VERSION 5.8 ;
BUSBITCHARS "[]" ;
DIVIDERCHAR "/" ;
UNITS
    DATABASE MICRONS 1000 ;
END UNITS

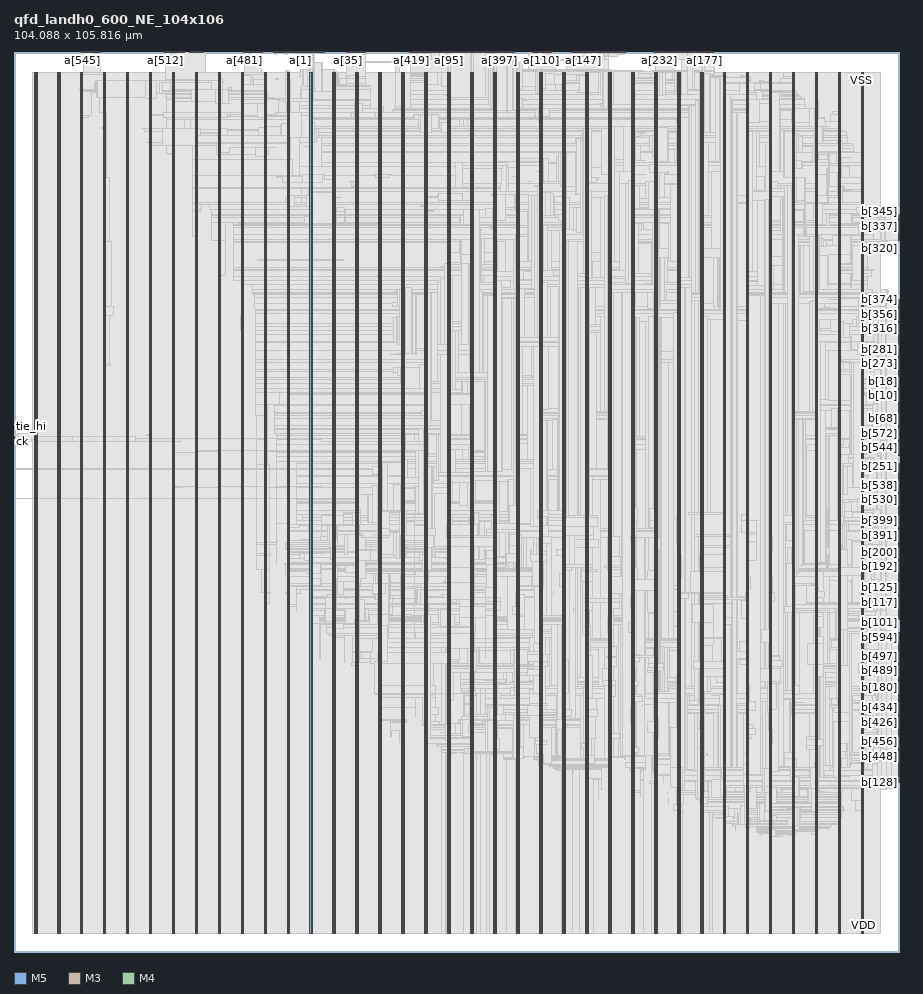
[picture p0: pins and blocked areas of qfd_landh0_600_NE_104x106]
MACRO qfd_landh0_600_NE_104x106
  FOREIGN qfd_landh0_600_NE_104x106 0 0 ;
  CLASS BLOCK ;
  SIZE 104.088 BY 105.816 ;
  PIN a[0]
    DIRECTION INPUT ;
    USE SIGNAL ;
    PORT
      LAYER M5 ;
        RECT  33.552 105.732 33.576 105.816 ;
    END
  END a[0]
  PIN a[100]
    DIRECTION INPUT ;
    USE SIGNAL ;
    PORT
      LAYER M3 ;
        RECT  61.236 105.779 61.254 105.816 ;
    END
  END a[100]
  PIN a[101]
    DIRECTION INPUT ;
    USE SIGNAL ;
    PORT
      LAYER M3 ;
        RECT  61.308 105.779 61.326 105.816 ;
    END
  END a[101]
  PIN a[102]
    DIRECTION INPUT ;
    USE SIGNAL ;
    PORT
      LAYER M3 ;
        RECT  61.38 105.779 61.398 105.816 ;
    END
  END a[102]
  PIN a[103]
    DIRECTION INPUT ;
    USE SIGNAL ;
    PORT
      LAYER M3 ;
        RECT  61.452 105.779 61.47 105.816 ;
    END
  END a[103]
  PIN a[104]
    DIRECTION INPUT ;
    USE SIGNAL ;
    PORT
      LAYER M3 ;
        RECT  61.524 105.779 61.542 105.816 ;
    END
  END a[104]
  PIN a[105]
    DIRECTION INPUT ;
    USE SIGNAL ;
    PORT
      LAYER M3 ;
        RECT  61.596 105.779 61.614 105.816 ;
    END
  END a[105]
  PIN a[106]
    DIRECTION INPUT ;
    USE SIGNAL ;
    PORT
      LAYER M3 ;
        RECT  61.668 105.779 61.686 105.816 ;
    END
  END a[106]
  PIN a[107]
    DIRECTION INPUT ;
    USE SIGNAL ;
    PORT
      LAYER M3 ;
        RECT  61.74 105.779 61.758 105.816 ;
    END
  END a[107]
  PIN a[108]
    DIRECTION INPUT ;
    USE SIGNAL ;
    PORT
      LAYER M3 ;
        RECT  61.812 105.779 61.83 105.816 ;
    END
  END a[108]
  PIN a[109]
    DIRECTION INPUT ;
    USE SIGNAL ;
    PORT
      LAYER M3 ;
        RECT  61.884 105.779 61.902 105.816 ;
    END
  END a[109]
  PIN a[10]
    DIRECTION INPUT ;
    USE SIGNAL ;
    PORT
      LAYER M5 ;
        RECT  34.512 105.732 34.536 105.816 ;
    END
  END a[10]
  PIN a[110]
    DIRECTION INPUT ;
    USE SIGNAL ;
    PORT
      LAYER M3 ;
        RECT  61.956 105.779 61.974 105.816 ;
    END
  END a[110]
  PIN a[111]
    DIRECTION INPUT ;
    USE SIGNAL ;
    PORT
      LAYER M3 ;
        RECT  62.028 105.779 62.046 105.816 ;
    END
  END a[111]
  PIN a[112]
    DIRECTION INPUT ;
    USE SIGNAL ;
    PORT
      LAYER M3 ;
        RECT  62.1 105.779 62.118 105.816 ;
    END
  END a[112]
  PIN a[113]
    DIRECTION INPUT ;
    USE SIGNAL ;
    PORT
      LAYER M3 ;
        RECT  62.172 105.779 62.19 105.816 ;
    END
  END a[113]
  PIN a[114]
    DIRECTION INPUT ;
    USE SIGNAL ;
    PORT
      LAYER M3 ;
        RECT  62.244 105.779 62.262 105.816 ;
    END
  END a[114]
  PIN a[115]
    DIRECTION INPUT ;
    USE SIGNAL ;
    PORT
      LAYER M3 ;
        RECT  62.316 105.779 62.334 105.816 ;
    END
  END a[115]
  PIN a[116]
    DIRECTION INPUT ;
    USE SIGNAL ;
    PORT
      LAYER M3 ;
        RECT  62.388 105.779 62.406 105.816 ;
    END
  END a[116]
  PIN a[117]
    DIRECTION INPUT ;
    USE SIGNAL ;
    PORT
      LAYER M3 ;
        RECT  62.46 105.779 62.478 105.816 ;
    END
  END a[117]
  PIN a[118]
    DIRECTION INPUT ;
    USE SIGNAL ;
    PORT
      LAYER M3 ;
        RECT  62.532 105.779 62.55 105.816 ;
    END
  END a[118]
  PIN a[119]
    DIRECTION INPUT ;
    USE SIGNAL ;
    PORT
      LAYER M3 ;
        RECT  62.604 105.779 62.622 105.816 ;
    END
  END a[119]
  PIN a[11]
    DIRECTION INPUT ;
    USE SIGNAL ;
    PORT
      LAYER M5 ;
        RECT  34.608 105.732 34.632 105.816 ;
    END
  END a[11]
  PIN a[120]
    DIRECTION INPUT ;
    USE SIGNAL ;
    PORT
      LAYER M3 ;
        RECT  62.676 105.779 62.694 105.816 ;
    END
  END a[120]
  PIN a[121]
    DIRECTION INPUT ;
    USE SIGNAL ;
    PORT
      LAYER M3 ;
        RECT  62.748 105.779 62.766 105.816 ;
    END
  END a[121]
  PIN a[122]
    DIRECTION INPUT ;
    USE SIGNAL ;
    PORT
      LAYER M3 ;
        RECT  62.82 105.779 62.838 105.816 ;
    END
  END a[122]
  PIN a[123]
    DIRECTION INPUT ;
    USE SIGNAL ;
    PORT
      LAYER M3 ;
        RECT  62.892 105.779 62.91 105.816 ;
    END
  END a[123]
  PIN a[124]
    DIRECTION INPUT ;
    USE SIGNAL ;
    PORT
      LAYER M3 ;
        RECT  62.964 105.779 62.982 105.816 ;
    END
  END a[124]
  PIN a[125]
    DIRECTION INPUT ;
    USE SIGNAL ;
    PORT
      LAYER M3 ;
        RECT  63.036 105.779 63.054 105.816 ;
    END
  END a[125]
  PIN a[126]
    DIRECTION INPUT ;
    USE SIGNAL ;
    PORT
      LAYER M3 ;
        RECT  63.108 105.779 63.126 105.816 ;
    END
  END a[126]
  PIN a[127]
    DIRECTION INPUT ;
    USE SIGNAL ;
    PORT
      LAYER M3 ;
        RECT  63.18 105.779 63.198 105.816 ;
    END
  END a[127]
  PIN a[128]
    DIRECTION INPUT ;
    USE SIGNAL ;
    PORT
      LAYER M3 ;
        RECT  65.556 105.779 65.574 105.816 ;
    END
  END a[128]
  PIN a[129]
    DIRECTION INPUT ;
    USE SIGNAL ;
    PORT
      LAYER M3 ;
        RECT  65.628 105.779 65.646 105.816 ;
    END
  END a[129]
  PIN a[12]
    DIRECTION INPUT ;
    USE SIGNAL ;
    PORT
      LAYER M5 ;
        RECT  34.704 105.732 34.728 105.816 ;
    END
  END a[12]
  PIN a[130]
    DIRECTION INPUT ;
    USE SIGNAL ;
    PORT
      LAYER M3 ;
        RECT  65.7 105.779 65.718 105.816 ;
    END
  END a[130]
  PIN a[131]
    DIRECTION INPUT ;
    USE SIGNAL ;
    PORT
      LAYER M3 ;
        RECT  65.772 105.779 65.79 105.816 ;
    END
  END a[131]
  PIN a[132]
    DIRECTION INPUT ;
    USE SIGNAL ;
    PORT
      LAYER M3 ;
        RECT  65.844 105.779 65.862 105.816 ;
    END
  END a[132]
  PIN a[133]
    DIRECTION INPUT ;
    USE SIGNAL ;
    PORT
      LAYER M3 ;
        RECT  65.916 105.779 65.934 105.816 ;
    END
  END a[133]
  PIN a[134]
    DIRECTION INPUT ;
    USE SIGNAL ;
    PORT
      LAYER M3 ;
        RECT  65.988 105.779 66.006 105.816 ;
    END
  END a[134]
  PIN a[135]
    DIRECTION INPUT ;
    USE SIGNAL ;
    PORT
      LAYER M3 ;
        RECT  66.06 105.779 66.078 105.816 ;
    END
  END a[135]
  PIN a[136]
    DIRECTION INPUT ;
    USE SIGNAL ;
    PORT
      LAYER M3 ;
        RECT  66.132 105.779 66.15 105.816 ;
    END
  END a[136]
  PIN a[137]
    DIRECTION INPUT ;
    USE SIGNAL ;
    PORT
      LAYER M3 ;
        RECT  66.204 105.779 66.222 105.816 ;
    END
  END a[137]
  PIN a[138]
    DIRECTION INPUT ;
    USE SIGNAL ;
    PORT
      LAYER M3 ;
        RECT  66.276 105.779 66.294 105.816 ;
    END
  END a[138]
  PIN a[139]
    DIRECTION INPUT ;
    USE SIGNAL ;
    PORT
      LAYER M3 ;
        RECT  66.348 105.779 66.366 105.816 ;
    END
  END a[139]
  PIN a[13]
    DIRECTION INPUT ;
    USE SIGNAL ;
    PORT
      LAYER M5 ;
        RECT  34.8 105.732 34.824 105.816 ;
    END
  END a[13]
  PIN a[140]
    DIRECTION INPUT ;
    USE SIGNAL ;
    PORT
      LAYER M3 ;
        RECT  66.42 105.779 66.438 105.816 ;
    END
  END a[140]
  PIN a[141]
    DIRECTION INPUT ;
    USE SIGNAL ;
    PORT
      LAYER M3 ;
        RECT  66.492 105.779 66.51 105.816 ;
    END
  END a[141]
  PIN a[142]
    DIRECTION INPUT ;
    USE SIGNAL ;
    PORT
      LAYER M3 ;
        RECT  66.564 105.779 66.582 105.816 ;
    END
  END a[142]
  PIN a[143]
    DIRECTION INPUT ;
    USE SIGNAL ;
    PORT
      LAYER M3 ;
        RECT  66.636 105.779 66.654 105.816 ;
    END
  END a[143]
  PIN a[144]
    DIRECTION INPUT ;
    USE SIGNAL ;
    PORT
      LAYER M3 ;
        RECT  66.708 105.779 66.726 105.816 ;
    END
  END a[144]
  PIN a[145]
    DIRECTION INPUT ;
    USE SIGNAL ;
    PORT
      LAYER M3 ;
        RECT  66.78 105.779 66.798 105.816 ;
    END
  END a[145]
  PIN a[146]
    DIRECTION INPUT ;
    USE SIGNAL ;
    PORT
      LAYER M3 ;
        RECT  66.852 105.779 66.87 105.816 ;
    END
  END a[146]
  PIN a[147]
    DIRECTION INPUT ;
    USE SIGNAL ;
    PORT
      LAYER M3 ;
        RECT  66.924 105.779 66.942 105.816 ;
    END
  END a[147]
  PIN a[148]
    DIRECTION INPUT ;
    USE SIGNAL ;
    PORT
      LAYER M3 ;
        RECT  66.996 105.779 67.014 105.816 ;
    END
  END a[148]
  PIN a[149]
    DIRECTION INPUT ;
    USE SIGNAL ;
    PORT
      LAYER M3 ;
        RECT  67.068 105.779 67.086 105.816 ;
    END
  END a[149]
  PIN a[14]
    DIRECTION INPUT ;
    USE SIGNAL ;
    PORT
      LAYER M5 ;
        RECT  34.896 105.732 34.92 105.816 ;
    END
  END a[14]
  PIN a[150]
    DIRECTION INPUT ;
    USE SIGNAL ;
    PORT
      LAYER M3 ;
        RECT  67.14 105.779 67.158 105.816 ;
    END
  END a[150]
  PIN a[151]
    DIRECTION INPUT ;
    USE SIGNAL ;
    PORT
      LAYER M3 ;
        RECT  67.212 105.779 67.23 105.816 ;
    END
  END a[151]
  PIN a[152]
    DIRECTION INPUT ;
    USE SIGNAL ;
    PORT
      LAYER M3 ;
        RECT  67.284 105.779 67.302 105.816 ;
    END
  END a[152]
  PIN a[153]
    DIRECTION INPUT ;
    USE SIGNAL ;
    PORT
      LAYER M3 ;
        RECT  67.356 105.779 67.374 105.816 ;
    END
  END a[153]
  PIN a[154]
    DIRECTION INPUT ;
    USE SIGNAL ;
    PORT
      LAYER M3 ;
        RECT  67.428 105.779 67.446 105.816 ;
    END
  END a[154]
  PIN a[155]
    DIRECTION INPUT ;
    USE SIGNAL ;
    PORT
      LAYER M3 ;
        RECT  67.5 105.779 67.518 105.816 ;
    END
  END a[155]
  PIN a[156]
    DIRECTION INPUT ;
    USE SIGNAL ;
    PORT
      LAYER M3 ;
        RECT  67.572 105.779 67.59 105.816 ;
    END
  END a[156]
  PIN a[157]
    DIRECTION INPUT ;
    USE SIGNAL ;
    PORT
      LAYER M3 ;
        RECT  67.644 105.779 67.662 105.816 ;
    END
  END a[157]
  PIN a[158]
    DIRECTION INPUT ;
    USE SIGNAL ;
    PORT
      LAYER M3 ;
        RECT  67.716 105.779 67.734 105.816 ;
    END
  END a[158]
  PIN a[159]
    DIRECTION INPUT ;
    USE SIGNAL ;
    PORT
      LAYER M3 ;
        RECT  67.788 105.779 67.806 105.816 ;
    END
  END a[159]
  PIN a[15]
    DIRECTION INPUT ;
    USE SIGNAL ;
    PORT
      LAYER M5 ;
        RECT  34.992 105.732 35.016 105.816 ;
    END
  END a[15]
  PIN a[160]
    DIRECTION INPUT ;
    USE SIGNAL ;
    PORT
      LAYER M3 ;
        RECT  79.956 105.779 79.974 105.816 ;
    END
  END a[160]
  PIN a[161]
    DIRECTION INPUT ;
    USE SIGNAL ;
    PORT
      LAYER M3 ;
        RECT  80.028 105.779 80.046 105.816 ;
    END
  END a[161]
  PIN a[162]
    DIRECTION INPUT ;
    USE SIGNAL ;
    PORT
      LAYER M3 ;
        RECT  80.1 105.779 80.118 105.816 ;
    END
  END a[162]
  PIN a[163]
    DIRECTION INPUT ;
    USE SIGNAL ;
    PORT
      LAYER M3 ;
        RECT  80.172 105.779 80.19 105.816 ;
    END
  END a[163]
  PIN a[164]
    DIRECTION INPUT ;
    USE SIGNAL ;
    PORT
      LAYER M3 ;
        RECT  80.244 105.779 80.262 105.816 ;
    END
  END a[164]
  PIN a[165]
    DIRECTION INPUT ;
    USE SIGNAL ;
    PORT
      LAYER M3 ;
        RECT  80.316 105.779 80.334 105.816 ;
    END
  END a[165]
  PIN a[166]
    DIRECTION INPUT ;
    USE SIGNAL ;
    PORT
      LAYER M3 ;
        RECT  80.388 105.779 80.406 105.816 ;
    END
  END a[166]
  PIN a[167]
    DIRECTION INPUT ;
    USE SIGNAL ;
    PORT
      LAYER M3 ;
        RECT  80.46 105.779 80.478 105.816 ;
    END
  END a[167]
  PIN a[168]
    DIRECTION INPUT ;
    USE SIGNAL ;
    PORT
      LAYER M3 ;
        RECT  80.532 105.779 80.55 105.816 ;
    END
  END a[168]
  PIN a[169]
    DIRECTION INPUT ;
    USE SIGNAL ;
    PORT
      LAYER M3 ;
        RECT  80.604 105.779 80.622 105.816 ;
    END
  END a[169]
  PIN a[16]
    DIRECTION INPUT ;
    USE SIGNAL ;
    PORT
      LAYER M5 ;
        RECT  35.088 105.732 35.112 105.816 ;
    END
  END a[16]
  PIN a[170]
    DIRECTION INPUT ;
    USE SIGNAL ;
    PORT
      LAYER M3 ;
        RECT  80.676 105.779 80.694 105.816 ;
    END
  END a[170]
  PIN a[171]
    DIRECTION INPUT ;
    USE SIGNAL ;
    PORT
      LAYER M3 ;
        RECT  80.748 105.779 80.766 105.816 ;
    END
  END a[171]
  PIN a[172]
    DIRECTION INPUT ;
    USE SIGNAL ;
    PORT
      LAYER M3 ;
        RECT  80.82 105.779 80.838 105.816 ;
    END
  END a[172]
  PIN a[173]
    DIRECTION INPUT ;
    USE SIGNAL ;
    PORT
      LAYER M3 ;
        RECT  80.892 105.779 80.91 105.816 ;
    END
  END a[173]
  PIN a[174]
    DIRECTION INPUT ;
    USE SIGNAL ;
    PORT
      LAYER M3 ;
        RECT  80.964 105.779 80.982 105.816 ;
    END
  END a[174]
  PIN a[175]
    DIRECTION INPUT ;
    USE SIGNAL ;
    PORT
      LAYER M3 ;
        RECT  81.036 105.779 81.054 105.816 ;
    END
  END a[175]
  PIN a[176]
    DIRECTION INPUT ;
    USE SIGNAL ;
    PORT
      LAYER M3 ;
        RECT  81.108 105.779 81.126 105.816 ;
    END
  END a[176]
  PIN a[177]
    DIRECTION INPUT ;
    USE SIGNAL ;
    PORT
      LAYER M3 ;
        RECT  81.18 105.779 81.198 105.816 ;
    END
  END a[177]
  PIN a[178]
    DIRECTION INPUT ;
    USE SIGNAL ;
    PORT
      LAYER M3 ;
        RECT  81.252 105.779 81.27 105.816 ;
    END
  END a[178]
  PIN a[179]
    DIRECTION INPUT ;
    USE SIGNAL ;
    PORT
      LAYER M3 ;
        RECT  81.324 105.779 81.342 105.816 ;
    END
  END a[179]
  PIN a[17]
    DIRECTION INPUT ;
    USE SIGNAL ;
    PORT
      LAYER M5 ;
        RECT  35.184 105.732 35.208 105.816 ;
    END
  END a[17]
  PIN a[180]
    DIRECTION INPUT ;
    USE SIGNAL ;
    PORT
      LAYER M3 ;
        RECT  81.396 105.779 81.414 105.816 ;
    END
  END a[180]
  PIN a[181]
    DIRECTION INPUT ;
    USE SIGNAL ;
    PORT
      LAYER M3 ;
        RECT  81.468 105.779 81.486 105.816 ;
    END
  END a[181]
  PIN a[182]
    DIRECTION INPUT ;
    USE SIGNAL ;
    PORT
      LAYER M3 ;
        RECT  81.54 105.779 81.558 105.816 ;
    END
  END a[182]
  PIN a[183]
    DIRECTION INPUT ;
    USE SIGNAL ;
    PORT
      LAYER M3 ;
        RECT  81.612 105.779 81.63 105.816 ;
    END
  END a[183]
  PIN a[184]
    DIRECTION INPUT ;
    USE SIGNAL ;
    PORT
      LAYER M3 ;
        RECT  81.684 105.779 81.702 105.816 ;
    END
  END a[184]
  PIN a[185]
    DIRECTION INPUT ;
    USE SIGNAL ;
    PORT
      LAYER M3 ;
        RECT  81.756 105.779 81.774 105.816 ;
    END
  END a[185]
  PIN a[186]
    DIRECTION INPUT ;
    USE SIGNAL ;
    PORT
      LAYER M3 ;
        RECT  81.828 105.779 81.846 105.816 ;
    END
  END a[186]
  PIN a[187]
    DIRECTION INPUT ;
    USE SIGNAL ;
    PORT
      LAYER M3 ;
        RECT  81.9 105.779 81.918 105.816 ;
    END
  END a[187]
  PIN a[188]
    DIRECTION INPUT ;
    USE SIGNAL ;
    PORT
      LAYER M3 ;
        RECT  81.972 105.779 81.99 105.816 ;
    END
  END a[188]
  PIN a[189]
    DIRECTION INPUT ;
    USE SIGNAL ;
    PORT
      LAYER M3 ;
        RECT  82.044 105.779 82.062 105.816 ;
    END
  END a[189]
  PIN a[18]
    DIRECTION INPUT ;
    USE SIGNAL ;
    PORT
      LAYER M5 ;
        RECT  35.28 105.732 35.304 105.816 ;
    END
  END a[18]
  PIN a[190]
    DIRECTION INPUT ;
    USE SIGNAL ;
    PORT
      LAYER M3 ;
        RECT  82.116 105.779 82.134 105.816 ;
    END
  END a[190]
  PIN a[191]
    DIRECTION INPUT ;
    USE SIGNAL ;
    PORT
      LAYER M3 ;
        RECT  82.188 105.779 82.206 105.816 ;
    END
  END a[191]
  PIN a[192]
    DIRECTION INPUT ;
    USE SIGNAL ;
    PORT
      LAYER M5 ;
        RECT  68.88 105.732 68.904 105.816 ;
    END
  END a[192]
  PIN a[193]
    DIRECTION INPUT ;
    USE SIGNAL ;
    PORT
      LAYER M5 ;
        RECT  68.976 105.732 69 105.816 ;
    END
  END a[193]
  PIN a[194]
    DIRECTION INPUT ;
    USE SIGNAL ;
    PORT
      LAYER M5 ;
        RECT  69.072 105.732 69.096 105.816 ;
    END
  END a[194]
  PIN a[195]
    DIRECTION INPUT ;
    USE SIGNAL ;
    PORT
      LAYER M5 ;
        RECT  69.168 105.732 69.192 105.816 ;
    END
  END a[195]
  PIN a[196]
    DIRECTION INPUT ;
    USE SIGNAL ;
    PORT
      LAYER M5 ;
        RECT  69.264 105.732 69.288 105.816 ;
    END
  END a[196]
  PIN a[197]
    DIRECTION INPUT ;
    USE SIGNAL ;
    PORT
      LAYER M5 ;
        RECT  69.36 105.732 69.384 105.816 ;
    END
  END a[197]
  PIN a[198]
    DIRECTION INPUT ;
    USE SIGNAL ;
    PORT
      LAYER M5 ;
        RECT  69.456 105.732 69.48 105.816 ;
    END
  END a[198]
  PIN a[199]
    DIRECTION INPUT ;
    USE SIGNAL ;
    PORT
      LAYER M5 ;
        RECT  69.552 105.732 69.576 105.816 ;
    END
  END a[199]
  PIN a[19]
    DIRECTION INPUT ;
    USE SIGNAL ;
    PORT
      LAYER M5 ;
        RECT  35.376 105.732 35.4 105.816 ;
    END
  END a[19]
  PIN a[1]
    DIRECTION INPUT ;
    USE SIGNAL ;
    PORT
      LAYER M5 ;
        RECT  33.648 105.732 33.672 105.816 ;
    END
  END a[1]
  PIN a[200]
    DIRECTION INPUT ;
    USE SIGNAL ;
    PORT
      LAYER M5 ;
        RECT  69.648 105.732 69.672 105.816 ;
    END
  END a[200]
  PIN a[201]
    DIRECTION INPUT ;
    USE SIGNAL ;
    PORT
      LAYER M5 ;
        RECT  69.744 105.732 69.768 105.816 ;
    END
  END a[201]
  PIN a[202]
    DIRECTION INPUT ;
    USE SIGNAL ;
    PORT
      LAYER M5 ;
        RECT  69.84 105.732 69.864 105.816 ;
    END
  END a[202]
  PIN a[203]
    DIRECTION INPUT ;
    USE SIGNAL ;
    PORT
      LAYER M5 ;
        RECT  69.936 105.732 69.96 105.816 ;
    END
  END a[203]
  PIN a[204]
    DIRECTION INPUT ;
    USE SIGNAL ;
    PORT
      LAYER M5 ;
        RECT  70.032 105.732 70.056 105.816 ;
    END
  END a[204]
  PIN a[205]
    DIRECTION INPUT ;
    USE SIGNAL ;
    PORT
      LAYER M5 ;
        RECT  70.128 105.732 70.152 105.816 ;
    END
  END a[205]
  PIN a[206]
    DIRECTION INPUT ;
    USE SIGNAL ;
    PORT
      LAYER M5 ;
        RECT  70.224 105.732 70.248 105.816 ;
    END
  END a[206]
  PIN a[207]
    DIRECTION INPUT ;
    USE SIGNAL ;
    PORT
      LAYER M5 ;
        RECT  70.32 105.732 70.344 105.816 ;
    END
  END a[207]
  PIN a[208]
    DIRECTION INPUT ;
    USE SIGNAL ;
    PORT
      LAYER M5 ;
        RECT  70.416 105.732 70.44 105.816 ;
    END
  END a[208]
  PIN a[209]
    DIRECTION INPUT ;
    USE SIGNAL ;
    PORT
      LAYER M5 ;
        RECT  70.512 105.732 70.536 105.816 ;
    END
  END a[209]
  PIN a[20]
    DIRECTION INPUT ;
    USE SIGNAL ;
    PORT
      LAYER M5 ;
        RECT  35.472 105.732 35.496 105.816 ;
    END
  END a[20]
  PIN a[210]
    DIRECTION INPUT ;
    USE SIGNAL ;
    PORT
      LAYER M5 ;
        RECT  70.608 105.732 70.632 105.816 ;
    END
  END a[210]
  PIN a[211]
    DIRECTION INPUT ;
    USE SIGNAL ;
    PORT
      LAYER M5 ;
        RECT  70.704 105.732 70.728 105.816 ;
    END
  END a[211]
  PIN a[212]
    DIRECTION INPUT ;
    USE SIGNAL ;
    PORT
      LAYER M5 ;
        RECT  70.8 105.732 70.824 105.816 ;
    END
  END a[212]
  PIN a[213]
    DIRECTION INPUT ;
    USE SIGNAL ;
    PORT
      LAYER M5 ;
        RECT  70.896 105.732 70.92 105.816 ;
    END
  END a[213]
  PIN a[214]
    DIRECTION INPUT ;
    USE SIGNAL ;
    PORT
      LAYER M5 ;
        RECT  70.992 105.732 71.016 105.816 ;
    END
  END a[214]
  PIN a[215]
    DIRECTION INPUT ;
    USE SIGNAL ;
    PORT
      LAYER M5 ;
        RECT  71.088 105.732 71.112 105.816 ;
    END
  END a[215]
  PIN a[216]
    DIRECTION INPUT ;
    USE SIGNAL ;
    PORT
      LAYER M5 ;
        RECT  71.184 105.732 71.208 105.816 ;
    END
  END a[216]
  PIN a[217]
    DIRECTION INPUT ;
    USE SIGNAL ;
    PORT
      LAYER M5 ;
        RECT  71.28 105.732 71.304 105.816 ;
    END
  END a[217]
  PIN a[218]
    DIRECTION INPUT ;
    USE SIGNAL ;
    PORT
      LAYER M5 ;
        RECT  71.376 105.732 71.4 105.816 ;
    END
  END a[218]
  PIN a[219]
    DIRECTION INPUT ;
    USE SIGNAL ;
    PORT
      LAYER M5 ;
        RECT  71.472 105.732 71.496 105.816 ;
    END
  END a[219]
  PIN a[21]
    DIRECTION INPUT ;
    USE SIGNAL ;
    PORT
      LAYER M5 ;
        RECT  35.568 105.732 35.592 105.816 ;
    END
  END a[21]
  PIN a[220]
    DIRECTION INPUT ;
    USE SIGNAL ;
    PORT
      LAYER M5 ;
        RECT  71.568 105.732 71.592 105.816 ;
    END
  END a[220]
  PIN a[221]
    DIRECTION INPUT ;
    USE SIGNAL ;
    PORT
      LAYER M5 ;
        RECT  71.664 105.732 71.688 105.816 ;
    END
  END a[221]
  PIN a[222]
    DIRECTION INPUT ;
    USE SIGNAL ;
    PORT
      LAYER M5 ;
        RECT  71.76 105.732 71.784 105.816 ;
    END
  END a[222]
  PIN a[223]
    DIRECTION INPUT ;
    USE SIGNAL ;
    PORT
      LAYER M5 ;
        RECT  71.856 105.732 71.88 105.816 ;
    END
  END a[223]
  PIN a[224]
    DIRECTION INPUT ;
    USE SIGNAL ;
    PORT
      LAYER M3 ;
        RECT  75.348 105.779 75.366 105.816 ;
    END
  END a[224]
  PIN a[225]
    DIRECTION INPUT ;
    USE SIGNAL ;
    PORT
      LAYER M3 ;
        RECT  75.42 105.779 75.438 105.816 ;
    END
  END a[225]
  PIN a[226]
    DIRECTION INPUT ;
    USE SIGNAL ;
    PORT
      LAYER M3 ;
        RECT  75.492 105.779 75.51 105.816 ;
    END
  END a[226]
  PIN a[227]
    DIRECTION INPUT ;
    USE SIGNAL ;
    PORT
      LAYER M3 ;
        RECT  75.564 105.779 75.582 105.816 ;
    END
  END a[227]
  PIN a[228]
    DIRECTION INPUT ;
    USE SIGNAL ;
    PORT
      LAYER M3 ;
        RECT  75.636 105.779 75.654 105.816 ;
    END
  END a[228]
  PIN a[229]
    DIRECTION INPUT ;
    USE SIGNAL ;
    PORT
      LAYER M3 ;
        RECT  75.708 105.779 75.726 105.816 ;
    END
  END a[229]
  PIN a[22]
    DIRECTION INPUT ;
    USE SIGNAL ;
    PORT
      LAYER M5 ;
        RECT  35.664 105.732 35.688 105.816 ;
    END
  END a[22]
  PIN a[230]
    DIRECTION INPUT ;
    USE SIGNAL ;
    PORT
      LAYER M3 ;
        RECT  75.78 105.779 75.798 105.816 ;
    END
  END a[230]
  PIN a[231]
    DIRECTION INPUT ;
    USE SIGNAL ;
    PORT
      LAYER M3 ;
        RECT  75.852 105.779 75.87 105.816 ;
    END
  END a[231]
  PIN a[232]
    DIRECTION INPUT ;
    USE SIGNAL ;
    PORT
      LAYER M3 ;
        RECT  75.924 105.779 75.942 105.816 ;
    END
  END a[232]
  PIN a[233]
    DIRECTION INPUT ;
    USE SIGNAL ;
    PORT
      LAYER M3 ;
        RECT  75.996 105.779 76.014 105.816 ;
    END
  END a[233]
  PIN a[234]
    DIRECTION INPUT ;
    USE SIGNAL ;
    PORT
      LAYER M3 ;
        RECT  76.068 105.779 76.086 105.816 ;
    END
  END a[234]
  PIN a[235]
    DIRECTION INPUT ;
    USE SIGNAL ;
    PORT
      LAYER M3 ;
        RECT  76.14 105.779 76.158 105.816 ;
    END
  END a[235]
  PIN a[236]
    DIRECTION INPUT ;
    USE SIGNAL ;
    PORT
      LAYER M3 ;
        RECT  76.212 105.779 76.23 105.816 ;
    END
  END a[236]
  PIN a[237]
    DIRECTION INPUT ;
    USE SIGNAL ;
    PORT
      LAYER M3 ;
        RECT  76.284 105.779 76.302 105.816 ;
    END
  END a[237]
  PIN a[238]
    DIRECTION INPUT ;
    USE SIGNAL ;
    PORT
      LAYER M3 ;
        RECT  76.356 105.779 76.374 105.816 ;
    END
  END a[238]
  PIN a[239]
    DIRECTION INPUT ;
    USE SIGNAL ;
    PORT
      LAYER M3 ;
        RECT  76.428 105.779 76.446 105.816 ;
    END
  END a[239]
  PIN a[23]
    DIRECTION INPUT ;
    USE SIGNAL ;
    PORT
      LAYER M5 ;
        RECT  35.76 105.732 35.784 105.816 ;
    END
  END a[23]
  PIN a[240]
    DIRECTION INPUT ;
    USE SIGNAL ;
    PORT
      LAYER M3 ;
        RECT  76.5 105.779 76.518 105.816 ;
    END
  END a[240]
  PIN a[241]
    DIRECTION INPUT ;
    USE SIGNAL ;
    PORT
      LAYER M3 ;
        RECT  76.572 105.779 76.59 105.816 ;
    END
  END a[241]
  PIN a[242]
    DIRECTION INPUT ;
    USE SIGNAL ;
    PORT
      LAYER M3 ;
        RECT  76.644 105.779 76.662 105.816 ;
    END
  END a[242]
  PIN a[243]
    DIRECTION INPUT ;
    USE SIGNAL ;
    PORT
      LAYER M3 ;
        RECT  76.716 105.779 76.734 105.816 ;
    END
  END a[243]
  PIN a[244]
    DIRECTION INPUT ;
    USE SIGNAL ;
    PORT
      LAYER M3 ;
        RECT  76.788 105.779 76.806 105.816 ;
    END
  END a[244]
  PIN a[245]
    DIRECTION INPUT ;
    USE SIGNAL ;
    PORT
      LAYER M3 ;
        RECT  76.86 105.779 76.878 105.816 ;
    END
  END a[245]
  PIN a[246]
    DIRECTION INPUT ;
    USE SIGNAL ;
    PORT
      LAYER M3 ;
        RECT  76.932 105.779 76.95 105.816 ;
    END
  END a[246]
  PIN a[247]
    DIRECTION INPUT ;
    USE SIGNAL ;
    PORT
      LAYER M3 ;
        RECT  77.004 105.779 77.022 105.816 ;
    END
  END a[247]
  PIN a[248]
    DIRECTION INPUT ;
    USE SIGNAL ;
    PORT
      LAYER M3 ;
        RECT  77.076 105.779 77.094 105.816 ;
    END
  END a[248]
  PIN a[249]
    DIRECTION INPUT ;
    USE SIGNAL ;
    PORT
      LAYER M3 ;
        RECT  77.148 105.779 77.166 105.816 ;
    END
  END a[249]
  PIN a[24]
    DIRECTION INPUT ;
    USE SIGNAL ;
    PORT
      LAYER M5 ;
        RECT  35.856 105.732 35.88 105.816 ;
    END
  END a[24]
  PIN a[250]
    DIRECTION INPUT ;
    USE SIGNAL ;
    PORT
      LAYER M3 ;
        RECT  77.22 105.779 77.238 105.816 ;
    END
  END a[250]
  PIN a[251]
    DIRECTION INPUT ;
    USE SIGNAL ;
    PORT
      LAYER M3 ;
        RECT  77.292 105.779 77.31 105.816 ;
    END
  END a[251]
  PIN a[252]
    DIRECTION INPUT ;
    USE SIGNAL ;
    PORT
      LAYER M3 ;
        RECT  77.364 105.779 77.382 105.816 ;
    END
  END a[252]
  PIN a[253]
    DIRECTION INPUT ;
    USE SIGNAL ;
    PORT
      LAYER M3 ;
        RECT  77.436 105.779 77.454 105.816 ;
    END
  END a[253]
  PIN a[254]
    DIRECTION INPUT ;
    USE SIGNAL ;
    PORT
      LAYER M3 ;
        RECT  77.508 105.779 77.526 105.816 ;
    END
  END a[254]
  PIN a[255]
    DIRECTION INPUT ;
    USE SIGNAL ;
    PORT
      LAYER M3 ;
        RECT  77.58 105.779 77.598 105.816 ;
    END
  END a[255]
  PIN a[256]
    DIRECTION INPUT ;
    USE SIGNAL ;
    PORT
      LAYER M3 ;
        RECT  77.652 105.779 77.67 105.816 ;
    END
  END a[256]
  PIN a[257]
    DIRECTION INPUT ;
    USE SIGNAL ;
    PORT
      LAYER M3 ;
        RECT  77.724 105.779 77.742 105.816 ;
    END
  END a[257]
  PIN a[258]
    DIRECTION INPUT ;
    USE SIGNAL ;
    PORT
      LAYER M3 ;
        RECT  77.796 105.779 77.814 105.816 ;
    END
  END a[258]
  PIN a[259]
    DIRECTION INPUT ;
    USE SIGNAL ;
    PORT
      LAYER M3 ;
        RECT  77.868 105.779 77.886 105.816 ;
    END
  END a[259]
  PIN a[25]
    DIRECTION INPUT ;
    USE SIGNAL ;
    PORT
      LAYER M5 ;
        RECT  35.952 105.732 35.976 105.816 ;
    END
  END a[25]
  PIN a[260]
    DIRECTION INPUT ;
    USE SIGNAL ;
    PORT
      LAYER M3 ;
        RECT  77.94 105.779 77.958 105.816 ;
    END
  END a[260]
  PIN a[261]
    DIRECTION INPUT ;
    USE SIGNAL ;
    PORT
      LAYER M3 ;
        RECT  78.012 105.779 78.03 105.816 ;
    END
  END a[261]
  PIN a[262]
    DIRECTION INPUT ;
    USE SIGNAL ;
    PORT
      LAYER M3 ;
        RECT  78.084 105.779 78.102 105.816 ;
    END
  END a[262]
  PIN a[263]
    DIRECTION INPUT ;
    USE SIGNAL ;
    PORT
      LAYER M3 ;
        RECT  78.156 105.779 78.174 105.816 ;
    END
  END a[263]
  PIN a[264]
    DIRECTION INPUT ;
    USE SIGNAL ;
    PORT
      LAYER M3 ;
        RECT  78.228 105.779 78.246 105.816 ;
    END
  END a[264]
  PIN a[265]
    DIRECTION INPUT ;
    USE SIGNAL ;
    PORT
      LAYER M3 ;
        RECT  78.3 105.779 78.318 105.816 ;
    END
  END a[265]
  PIN a[266]
    DIRECTION INPUT ;
    USE SIGNAL ;
    PORT
      LAYER M3 ;
        RECT  78.372 105.779 78.39 105.816 ;
    END
  END a[266]
  PIN a[267]
    DIRECTION INPUT ;
    USE SIGNAL ;
    PORT
      LAYER M3 ;
        RECT  78.444 105.779 78.462 105.816 ;
    END
  END a[267]
  PIN a[268]
    DIRECTION INPUT ;
    USE SIGNAL ;
    PORT
      LAYER M3 ;
        RECT  78.516 105.779 78.534 105.816 ;
    END
  END a[268]
  PIN a[269]
    DIRECTION INPUT ;
    USE SIGNAL ;
    PORT
      LAYER M3 ;
        RECT  78.588 105.779 78.606 105.816 ;
    END
  END a[269]
  PIN a[26]
    DIRECTION INPUT ;
    USE SIGNAL ;
    PORT
      LAYER M5 ;
        RECT  36.048 105.732 36.072 105.816 ;
    END
  END a[26]
  PIN a[270]
    DIRECTION INPUT ;
    USE SIGNAL ;
    PORT
      LAYER M3 ;
        RECT  78.66 105.779 78.678 105.816 ;
    END
  END a[270]
  PIN a[271]
    DIRECTION INPUT ;
    USE SIGNAL ;
    PORT
      LAYER M3 ;
        RECT  78.732 105.779 78.75 105.816 ;
    END
  END a[271]
  PIN a[272]
    DIRECTION INPUT ;
    USE SIGNAL ;
    PORT
      LAYER M3 ;
        RECT  78.804 105.779 78.822 105.816 ;
    END
  END a[272]
  PIN a[273]
    DIRECTION INPUT ;
    USE SIGNAL ;
    PORT
      LAYER M3 ;
        RECT  78.876 105.779 78.894 105.816 ;
    END
  END a[273]
  PIN a[274]
    DIRECTION INPUT ;
    USE SIGNAL ;
    PORT
      LAYER M3 ;
        RECT  78.948 105.779 78.966 105.816 ;
    END
  END a[274]
  PIN a[275]
    DIRECTION INPUT ;
    USE SIGNAL ;
    PORT
      LAYER M3 ;
        RECT  79.02 105.779 79.038 105.816 ;
    END
  END a[275]
  PIN a[276]
    DIRECTION INPUT ;
    USE SIGNAL ;
    PORT
      LAYER M3 ;
        RECT  79.092 105.779 79.11 105.816 ;
    END
  END a[276]
  PIN a[277]
    DIRECTION INPUT ;
    USE SIGNAL ;
    PORT
      LAYER M3 ;
        RECT  79.164 105.779 79.182 105.816 ;
    END
  END a[277]
  PIN a[278]
    DIRECTION INPUT ;
    USE SIGNAL ;
    PORT
      LAYER M3 ;
        RECT  79.236 105.779 79.254 105.816 ;
    END
  END a[278]
  PIN a[279]
    DIRECTION INPUT ;
    USE SIGNAL ;
    PORT
      LAYER M3 ;
        RECT  79.308 105.779 79.326 105.816 ;
    END
  END a[279]
  PIN a[27]
    DIRECTION INPUT ;
    USE SIGNAL ;
    PORT
      LAYER M5 ;
        RECT  36.144 105.732 36.168 105.816 ;
    END
  END a[27]
  PIN a[280]
    DIRECTION INPUT ;
    USE SIGNAL ;
    PORT
      LAYER M3 ;
        RECT  79.38 105.779 79.398 105.816 ;
    END
  END a[280]
  PIN a[281]
    DIRECTION INPUT ;
    USE SIGNAL ;
    PORT
      LAYER M3 ;
        RECT  79.452 105.779 79.47 105.816 ;
    END
  END a[281]
  PIN a[282]
    DIRECTION INPUT ;
    USE SIGNAL ;
    PORT
      LAYER M3 ;
        RECT  79.524 105.779 79.542 105.816 ;
    END
  END a[282]
  PIN a[283]
    DIRECTION INPUT ;
    USE SIGNAL ;
    PORT
      LAYER M3 ;
        RECT  79.596 105.779 79.614 105.816 ;
    END
  END a[283]
  PIN a[284]
    DIRECTION INPUT ;
    USE SIGNAL ;
    PORT
      LAYER M3 ;
        RECT  79.668 105.779 79.686 105.816 ;
    END
  END a[284]
  PIN a[285]
    DIRECTION INPUT ;
    USE SIGNAL ;
    PORT
      LAYER M3 ;
        RECT  79.74 105.779 79.758 105.816 ;
    END
  END a[285]
  PIN a[286]
    DIRECTION INPUT ;
    USE SIGNAL ;
    PORT
      LAYER M3 ;
        RECT  79.812 105.779 79.83 105.816 ;
    END
  END a[286]
  PIN a[287]
    DIRECTION INPUT ;
    USE SIGNAL ;
    PORT
      LAYER M3 ;
        RECT  79.884 105.779 79.902 105.816 ;
    END
  END a[287]
  PIN a[288]
    DIRECTION INPUT ;
    USE SIGNAL ;
    PORT
      LAYER M3 ;
        RECT  67.86 105.779 67.878 105.816 ;
    END
  END a[288]
  PIN a[289]
    DIRECTION INPUT ;
    USE SIGNAL ;
    PORT
      LAYER M3 ;
        RECT  67.932 105.779 67.95 105.816 ;
    END
  END a[289]
  PIN a[28]
    DIRECTION INPUT ;
    USE SIGNAL ;
    PORT
      LAYER M5 ;
        RECT  36.24 105.732 36.264 105.816 ;
    END
  END a[28]
  PIN a[290]
    DIRECTION INPUT ;
    USE SIGNAL ;
    PORT
      LAYER M3 ;
        RECT  68.004 105.779 68.022 105.816 ;
    END
  END a[290]
  PIN a[291]
    DIRECTION INPUT ;
    USE SIGNAL ;
    PORT
      LAYER M3 ;
        RECT  68.076 105.779 68.094 105.816 ;
    END
  END a[291]
  PIN a[292]
    DIRECTION INPUT ;
    USE SIGNAL ;
    PORT
      LAYER M3 ;
        RECT  68.148 105.779 68.166 105.816 ;
    END
  END a[292]
  PIN a[293]
    DIRECTION INPUT ;
    USE SIGNAL ;
    PORT
      LAYER M3 ;
        RECT  68.22 105.779 68.238 105.816 ;
    END
  END a[293]
  PIN a[294]
    DIRECTION INPUT ;
    USE SIGNAL ;
    PORT
      LAYER M3 ;
        RECT  68.292 105.779 68.31 105.816 ;
    END
  END a[294]
  PIN a[295]
    DIRECTION INPUT ;
    USE SIGNAL ;
    PORT
      LAYER M3 ;
        RECT  68.364 105.779 68.382 105.816 ;
    END
  END a[295]
  PIN a[296]
    DIRECTION INPUT ;
    USE SIGNAL ;
    PORT
      LAYER M3 ;
        RECT  68.436 105.779 68.454 105.816 ;
    END
  END a[296]
  PIN a[297]
    DIRECTION INPUT ;
    USE SIGNAL ;
    PORT
      LAYER M3 ;
        RECT  68.508 105.779 68.526 105.816 ;
    END
  END a[297]
  PIN a[298]
    DIRECTION INPUT ;
    USE SIGNAL ;
    PORT
      LAYER M3 ;
        RECT  68.58 105.779 68.598 105.816 ;
    END
  END a[298]
  PIN a[299]
    DIRECTION INPUT ;
    USE SIGNAL ;
    PORT
      LAYER M3 ;
        RECT  68.652 105.779 68.67 105.816 ;
    END
  END a[299]
  PIN a[29]
    DIRECTION INPUT ;
    USE SIGNAL ;
    PORT
      LAYER M5 ;
        RECT  36.336 105.732 36.36 105.816 ;
    END
  END a[29]
  PIN a[2]
    DIRECTION INPUT ;
    USE SIGNAL ;
    PORT
      LAYER M5 ;
        RECT  33.744 105.732 33.768 105.816 ;
    END
  END a[2]
  PIN a[300]
    DIRECTION INPUT ;
    USE SIGNAL ;
    PORT
      LAYER M3 ;
        RECT  68.724 105.779 68.742 105.816 ;
    END
  END a[300]
  PIN a[301]
    DIRECTION INPUT ;
    USE SIGNAL ;
    PORT
      LAYER M3 ;
        RECT  68.796 105.779 68.814 105.816 ;
    END
  END a[301]
  PIN a[302]
    DIRECTION INPUT ;
    USE SIGNAL ;
    PORT
      LAYER M3 ;
        RECT  68.868 105.779 68.886 105.816 ;
    END
  END a[302]
  PIN a[303]
    DIRECTION INPUT ;
    USE SIGNAL ;
    PORT
      LAYER M3 ;
        RECT  68.94 105.779 68.958 105.816 ;
    END
  END a[303]
  PIN a[304]
    DIRECTION INPUT ;
    USE SIGNAL ;
    PORT
      LAYER M3 ;
        RECT  69.012 105.779 69.03 105.816 ;
    END
  END a[304]
  PIN a[305]
    DIRECTION INPUT ;
    USE SIGNAL ;
    PORT
      LAYER M3 ;
        RECT  69.084 105.779 69.102 105.816 ;
    END
  END a[305]
  PIN a[306]
    DIRECTION INPUT ;
    USE SIGNAL ;
    PORT
      LAYER M3 ;
        RECT  69.156 105.779 69.174 105.816 ;
    END
  END a[306]
  PIN a[307]
    DIRECTION INPUT ;
    USE SIGNAL ;
    PORT
      LAYER M3 ;
        RECT  69.228 105.779 69.246 105.816 ;
    END
  END a[307]
  PIN a[308]
    DIRECTION INPUT ;
    USE SIGNAL ;
    PORT
      LAYER M3 ;
        RECT  69.3 105.779 69.318 105.816 ;
    END
  END a[308]
  PIN a[309]
    DIRECTION INPUT ;
    USE SIGNAL ;
    PORT
      LAYER M3 ;
        RECT  69.372 105.779 69.39 105.816 ;
    END
  END a[309]
  PIN a[30]
    DIRECTION INPUT ;
    USE SIGNAL ;
    PORT
      LAYER M5 ;
        RECT  36.432 105.732 36.456 105.816 ;
    END
  END a[30]
  PIN a[310]
    DIRECTION INPUT ;
    USE SIGNAL ;
    PORT
      LAYER M3 ;
        RECT  69.444 105.779 69.462 105.816 ;
    END
  END a[310]
  PIN a[311]
    DIRECTION INPUT ;
    USE SIGNAL ;
    PORT
      LAYER M3 ;
        RECT  69.516 105.779 69.534 105.816 ;
    END
  END a[311]
  PIN a[312]
    DIRECTION INPUT ;
    USE SIGNAL ;
    PORT
      LAYER M3 ;
        RECT  69.588 105.779 69.606 105.816 ;
    END
  END a[312]
  PIN a[313]
    DIRECTION INPUT ;
    USE SIGNAL ;
    PORT
      LAYER M3 ;
        RECT  69.66 105.779 69.678 105.816 ;
    END
  END a[313]
  PIN a[314]
    DIRECTION INPUT ;
    USE SIGNAL ;
    PORT
      LAYER M3 ;
        RECT  69.732 105.779 69.75 105.816 ;
    END
  END a[314]
  PIN a[315]
    DIRECTION INPUT ;
    USE SIGNAL ;
    PORT
      LAYER M3 ;
        RECT  69.804 105.779 69.822 105.816 ;
    END
  END a[315]
  PIN a[316]
    DIRECTION INPUT ;
    USE SIGNAL ;
    PORT
      LAYER M3 ;
        RECT  69.876 105.779 69.894 105.816 ;
    END
  END a[316]
  PIN a[317]
    DIRECTION INPUT ;
    USE SIGNAL ;
    PORT
      LAYER M3 ;
        RECT  69.948 105.779 69.966 105.816 ;
    END
  END a[317]
  PIN a[318]
    DIRECTION INPUT ;
    USE SIGNAL ;
    PORT
      LAYER M3 ;
        RECT  70.02 105.779 70.038 105.816 ;
    END
  END a[318]
  PIN a[319]
    DIRECTION INPUT ;
    USE SIGNAL ;
    PORT
      LAYER M3 ;
        RECT  70.092 105.779 70.11 105.816 ;
    END
  END a[319]
  PIN a[31]
    DIRECTION INPUT ;
    USE SIGNAL ;
    PORT
      LAYER M5 ;
        RECT  36.528 105.732 36.552 105.816 ;
    END
  END a[31]
  PIN a[320]
    DIRECTION INPUT ;
    USE SIGNAL ;
    PORT
      LAYER M5 ;
        RECT  49.68 105.732 49.704 105.816 ;
    END
  END a[320]
  PIN a[321]
    DIRECTION INPUT ;
    USE SIGNAL ;
    PORT
      LAYER M5 ;
        RECT  49.776 105.732 49.8 105.816 ;
    END
  END a[321]
  PIN a[322]
    DIRECTION INPUT ;
    USE SIGNAL ;
    PORT
      LAYER M5 ;
        RECT  49.872 105.732 49.896 105.816 ;
    END
  END a[322]
  PIN a[323]
    DIRECTION INPUT ;
    USE SIGNAL ;
    PORT
      LAYER M5 ;
        RECT  49.968 105.732 49.992 105.816 ;
    END
  END a[323]
  PIN a[324]
    DIRECTION INPUT ;
    USE SIGNAL ;
    PORT
      LAYER M5 ;
        RECT  50.064 105.732 50.088 105.816 ;
    END
  END a[324]
  PIN a[325]
    DIRECTION INPUT ;
    USE SIGNAL ;
    PORT
      LAYER M5 ;
        RECT  50.16 105.732 50.184 105.816 ;
    END
  END a[325]
  PIN a[326]
    DIRECTION INPUT ;
    USE SIGNAL ;
    PORT
      LAYER M5 ;
        RECT  50.256 105.732 50.28 105.816 ;
    END
  END a[326]
  PIN a[327]
    DIRECTION INPUT ;
    USE SIGNAL ;
    PORT
      LAYER M5 ;
        RECT  50.352 105.732 50.376 105.816 ;
    END
  END a[327]
  PIN a[328]
    DIRECTION INPUT ;
    USE SIGNAL ;
    PORT
      LAYER M5 ;
        RECT  50.448 105.732 50.472 105.816 ;
    END
  END a[328]
  PIN a[329]
    DIRECTION INPUT ;
    USE SIGNAL ;
    PORT
      LAYER M5 ;
        RECT  50.544 105.732 50.568 105.816 ;
    END
  END a[329]
  PIN a[32]
    DIRECTION INPUT ;
    USE SIGNAL ;
    PORT
      LAYER M3 ;
        RECT  39.06 105.779 39.078 105.816 ;
    END
  END a[32]
  PIN a[330]
    DIRECTION INPUT ;
    USE SIGNAL ;
    PORT
      LAYER M5 ;
        RECT  50.64 105.732 50.664 105.816 ;
    END
  END a[330]
  PIN a[331]
    DIRECTION INPUT ;
    USE SIGNAL ;
    PORT
      LAYER M5 ;
        RECT  50.736 105.732 50.76 105.816 ;
    END
  END a[331]
  PIN a[332]
    DIRECTION INPUT ;
    USE SIGNAL ;
    PORT
      LAYER M5 ;
        RECT  50.832 105.732 50.856 105.816 ;
    END
  END a[332]
  PIN a[333]
    DIRECTION INPUT ;
    USE SIGNAL ;
    PORT
      LAYER M5 ;
        RECT  50.928 105.732 50.952 105.816 ;
    END
  END a[333]
  PIN a[334]
    DIRECTION INPUT ;
    USE SIGNAL ;
    PORT
      LAYER M5 ;
        RECT  51.024 105.732 51.048 105.816 ;
    END
  END a[334]
  PIN a[335]
    DIRECTION INPUT ;
    USE SIGNAL ;
    PORT
      LAYER M5 ;
        RECT  51.12 105.732 51.144 105.816 ;
    END
  END a[335]
  PIN a[336]
    DIRECTION INPUT ;
    USE SIGNAL ;
    PORT
      LAYER M5 ;
        RECT  51.216 105.732 51.24 105.816 ;
    END
  END a[336]
  PIN a[337]
    DIRECTION INPUT ;
    USE SIGNAL ;
    PORT
      LAYER M5 ;
        RECT  51.312 105.732 51.336 105.816 ;
    END
  END a[337]
  PIN a[338]
    DIRECTION INPUT ;
    USE SIGNAL ;
    PORT
      LAYER M5 ;
        RECT  51.408 105.732 51.432 105.816 ;
    END
  END a[338]
  PIN a[339]
    DIRECTION INPUT ;
    USE SIGNAL ;
    PORT
      LAYER M5 ;
        RECT  51.504 105.732 51.528 105.816 ;
    END
  END a[339]
  PIN a[33]
    DIRECTION INPUT ;
    USE SIGNAL ;
    PORT
      LAYER M3 ;
        RECT  39.132 105.779 39.15 105.816 ;
    END
  END a[33]
  PIN a[340]
    DIRECTION INPUT ;
    USE SIGNAL ;
    PORT
      LAYER M5 ;
        RECT  51.6 105.732 51.624 105.816 ;
    END
  END a[340]
  PIN a[341]
    DIRECTION INPUT ;
    USE SIGNAL ;
    PORT
      LAYER M5 ;
        RECT  51.696 105.732 51.72 105.816 ;
    END
  END a[341]
  PIN a[342]
    DIRECTION INPUT ;
    USE SIGNAL ;
    PORT
      LAYER M5 ;
        RECT  51.792 105.732 51.816 105.816 ;
    END
  END a[342]
  PIN a[343]
    DIRECTION INPUT ;
    USE SIGNAL ;
    PORT
      LAYER M5 ;
        RECT  51.888 105.732 51.912 105.816 ;
    END
  END a[343]
  PIN a[344]
    DIRECTION INPUT ;
    USE SIGNAL ;
    PORT
      LAYER M5 ;
        RECT  51.984 105.732 52.008 105.816 ;
    END
  END a[344]
  PIN a[345]
    DIRECTION INPUT ;
    USE SIGNAL ;
    PORT
      LAYER M5 ;
        RECT  52.08 105.732 52.104 105.816 ;
    END
  END a[345]
  PIN a[346]
    DIRECTION INPUT ;
    USE SIGNAL ;
    PORT
      LAYER M5 ;
        RECT  52.176 105.732 52.2 105.816 ;
    END
  END a[346]
  PIN a[347]
    DIRECTION INPUT ;
    USE SIGNAL ;
    PORT
      LAYER M5 ;
        RECT  52.272 105.732 52.296 105.816 ;
    END
  END a[347]
  PIN a[348]
    DIRECTION INPUT ;
    USE SIGNAL ;
    PORT
      LAYER M5 ;
        RECT  52.368 105.732 52.392 105.816 ;
    END
  END a[348]
  PIN a[349]
    DIRECTION INPUT ;
    USE SIGNAL ;
    PORT
      LAYER M5 ;
        RECT  52.464 105.732 52.488 105.816 ;
    END
  END a[349]
  PIN a[34]
    DIRECTION INPUT ;
    USE SIGNAL ;
    PORT
      LAYER M3 ;
        RECT  39.204 105.779 39.222 105.816 ;
    END
  END a[34]
  PIN a[350]
    DIRECTION INPUT ;
    USE SIGNAL ;
    PORT
      LAYER M5 ;
        RECT  52.56 105.732 52.584 105.816 ;
    END
  END a[350]
  PIN a[351]
    DIRECTION INPUT ;
    USE SIGNAL ;
    PORT
      LAYER M5 ;
        RECT  52.656 105.732 52.68 105.816 ;
    END
  END a[351]
  PIN a[352]
    DIRECTION INPUT ;
    USE SIGNAL ;
    PORT
      LAYER M5 ;
        RECT  52.752 105.732 52.776 105.816 ;
    END
  END a[352]
  PIN a[353]
    DIRECTION INPUT ;
    USE SIGNAL ;
    PORT
      LAYER M5 ;
        RECT  52.848 105.732 52.872 105.816 ;
    END
  END a[353]
  PIN a[354]
    DIRECTION INPUT ;
    USE SIGNAL ;
    PORT
      LAYER M5 ;
        RECT  52.944 105.732 52.968 105.816 ;
    END
  END a[354]
  PIN a[355]
    DIRECTION INPUT ;
    USE SIGNAL ;
    PORT
      LAYER M5 ;
        RECT  53.04 105.732 53.064 105.816 ;
    END
  END a[355]
  PIN a[356]
    DIRECTION INPUT ;
    USE SIGNAL ;
    PORT
      LAYER M5 ;
        RECT  53.136 105.732 53.16 105.816 ;
    END
  END a[356]
  PIN a[357]
    DIRECTION INPUT ;
    USE SIGNAL ;
    PORT
      LAYER M5 ;
        RECT  53.232 105.732 53.256 105.816 ;
    END
  END a[357]
  PIN a[358]
    DIRECTION INPUT ;
    USE SIGNAL ;
    PORT
      LAYER M5 ;
        RECT  53.328 105.732 53.352 105.816 ;
    END
  END a[358]
  PIN a[359]
    DIRECTION INPUT ;
    USE SIGNAL ;
    PORT
      LAYER M5 ;
        RECT  53.424 105.732 53.448 105.816 ;
    END
  END a[359]
  PIN a[35]
    DIRECTION INPUT ;
    USE SIGNAL ;
    PORT
      LAYER M3 ;
        RECT  39.276 105.779 39.294 105.816 ;
    END
  END a[35]
  PIN a[360]
    DIRECTION INPUT ;
    USE SIGNAL ;
    PORT
      LAYER M5 ;
        RECT  53.52 105.732 53.544 105.816 ;
    END
  END a[360]
  PIN a[361]
    DIRECTION INPUT ;
    USE SIGNAL ;
    PORT
      LAYER M5 ;
        RECT  53.616 105.732 53.64 105.816 ;
    END
  END a[361]
  PIN a[362]
    DIRECTION INPUT ;
    USE SIGNAL ;
    PORT
      LAYER M5 ;
        RECT  53.712 105.732 53.736 105.816 ;
    END
  END a[362]
  PIN a[363]
    DIRECTION INPUT ;
    USE SIGNAL ;
    PORT
      LAYER M5 ;
        RECT  53.808 105.732 53.832 105.816 ;
    END
  END a[363]
  PIN a[364]
    DIRECTION INPUT ;
    USE SIGNAL ;
    PORT
      LAYER M5 ;
        RECT  53.904 105.732 53.928 105.816 ;
    END
  END a[364]
  PIN a[365]
    DIRECTION INPUT ;
    USE SIGNAL ;
    PORT
      LAYER M5 ;
        RECT  54 105.732 54.024 105.816 ;
    END
  END a[365]
  PIN a[366]
    DIRECTION INPUT ;
    USE SIGNAL ;
    PORT
      LAYER M5 ;
        RECT  54.096 105.732 54.12 105.816 ;
    END
  END a[366]
  PIN a[367]
    DIRECTION INPUT ;
    USE SIGNAL ;
    PORT
      LAYER M5 ;
        RECT  54.192 105.732 54.216 105.816 ;
    END
  END a[367]
  PIN a[368]
    DIRECTION INPUT ;
    USE SIGNAL ;
    PORT
      LAYER M5 ;
        RECT  54.288 105.732 54.312 105.816 ;
    END
  END a[368]
  PIN a[369]
    DIRECTION INPUT ;
    USE SIGNAL ;
    PORT
      LAYER M5 ;
        RECT  54.384 105.732 54.408 105.816 ;
    END
  END a[369]
  PIN a[36]
    DIRECTION INPUT ;
    USE SIGNAL ;
    PORT
      LAYER M3 ;
        RECT  39.348 105.779 39.366 105.816 ;
    END
  END a[36]
  PIN a[370]
    DIRECTION INPUT ;
    USE SIGNAL ;
    PORT
      LAYER M5 ;
        RECT  54.48 105.732 54.504 105.816 ;
    END
  END a[370]
  PIN a[371]
    DIRECTION INPUT ;
    USE SIGNAL ;
    PORT
      LAYER M5 ;
        RECT  54.576 105.732 54.6 105.816 ;
    END
  END a[371]
  PIN a[372]
    DIRECTION INPUT ;
    USE SIGNAL ;
    PORT
      LAYER M5 ;
        RECT  54.672 105.732 54.696 105.816 ;
    END
  END a[372]
  PIN a[373]
    DIRECTION INPUT ;
    USE SIGNAL ;
    PORT
      LAYER M5 ;
        RECT  54.768 105.732 54.792 105.816 ;
    END
  END a[373]
  PIN a[374]
    DIRECTION INPUT ;
    USE SIGNAL ;
    PORT
      LAYER M5 ;
        RECT  54.864 105.732 54.888 105.816 ;
    END
  END a[374]
  PIN a[375]
    DIRECTION INPUT ;
    USE SIGNAL ;
    PORT
      LAYER M5 ;
        RECT  54.96 105.732 54.984 105.816 ;
    END
  END a[375]
  PIN a[376]
    DIRECTION INPUT ;
    USE SIGNAL ;
    PORT
      LAYER M5 ;
        RECT  55.056 105.732 55.08 105.816 ;
    END
  END a[376]
  PIN a[377]
    DIRECTION INPUT ;
    USE SIGNAL ;
    PORT
      LAYER M5 ;
        RECT  55.152 105.732 55.176 105.816 ;
    END
  END a[377]
  PIN a[378]
    DIRECTION INPUT ;
    USE SIGNAL ;
    PORT
      LAYER M5 ;
        RECT  55.248 105.732 55.272 105.816 ;
    END
  END a[378]
  PIN a[379]
    DIRECTION INPUT ;
    USE SIGNAL ;
    PORT
      LAYER M5 ;
        RECT  55.344 105.732 55.368 105.816 ;
    END
  END a[379]
  PIN a[37]
    DIRECTION INPUT ;
    USE SIGNAL ;
    PORT
      LAYER M3 ;
        RECT  39.42 105.779 39.438 105.816 ;
    END
  END a[37]
  PIN a[380]
    DIRECTION INPUT ;
    USE SIGNAL ;
    PORT
      LAYER M5 ;
        RECT  55.44 105.732 55.464 105.816 ;
    END
  END a[380]
  PIN a[381]
    DIRECTION INPUT ;
    USE SIGNAL ;
    PORT
      LAYER M5 ;
        RECT  55.536 105.732 55.56 105.816 ;
    END
  END a[381]
  PIN a[382]
    DIRECTION INPUT ;
    USE SIGNAL ;
    PORT
      LAYER M5 ;
        RECT  55.632 105.732 55.656 105.816 ;
    END
  END a[382]
  PIN a[383]
    DIRECTION INPUT ;
    USE SIGNAL ;
    PORT
      LAYER M5 ;
        RECT  55.728 105.732 55.752 105.816 ;
    END
  END a[383]
  PIN a[384]
    DIRECTION INPUT ;
    USE SIGNAL ;
    PORT
      LAYER M5 ;
        RECT  55.824 105.732 55.848 105.816 ;
    END
  END a[384]
  PIN a[385]
    DIRECTION INPUT ;
    USE SIGNAL ;
    PORT
      LAYER M5 ;
        RECT  55.92 105.732 55.944 105.816 ;
    END
  END a[385]
  PIN a[386]
    DIRECTION INPUT ;
    USE SIGNAL ;
    PORT
      LAYER M5 ;
        RECT  56.016 105.732 56.04 105.816 ;
    END
  END a[386]
  PIN a[387]
    DIRECTION INPUT ;
    USE SIGNAL ;
    PORT
      LAYER M5 ;
        RECT  56.112 105.732 56.136 105.816 ;
    END
  END a[387]
  PIN a[388]
    DIRECTION INPUT ;
    USE SIGNAL ;
    PORT
      LAYER M5 ;
        RECT  56.208 105.732 56.232 105.816 ;
    END
  END a[388]
  PIN a[389]
    DIRECTION INPUT ;
    USE SIGNAL ;
    PORT
      LAYER M5 ;
        RECT  56.304 105.732 56.328 105.816 ;
    END
  END a[389]
  PIN a[38]
    DIRECTION INPUT ;
    USE SIGNAL ;
    PORT
      LAYER M3 ;
        RECT  39.492 105.779 39.51 105.816 ;
    END
  END a[38]
  PIN a[390]
    DIRECTION INPUT ;
    USE SIGNAL ;
    PORT
      LAYER M5 ;
        RECT  56.4 105.732 56.424 105.816 ;
    END
  END a[390]
  PIN a[391]
    DIRECTION INPUT ;
    USE SIGNAL ;
    PORT
      LAYER M5 ;
        RECT  56.496 105.732 56.52 105.816 ;
    END
  END a[391]
  PIN a[392]
    DIRECTION INPUT ;
    USE SIGNAL ;
    PORT
      LAYER M5 ;
        RECT  56.592 105.732 56.616 105.816 ;
    END
  END a[392]
  PIN a[393]
    DIRECTION INPUT ;
    USE SIGNAL ;
    PORT
      LAYER M5 ;
        RECT  56.688 105.732 56.712 105.816 ;
    END
  END a[393]
  PIN a[394]
    DIRECTION INPUT ;
    USE SIGNAL ;
    PORT
      LAYER M5 ;
        RECT  56.784 105.732 56.808 105.816 ;
    END
  END a[394]
  PIN a[395]
    DIRECTION INPUT ;
    USE SIGNAL ;
    PORT
      LAYER M5 ;
        RECT  56.88 105.732 56.904 105.816 ;
    END
  END a[395]
  PIN a[396]
    DIRECTION INPUT ;
    USE SIGNAL ;
    PORT
      LAYER M5 ;
        RECT  56.976 105.732 57 105.816 ;
    END
  END a[396]
  PIN a[397]
    DIRECTION INPUT ;
    USE SIGNAL ;
    PORT
      LAYER M5 ;
        RECT  57.072 105.732 57.096 105.816 ;
    END
  END a[397]
  PIN a[398]
    DIRECTION INPUT ;
    USE SIGNAL ;
    PORT
      LAYER M5 ;
        RECT  57.168 105.732 57.192 105.816 ;
    END
  END a[398]
  PIN a[399]
    DIRECTION INPUT ;
    USE SIGNAL ;
    PORT
      LAYER M5 ;
        RECT  57.264 105.732 57.288 105.816 ;
    END
  END a[399]
  PIN a[39]
    DIRECTION INPUT ;
    USE SIGNAL ;
    PORT
      LAYER M3 ;
        RECT  39.564 105.779 39.582 105.816 ;
    END
  END a[39]
  PIN a[3]
    DIRECTION INPUT ;
    USE SIGNAL ;
    PORT
      LAYER M5 ;
        RECT  33.84 105.732 33.864 105.816 ;
    END
  END a[3]
  PIN a[400]
    DIRECTION INPUT ;
    USE SIGNAL ;
    PORT
      LAYER M5 ;
        RECT  57.36 105.732 57.384 105.816 ;
    END
  END a[400]
  PIN a[401]
    DIRECTION INPUT ;
    USE SIGNAL ;
    PORT
      LAYER M5 ;
        RECT  57.456 105.732 57.48 105.816 ;
    END
  END a[401]
  PIN a[402]
    DIRECTION INPUT ;
    USE SIGNAL ;
    PORT
      LAYER M5 ;
        RECT  57.552 105.732 57.576 105.816 ;
    END
  END a[402]
  PIN a[403]
    DIRECTION INPUT ;
    USE SIGNAL ;
    PORT
      LAYER M5 ;
        RECT  57.648 105.732 57.672 105.816 ;
    END
  END a[403]
  PIN a[404]
    DIRECTION INPUT ;
    USE SIGNAL ;
    PORT
      LAYER M5 ;
        RECT  57.744 105.732 57.768 105.816 ;
    END
  END a[404]
  PIN a[405]
    DIRECTION INPUT ;
    USE SIGNAL ;
    PORT
      LAYER M5 ;
        RECT  57.84 105.732 57.864 105.816 ;
    END
  END a[405]
  PIN a[406]
    DIRECTION INPUT ;
    USE SIGNAL ;
    PORT
      LAYER M5 ;
        RECT  57.936 105.732 57.96 105.816 ;
    END
  END a[406]
  PIN a[407]
    DIRECTION INPUT ;
    USE SIGNAL ;
    PORT
      LAYER M5 ;
        RECT  58.032 105.732 58.056 105.816 ;
    END
  END a[407]
  PIN a[408]
    DIRECTION INPUT ;
    USE SIGNAL ;
    PORT
      LAYER M5 ;
        RECT  58.128 105.732 58.152 105.816 ;
    END
  END a[408]
  PIN a[409]
    DIRECTION INPUT ;
    USE SIGNAL ;
    PORT
      LAYER M5 ;
        RECT  58.224 105.732 58.248 105.816 ;
    END
  END a[409]
  PIN a[40]
    DIRECTION INPUT ;
    USE SIGNAL ;
    PORT
      LAYER M3 ;
        RECT  39.636 105.779 39.654 105.816 ;
    END
  END a[40]
  PIN a[410]
    DIRECTION INPUT ;
    USE SIGNAL ;
    PORT
      LAYER M5 ;
        RECT  58.32 105.732 58.344 105.816 ;
    END
  END a[410]
  PIN a[411]
    DIRECTION INPUT ;
    USE SIGNAL ;
    PORT
      LAYER M5 ;
        RECT  58.416 105.732 58.44 105.816 ;
    END
  END a[411]
  PIN a[412]
    DIRECTION INPUT ;
    USE SIGNAL ;
    PORT
      LAYER M5 ;
        RECT  58.512 105.732 58.536 105.816 ;
    END
  END a[412]
  PIN a[413]
    DIRECTION INPUT ;
    USE SIGNAL ;
    PORT
      LAYER M5 ;
        RECT  58.608 105.732 58.632 105.816 ;
    END
  END a[413]
  PIN a[414]
    DIRECTION INPUT ;
    USE SIGNAL ;
    PORT
      LAYER M5 ;
        RECT  58.704 105.732 58.728 105.816 ;
    END
  END a[414]
  PIN a[415]
    DIRECTION INPUT ;
    USE SIGNAL ;
    PORT
      LAYER M5 ;
        RECT  58.8 105.732 58.824 105.816 ;
    END
  END a[415]
  PIN a[416]
    DIRECTION INPUT ;
    USE SIGNAL ;
    PORT
      LAYER M3 ;
        RECT  46.548 105.779 46.566 105.816 ;
    END
  END a[416]
  PIN a[417]
    DIRECTION INPUT ;
    USE SIGNAL ;
    PORT
      LAYER M3 ;
        RECT  46.62 105.779 46.638 105.816 ;
    END
  END a[417]
  PIN a[418]
    DIRECTION INPUT ;
    USE SIGNAL ;
    PORT
      LAYER M3 ;
        RECT  46.692 105.779 46.71 105.816 ;
    END
  END a[418]
  PIN a[419]
    DIRECTION INPUT ;
    USE SIGNAL ;
    PORT
      LAYER M3 ;
        RECT  46.764 105.779 46.782 105.816 ;
    END
  END a[419]
  PIN a[41]
    DIRECTION INPUT ;
    USE SIGNAL ;
    PORT
      LAYER M3 ;
        RECT  39.708 105.779 39.726 105.816 ;
    END
  END a[41]
  PIN a[420]
    DIRECTION INPUT ;
    USE SIGNAL ;
    PORT
      LAYER M3 ;
        RECT  46.836 105.779 46.854 105.816 ;
    END
  END a[420]
  PIN a[421]
    DIRECTION INPUT ;
    USE SIGNAL ;
    PORT
      LAYER M3 ;
        RECT  46.908 105.779 46.926 105.816 ;
    END
  END a[421]
  PIN a[422]
    DIRECTION INPUT ;
    USE SIGNAL ;
    PORT
      LAYER M3 ;
        RECT  46.98 105.779 46.998 105.816 ;
    END
  END a[422]
  PIN a[423]
    DIRECTION INPUT ;
    USE SIGNAL ;
    PORT
      LAYER M3 ;
        RECT  47.052 105.779 47.07 105.816 ;
    END
  END a[423]
  PIN a[424]
    DIRECTION INPUT ;
    USE SIGNAL ;
    PORT
      LAYER M3 ;
        RECT  47.124 105.779 47.142 105.816 ;
    END
  END a[424]
  PIN a[425]
    DIRECTION INPUT ;
    USE SIGNAL ;
    PORT
      LAYER M3 ;
        RECT  47.196 105.779 47.214 105.816 ;
    END
  END a[425]
  PIN a[426]
    DIRECTION INPUT ;
    USE SIGNAL ;
    PORT
      LAYER M3 ;
        RECT  47.268 105.779 47.286 105.816 ;
    END
  END a[426]
  PIN a[427]
    DIRECTION INPUT ;
    USE SIGNAL ;
    PORT
      LAYER M3 ;
        RECT  47.34 105.779 47.358 105.816 ;
    END
  END a[427]
  PIN a[428]
    DIRECTION INPUT ;
    USE SIGNAL ;
    PORT
      LAYER M3 ;
        RECT  47.412 105.779 47.43 105.816 ;
    END
  END a[428]
  PIN a[429]
    DIRECTION INPUT ;
    USE SIGNAL ;
    PORT
      LAYER M3 ;
        RECT  47.484 105.779 47.502 105.816 ;
    END
  END a[429]
  PIN a[42]
    DIRECTION INPUT ;
    USE SIGNAL ;
    PORT
      LAYER M3 ;
        RECT  39.78 105.779 39.798 105.816 ;
    END
  END a[42]
  PIN a[430]
    DIRECTION INPUT ;
    USE SIGNAL ;
    PORT
      LAYER M3 ;
        RECT  47.556 105.779 47.574 105.816 ;
    END
  END a[430]
  PIN a[431]
    DIRECTION INPUT ;
    USE SIGNAL ;
    PORT
      LAYER M3 ;
        RECT  47.628 105.779 47.646 105.816 ;
    END
  END a[431]
  PIN a[432]
    DIRECTION INPUT ;
    USE SIGNAL ;
    PORT
      LAYER M3 ;
        RECT  47.7 105.779 47.718 105.816 ;
    END
  END a[432]
  PIN a[433]
    DIRECTION INPUT ;
    USE SIGNAL ;
    PORT
      LAYER M3 ;
        RECT  47.772 105.779 47.79 105.816 ;
    END
  END a[433]
  PIN a[434]
    DIRECTION INPUT ;
    USE SIGNAL ;
    PORT
      LAYER M3 ;
        RECT  47.844 105.779 47.862 105.816 ;
    END
  END a[434]
  PIN a[435]
    DIRECTION INPUT ;
    USE SIGNAL ;
    PORT
      LAYER M3 ;
        RECT  47.916 105.779 47.934 105.816 ;
    END
  END a[435]
  PIN a[436]
    DIRECTION INPUT ;
    USE SIGNAL ;
    PORT
      LAYER M3 ;
        RECT  47.988 105.779 48.006 105.816 ;
    END
  END a[436]
  PIN a[437]
    DIRECTION INPUT ;
    USE SIGNAL ;
    PORT
      LAYER M3 ;
        RECT  48.06 105.779 48.078 105.816 ;
    END
  END a[437]
  PIN a[438]
    DIRECTION INPUT ;
    USE SIGNAL ;
    PORT
      LAYER M3 ;
        RECT  48.132 105.779 48.15 105.816 ;
    END
  END a[438]
  PIN a[439]
    DIRECTION INPUT ;
    USE SIGNAL ;
    PORT
      LAYER M3 ;
        RECT  48.204 105.779 48.222 105.816 ;
    END
  END a[439]
  PIN a[43]
    DIRECTION INPUT ;
    USE SIGNAL ;
    PORT
      LAYER M3 ;
        RECT  39.852 105.779 39.87 105.816 ;
    END
  END a[43]
  PIN a[440]
    DIRECTION INPUT ;
    USE SIGNAL ;
    PORT
      LAYER M3 ;
        RECT  48.276 105.779 48.294 105.816 ;
    END
  END a[440]
  PIN a[441]
    DIRECTION INPUT ;
    USE SIGNAL ;
    PORT
      LAYER M3 ;
        RECT  48.348 105.779 48.366 105.816 ;
    END
  END a[441]
  PIN a[442]
    DIRECTION INPUT ;
    USE SIGNAL ;
    PORT
      LAYER M3 ;
        RECT  48.42 105.779 48.438 105.816 ;
    END
  END a[442]
  PIN a[443]
    DIRECTION INPUT ;
    USE SIGNAL ;
    PORT
      LAYER M3 ;
        RECT  48.492 105.779 48.51 105.816 ;
    END
  END a[443]
  PIN a[444]
    DIRECTION INPUT ;
    USE SIGNAL ;
    PORT
      LAYER M3 ;
        RECT  48.564 105.779 48.582 105.816 ;
    END
  END a[444]
  PIN a[445]
    DIRECTION INPUT ;
    USE SIGNAL ;
    PORT
      LAYER M3 ;
        RECT  48.636 105.779 48.654 105.816 ;
    END
  END a[445]
  PIN a[446]
    DIRECTION INPUT ;
    USE SIGNAL ;
    PORT
      LAYER M3 ;
        RECT  48.708 105.779 48.726 105.816 ;
    END
  END a[446]
  PIN a[447]
    DIRECTION INPUT ;
    USE SIGNAL ;
    PORT
      LAYER M3 ;
        RECT  48.78 105.779 48.798 105.816 ;
    END
  END a[447]
  PIN a[448]
    DIRECTION INPUT ;
    USE SIGNAL ;
    PORT
      LAYER M5 ;
        RECT  30.48 105.732 30.504 105.816 ;
    END
  END a[448]
  PIN a[449]
    DIRECTION INPUT ;
    USE SIGNAL ;
    PORT
      LAYER M5 ;
        RECT  30.576 105.732 30.6 105.816 ;
    END
  END a[449]
  PIN a[44]
    DIRECTION INPUT ;
    USE SIGNAL ;
    PORT
      LAYER M3 ;
        RECT  39.924 105.779 39.942 105.816 ;
    END
  END a[44]
  PIN a[450]
    DIRECTION INPUT ;
    USE SIGNAL ;
    PORT
      LAYER M5 ;
        RECT  30.672 105.732 30.696 105.816 ;
    END
  END a[450]
  PIN a[451]
    DIRECTION INPUT ;
    USE SIGNAL ;
    PORT
      LAYER M5 ;
        RECT  30.768 105.732 30.792 105.816 ;
    END
  END a[451]
  PIN a[452]
    DIRECTION INPUT ;
    USE SIGNAL ;
    PORT
      LAYER M5 ;
        RECT  30.864 105.732 30.888 105.816 ;
    END
  END a[452]
  PIN a[453]
    DIRECTION INPUT ;
    USE SIGNAL ;
    PORT
      LAYER M5 ;
        RECT  30.96 105.732 30.984 105.816 ;
    END
  END a[453]
  PIN a[454]
    DIRECTION INPUT ;
    USE SIGNAL ;
    PORT
      LAYER M5 ;
        RECT  31.056 105.732 31.08 105.816 ;
    END
  END a[454]
  PIN a[455]
    DIRECTION INPUT ;
    USE SIGNAL ;
    PORT
      LAYER M5 ;
        RECT  31.152 105.732 31.176 105.816 ;
    END
  END a[455]
  PIN a[456]
    DIRECTION INPUT ;
    USE SIGNAL ;
    PORT
      LAYER M5 ;
        RECT  31.248 105.732 31.272 105.816 ;
    END
  END a[456]
  PIN a[457]
    DIRECTION INPUT ;
    USE SIGNAL ;
    PORT
      LAYER M5 ;
        RECT  31.344 105.732 31.368 105.816 ;
    END
  END a[457]
  PIN a[458]
    DIRECTION INPUT ;
    USE SIGNAL ;
    PORT
      LAYER M5 ;
        RECT  31.44 105.732 31.464 105.816 ;
    END
  END a[458]
  PIN a[459]
    DIRECTION INPUT ;
    USE SIGNAL ;
    PORT
      LAYER M5 ;
        RECT  31.536 105.732 31.56 105.816 ;
    END
  END a[459]
  PIN a[45]
    DIRECTION INPUT ;
    USE SIGNAL ;
    PORT
      LAYER M3 ;
        RECT  39.996 105.779 40.014 105.816 ;
    END
  END a[45]
  PIN a[460]
    DIRECTION INPUT ;
    USE SIGNAL ;
    PORT
      LAYER M5 ;
        RECT  31.632 105.732 31.656 105.816 ;
    END
  END a[460]
  PIN a[461]
    DIRECTION INPUT ;
    USE SIGNAL ;
    PORT
      LAYER M5 ;
        RECT  31.728 105.732 31.752 105.816 ;
    END
  END a[461]
  PIN a[462]
    DIRECTION INPUT ;
    USE SIGNAL ;
    PORT
      LAYER M5 ;
        RECT  31.824 105.732 31.848 105.816 ;
    END
  END a[462]
  PIN a[463]
    DIRECTION INPUT ;
    USE SIGNAL ;
    PORT
      LAYER M5 ;
        RECT  31.92 105.732 31.944 105.816 ;
    END
  END a[463]
  PIN a[464]
    DIRECTION INPUT ;
    USE SIGNAL ;
    PORT
      LAYER M5 ;
        RECT  32.016 105.732 32.04 105.816 ;
    END
  END a[464]
  PIN a[465]
    DIRECTION INPUT ;
    USE SIGNAL ;
    PORT
      LAYER M5 ;
        RECT  32.112 105.732 32.136 105.816 ;
    END
  END a[465]
  PIN a[466]
    DIRECTION INPUT ;
    USE SIGNAL ;
    PORT
      LAYER M5 ;
        RECT  32.208 105.732 32.232 105.816 ;
    END
  END a[466]
  PIN a[467]
    DIRECTION INPUT ;
    USE SIGNAL ;
    PORT
      LAYER M5 ;
        RECT  32.304 105.732 32.328 105.816 ;
    END
  END a[467]
  PIN a[468]
    DIRECTION INPUT ;
    USE SIGNAL ;
    PORT
      LAYER M5 ;
        RECT  32.4 105.732 32.424 105.816 ;
    END
  END a[468]
  PIN a[469]
    DIRECTION INPUT ;
    USE SIGNAL ;
    PORT
      LAYER M5 ;
        RECT  32.496 105.732 32.52 105.816 ;
    END
  END a[469]
  PIN a[46]
    DIRECTION INPUT ;
    USE SIGNAL ;
    PORT
      LAYER M3 ;
        RECT  40.068 105.779 40.086 105.816 ;
    END
  END a[46]
  PIN a[470]
    DIRECTION INPUT ;
    USE SIGNAL ;
    PORT
      LAYER M5 ;
        RECT  32.592 105.732 32.616 105.816 ;
    END
  END a[470]
  PIN a[471]
    DIRECTION INPUT ;
    USE SIGNAL ;
    PORT
      LAYER M5 ;
        RECT  32.688 105.732 32.712 105.816 ;
    END
  END a[471]
  PIN a[472]
    DIRECTION INPUT ;
    USE SIGNAL ;
    PORT
      LAYER M5 ;
        RECT  32.784 105.732 32.808 105.816 ;
    END
  END a[472]
  PIN a[473]
    DIRECTION INPUT ;
    USE SIGNAL ;
    PORT
      LAYER M5 ;
        RECT  32.88 105.732 32.904 105.816 ;
    END
  END a[473]
  PIN a[474]
    DIRECTION INPUT ;
    USE SIGNAL ;
    PORT
      LAYER M5 ;
        RECT  32.976 105.732 33 105.816 ;
    END
  END a[474]
  PIN a[475]
    DIRECTION INPUT ;
    USE SIGNAL ;
    PORT
      LAYER M5 ;
        RECT  33.072 105.732 33.096 105.816 ;
    END
  END a[475]
  PIN a[476]
    DIRECTION INPUT ;
    USE SIGNAL ;
    PORT
      LAYER M5 ;
        RECT  33.168 105.732 33.192 105.816 ;
    END
  END a[476]
  PIN a[477]
    DIRECTION INPUT ;
    USE SIGNAL ;
    PORT
      LAYER M5 ;
        RECT  33.264 105.732 33.288 105.816 ;
    END
  END a[477]
  PIN a[478]
    DIRECTION INPUT ;
    USE SIGNAL ;
    PORT
      LAYER M5 ;
        RECT  33.36 105.732 33.384 105.816 ;
    END
  END a[478]
  PIN a[479]
    DIRECTION INPUT ;
    USE SIGNAL ;
    PORT
      LAYER M5 ;
        RECT  33.456 105.732 33.48 105.816 ;
    END
  END a[479]
  PIN a[47]
    DIRECTION INPUT ;
    USE SIGNAL ;
    PORT
      LAYER M3 ;
        RECT  40.14 105.779 40.158 105.816 ;
    END
  END a[47]
  PIN a[480]
    DIRECTION INPUT ;
    USE SIGNAL ;
    PORT
      LAYER M3 ;
        RECT  26.964 105.779 26.982 105.816 ;
    END
  END a[480]
  PIN a[481]
    DIRECTION INPUT ;
    USE SIGNAL ;
    PORT
      LAYER M3 ;
        RECT  27.036 105.779 27.054 105.816 ;
    END
  END a[481]
  PIN a[482]
    DIRECTION INPUT ;
    USE SIGNAL ;
    PORT
      LAYER M3 ;
        RECT  27.108 105.779 27.126 105.816 ;
    END
  END a[482]
  PIN a[483]
    DIRECTION INPUT ;
    USE SIGNAL ;
    PORT
      LAYER M3 ;
        RECT  27.18 105.779 27.198 105.816 ;
    END
  END a[483]
  PIN a[484]
    DIRECTION INPUT ;
    USE SIGNAL ;
    PORT
      LAYER M3 ;
        RECT  27.252 105.779 27.27 105.816 ;
    END
  END a[484]
  PIN a[485]
    DIRECTION INPUT ;
    USE SIGNAL ;
    PORT
      LAYER M3 ;
        RECT  27.324 105.779 27.342 105.816 ;
    END
  END a[485]
  PIN a[486]
    DIRECTION INPUT ;
    USE SIGNAL ;
    PORT
      LAYER M3 ;
        RECT  27.396 105.779 27.414 105.816 ;
    END
  END a[486]
  PIN a[487]
    DIRECTION INPUT ;
    USE SIGNAL ;
    PORT
      LAYER M3 ;
        RECT  27.468 105.779 27.486 105.816 ;
    END
  END a[487]
  PIN a[488]
    DIRECTION INPUT ;
    USE SIGNAL ;
    PORT
      LAYER M3 ;
        RECT  27.54 105.779 27.558 105.816 ;
    END
  END a[488]
  PIN a[489]
    DIRECTION INPUT ;
    USE SIGNAL ;
    PORT
      LAYER M3 ;
        RECT  27.612 105.779 27.63 105.816 ;
    END
  END a[489]
  PIN a[48]
    DIRECTION INPUT ;
    USE SIGNAL ;
    PORT
      LAYER M3 ;
        RECT  40.212 105.779 40.23 105.816 ;
    END
  END a[48]
  PIN a[490]
    DIRECTION INPUT ;
    USE SIGNAL ;
    PORT
      LAYER M3 ;
        RECT  27.684 105.779 27.702 105.816 ;
    END
  END a[490]
  PIN a[491]
    DIRECTION INPUT ;
    USE SIGNAL ;
    PORT
      LAYER M3 ;
        RECT  27.756 105.779 27.774 105.816 ;
    END
  END a[491]
  PIN a[492]
    DIRECTION INPUT ;
    USE SIGNAL ;
    PORT
      LAYER M3 ;
        RECT  27.828 105.779 27.846 105.816 ;
    END
  END a[492]
  PIN a[493]
    DIRECTION INPUT ;
    USE SIGNAL ;
    PORT
      LAYER M3 ;
        RECT  27.9 105.779 27.918 105.816 ;
    END
  END a[493]
  PIN a[494]
    DIRECTION INPUT ;
    USE SIGNAL ;
    PORT
      LAYER M3 ;
        RECT  27.972 105.779 27.99 105.816 ;
    END
  END a[494]
  PIN a[495]
    DIRECTION INPUT ;
    USE SIGNAL ;
    PORT
      LAYER M3 ;
        RECT  28.044 105.779 28.062 105.816 ;
    END
  END a[495]
  PIN a[496]
    DIRECTION INPUT ;
    USE SIGNAL ;
    PORT
      LAYER M3 ;
        RECT  28.116 105.779 28.134 105.816 ;
    END
  END a[496]
  PIN a[497]
    DIRECTION INPUT ;
    USE SIGNAL ;
    PORT
      LAYER M3 ;
        RECT  28.188 105.779 28.206 105.816 ;
    END
  END a[497]
  PIN a[498]
    DIRECTION INPUT ;
    USE SIGNAL ;
    PORT
      LAYER M3 ;
        RECT  28.26 105.779 28.278 105.816 ;
    END
  END a[498]
  PIN a[499]
    DIRECTION INPUT ;
    USE SIGNAL ;
    PORT
      LAYER M3 ;
        RECT  28.332 105.779 28.35 105.816 ;
    END
  END a[499]
  PIN a[49]
    DIRECTION INPUT ;
    USE SIGNAL ;
    PORT
      LAYER M3 ;
        RECT  40.284 105.779 40.302 105.816 ;
    END
  END a[49]
  PIN a[4]
    DIRECTION INPUT ;
    USE SIGNAL ;
    PORT
      LAYER M5 ;
        RECT  33.936 105.732 33.96 105.816 ;
    END
  END a[4]
  PIN a[500]
    DIRECTION INPUT ;
    USE SIGNAL ;
    PORT
      LAYER M3 ;
        RECT  28.404 105.779 28.422 105.816 ;
    END
  END a[500]
  PIN a[501]
    DIRECTION INPUT ;
    USE SIGNAL ;
    PORT
      LAYER M3 ;
        RECT  28.476 105.779 28.494 105.816 ;
    END
  END a[501]
  PIN a[502]
    DIRECTION INPUT ;
    USE SIGNAL ;
    PORT
      LAYER M3 ;
        RECT  28.548 105.779 28.566 105.816 ;
    END
  END a[502]
  PIN a[503]
    DIRECTION INPUT ;
    USE SIGNAL ;
    PORT
      LAYER M3 ;
        RECT  28.62 105.779 28.638 105.816 ;
    END
  END a[503]
  PIN a[504]
    DIRECTION INPUT ;
    USE SIGNAL ;
    PORT
      LAYER M3 ;
        RECT  28.692 105.779 28.71 105.816 ;
    END
  END a[504]
  PIN a[505]
    DIRECTION INPUT ;
    USE SIGNAL ;
    PORT
      LAYER M3 ;
        RECT  28.764 105.779 28.782 105.816 ;
    END
  END a[505]
  PIN a[506]
    DIRECTION INPUT ;
    USE SIGNAL ;
    PORT
      LAYER M3 ;
        RECT  28.836 105.779 28.854 105.816 ;
    END
  END a[506]
  PIN a[507]
    DIRECTION INPUT ;
    USE SIGNAL ;
    PORT
      LAYER M3 ;
        RECT  28.908 105.779 28.926 105.816 ;
    END
  END a[507]
  PIN a[508]
    DIRECTION INPUT ;
    USE SIGNAL ;
    PORT
      LAYER M3 ;
        RECT  28.98 105.779 28.998 105.816 ;
    END
  END a[508]
  PIN a[509]
    DIRECTION INPUT ;
    USE SIGNAL ;
    PORT
      LAYER M3 ;
        RECT  29.052 105.779 29.07 105.816 ;
    END
  END a[509]
  PIN a[50]
    DIRECTION INPUT ;
    USE SIGNAL ;
    PORT
      LAYER M3 ;
        RECT  40.356 105.779 40.374 105.816 ;
    END
  END a[50]
  PIN a[510]
    DIRECTION INPUT ;
    USE SIGNAL ;
    PORT
      LAYER M3 ;
        RECT  29.124 105.779 29.142 105.816 ;
    END
  END a[510]
  PIN a[511]
    DIRECTION INPUT ;
    USE SIGNAL ;
    PORT
      LAYER M3 ;
        RECT  29.196 105.779 29.214 105.816 ;
    END
  END a[511]
  PIN a[512]
    DIRECTION INPUT ;
    USE SIGNAL ;
    PORT
      LAYER M3 ;
        RECT  17.748 105.779 17.766 105.816 ;
    END
  END a[512]
  PIN a[513]
    DIRECTION INPUT ;
    USE SIGNAL ;
    PORT
      LAYER M3 ;
        RECT  17.82 105.779 17.838 105.816 ;
    END
  END a[513]
  PIN a[514]
    DIRECTION INPUT ;
    USE SIGNAL ;
    PORT
      LAYER M3 ;
        RECT  17.892 105.779 17.91 105.816 ;
    END
  END a[514]
  PIN a[515]
    DIRECTION INPUT ;
    USE SIGNAL ;
    PORT
      LAYER M3 ;
        RECT  17.964 105.779 17.982 105.816 ;
    END
  END a[515]
  PIN a[516]
    DIRECTION INPUT ;
    USE SIGNAL ;
    PORT
      LAYER M3 ;
        RECT  18.036 105.779 18.054 105.816 ;
    END
  END a[516]
  PIN a[517]
    DIRECTION INPUT ;
    USE SIGNAL ;
    PORT
      LAYER M3 ;
        RECT  18.108 105.779 18.126 105.816 ;
    END
  END a[517]
  PIN a[518]
    DIRECTION INPUT ;
    USE SIGNAL ;
    PORT
      LAYER M3 ;
        RECT  18.18 105.779 18.198 105.816 ;
    END
  END a[518]
  PIN a[519]
    DIRECTION INPUT ;
    USE SIGNAL ;
    PORT
      LAYER M3 ;
        RECT  18.252 105.779 18.27 105.816 ;
    END
  END a[519]
  PIN a[51]
    DIRECTION INPUT ;
    USE SIGNAL ;
    PORT
      LAYER M3 ;
        RECT  40.428 105.779 40.446 105.816 ;
    END
  END a[51]
  PIN a[520]
    DIRECTION INPUT ;
    USE SIGNAL ;
    PORT
      LAYER M3 ;
        RECT  18.324 105.779 18.342 105.816 ;
    END
  END a[520]
  PIN a[521]
    DIRECTION INPUT ;
    USE SIGNAL ;
    PORT
      LAYER M3 ;
        RECT  18.396 105.779 18.414 105.816 ;
    END
  END a[521]
  PIN a[522]
    DIRECTION INPUT ;
    USE SIGNAL ;
    PORT
      LAYER M3 ;
        RECT  18.468 105.779 18.486 105.816 ;
    END
  END a[522]
  PIN a[523]
    DIRECTION INPUT ;
    USE SIGNAL ;
    PORT
      LAYER M3 ;
        RECT  18.54 105.779 18.558 105.816 ;
    END
  END a[523]
  PIN a[524]
    DIRECTION INPUT ;
    USE SIGNAL ;
    PORT
      LAYER M3 ;
        RECT  18.612 105.779 18.63 105.816 ;
    END
  END a[524]
  PIN a[525]
    DIRECTION INPUT ;
    USE SIGNAL ;
    PORT
      LAYER M3 ;
        RECT  18.684 105.779 18.702 105.816 ;
    END
  END a[525]
  PIN a[526]
    DIRECTION INPUT ;
    USE SIGNAL ;
    PORT
      LAYER M3 ;
        RECT  18.756 105.779 18.774 105.816 ;
    END
  END a[526]
  PIN a[527]
    DIRECTION INPUT ;
    USE SIGNAL ;
    PORT
      LAYER M3 ;
        RECT  18.828 105.779 18.846 105.816 ;
    END
  END a[527]
  PIN a[528]
    DIRECTION INPUT ;
    USE SIGNAL ;
    PORT
      LAYER M3 ;
        RECT  18.9 105.779 18.918 105.816 ;
    END
  END a[528]
  PIN a[529]
    DIRECTION INPUT ;
    USE SIGNAL ;
    PORT
      LAYER M3 ;
        RECT  18.972 105.779 18.99 105.816 ;
    END
  END a[529]
  PIN a[52]
    DIRECTION INPUT ;
    USE SIGNAL ;
    PORT
      LAYER M3 ;
        RECT  40.5 105.779 40.518 105.816 ;
    END
  END a[52]
  PIN a[530]
    DIRECTION INPUT ;
    USE SIGNAL ;
    PORT
      LAYER M3 ;
        RECT  19.044 105.779 19.062 105.816 ;
    END
  END a[530]
  PIN a[531]
    DIRECTION INPUT ;
    USE SIGNAL ;
    PORT
      LAYER M3 ;
        RECT  19.116 105.779 19.134 105.816 ;
    END
  END a[531]
  PIN a[532]
    DIRECTION INPUT ;
    USE SIGNAL ;
    PORT
      LAYER M3 ;
        RECT  19.188 105.779 19.206 105.816 ;
    END
  END a[532]
  PIN a[533]
    DIRECTION INPUT ;
    USE SIGNAL ;
    PORT
      LAYER M3 ;
        RECT  19.26 105.779 19.278 105.816 ;
    END
  END a[533]
  PIN a[534]
    DIRECTION INPUT ;
    USE SIGNAL ;
    PORT
      LAYER M3 ;
        RECT  19.332 105.779 19.35 105.816 ;
    END
  END a[534]
  PIN a[535]
    DIRECTION INPUT ;
    USE SIGNAL ;
    PORT
      LAYER M3 ;
        RECT  19.404 105.779 19.422 105.816 ;
    END
  END a[535]
  PIN a[536]
    DIRECTION INPUT ;
    USE SIGNAL ;
    PORT
      LAYER M3 ;
        RECT  19.476 105.779 19.494 105.816 ;
    END
  END a[536]
  PIN a[537]
    DIRECTION INPUT ;
    USE SIGNAL ;
    PORT
      LAYER M3 ;
        RECT  19.548 105.779 19.566 105.816 ;
    END
  END a[537]
  PIN a[538]
    DIRECTION INPUT ;
    USE SIGNAL ;
    PORT
      LAYER M3 ;
        RECT  19.62 105.779 19.638 105.816 ;
    END
  END a[538]
  PIN a[539]
    DIRECTION INPUT ;
    USE SIGNAL ;
    PORT
      LAYER M3 ;
        RECT  19.692 105.779 19.71 105.816 ;
    END
  END a[539]
  PIN a[53]
    DIRECTION INPUT ;
    USE SIGNAL ;
    PORT
      LAYER M3 ;
        RECT  40.572 105.779 40.59 105.816 ;
    END
  END a[53]
  PIN a[540]
    DIRECTION INPUT ;
    USE SIGNAL ;
    PORT
      LAYER M3 ;
        RECT  19.764 105.779 19.782 105.816 ;
    END
  END a[540]
  PIN a[541]
    DIRECTION INPUT ;
    USE SIGNAL ;
    PORT
      LAYER M3 ;
        RECT  19.836 105.779 19.854 105.816 ;
    END
  END a[541]
  PIN a[542]
    DIRECTION INPUT ;
    USE SIGNAL ;
    PORT
      LAYER M3 ;
        RECT  19.908 105.779 19.926 105.816 ;
    END
  END a[542]
  PIN a[543]
    DIRECTION INPUT ;
    USE SIGNAL ;
    PORT
      LAYER M3 ;
        RECT  19.98 105.779 19.998 105.816 ;
    END
  END a[543]
  PIN a[544]
    DIRECTION INPUT ;
    USE SIGNAL ;
    PORT
      LAYER M3 ;
        RECT  7.956 105.779 7.974 105.816 ;
    END
  END a[544]
  PIN a[545]
    DIRECTION INPUT ;
    USE SIGNAL ;
    PORT
      LAYER M3 ;
        RECT  8.028 105.779 8.046 105.816 ;
    END
  END a[545]
  PIN a[546]
    DIRECTION INPUT ;
    USE SIGNAL ;
    PORT
      LAYER M3 ;
        RECT  8.1 105.779 8.118 105.816 ;
    END
  END a[546]
  PIN a[547]
    DIRECTION INPUT ;
    USE SIGNAL ;
    PORT
      LAYER M3 ;
        RECT  8.172 105.779 8.19 105.816 ;
    END
  END a[547]
  PIN a[548]
    DIRECTION INPUT ;
    USE SIGNAL ;
    PORT
      LAYER M3 ;
        RECT  8.244 105.779 8.262 105.816 ;
    END
  END a[548]
  PIN a[549]
    DIRECTION INPUT ;
    USE SIGNAL ;
    PORT
      LAYER M3 ;
        RECT  8.316 105.779 8.334 105.816 ;
    END
  END a[549]
  PIN a[54]
    DIRECTION INPUT ;
    USE SIGNAL ;
    PORT
      LAYER M3 ;
        RECT  40.644 105.779 40.662 105.816 ;
    END
  END a[54]
  PIN a[550]
    DIRECTION INPUT ;
    USE SIGNAL ;
    PORT
      LAYER M3 ;
        RECT  8.388 105.779 8.406 105.816 ;
    END
  END a[550]
  PIN a[551]
    DIRECTION INPUT ;
    USE SIGNAL ;
    PORT
      LAYER M3 ;
        RECT  8.46 105.779 8.478 105.816 ;
    END
  END a[551]
  PIN a[552]
    DIRECTION INPUT ;
    USE SIGNAL ;
    PORT
      LAYER M3 ;
        RECT  8.532 105.779 8.55 105.816 ;
    END
  END a[552]
  PIN a[553]
    DIRECTION INPUT ;
    USE SIGNAL ;
    PORT
      LAYER M3 ;
        RECT  8.604 105.779 8.622 105.816 ;
    END
  END a[553]
  PIN a[554]
    DIRECTION INPUT ;
    USE SIGNAL ;
    PORT
      LAYER M3 ;
        RECT  8.676 105.779 8.694 105.816 ;
    END
  END a[554]
  PIN a[555]
    DIRECTION INPUT ;
    USE SIGNAL ;
    PORT
      LAYER M3 ;
        RECT  8.748 105.779 8.766 105.816 ;
    END
  END a[555]
  PIN a[556]
    DIRECTION INPUT ;
    USE SIGNAL ;
    PORT
      LAYER M3 ;
        RECT  8.82 105.779 8.838 105.816 ;
    END
  END a[556]
  PIN a[557]
    DIRECTION INPUT ;
    USE SIGNAL ;
    PORT
      LAYER M3 ;
        RECT  8.892 105.779 8.91 105.816 ;
    END
  END a[557]
  PIN a[558]
    DIRECTION INPUT ;
    USE SIGNAL ;
    PORT
      LAYER M3 ;
        RECT  8.964 105.779 8.982 105.816 ;
    END
  END a[558]
  PIN a[559]
    DIRECTION INPUT ;
    USE SIGNAL ;
    PORT
      LAYER M3 ;
        RECT  9.036 105.779 9.054 105.816 ;
    END
  END a[559]
  PIN a[55]
    DIRECTION INPUT ;
    USE SIGNAL ;
    PORT
      LAYER M3 ;
        RECT  40.716 105.779 40.734 105.816 ;
    END
  END a[55]
  PIN a[560]
    DIRECTION INPUT ;
    USE SIGNAL ;
    PORT
      LAYER M3 ;
        RECT  9.108 105.779 9.126 105.816 ;
    END
  END a[560]
  PIN a[561]
    DIRECTION INPUT ;
    USE SIGNAL ;
    PORT
      LAYER M3 ;
        RECT  9.18 105.779 9.198 105.816 ;
    END
  END a[561]
  PIN a[562]
    DIRECTION INPUT ;
    USE SIGNAL ;
    PORT
      LAYER M3 ;
        RECT  9.252 105.779 9.27 105.816 ;
    END
  END a[562]
  PIN a[563]
    DIRECTION INPUT ;
    USE SIGNAL ;
    PORT
      LAYER M3 ;
        RECT  9.324 105.779 9.342 105.816 ;
    END
  END a[563]
  PIN a[564]
    DIRECTION INPUT ;
    USE SIGNAL ;
    PORT
      LAYER M3 ;
        RECT  9.396 105.779 9.414 105.816 ;
    END
  END a[564]
  PIN a[565]
    DIRECTION INPUT ;
    USE SIGNAL ;
    PORT
      LAYER M3 ;
        RECT  9.468 105.779 9.486 105.816 ;
    END
  END a[565]
  PIN a[566]
    DIRECTION INPUT ;
    USE SIGNAL ;
    PORT
      LAYER M3 ;
        RECT  9.54 105.779 9.558 105.816 ;
    END
  END a[566]
  PIN a[567]
    DIRECTION INPUT ;
    USE SIGNAL ;
    PORT
      LAYER M3 ;
        RECT  9.612 105.779 9.63 105.816 ;
    END
  END a[567]
  PIN a[568]
    DIRECTION INPUT ;
    USE SIGNAL ;
    PORT
      LAYER M3 ;
        RECT  9.684 105.779 9.702 105.816 ;
    END
  END a[568]
  PIN a[569]
    DIRECTION INPUT ;
    USE SIGNAL ;
    PORT
      LAYER M3 ;
        RECT  9.756 105.779 9.774 105.816 ;
    END
  END a[569]
  PIN a[56]
    DIRECTION INPUT ;
    USE SIGNAL ;
    PORT
      LAYER M3 ;
        RECT  40.788 105.779 40.806 105.816 ;
    END
  END a[56]
  PIN a[570]
    DIRECTION INPUT ;
    USE SIGNAL ;
    PORT
      LAYER M3 ;
        RECT  9.828 105.779 9.846 105.816 ;
    END
  END a[570]
  PIN a[571]
    DIRECTION INPUT ;
    USE SIGNAL ;
    PORT
      LAYER M3 ;
        RECT  9.9 105.779 9.918 105.816 ;
    END
  END a[571]
  PIN a[572]
    DIRECTION INPUT ;
    USE SIGNAL ;
    PORT
      LAYER M3 ;
        RECT  9.972 105.779 9.99 105.816 ;
    END
  END a[572]
  PIN a[573]
    DIRECTION INPUT ;
    USE SIGNAL ;
    PORT
      LAYER M3 ;
        RECT  10.044 105.779 10.062 105.816 ;
    END
  END a[573]
  PIN a[574]
    DIRECTION INPUT ;
    USE SIGNAL ;
    PORT
      LAYER M3 ;
        RECT  10.116 105.779 10.134 105.816 ;
    END
  END a[574]
  PIN a[575]
    DIRECTION INPUT ;
    USE SIGNAL ;
    PORT
      LAYER M3 ;
        RECT  10.188 105.779 10.206 105.816 ;
    END
  END a[575]
  PIN a[576]
    DIRECTION INPUT ;
    USE SIGNAL ;
    PORT
      LAYER M3 ;
        RECT  20.628 105.779 20.646 105.816 ;
    END
  END a[576]
  PIN a[577]
    DIRECTION INPUT ;
    USE SIGNAL ;
    PORT
      LAYER M3 ;
        RECT  20.7 105.779 20.718 105.816 ;
    END
  END a[577]
  PIN a[578]
    DIRECTION INPUT ;
    USE SIGNAL ;
    PORT
      LAYER M3 ;
        RECT  20.772 105.779 20.79 105.816 ;
    END
  END a[578]
  PIN a[579]
    DIRECTION INPUT ;
    USE SIGNAL ;
    PORT
      LAYER M3 ;
        RECT  20.844 105.779 20.862 105.816 ;
    END
  END a[579]
  PIN a[57]
    DIRECTION INPUT ;
    USE SIGNAL ;
    PORT
      LAYER M3 ;
        RECT  40.86 105.779 40.878 105.816 ;
    END
  END a[57]
  PIN a[580]
    DIRECTION INPUT ;
    USE SIGNAL ;
    PORT
      LAYER M3 ;
        RECT  20.916 105.779 20.934 105.816 ;
    END
  END a[580]
  PIN a[581]
    DIRECTION INPUT ;
    USE SIGNAL ;
    PORT
      LAYER M3 ;
        RECT  20.988 105.779 21.006 105.816 ;
    END
  END a[581]
  PIN a[582]
    DIRECTION INPUT ;
    USE SIGNAL ;
    PORT
      LAYER M3 ;
        RECT  21.06 105.779 21.078 105.816 ;
    END
  END a[582]
  PIN a[583]
    DIRECTION INPUT ;
    USE SIGNAL ;
    PORT
      LAYER M3 ;
        RECT  21.132 105.779 21.15 105.816 ;
    END
  END a[583]
  PIN a[584]
    DIRECTION INPUT ;
    USE SIGNAL ;
    PORT
      LAYER M3 ;
        RECT  21.204 105.779 21.222 105.816 ;
    END
  END a[584]
  PIN a[585]
    DIRECTION INPUT ;
    USE SIGNAL ;
    PORT
      LAYER M3 ;
        RECT  21.276 105.779 21.294 105.816 ;
    END
  END a[585]
  PIN a[586]
    DIRECTION INPUT ;
    USE SIGNAL ;
    PORT
      LAYER M3 ;
        RECT  21.348 105.779 21.366 105.816 ;
    END
  END a[586]
  PIN a[587]
    DIRECTION INPUT ;
    USE SIGNAL ;
    PORT
      LAYER M3 ;
        RECT  21.42 105.779 21.438 105.816 ;
    END
  END a[587]
  PIN a[588]
    DIRECTION INPUT ;
    USE SIGNAL ;
    PORT
      LAYER M3 ;
        RECT  21.492 105.779 21.51 105.816 ;
    END
  END a[588]
  PIN a[589]
    DIRECTION INPUT ;
    USE SIGNAL ;
    PORT
      LAYER M3 ;
        RECT  21.564 105.779 21.582 105.816 ;
    END
  END a[589]
  PIN a[58]
    DIRECTION INPUT ;
    USE SIGNAL ;
    PORT
      LAYER M3 ;
        RECT  40.932 105.779 40.95 105.816 ;
    END
  END a[58]
  PIN a[590]
    DIRECTION INPUT ;
    USE SIGNAL ;
    PORT
      LAYER M3 ;
        RECT  21.636 105.779 21.654 105.816 ;
    END
  END a[590]
  PIN a[591]
    DIRECTION INPUT ;
    USE SIGNAL ;
    PORT
      LAYER M3 ;
        RECT  21.708 105.779 21.726 105.816 ;
    END
  END a[591]
  PIN a[592]
    DIRECTION INPUT ;
    USE SIGNAL ;
    PORT
      LAYER M3 ;
        RECT  21.78 105.779 21.798 105.816 ;
    END
  END a[592]
  PIN a[593]
    DIRECTION INPUT ;
    USE SIGNAL ;
    PORT
      LAYER M3 ;
        RECT  21.852 105.779 21.87 105.816 ;
    END
  END a[593]
  PIN a[594]
    DIRECTION INPUT ;
    USE SIGNAL ;
    PORT
      LAYER M3 ;
        RECT  21.924 105.779 21.942 105.816 ;
    END
  END a[594]
  PIN a[595]
    DIRECTION INPUT ;
    USE SIGNAL ;
    PORT
      LAYER M3 ;
        RECT  21.996 105.779 22.014 105.816 ;
    END
  END a[595]
  PIN a[596]
    DIRECTION INPUT ;
    USE SIGNAL ;
    PORT
      LAYER M3 ;
        RECT  22.068 105.779 22.086 105.816 ;
    END
  END a[596]
  PIN a[597]
    DIRECTION INPUT ;
    USE SIGNAL ;
    PORT
      LAYER M3 ;
        RECT  22.14 105.779 22.158 105.816 ;
    END
  END a[597]
  PIN a[598]
    DIRECTION INPUT ;
    USE SIGNAL ;
    PORT
      LAYER M3 ;
        RECT  22.212 105.779 22.23 105.816 ;
    END
  END a[598]
  PIN a[599]
    DIRECTION INPUT ;
    USE SIGNAL ;
    PORT
      LAYER M3 ;
        RECT  22.284 105.779 22.302 105.816 ;
    END
  END a[599]
  PIN a[59]
    DIRECTION INPUT ;
    USE SIGNAL ;
    PORT
      LAYER M3 ;
        RECT  41.004 105.779 41.022 105.816 ;
    END
  END a[59]
  PIN a[5]
    DIRECTION INPUT ;
    USE SIGNAL ;
    PORT
      LAYER M5 ;
        RECT  34.032 105.732 34.056 105.816 ;
    END
  END a[5]
  PIN a[60]
    DIRECTION INPUT ;
    USE SIGNAL ;
    PORT
      LAYER M3 ;
        RECT  41.076 105.779 41.094 105.816 ;
    END
  END a[60]
  PIN a[61]
    DIRECTION INPUT ;
    USE SIGNAL ;
    PORT
      LAYER M3 ;
        RECT  41.148 105.779 41.166 105.816 ;
    END
  END a[61]
  PIN a[62]
    DIRECTION INPUT ;
    USE SIGNAL ;
    PORT
      LAYER M3 ;
        RECT  41.22 105.779 41.238 105.816 ;
    END
  END a[62]
  PIN a[63]
    DIRECTION INPUT ;
    USE SIGNAL ;
    PORT
      LAYER M3 ;
        RECT  41.292 105.779 41.31 105.816 ;
    END
  END a[63]
  PIN a[64]
    DIRECTION INPUT ;
    USE SIGNAL ;
    PORT
      LAYER M3 ;
        RECT  48.852 105.779 48.87 105.816 ;
    END
  END a[64]
  PIN a[65]
    DIRECTION INPUT ;
    USE SIGNAL ;
    PORT
      LAYER M3 ;
        RECT  48.924 105.779 48.942 105.816 ;
    END
  END a[65]
  PIN a[66]
    DIRECTION INPUT ;
    USE SIGNAL ;
    PORT
      LAYER M3 ;
        RECT  48.996 105.779 49.014 105.816 ;
    END
  END a[66]
  PIN a[67]
    DIRECTION INPUT ;
    USE SIGNAL ;
    PORT
      LAYER M3 ;
        RECT  49.068 105.779 49.086 105.816 ;
    END
  END a[67]
  PIN a[68]
    DIRECTION INPUT ;
    USE SIGNAL ;
    PORT
      LAYER M3 ;
        RECT  49.14 105.779 49.158 105.816 ;
    END
  END a[68]
  PIN a[69]
    DIRECTION INPUT ;
    USE SIGNAL ;
    PORT
      LAYER M3 ;
        RECT  49.212 105.779 49.23 105.816 ;
    END
  END a[69]
  PIN a[6]
    DIRECTION INPUT ;
    USE SIGNAL ;
    PORT
      LAYER M5 ;
        RECT  34.128 105.732 34.152 105.816 ;
    END
  END a[6]
  PIN a[70]
    DIRECTION INPUT ;
    USE SIGNAL ;
    PORT
      LAYER M3 ;
        RECT  49.284 105.779 49.302 105.816 ;
    END
  END a[70]
  PIN a[71]
    DIRECTION INPUT ;
    USE SIGNAL ;
    PORT
      LAYER M3 ;
        RECT  49.356 105.779 49.374 105.816 ;
    END
  END a[71]
  PIN a[72]
    DIRECTION INPUT ;
    USE SIGNAL ;
    PORT
      LAYER M3 ;
        RECT  49.428 105.779 49.446 105.816 ;
    END
  END a[72]
  PIN a[73]
    DIRECTION INPUT ;
    USE SIGNAL ;
    PORT
      LAYER M3 ;
        RECT  49.5 105.779 49.518 105.816 ;
    END
  END a[73]
  PIN a[74]
    DIRECTION INPUT ;
    USE SIGNAL ;
    PORT
      LAYER M3 ;
        RECT  49.572 105.779 49.59 105.816 ;
    END
  END a[74]
  PIN a[75]
    DIRECTION INPUT ;
    USE SIGNAL ;
    PORT
      LAYER M3 ;
        RECT  49.644 105.779 49.662 105.816 ;
    END
  END a[75]
  PIN a[76]
    DIRECTION INPUT ;
    USE SIGNAL ;
    PORT
      LAYER M3 ;
        RECT  49.716 105.779 49.734 105.816 ;
    END
  END a[76]
  PIN a[77]
    DIRECTION INPUT ;
    USE SIGNAL ;
    PORT
      LAYER M3 ;
        RECT  49.788 105.779 49.806 105.816 ;
    END
  END a[77]
  PIN a[78]
    DIRECTION INPUT ;
    USE SIGNAL ;
    PORT
      LAYER M3 ;
        RECT  49.86 105.779 49.878 105.816 ;
    END
  END a[78]
  PIN a[79]
    DIRECTION INPUT ;
    USE SIGNAL ;
    PORT
      LAYER M3 ;
        RECT  49.932 105.779 49.95 105.816 ;
    END
  END a[79]
  PIN a[7]
    DIRECTION INPUT ;
    USE SIGNAL ;
    PORT
      LAYER M5 ;
        RECT  34.224 105.732 34.248 105.816 ;
    END
  END a[7]
  PIN a[80]
    DIRECTION INPUT ;
    USE SIGNAL ;
    PORT
      LAYER M3 ;
        RECT  50.004 105.779 50.022 105.816 ;
    END
  END a[80]
  PIN a[81]
    DIRECTION INPUT ;
    USE SIGNAL ;
    PORT
      LAYER M3 ;
        RECT  50.076 105.779 50.094 105.816 ;
    END
  END a[81]
  PIN a[82]
    DIRECTION INPUT ;
    USE SIGNAL ;
    PORT
      LAYER M3 ;
        RECT  50.148 105.779 50.166 105.816 ;
    END
  END a[82]
  PIN a[83]
    DIRECTION INPUT ;
    USE SIGNAL ;
    PORT
      LAYER M3 ;
        RECT  50.22 105.779 50.238 105.816 ;
    END
  END a[83]
  PIN a[84]
    DIRECTION INPUT ;
    USE SIGNAL ;
    PORT
      LAYER M3 ;
        RECT  50.292 105.779 50.31 105.816 ;
    END
  END a[84]
  PIN a[85]
    DIRECTION INPUT ;
    USE SIGNAL ;
    PORT
      LAYER M3 ;
        RECT  50.364 105.779 50.382 105.816 ;
    END
  END a[85]
  PIN a[86]
    DIRECTION INPUT ;
    USE SIGNAL ;
    PORT
      LAYER M3 ;
        RECT  50.436 105.779 50.454 105.816 ;
    END
  END a[86]
  PIN a[87]
    DIRECTION INPUT ;
    USE SIGNAL ;
    PORT
      LAYER M3 ;
        RECT  50.508 105.779 50.526 105.816 ;
    END
  END a[87]
  PIN a[88]
    DIRECTION INPUT ;
    USE SIGNAL ;
    PORT
      LAYER M3 ;
        RECT  50.58 105.779 50.598 105.816 ;
    END
  END a[88]
  PIN a[89]
    DIRECTION INPUT ;
    USE SIGNAL ;
    PORT
      LAYER M3 ;
        RECT  50.652 105.779 50.67 105.816 ;
    END
  END a[89]
  PIN a[8]
    DIRECTION INPUT ;
    USE SIGNAL ;
    PORT
      LAYER M5 ;
        RECT  34.32 105.732 34.344 105.816 ;
    END
  END a[8]
  PIN a[90]
    DIRECTION INPUT ;
    USE SIGNAL ;
    PORT
      LAYER M3 ;
        RECT  50.724 105.779 50.742 105.816 ;
    END
  END a[90]
  PIN a[91]
    DIRECTION INPUT ;
    USE SIGNAL ;
    PORT
      LAYER M3 ;
        RECT  50.796 105.779 50.814 105.816 ;
    END
  END a[91]
  PIN a[92]
    DIRECTION INPUT ;
    USE SIGNAL ;
    PORT
      LAYER M3 ;
        RECT  50.868 105.779 50.886 105.816 ;
    END
  END a[92]
  PIN a[93]
    DIRECTION INPUT ;
    USE SIGNAL ;
    PORT
      LAYER M3 ;
        RECT  50.94 105.779 50.958 105.816 ;
    END
  END a[93]
  PIN a[94]
    DIRECTION INPUT ;
    USE SIGNAL ;
    PORT
      LAYER M3 ;
        RECT  51.012 105.779 51.03 105.816 ;
    END
  END a[94]
  PIN a[95]
    DIRECTION INPUT ;
    USE SIGNAL ;
    PORT
      LAYER M3 ;
        RECT  51.084 105.779 51.102 105.816 ;
    END
  END a[95]
  PIN a[96]
    DIRECTION INPUT ;
    USE SIGNAL ;
    PORT
      LAYER M3 ;
        RECT  60.948 105.779 60.966 105.816 ;
    END
  END a[96]
  PIN a[97]
    DIRECTION INPUT ;
    USE SIGNAL ;
    PORT
      LAYER M3 ;
        RECT  61.02 105.779 61.038 105.816 ;
    END
  END a[97]
  PIN a[98]
    DIRECTION INPUT ;
    USE SIGNAL ;
    PORT
      LAYER M3 ;
        RECT  61.092 105.779 61.11 105.816 ;
    END
  END a[98]
  PIN a[99]
    DIRECTION INPUT ;
    USE SIGNAL ;
    PORT
      LAYER M3 ;
        RECT  61.164 105.779 61.182 105.816 ;
    END
  END a[99]
  PIN a[9]
    DIRECTION INPUT ;
    USE SIGNAL ;
    PORT
      LAYER M5 ;
        RECT  34.416 105.732 34.44 105.816 ;
    END
  END a[9]
  PIN b[0]
    DIRECTION OUTPUT ;
    USE SIGNAL ;
    PORT
      LAYER M4 ;
        RECT  104.004 64.464 104.088 64.488 ;
    END
  END b[0]
  PIN b[100]
    DIRECTION OUTPUT ;
    USE SIGNAL ;
    PORT
      LAYER M4 ;
        RECT  104.004 39.504 104.088 39.528 ;
    END
  END b[100]
  PIN b[101]
    DIRECTION OUTPUT ;
    USE SIGNAL ;
    PORT
      LAYER M4 ;
        RECT  104.004 39.6 104.088 39.624 ;
    END
  END b[101]
  PIN b[102]
    DIRECTION OUTPUT ;
    USE SIGNAL ;
    PORT
      LAYER M4 ;
        RECT  104.004 39.696 104.088 39.72 ;
    END
  END b[102]
  PIN b[103]
    DIRECTION OUTPUT ;
    USE SIGNAL ;
    PORT
      LAYER M4 ;
        RECT  104.004 39.792 104.088 39.816 ;
    END
  END b[103]
  PIN b[104]
    DIRECTION OUTPUT ;
    USE SIGNAL ;
    PORT
      LAYER M4 ;
        RECT  104.004 39.888 104.088 39.912 ;
    END
  END b[104]
  PIN b[105]
    DIRECTION OUTPUT ;
    USE SIGNAL ;
    PORT
      LAYER M4 ;
        RECT  104.004 39.984 104.088 40.008 ;
    END
  END b[105]
  PIN b[106]
    DIRECTION OUTPUT ;
    USE SIGNAL ;
    PORT
      LAYER M4 ;
        RECT  104.004 40.08 104.088 40.104 ;
    END
  END b[106]
  PIN b[107]
    DIRECTION OUTPUT ;
    USE SIGNAL ;
    PORT
      LAYER M4 ;
        RECT  104.004 40.176 104.088 40.2 ;
    END
  END b[107]
  PIN b[108]
    DIRECTION OUTPUT ;
    USE SIGNAL ;
    PORT
      LAYER M4 ;
        RECT  104.004 40.272 104.088 40.296 ;
    END
  END b[108]
  PIN b[109]
    DIRECTION OUTPUT ;
    USE SIGNAL ;
    PORT
      LAYER M4 ;
        RECT  104.004 40.368 104.088 40.392 ;
    END
  END b[109]
  PIN b[10]
    DIRECTION OUTPUT ;
    USE SIGNAL ;
    PORT
      LAYER M4 ;
        RECT  104.004 65.424 104.088 65.448 ;
    END
  END b[10]
  PIN b[110]
    DIRECTION OUTPUT ;
    USE SIGNAL ;
    PORT
      LAYER M4 ;
        RECT  104.004 40.464 104.088 40.488 ;
    END
  END b[110]
  PIN b[111]
    DIRECTION OUTPUT ;
    USE SIGNAL ;
    PORT
      LAYER M4 ;
        RECT  104.004 40.56 104.088 40.584 ;
    END
  END b[111]
  PIN b[112]
    DIRECTION OUTPUT ;
    USE SIGNAL ;
    PORT
      LAYER M4 ;
        RECT  104.004 40.656 104.088 40.68 ;
    END
  END b[112]
  PIN b[113]
    DIRECTION OUTPUT ;
    USE SIGNAL ;
    PORT
      LAYER M4 ;
        RECT  104.004 40.752 104.088 40.776 ;
    END
  END b[113]
  PIN b[114]
    DIRECTION OUTPUT ;
    USE SIGNAL ;
    PORT
      LAYER M4 ;
        RECT  104.004 40.848 104.088 40.872 ;
    END
  END b[114]
  PIN b[115]
    DIRECTION OUTPUT ;
    USE SIGNAL ;
    PORT
      LAYER M4 ;
        RECT  104.004 40.944 104.088 40.968 ;
    END
  END b[115]
  PIN b[116]
    DIRECTION OUTPUT ;
    USE SIGNAL ;
    PORT
      LAYER M4 ;
        RECT  104.004 41.04 104.088 41.064 ;
    END
  END b[116]
  PIN b[117]
    DIRECTION OUTPUT ;
    USE SIGNAL ;
    PORT
      LAYER M4 ;
        RECT  104.004 41.136 104.088 41.16 ;
    END
  END b[117]
  PIN b[118]
    DIRECTION OUTPUT ;
    USE SIGNAL ;
    PORT
      LAYER M4 ;
        RECT  104.004 41.232 104.088 41.256 ;
    END
  END b[118]
  PIN b[119]
    DIRECTION OUTPUT ;
    USE SIGNAL ;
    PORT
      LAYER M4 ;
        RECT  104.004 41.328 104.088 41.352 ;
    END
  END b[119]
  PIN b[11]
    DIRECTION OUTPUT ;
    USE SIGNAL ;
    PORT
      LAYER M4 ;
        RECT  104.004 65.52 104.088 65.544 ;
    END
  END b[11]
  PIN b[120]
    DIRECTION OUTPUT ;
    USE SIGNAL ;
    PORT
      LAYER M4 ;
        RECT  104.004 41.424 104.088 41.448 ;
    END
  END b[120]
  PIN b[121]
    DIRECTION OUTPUT ;
    USE SIGNAL ;
    PORT
      LAYER M4 ;
        RECT  104.004 41.52 104.088 41.544 ;
    END
  END b[121]
  PIN b[122]
    DIRECTION OUTPUT ;
    USE SIGNAL ;
    PORT
      LAYER M4 ;
        RECT  104.004 41.616 104.088 41.64 ;
    END
  END b[122]
  PIN b[123]
    DIRECTION OUTPUT ;
    USE SIGNAL ;
    PORT
      LAYER M4 ;
        RECT  104.004 41.712 104.088 41.736 ;
    END
  END b[123]
  PIN b[124]
    DIRECTION OUTPUT ;
    USE SIGNAL ;
    PORT
      LAYER M4 ;
        RECT  104.004 41.808 104.088 41.832 ;
    END
  END b[124]
  PIN b[125]
    DIRECTION OUTPUT ;
    USE SIGNAL ;
    PORT
      LAYER M4 ;
        RECT  104.004 41.904 104.088 41.928 ;
    END
  END b[125]
  PIN b[126]
    DIRECTION OUTPUT ;
    USE SIGNAL ;
    PORT
      LAYER M4 ;
        RECT  104.004 42 104.088 42.024 ;
    END
  END b[126]
  PIN b[127]
    DIRECTION OUTPUT ;
    USE SIGNAL ;
    PORT
      LAYER M4 ;
        RECT  104.004 42.096 104.088 42.12 ;
    END
  END b[127]
  PIN b[128]
    DIRECTION OUTPUT ;
    USE SIGNAL ;
    PORT
      LAYER M4 ;
        RECT  104.004 19.92 104.088 19.944 ;
    END
  END b[128]
  PIN b[129]
    DIRECTION OUTPUT ;
    USE SIGNAL ;
    PORT
      LAYER M4 ;
        RECT  104.004 20.016 104.088 20.04 ;
    END
  END b[129]
  PIN b[12]
    DIRECTION OUTPUT ;
    USE SIGNAL ;
    PORT
      LAYER M4 ;
        RECT  104.004 65.616 104.088 65.64 ;
    END
  END b[12]
  PIN b[130]
    DIRECTION OUTPUT ;
    USE SIGNAL ;
    PORT
      LAYER M4 ;
        RECT  104.004 20.112 104.088 20.136 ;
    END
  END b[130]
  PIN b[131]
    DIRECTION OUTPUT ;
    USE SIGNAL ;
    PORT
      LAYER M4 ;
        RECT  104.004 20.208 104.088 20.232 ;
    END
  END b[131]
  PIN b[132]
    DIRECTION OUTPUT ;
    USE SIGNAL ;
    PORT
      LAYER M4 ;
        RECT  104.004 20.304 104.088 20.328 ;
    END
  END b[132]
  PIN b[133]
    DIRECTION OUTPUT ;
    USE SIGNAL ;
    PORT
      LAYER M4 ;
        RECT  104.004 20.4 104.088 20.424 ;
    END
  END b[133]
  PIN b[134]
    DIRECTION OUTPUT ;
    USE SIGNAL ;
    PORT
      LAYER M4 ;
        RECT  104.004 20.496 104.088 20.52 ;
    END
  END b[134]
  PIN b[135]
    DIRECTION OUTPUT ;
    USE SIGNAL ;
    PORT
      LAYER M4 ;
        RECT  104.004 20.592 104.088 20.616 ;
    END
  END b[135]
  PIN b[136]
    DIRECTION OUTPUT ;
    USE SIGNAL ;
    PORT
      LAYER M4 ;
        RECT  104.004 20.688 104.088 20.712 ;
    END
  END b[136]
  PIN b[137]
    DIRECTION OUTPUT ;
    USE SIGNAL ;
    PORT
      LAYER M4 ;
        RECT  104.004 20.784 104.088 20.808 ;
    END
  END b[137]
  PIN b[138]
    DIRECTION OUTPUT ;
    USE SIGNAL ;
    PORT
      LAYER M4 ;
        RECT  104.004 20.88 104.088 20.904 ;
    END
  END b[138]
  PIN b[139]
    DIRECTION OUTPUT ;
    USE SIGNAL ;
    PORT
      LAYER M4 ;
        RECT  104.004 20.976 104.088 21 ;
    END
  END b[139]
  PIN b[13]
    DIRECTION OUTPUT ;
    USE SIGNAL ;
    PORT
      LAYER M4 ;
        RECT  104.004 65.712 104.088 65.736 ;
    END
  END b[13]
  PIN b[140]
    DIRECTION OUTPUT ;
    USE SIGNAL ;
    PORT
      LAYER M4 ;
        RECT  104.004 21.072 104.088 21.096 ;
    END
  END b[140]
  PIN b[141]
    DIRECTION OUTPUT ;
    USE SIGNAL ;
    PORT
      LAYER M4 ;
        RECT  104.004 21.168 104.088 21.192 ;
    END
  END b[141]
  PIN b[142]
    DIRECTION OUTPUT ;
    USE SIGNAL ;
    PORT
      LAYER M4 ;
        RECT  104.004 21.264 104.088 21.288 ;
    END
  END b[142]
  PIN b[143]
    DIRECTION OUTPUT ;
    USE SIGNAL ;
    PORT
      LAYER M4 ;
        RECT  104.004 21.36 104.088 21.384 ;
    END
  END b[143]
  PIN b[144]
    DIRECTION OUTPUT ;
    USE SIGNAL ;
    PORT
      LAYER M4 ;
        RECT  104.004 21.456 104.088 21.48 ;
    END
  END b[144]
  PIN b[145]
    DIRECTION OUTPUT ;
    USE SIGNAL ;
    PORT
      LAYER M4 ;
        RECT  104.004 21.552 104.088 21.576 ;
    END
  END b[145]
  PIN b[146]
    DIRECTION OUTPUT ;
    USE SIGNAL ;
    PORT
      LAYER M4 ;
        RECT  104.004 21.648 104.088 21.672 ;
    END
  END b[146]
  PIN b[147]
    DIRECTION OUTPUT ;
    USE SIGNAL ;
    PORT
      LAYER M4 ;
        RECT  104.004 21.744 104.088 21.768 ;
    END
  END b[147]
  PIN b[148]
    DIRECTION OUTPUT ;
    USE SIGNAL ;
    PORT
      LAYER M4 ;
        RECT  104.004 21.84 104.088 21.864 ;
    END
  END b[148]
  PIN b[149]
    DIRECTION OUTPUT ;
    USE SIGNAL ;
    PORT
      LAYER M4 ;
        RECT  104.004 21.936 104.088 21.96 ;
    END
  END b[149]
  PIN b[14]
    DIRECTION OUTPUT ;
    USE SIGNAL ;
    PORT
      LAYER M4 ;
        RECT  104.004 65.808 104.088 65.832 ;
    END
  END b[14]
  PIN b[150]
    DIRECTION OUTPUT ;
    USE SIGNAL ;
    PORT
      LAYER M4 ;
        RECT  104.004 22.032 104.088 22.056 ;
    END
  END b[150]
  PIN b[151]
    DIRECTION OUTPUT ;
    USE SIGNAL ;
    PORT
      LAYER M4 ;
        RECT  104.004 22.128 104.088 22.152 ;
    END
  END b[151]
  PIN b[152]
    DIRECTION OUTPUT ;
    USE SIGNAL ;
    PORT
      LAYER M4 ;
        RECT  104.004 22.224 104.088 22.248 ;
    END
  END b[152]
  PIN b[153]
    DIRECTION OUTPUT ;
    USE SIGNAL ;
    PORT
      LAYER M4 ;
        RECT  104.004 22.32 104.088 22.344 ;
    END
  END b[153]
  PIN b[154]
    DIRECTION OUTPUT ;
    USE SIGNAL ;
    PORT
      LAYER M4 ;
        RECT  104.004 22.416 104.088 22.44 ;
    END
  END b[154]
  PIN b[155]
    DIRECTION OUTPUT ;
    USE SIGNAL ;
    PORT
      LAYER M4 ;
        RECT  104.004 22.512 104.088 22.536 ;
    END
  END b[155]
  PIN b[156]
    DIRECTION OUTPUT ;
    USE SIGNAL ;
    PORT
      LAYER M4 ;
        RECT  104.004 22.608 104.088 22.632 ;
    END
  END b[156]
  PIN b[157]
    DIRECTION OUTPUT ;
    USE SIGNAL ;
    PORT
      LAYER M4 ;
        RECT  104.004 22.704 104.088 22.728 ;
    END
  END b[157]
  PIN b[158]
    DIRECTION OUTPUT ;
    USE SIGNAL ;
    PORT
      LAYER M4 ;
        RECT  104.004 22.8 104.088 22.824 ;
    END
  END b[158]
  PIN b[159]
    DIRECTION OUTPUT ;
    USE SIGNAL ;
    PORT
      LAYER M4 ;
        RECT  104.004 22.896 104.088 22.92 ;
    END
  END b[159]
  PIN b[15]
    DIRECTION OUTPUT ;
    USE SIGNAL ;
    PORT
      LAYER M4 ;
        RECT  104.004 65.904 104.088 65.928 ;
    END
  END b[15]
  PIN b[160]
    DIRECTION OUTPUT ;
    USE SIGNAL ;
    PORT
      LAYER M4 ;
        RECT  104.004 29.136 104.088 29.16 ;
    END
  END b[160]
  PIN b[161]
    DIRECTION OUTPUT ;
    USE SIGNAL ;
    PORT
      LAYER M4 ;
        RECT  104.004 29.232 104.088 29.256 ;
    END
  END b[161]
  PIN b[162]
    DIRECTION OUTPUT ;
    USE SIGNAL ;
    PORT
      LAYER M4 ;
        RECT  104.004 29.328 104.088 29.352 ;
    END
  END b[162]
  PIN b[163]
    DIRECTION OUTPUT ;
    USE SIGNAL ;
    PORT
      LAYER M4 ;
        RECT  104.004 29.424 104.088 29.448 ;
    END
  END b[163]
  PIN b[164]
    DIRECTION OUTPUT ;
    USE SIGNAL ;
    PORT
      LAYER M4 ;
        RECT  104.004 29.52 104.088 29.544 ;
    END
  END b[164]
  PIN b[165]
    DIRECTION OUTPUT ;
    USE SIGNAL ;
    PORT
      LAYER M4 ;
        RECT  104.004 29.616 104.088 29.64 ;
    END
  END b[165]
  PIN b[166]
    DIRECTION OUTPUT ;
    USE SIGNAL ;
    PORT
      LAYER M4 ;
        RECT  104.004 29.712 104.088 29.736 ;
    END
  END b[166]
  PIN b[167]
    DIRECTION OUTPUT ;
    USE SIGNAL ;
    PORT
      LAYER M4 ;
        RECT  104.004 29.808 104.088 29.832 ;
    END
  END b[167]
  PIN b[168]
    DIRECTION OUTPUT ;
    USE SIGNAL ;
    PORT
      LAYER M4 ;
        RECT  104.004 29.904 104.088 29.928 ;
    END
  END b[168]
  PIN b[169]
    DIRECTION OUTPUT ;
    USE SIGNAL ;
    PORT
      LAYER M4 ;
        RECT  104.004 30 104.088 30.024 ;
    END
  END b[169]
  PIN b[16]
    DIRECTION OUTPUT ;
    USE SIGNAL ;
    PORT
      LAYER M4 ;
        RECT  104.004 66 104.088 66.024 ;
    END
  END b[16]
  PIN b[170]
    DIRECTION OUTPUT ;
    USE SIGNAL ;
    PORT
      LAYER M4 ;
        RECT  104.004 30.096 104.088 30.12 ;
    END
  END b[170]
  PIN b[171]
    DIRECTION OUTPUT ;
    USE SIGNAL ;
    PORT
      LAYER M4 ;
        RECT  104.004 30.192 104.088 30.216 ;
    END
  END b[171]
  PIN b[172]
    DIRECTION OUTPUT ;
    USE SIGNAL ;
    PORT
      LAYER M4 ;
        RECT  104.004 30.288 104.088 30.312 ;
    END
  END b[172]
  PIN b[173]
    DIRECTION OUTPUT ;
    USE SIGNAL ;
    PORT
      LAYER M4 ;
        RECT  104.004 30.384 104.088 30.408 ;
    END
  END b[173]
  PIN b[174]
    DIRECTION OUTPUT ;
    USE SIGNAL ;
    PORT
      LAYER M4 ;
        RECT  104.004 30.48 104.088 30.504 ;
    END
  END b[174]
  PIN b[175]
    DIRECTION OUTPUT ;
    USE SIGNAL ;
    PORT
      LAYER M4 ;
        RECT  104.004 30.576 104.088 30.6 ;
    END
  END b[175]
  PIN b[176]
    DIRECTION OUTPUT ;
    USE SIGNAL ;
    PORT
      LAYER M4 ;
        RECT  104.004 30.672 104.088 30.696 ;
    END
  END b[176]
  PIN b[177]
    DIRECTION OUTPUT ;
    USE SIGNAL ;
    PORT
      LAYER M4 ;
        RECT  104.004 30.768 104.088 30.792 ;
    END
  END b[177]
  PIN b[178]
    DIRECTION OUTPUT ;
    USE SIGNAL ;
    PORT
      LAYER M4 ;
        RECT  104.004 30.864 104.088 30.888 ;
    END
  END b[178]
  PIN b[179]
    DIRECTION OUTPUT ;
    USE SIGNAL ;
    PORT
      LAYER M4 ;
        RECT  104.004 30.96 104.088 30.984 ;
    END
  END b[179]
  PIN b[17]
    DIRECTION OUTPUT ;
    USE SIGNAL ;
    PORT
      LAYER M4 ;
        RECT  104.004 66.096 104.088 66.12 ;
    END
  END b[17]
  PIN b[180]
    DIRECTION OUTPUT ;
    USE SIGNAL ;
    PORT
      LAYER M4 ;
        RECT  104.004 31.056 104.088 31.08 ;
    END
  END b[180]
  PIN b[181]
    DIRECTION OUTPUT ;
    USE SIGNAL ;
    PORT
      LAYER M4 ;
        RECT  104.004 31.152 104.088 31.176 ;
    END
  END b[181]
  PIN b[182]
    DIRECTION OUTPUT ;
    USE SIGNAL ;
    PORT
      LAYER M4 ;
        RECT  104.004 31.248 104.088 31.272 ;
    END
  END b[182]
  PIN b[183]
    DIRECTION OUTPUT ;
    USE SIGNAL ;
    PORT
      LAYER M4 ;
        RECT  104.004 31.344 104.088 31.368 ;
    END
  END b[183]
  PIN b[184]
    DIRECTION OUTPUT ;
    USE SIGNAL ;
    PORT
      LAYER M4 ;
        RECT  104.004 31.44 104.088 31.464 ;
    END
  END b[184]
  PIN b[185]
    DIRECTION OUTPUT ;
    USE SIGNAL ;
    PORT
      LAYER M4 ;
        RECT  104.004 31.536 104.088 31.56 ;
    END
  END b[185]
  PIN b[186]
    DIRECTION OUTPUT ;
    USE SIGNAL ;
    PORT
      LAYER M4 ;
        RECT  104.004 31.632 104.088 31.656 ;
    END
  END b[186]
  PIN b[187]
    DIRECTION OUTPUT ;
    USE SIGNAL ;
    PORT
      LAYER M4 ;
        RECT  104.004 31.728 104.088 31.752 ;
    END
  END b[187]
  PIN b[188]
    DIRECTION OUTPUT ;
    USE SIGNAL ;
    PORT
      LAYER M4 ;
        RECT  104.004 31.824 104.088 31.848 ;
    END
  END b[188]
  PIN b[189]
    DIRECTION OUTPUT ;
    USE SIGNAL ;
    PORT
      LAYER M4 ;
        RECT  104.004 31.92 104.088 31.944 ;
    END
  END b[189]
  PIN b[18]
    DIRECTION OUTPUT ;
    USE SIGNAL ;
    PORT
      LAYER M4 ;
        RECT  104.004 66.192 104.088 66.216 ;
    END
  END b[18]
  PIN b[190]
    DIRECTION OUTPUT ;
    USE SIGNAL ;
    PORT
      LAYER M4 ;
        RECT  104.004 32.016 104.088 32.04 ;
    END
  END b[190]
  PIN b[191]
    DIRECTION OUTPUT ;
    USE SIGNAL ;
    PORT
      LAYER M4 ;
        RECT  104.004 32.112 104.088 32.136 ;
    END
  END b[191]
  PIN b[192]
    DIRECTION OUTPUT ;
    USE SIGNAL ;
    PORT
      LAYER M4 ;
        RECT  104.004 45.264 104.088 45.288 ;
    END
  END b[192]
  PIN b[193]
    DIRECTION OUTPUT ;
    USE SIGNAL ;
    PORT
      LAYER M4 ;
        RECT  104.004 45.36 104.088 45.384 ;
    END
  END b[193]
  PIN b[194]
    DIRECTION OUTPUT ;
    USE SIGNAL ;
    PORT
      LAYER M4 ;
        RECT  104.004 45.456 104.088 45.48 ;
    END
  END b[194]
  PIN b[195]
    DIRECTION OUTPUT ;
    USE SIGNAL ;
    PORT
      LAYER M4 ;
        RECT  104.004 45.552 104.088 45.576 ;
    END
  END b[195]
  PIN b[196]
    DIRECTION OUTPUT ;
    USE SIGNAL ;
    PORT
      LAYER M4 ;
        RECT  104.004 45.648 104.088 45.672 ;
    END
  END b[196]
  PIN b[197]
    DIRECTION OUTPUT ;
    USE SIGNAL ;
    PORT
      LAYER M4 ;
        RECT  104.004 45.744 104.088 45.768 ;
    END
  END b[197]
  PIN b[198]
    DIRECTION OUTPUT ;
    USE SIGNAL ;
    PORT
      LAYER M4 ;
        RECT  104.004 45.84 104.088 45.864 ;
    END
  END b[198]
  PIN b[199]
    DIRECTION OUTPUT ;
    USE SIGNAL ;
    PORT
      LAYER M4 ;
        RECT  104.004 45.936 104.088 45.96 ;
    END
  END b[199]
  PIN b[19]
    DIRECTION OUTPUT ;
    USE SIGNAL ;
    PORT
      LAYER M4 ;
        RECT  104.004 66.288 104.088 66.312 ;
    END
  END b[19]
  PIN b[1]
    DIRECTION OUTPUT ;
    USE SIGNAL ;
    PORT
      LAYER M4 ;
        RECT  104.004 64.56 104.088 64.584 ;
    END
  END b[1]
  PIN b[200]
    DIRECTION OUTPUT ;
    USE SIGNAL ;
    PORT
      LAYER M4 ;
        RECT  104.004 46.032 104.088 46.056 ;
    END
  END b[200]
  PIN b[201]
    DIRECTION OUTPUT ;
    USE SIGNAL ;
    PORT
      LAYER M4 ;
        RECT  104.004 46.128 104.088 46.152 ;
    END
  END b[201]
  PIN b[202]
    DIRECTION OUTPUT ;
    USE SIGNAL ;
    PORT
      LAYER M4 ;
        RECT  104.004 46.224 104.088 46.248 ;
    END
  END b[202]
  PIN b[203]
    DIRECTION OUTPUT ;
    USE SIGNAL ;
    PORT
      LAYER M4 ;
        RECT  104.004 46.32 104.088 46.344 ;
    END
  END b[203]
  PIN b[204]
    DIRECTION OUTPUT ;
    USE SIGNAL ;
    PORT
      LAYER M4 ;
        RECT  104.004 46.416 104.088 46.44 ;
    END
  END b[204]
  PIN b[205]
    DIRECTION OUTPUT ;
    USE SIGNAL ;
    PORT
      LAYER M4 ;
        RECT  104.004 46.512 104.088 46.536 ;
    END
  END b[205]
  PIN b[206]
    DIRECTION OUTPUT ;
    USE SIGNAL ;
    PORT
      LAYER M4 ;
        RECT  104.004 46.608 104.088 46.632 ;
    END
  END b[206]
  PIN b[207]
    DIRECTION OUTPUT ;
    USE SIGNAL ;
    PORT
      LAYER M4 ;
        RECT  104.004 46.704 104.088 46.728 ;
    END
  END b[207]
  PIN b[208]
    DIRECTION OUTPUT ;
    USE SIGNAL ;
    PORT
      LAYER M4 ;
        RECT  104.004 46.8 104.088 46.824 ;
    END
  END b[208]
  PIN b[209]
    DIRECTION OUTPUT ;
    USE SIGNAL ;
    PORT
      LAYER M4 ;
        RECT  104.004 46.896 104.088 46.92 ;
    END
  END b[209]
  PIN b[20]
    DIRECTION OUTPUT ;
    USE SIGNAL ;
    PORT
      LAYER M4 ;
        RECT  104.004 66.384 104.088 66.408 ;
    END
  END b[20]
  PIN b[210]
    DIRECTION OUTPUT ;
    USE SIGNAL ;
    PORT
      LAYER M4 ;
        RECT  104.004 46.992 104.088 47.016 ;
    END
  END b[210]
  PIN b[211]
    DIRECTION OUTPUT ;
    USE SIGNAL ;
    PORT
      LAYER M4 ;
        RECT  104.004 47.088 104.088 47.112 ;
    END
  END b[211]
  PIN b[212]
    DIRECTION OUTPUT ;
    USE SIGNAL ;
    PORT
      LAYER M4 ;
        RECT  104.004 47.184 104.088 47.208 ;
    END
  END b[212]
  PIN b[213]
    DIRECTION OUTPUT ;
    USE SIGNAL ;
    PORT
      LAYER M4 ;
        RECT  104.004 47.28 104.088 47.304 ;
    END
  END b[213]
  PIN b[214]
    DIRECTION OUTPUT ;
    USE SIGNAL ;
    PORT
      LAYER M4 ;
        RECT  104.004 47.376 104.088 47.4 ;
    END
  END b[214]
  PIN b[215]
    DIRECTION OUTPUT ;
    USE SIGNAL ;
    PORT
      LAYER M4 ;
        RECT  104.004 47.472 104.088 47.496 ;
    END
  END b[215]
  PIN b[216]
    DIRECTION OUTPUT ;
    USE SIGNAL ;
    PORT
      LAYER M4 ;
        RECT  104.004 47.568 104.088 47.592 ;
    END
  END b[216]
  PIN b[217]
    DIRECTION OUTPUT ;
    USE SIGNAL ;
    PORT
      LAYER M4 ;
        RECT  104.004 47.664 104.088 47.688 ;
    END
  END b[217]
  PIN b[218]
    DIRECTION OUTPUT ;
    USE SIGNAL ;
    PORT
      LAYER M4 ;
        RECT  104.004 47.76 104.088 47.784 ;
    END
  END b[218]
  PIN b[219]
    DIRECTION OUTPUT ;
    USE SIGNAL ;
    PORT
      LAYER M4 ;
        RECT  104.004 47.856 104.088 47.88 ;
    END
  END b[219]
  PIN b[21]
    DIRECTION OUTPUT ;
    USE SIGNAL ;
    PORT
      LAYER M4 ;
        RECT  104.004 66.48 104.088 66.504 ;
    END
  END b[21]
  PIN b[220]
    DIRECTION OUTPUT ;
    USE SIGNAL ;
    PORT
      LAYER M4 ;
        RECT  104.004 47.952 104.088 47.976 ;
    END
  END b[220]
  PIN b[221]
    DIRECTION OUTPUT ;
    USE SIGNAL ;
    PORT
      LAYER M4 ;
        RECT  104.004 48.048 104.088 48.072 ;
    END
  END b[221]
  PIN b[222]
    DIRECTION OUTPUT ;
    USE SIGNAL ;
    PORT
      LAYER M4 ;
        RECT  104.004 48.144 104.088 48.168 ;
    END
  END b[222]
  PIN b[223]
    DIRECTION OUTPUT ;
    USE SIGNAL ;
    PORT
      LAYER M4 ;
        RECT  104.004 48.24 104.088 48.264 ;
    END
  END b[223]
  PIN b[224]
    DIRECTION OUTPUT ;
    USE SIGNAL ;
    PORT
      LAYER M4 ;
        RECT  104.004 54.48 104.088 54.504 ;
    END
  END b[224]
  PIN b[225]
    DIRECTION OUTPUT ;
    USE SIGNAL ;
    PORT
      LAYER M4 ;
        RECT  104.004 54.576 104.088 54.6 ;
    END
  END b[225]
  PIN b[226]
    DIRECTION OUTPUT ;
    USE SIGNAL ;
    PORT
      LAYER M4 ;
        RECT  104.004 54.672 104.088 54.696 ;
    END
  END b[226]
  PIN b[227]
    DIRECTION OUTPUT ;
    USE SIGNAL ;
    PORT
      LAYER M4 ;
        RECT  104.004 54.768 104.088 54.792 ;
    END
  END b[227]
  PIN b[228]
    DIRECTION OUTPUT ;
    USE SIGNAL ;
    PORT
      LAYER M4 ;
        RECT  104.004 54.864 104.088 54.888 ;
    END
  END b[228]
  PIN b[229]
    DIRECTION OUTPUT ;
    USE SIGNAL ;
    PORT
      LAYER M4 ;
        RECT  104.004 54.96 104.088 54.984 ;
    END
  END b[229]
  PIN b[22]
    DIRECTION OUTPUT ;
    USE SIGNAL ;
    PORT
      LAYER M4 ;
        RECT  104.004 66.576 104.088 66.6 ;
    END
  END b[22]
  PIN b[230]
    DIRECTION OUTPUT ;
    USE SIGNAL ;
    PORT
      LAYER M4 ;
        RECT  104.004 55.056 104.088 55.08 ;
    END
  END b[230]
  PIN b[231]
    DIRECTION OUTPUT ;
    USE SIGNAL ;
    PORT
      LAYER M4 ;
        RECT  104.004 55.152 104.088 55.176 ;
    END
  END b[231]
  PIN b[232]
    DIRECTION OUTPUT ;
    USE SIGNAL ;
    PORT
      LAYER M4 ;
        RECT  104.004 55.248 104.088 55.272 ;
    END
  END b[232]
  PIN b[233]
    DIRECTION OUTPUT ;
    USE SIGNAL ;
    PORT
      LAYER M4 ;
        RECT  104.004 55.344 104.088 55.368 ;
    END
  END b[233]
  PIN b[234]
    DIRECTION OUTPUT ;
    USE SIGNAL ;
    PORT
      LAYER M4 ;
        RECT  104.004 55.44 104.088 55.464 ;
    END
  END b[234]
  PIN b[235]
    DIRECTION OUTPUT ;
    USE SIGNAL ;
    PORT
      LAYER M4 ;
        RECT  104.004 55.536 104.088 55.56 ;
    END
  END b[235]
  PIN b[236]
    DIRECTION OUTPUT ;
    USE SIGNAL ;
    PORT
      LAYER M4 ;
        RECT  104.004 55.632 104.088 55.656 ;
    END
  END b[236]
  PIN b[237]
    DIRECTION OUTPUT ;
    USE SIGNAL ;
    PORT
      LAYER M4 ;
        RECT  104.004 55.728 104.088 55.752 ;
    END
  END b[237]
  PIN b[238]
    DIRECTION OUTPUT ;
    USE SIGNAL ;
    PORT
      LAYER M4 ;
        RECT  104.004 55.824 104.088 55.848 ;
    END
  END b[238]
  PIN b[239]
    DIRECTION OUTPUT ;
    USE SIGNAL ;
    PORT
      LAYER M4 ;
        RECT  104.004 55.92 104.088 55.944 ;
    END
  END b[239]
  PIN b[23]
    DIRECTION OUTPUT ;
    USE SIGNAL ;
    PORT
      LAYER M4 ;
        RECT  104.004 66.672 104.088 66.696 ;
    END
  END b[23]
  PIN b[240]
    DIRECTION OUTPUT ;
    USE SIGNAL ;
    PORT
      LAYER M4 ;
        RECT  104.004 56.016 104.088 56.04 ;
    END
  END b[240]
  PIN b[241]
    DIRECTION OUTPUT ;
    USE SIGNAL ;
    PORT
      LAYER M4 ;
        RECT  104.004 56.112 104.088 56.136 ;
    END
  END b[241]
  PIN b[242]
    DIRECTION OUTPUT ;
    USE SIGNAL ;
    PORT
      LAYER M4 ;
        RECT  104.004 56.208 104.088 56.232 ;
    END
  END b[242]
  PIN b[243]
    DIRECTION OUTPUT ;
    USE SIGNAL ;
    PORT
      LAYER M4 ;
        RECT  104.004 56.304 104.088 56.328 ;
    END
  END b[243]
  PIN b[244]
    DIRECTION OUTPUT ;
    USE SIGNAL ;
    PORT
      LAYER M4 ;
        RECT  104.004 56.4 104.088 56.424 ;
    END
  END b[244]
  PIN b[245]
    DIRECTION OUTPUT ;
    USE SIGNAL ;
    PORT
      LAYER M4 ;
        RECT  104.004 56.496 104.088 56.52 ;
    END
  END b[245]
  PIN b[246]
    DIRECTION OUTPUT ;
    USE SIGNAL ;
    PORT
      LAYER M4 ;
        RECT  104.004 56.592 104.088 56.616 ;
    END
  END b[246]
  PIN b[247]
    DIRECTION OUTPUT ;
    USE SIGNAL ;
    PORT
      LAYER M4 ;
        RECT  104.004 56.688 104.088 56.712 ;
    END
  END b[247]
  PIN b[248]
    DIRECTION OUTPUT ;
    USE SIGNAL ;
    PORT
      LAYER M4 ;
        RECT  104.004 56.784 104.088 56.808 ;
    END
  END b[248]
  PIN b[249]
    DIRECTION OUTPUT ;
    USE SIGNAL ;
    PORT
      LAYER M4 ;
        RECT  104.004 56.88 104.088 56.904 ;
    END
  END b[249]
  PIN b[24]
    DIRECTION OUTPUT ;
    USE SIGNAL ;
    PORT
      LAYER M4 ;
        RECT  104.004 66.768 104.088 66.792 ;
    END
  END b[24]
  PIN b[250]
    DIRECTION OUTPUT ;
    USE SIGNAL ;
    PORT
      LAYER M4 ;
        RECT  104.004 56.976 104.088 57 ;
    END
  END b[250]
  PIN b[251]
    DIRECTION OUTPUT ;
    USE SIGNAL ;
    PORT
      LAYER M4 ;
        RECT  104.004 57.072 104.088 57.096 ;
    END
  END b[251]
  PIN b[252]
    DIRECTION OUTPUT ;
    USE SIGNAL ;
    PORT
      LAYER M4 ;
        RECT  104.004 57.168 104.088 57.192 ;
    END
  END b[252]
  PIN b[253]
    DIRECTION OUTPUT ;
    USE SIGNAL ;
    PORT
      LAYER M4 ;
        RECT  104.004 57.264 104.088 57.288 ;
    END
  END b[253]
  PIN b[254]
    DIRECTION OUTPUT ;
    USE SIGNAL ;
    PORT
      LAYER M4 ;
        RECT  104.004 57.36 104.088 57.384 ;
    END
  END b[254]
  PIN b[255]
    DIRECTION OUTPUT ;
    USE SIGNAL ;
    PORT
      LAYER M4 ;
        RECT  104.004 57.456 104.088 57.48 ;
    END
  END b[255]
  PIN b[256]
    DIRECTION OUTPUT ;
    USE SIGNAL ;
    PORT
      LAYER M4 ;
        RECT  104.004 67.536 104.088 67.56 ;
    END
  END b[256]
  PIN b[257]
    DIRECTION OUTPUT ;
    USE SIGNAL ;
    PORT
      LAYER M4 ;
        RECT  104.004 67.632 104.088 67.656 ;
    END
  END b[257]
  PIN b[258]
    DIRECTION OUTPUT ;
    USE SIGNAL ;
    PORT
      LAYER M4 ;
        RECT  104.004 67.728 104.088 67.752 ;
    END
  END b[258]
  PIN b[259]
    DIRECTION OUTPUT ;
    USE SIGNAL ;
    PORT
      LAYER M4 ;
        RECT  104.004 67.824 104.088 67.848 ;
    END
  END b[259]
  PIN b[25]
    DIRECTION OUTPUT ;
    USE SIGNAL ;
    PORT
      LAYER M4 ;
        RECT  104.004 66.864 104.088 66.888 ;
    END
  END b[25]
  PIN b[260]
    DIRECTION OUTPUT ;
    USE SIGNAL ;
    PORT
      LAYER M4 ;
        RECT  104.004 67.92 104.088 67.944 ;
    END
  END b[260]
  PIN b[261]
    DIRECTION OUTPUT ;
    USE SIGNAL ;
    PORT
      LAYER M4 ;
        RECT  104.004 68.016 104.088 68.04 ;
    END
  END b[261]
  PIN b[262]
    DIRECTION OUTPUT ;
    USE SIGNAL ;
    PORT
      LAYER M4 ;
        RECT  104.004 68.112 104.088 68.136 ;
    END
  END b[262]
  PIN b[263]
    DIRECTION OUTPUT ;
    USE SIGNAL ;
    PORT
      LAYER M4 ;
        RECT  104.004 68.208 104.088 68.232 ;
    END
  END b[263]
  PIN b[264]
    DIRECTION OUTPUT ;
    USE SIGNAL ;
    PORT
      LAYER M4 ;
        RECT  104.004 68.304 104.088 68.328 ;
    END
  END b[264]
  PIN b[265]
    DIRECTION OUTPUT ;
    USE SIGNAL ;
    PORT
      LAYER M4 ;
        RECT  104.004 68.4 104.088 68.424 ;
    END
  END b[265]
  PIN b[266]
    DIRECTION OUTPUT ;
    USE SIGNAL ;
    PORT
      LAYER M4 ;
        RECT  104.004 68.496 104.088 68.52 ;
    END
  END b[266]
  PIN b[267]
    DIRECTION OUTPUT ;
    USE SIGNAL ;
    PORT
      LAYER M4 ;
        RECT  104.004 68.592 104.088 68.616 ;
    END
  END b[267]
  PIN b[268]
    DIRECTION OUTPUT ;
    USE SIGNAL ;
    PORT
      LAYER M4 ;
        RECT  104.004 68.688 104.088 68.712 ;
    END
  END b[268]
  PIN b[269]
    DIRECTION OUTPUT ;
    USE SIGNAL ;
    PORT
      LAYER M4 ;
        RECT  104.004 68.784 104.088 68.808 ;
    END
  END b[269]
  PIN b[26]
    DIRECTION OUTPUT ;
    USE SIGNAL ;
    PORT
      LAYER M4 ;
        RECT  104.004 66.96 104.088 66.984 ;
    END
  END b[26]
  PIN b[270]
    DIRECTION OUTPUT ;
    USE SIGNAL ;
    PORT
      LAYER M4 ;
        RECT  104.004 68.88 104.088 68.904 ;
    END
  END b[270]
  PIN b[271]
    DIRECTION OUTPUT ;
    USE SIGNAL ;
    PORT
      LAYER M4 ;
        RECT  104.004 68.976 104.088 69 ;
    END
  END b[271]
  PIN b[272]
    DIRECTION OUTPUT ;
    USE SIGNAL ;
    PORT
      LAYER M4 ;
        RECT  104.004 69.072 104.088 69.096 ;
    END
  END b[272]
  PIN b[273]
    DIRECTION OUTPUT ;
    USE SIGNAL ;
    PORT
      LAYER M4 ;
        RECT  104.004 69.168 104.088 69.192 ;
    END
  END b[273]
  PIN b[274]
    DIRECTION OUTPUT ;
    USE SIGNAL ;
    PORT
      LAYER M4 ;
        RECT  104.004 69.264 104.088 69.288 ;
    END
  END b[274]
  PIN b[275]
    DIRECTION OUTPUT ;
    USE SIGNAL ;
    PORT
      LAYER M4 ;
        RECT  104.004 69.36 104.088 69.384 ;
    END
  END b[275]
  PIN b[276]
    DIRECTION OUTPUT ;
    USE SIGNAL ;
    PORT
      LAYER M4 ;
        RECT  104.004 69.456 104.088 69.48 ;
    END
  END b[276]
  PIN b[277]
    DIRECTION OUTPUT ;
    USE SIGNAL ;
    PORT
      LAYER M4 ;
        RECT  104.004 69.552 104.088 69.576 ;
    END
  END b[277]
  PIN b[278]
    DIRECTION OUTPUT ;
    USE SIGNAL ;
    PORT
      LAYER M4 ;
        RECT  104.004 69.648 104.088 69.672 ;
    END
  END b[278]
  PIN b[279]
    DIRECTION OUTPUT ;
    USE SIGNAL ;
    PORT
      LAYER M4 ;
        RECT  104.004 69.744 104.088 69.768 ;
    END
  END b[279]
  PIN b[27]
    DIRECTION OUTPUT ;
    USE SIGNAL ;
    PORT
      LAYER M4 ;
        RECT  104.004 67.056 104.088 67.08 ;
    END
  END b[27]
  PIN b[280]
    DIRECTION OUTPUT ;
    USE SIGNAL ;
    PORT
      LAYER M4 ;
        RECT  104.004 69.84 104.088 69.864 ;
    END
  END b[280]
  PIN b[281]
    DIRECTION OUTPUT ;
    USE SIGNAL ;
    PORT
      LAYER M4 ;
        RECT  104.004 69.936 104.088 69.96 ;
    END
  END b[281]
  PIN b[282]
    DIRECTION OUTPUT ;
    USE SIGNAL ;
    PORT
      LAYER M4 ;
        RECT  104.004 70.032 104.088 70.056 ;
    END
  END b[282]
  PIN b[283]
    DIRECTION OUTPUT ;
    USE SIGNAL ;
    PORT
      LAYER M4 ;
        RECT  104.004 70.128 104.088 70.152 ;
    END
  END b[283]
  PIN b[284]
    DIRECTION OUTPUT ;
    USE SIGNAL ;
    PORT
      LAYER M4 ;
        RECT  104.004 70.224 104.088 70.248 ;
    END
  END b[284]
  PIN b[285]
    DIRECTION OUTPUT ;
    USE SIGNAL ;
    PORT
      LAYER M4 ;
        RECT  104.004 70.32 104.088 70.344 ;
    END
  END b[285]
  PIN b[286]
    DIRECTION OUTPUT ;
    USE SIGNAL ;
    PORT
      LAYER M4 ;
        RECT  104.004 70.416 104.088 70.44 ;
    END
  END b[286]
  PIN b[287]
    DIRECTION OUTPUT ;
    USE SIGNAL ;
    PORT
      LAYER M4 ;
        RECT  104.004 70.512 104.088 70.536 ;
    END
  END b[287]
  PIN b[288]
    DIRECTION OUTPUT ;
    USE SIGNAL ;
    PORT
      LAYER M4 ;
        RECT  104.004 70.608 104.088 70.632 ;
    END
  END b[288]
  PIN b[289]
    DIRECTION OUTPUT ;
    USE SIGNAL ;
    PORT
      LAYER M4 ;
        RECT  104.004 70.704 104.088 70.728 ;
    END
  END b[289]
  PIN b[28]
    DIRECTION OUTPUT ;
    USE SIGNAL ;
    PORT
      LAYER M4 ;
        RECT  104.004 67.152 104.088 67.176 ;
    END
  END b[28]
  PIN b[290]
    DIRECTION OUTPUT ;
    USE SIGNAL ;
    PORT
      LAYER M4 ;
        RECT  104.004 70.8 104.088 70.824 ;
    END
  END b[290]
  PIN b[291]
    DIRECTION OUTPUT ;
    USE SIGNAL ;
    PORT
      LAYER M4 ;
        RECT  104.004 70.896 104.088 70.92 ;
    END
  END b[291]
  PIN b[292]
    DIRECTION OUTPUT ;
    USE SIGNAL ;
    PORT
      LAYER M4 ;
        RECT  104.004 70.992 104.088 71.016 ;
    END
  END b[292]
  PIN b[293]
    DIRECTION OUTPUT ;
    USE SIGNAL ;
    PORT
      LAYER M4 ;
        RECT  104.004 71.088 104.088 71.112 ;
    END
  END b[293]
  PIN b[294]
    DIRECTION OUTPUT ;
    USE SIGNAL ;
    PORT
      LAYER M4 ;
        RECT  104.004 71.184 104.088 71.208 ;
    END
  END b[294]
  PIN b[295]
    DIRECTION OUTPUT ;
    USE SIGNAL ;
    PORT
      LAYER M4 ;
        RECT  104.004 71.28 104.088 71.304 ;
    END
  END b[295]
  PIN b[296]
    DIRECTION OUTPUT ;
    USE SIGNAL ;
    PORT
      LAYER M4 ;
        RECT  104.004 71.376 104.088 71.4 ;
    END
  END b[296]
  PIN b[297]
    DIRECTION OUTPUT ;
    USE SIGNAL ;
    PORT
      LAYER M4 ;
        RECT  104.004 71.472 104.088 71.496 ;
    END
  END b[297]
  PIN b[298]
    DIRECTION OUTPUT ;
    USE SIGNAL ;
    PORT
      LAYER M4 ;
        RECT  104.004 71.568 104.088 71.592 ;
    END
  END b[298]
  PIN b[299]
    DIRECTION OUTPUT ;
    USE SIGNAL ;
    PORT
      LAYER M4 ;
        RECT  104.004 71.664 104.088 71.688 ;
    END
  END b[299]
  PIN b[29]
    DIRECTION OUTPUT ;
    USE SIGNAL ;
    PORT
      LAYER M4 ;
        RECT  104.004 67.248 104.088 67.272 ;
    END
  END b[29]
  PIN b[2]
    DIRECTION OUTPUT ;
    USE SIGNAL ;
    PORT
      LAYER M4 ;
        RECT  104.004 64.656 104.088 64.68 ;
    END
  END b[2]
  PIN b[300]
    DIRECTION OUTPUT ;
    USE SIGNAL ;
    PORT
      LAYER M4 ;
        RECT  104.004 71.76 104.088 71.784 ;
    END
  END b[300]
  PIN b[301]
    DIRECTION OUTPUT ;
    USE SIGNAL ;
    PORT
      LAYER M4 ;
        RECT  104.004 71.856 104.088 71.88 ;
    END
  END b[301]
  PIN b[302]
    DIRECTION OUTPUT ;
    USE SIGNAL ;
    PORT
      LAYER M4 ;
        RECT  104.004 71.952 104.088 71.976 ;
    END
  END b[302]
  PIN b[303]
    DIRECTION OUTPUT ;
    USE SIGNAL ;
    PORT
      LAYER M4 ;
        RECT  104.004 72.048 104.088 72.072 ;
    END
  END b[303]
  PIN b[304]
    DIRECTION OUTPUT ;
    USE SIGNAL ;
    PORT
      LAYER M4 ;
        RECT  104.004 72.144 104.088 72.168 ;
    END
  END b[304]
  PIN b[305]
    DIRECTION OUTPUT ;
    USE SIGNAL ;
    PORT
      LAYER M4 ;
        RECT  104.004 72.24 104.088 72.264 ;
    END
  END b[305]
  PIN b[306]
    DIRECTION OUTPUT ;
    USE SIGNAL ;
    PORT
      LAYER M4 ;
        RECT  104.004 72.336 104.088 72.36 ;
    END
  END b[306]
  PIN b[307]
    DIRECTION OUTPUT ;
    USE SIGNAL ;
    PORT
      LAYER M4 ;
        RECT  104.004 72.432 104.088 72.456 ;
    END
  END b[307]
  PIN b[308]
    DIRECTION OUTPUT ;
    USE SIGNAL ;
    PORT
      LAYER M4 ;
        RECT  104.004 72.528 104.088 72.552 ;
    END
  END b[308]
  PIN b[309]
    DIRECTION OUTPUT ;
    USE SIGNAL ;
    PORT
      LAYER M4 ;
        RECT  104.004 72.624 104.088 72.648 ;
    END
  END b[309]
  PIN b[30]
    DIRECTION OUTPUT ;
    USE SIGNAL ;
    PORT
      LAYER M4 ;
        RECT  104.004 67.344 104.088 67.368 ;
    END
  END b[30]
  PIN b[310]
    DIRECTION OUTPUT ;
    USE SIGNAL ;
    PORT
      LAYER M4 ;
        RECT  104.004 72.72 104.088 72.744 ;
    END
  END b[310]
  PIN b[311]
    DIRECTION OUTPUT ;
    USE SIGNAL ;
    PORT
      LAYER M4 ;
        RECT  104.004 72.816 104.088 72.84 ;
    END
  END b[311]
  PIN b[312]
    DIRECTION OUTPUT ;
    USE SIGNAL ;
    PORT
      LAYER M4 ;
        RECT  104.004 72.912 104.088 72.936 ;
    END
  END b[312]
  PIN b[313]
    DIRECTION OUTPUT ;
    USE SIGNAL ;
    PORT
      LAYER M4 ;
        RECT  104.004 73.008 104.088 73.032 ;
    END
  END b[313]
  PIN b[314]
    DIRECTION OUTPUT ;
    USE SIGNAL ;
    PORT
      LAYER M4 ;
        RECT  104.004 73.104 104.088 73.128 ;
    END
  END b[314]
  PIN b[315]
    DIRECTION OUTPUT ;
    USE SIGNAL ;
    PORT
      LAYER M4 ;
        RECT  104.004 73.2 104.088 73.224 ;
    END
  END b[315]
  PIN b[316]
    DIRECTION OUTPUT ;
    USE SIGNAL ;
    PORT
      LAYER M4 ;
        RECT  104.004 73.296 104.088 73.32 ;
    END
  END b[316]
  PIN b[317]
    DIRECTION OUTPUT ;
    USE SIGNAL ;
    PORT
      LAYER M4 ;
        RECT  104.004 73.392 104.088 73.416 ;
    END
  END b[317]
  PIN b[318]
    DIRECTION OUTPUT ;
    USE SIGNAL ;
    PORT
      LAYER M4 ;
        RECT  104.004 73.488 104.088 73.512 ;
    END
  END b[318]
  PIN b[319]
    DIRECTION OUTPUT ;
    USE SIGNAL ;
    PORT
      LAYER M4 ;
        RECT  104.004 73.584 104.088 73.608 ;
    END
  END b[319]
  PIN b[31]
    DIRECTION OUTPUT ;
    USE SIGNAL ;
    PORT
      LAYER M4 ;
        RECT  104.004 67.44 104.088 67.464 ;
    END
  END b[31]
  PIN b[320]
    DIRECTION OUTPUT ;
    USE SIGNAL ;
    PORT
      LAYER M4 ;
        RECT  104.004 83.664 104.088 83.688 ;
    END
  END b[320]
  PIN b[321]
    DIRECTION OUTPUT ;
    USE SIGNAL ;
    PORT
      LAYER M4 ;
        RECT  104.004 83.76 104.088 83.784 ;
    END
  END b[321]
  PIN b[322]
    DIRECTION OUTPUT ;
    USE SIGNAL ;
    PORT
      LAYER M4 ;
        RECT  104.004 83.856 104.088 83.88 ;
    END
  END b[322]
  PIN b[323]
    DIRECTION OUTPUT ;
    USE SIGNAL ;
    PORT
      LAYER M4 ;
        RECT  104.004 83.952 104.088 83.976 ;
    END
  END b[323]
  PIN b[324]
    DIRECTION OUTPUT ;
    USE SIGNAL ;
    PORT
      LAYER M4 ;
        RECT  104.004 84.048 104.088 84.072 ;
    END
  END b[324]
  PIN b[325]
    DIRECTION OUTPUT ;
    USE SIGNAL ;
    PORT
      LAYER M4 ;
        RECT  104.004 84.144 104.088 84.168 ;
    END
  END b[325]
  PIN b[326]
    DIRECTION OUTPUT ;
    USE SIGNAL ;
    PORT
      LAYER M4 ;
        RECT  104.004 84.24 104.088 84.264 ;
    END
  END b[326]
  PIN b[327]
    DIRECTION OUTPUT ;
    USE SIGNAL ;
    PORT
      LAYER M4 ;
        RECT  104.004 84.336 104.088 84.36 ;
    END
  END b[327]
  PIN b[328]
    DIRECTION OUTPUT ;
    USE SIGNAL ;
    PORT
      LAYER M4 ;
        RECT  104.004 84.432 104.088 84.456 ;
    END
  END b[328]
  PIN b[329]
    DIRECTION OUTPUT ;
    USE SIGNAL ;
    PORT
      LAYER M4 ;
        RECT  104.004 84.528 104.088 84.552 ;
    END
  END b[329]
  PIN b[32]
    DIRECTION OUTPUT ;
    USE SIGNAL ;
    PORT
      LAYER M4 ;
        RECT  104.004 42.192 104.088 42.216 ;
    END
  END b[32]
  PIN b[330]
    DIRECTION OUTPUT ;
    USE SIGNAL ;
    PORT
      LAYER M4 ;
        RECT  104.004 84.624 104.088 84.648 ;
    END
  END b[330]
  PIN b[331]
    DIRECTION OUTPUT ;
    USE SIGNAL ;
    PORT
      LAYER M4 ;
        RECT  104.004 84.72 104.088 84.744 ;
    END
  END b[331]
  PIN b[332]
    DIRECTION OUTPUT ;
    USE SIGNAL ;
    PORT
      LAYER M4 ;
        RECT  104.004 84.816 104.088 84.84 ;
    END
  END b[332]
  PIN b[333]
    DIRECTION OUTPUT ;
    USE SIGNAL ;
    PORT
      LAYER M4 ;
        RECT  104.004 84.912 104.088 84.936 ;
    END
  END b[333]
  PIN b[334]
    DIRECTION OUTPUT ;
    USE SIGNAL ;
    PORT
      LAYER M4 ;
        RECT  104.004 85.008 104.088 85.032 ;
    END
  END b[334]
  PIN b[335]
    DIRECTION OUTPUT ;
    USE SIGNAL ;
    PORT
      LAYER M4 ;
        RECT  104.004 85.104 104.088 85.128 ;
    END
  END b[335]
  PIN b[336]
    DIRECTION OUTPUT ;
    USE SIGNAL ;
    PORT
      LAYER M4 ;
        RECT  104.004 85.2 104.088 85.224 ;
    END
  END b[336]
  PIN b[337]
    DIRECTION OUTPUT ;
    USE SIGNAL ;
    PORT
      LAYER M4 ;
        RECT  104.004 85.296 104.088 85.32 ;
    END
  END b[337]
  PIN b[338]
    DIRECTION OUTPUT ;
    USE SIGNAL ;
    PORT
      LAYER M4 ;
        RECT  104.004 85.392 104.088 85.416 ;
    END
  END b[338]
  PIN b[339]
    DIRECTION OUTPUT ;
    USE SIGNAL ;
    PORT
      LAYER M4 ;
        RECT  104.004 85.488 104.088 85.512 ;
    END
  END b[339]
  PIN b[33]
    DIRECTION OUTPUT ;
    USE SIGNAL ;
    PORT
      LAYER M4 ;
        RECT  104.004 42.288 104.088 42.312 ;
    END
  END b[33]
  PIN b[340]
    DIRECTION OUTPUT ;
    USE SIGNAL ;
    PORT
      LAYER M4 ;
        RECT  104.004 85.584 104.088 85.608 ;
    END
  END b[340]
  PIN b[341]
    DIRECTION OUTPUT ;
    USE SIGNAL ;
    PORT
      LAYER M4 ;
        RECT  104.004 85.68 104.088 85.704 ;
    END
  END b[341]
  PIN b[342]
    DIRECTION OUTPUT ;
    USE SIGNAL ;
    PORT
      LAYER M4 ;
        RECT  104.004 85.776 104.088 85.8 ;
    END
  END b[342]
  PIN b[343]
    DIRECTION OUTPUT ;
    USE SIGNAL ;
    PORT
      LAYER M4 ;
        RECT  104.004 85.872 104.088 85.896 ;
    END
  END b[343]
  PIN b[344]
    DIRECTION OUTPUT ;
    USE SIGNAL ;
    PORT
      LAYER M4 ;
        RECT  104.004 85.968 104.088 85.992 ;
    END
  END b[344]
  PIN b[345]
    DIRECTION OUTPUT ;
    USE SIGNAL ;
    PORT
      LAYER M4 ;
        RECT  104.004 86.064 104.088 86.088 ;
    END
  END b[345]
  PIN b[346]
    DIRECTION OUTPUT ;
    USE SIGNAL ;
    PORT
      LAYER M4 ;
        RECT  104.004 86.16 104.088 86.184 ;
    END
  END b[346]
  PIN b[347]
    DIRECTION OUTPUT ;
    USE SIGNAL ;
    PORT
      LAYER M4 ;
        RECT  104.004 86.256 104.088 86.28 ;
    END
  END b[347]
  PIN b[348]
    DIRECTION OUTPUT ;
    USE SIGNAL ;
    PORT
      LAYER M4 ;
        RECT  104.004 86.352 104.088 86.376 ;
    END
  END b[348]
  PIN b[349]
    DIRECTION OUTPUT ;
    USE SIGNAL ;
    PORT
      LAYER M4 ;
        RECT  104.004 86.448 104.088 86.472 ;
    END
  END b[349]
  PIN b[34]
    DIRECTION OUTPUT ;
    USE SIGNAL ;
    PORT
      LAYER M4 ;
        RECT  104.004 42.384 104.088 42.408 ;
    END
  END b[34]
  PIN b[350]
    DIRECTION OUTPUT ;
    USE SIGNAL ;
    PORT
      LAYER M4 ;
        RECT  104.004 86.544 104.088 86.568 ;
    END
  END b[350]
  PIN b[351]
    DIRECTION OUTPUT ;
    USE SIGNAL ;
    PORT
      LAYER M4 ;
        RECT  104.004 86.64 104.088 86.664 ;
    END
  END b[351]
  PIN b[352]
    DIRECTION OUTPUT ;
    USE SIGNAL ;
    PORT
      LAYER M4 ;
        RECT  104.004 73.68 104.088 73.704 ;
    END
  END b[352]
  PIN b[353]
    DIRECTION OUTPUT ;
    USE SIGNAL ;
    PORT
      LAYER M4 ;
        RECT  104.004 73.776 104.088 73.8 ;
    END
  END b[353]
  PIN b[354]
    DIRECTION OUTPUT ;
    USE SIGNAL ;
    PORT
      LAYER M4 ;
        RECT  104.004 73.872 104.088 73.896 ;
    END
  END b[354]
  PIN b[355]
    DIRECTION OUTPUT ;
    USE SIGNAL ;
    PORT
      LAYER M4 ;
        RECT  104.004 73.968 104.088 73.992 ;
    END
  END b[355]
  PIN b[356]
    DIRECTION OUTPUT ;
    USE SIGNAL ;
    PORT
      LAYER M4 ;
        RECT  104.004 74.064 104.088 74.088 ;
    END
  END b[356]
  PIN b[357]
    DIRECTION OUTPUT ;
    USE SIGNAL ;
    PORT
      LAYER M4 ;
        RECT  104.004 74.16 104.088 74.184 ;
    END
  END b[357]
  PIN b[358]
    DIRECTION OUTPUT ;
    USE SIGNAL ;
    PORT
      LAYER M4 ;
        RECT  104.004 74.256 104.088 74.28 ;
    END
  END b[358]
  PIN b[359]
    DIRECTION OUTPUT ;
    USE SIGNAL ;
    PORT
      LAYER M4 ;
        RECT  104.004 74.352 104.088 74.376 ;
    END
  END b[359]
  PIN b[35]
    DIRECTION OUTPUT ;
    USE SIGNAL ;
    PORT
      LAYER M4 ;
        RECT  104.004 42.48 104.088 42.504 ;
    END
  END b[35]
  PIN b[360]
    DIRECTION OUTPUT ;
    USE SIGNAL ;
    PORT
      LAYER M4 ;
        RECT  104.004 74.448 104.088 74.472 ;
    END
  END b[360]
  PIN b[361]
    DIRECTION OUTPUT ;
    USE SIGNAL ;
    PORT
      LAYER M4 ;
        RECT  104.004 74.544 104.088 74.568 ;
    END
  END b[361]
  PIN b[362]
    DIRECTION OUTPUT ;
    USE SIGNAL ;
    PORT
      LAYER M4 ;
        RECT  104.004 74.64 104.088 74.664 ;
    END
  END b[362]
  PIN b[363]
    DIRECTION OUTPUT ;
    USE SIGNAL ;
    PORT
      LAYER M4 ;
        RECT  104.004 74.736 104.088 74.76 ;
    END
  END b[363]
  PIN b[364]
    DIRECTION OUTPUT ;
    USE SIGNAL ;
    PORT
      LAYER M4 ;
        RECT  104.004 74.832 104.088 74.856 ;
    END
  END b[364]
  PIN b[365]
    DIRECTION OUTPUT ;
    USE SIGNAL ;
    PORT
      LAYER M4 ;
        RECT  104.004 74.928 104.088 74.952 ;
    END
  END b[365]
  PIN b[366]
    DIRECTION OUTPUT ;
    USE SIGNAL ;
    PORT
      LAYER M4 ;
        RECT  104.004 75.024 104.088 75.048 ;
    END
  END b[366]
  PIN b[367]
    DIRECTION OUTPUT ;
    USE SIGNAL ;
    PORT
      LAYER M4 ;
        RECT  104.004 75.12 104.088 75.144 ;
    END
  END b[367]
  PIN b[368]
    DIRECTION OUTPUT ;
    USE SIGNAL ;
    PORT
      LAYER M4 ;
        RECT  104.004 75.216 104.088 75.24 ;
    END
  END b[368]
  PIN b[369]
    DIRECTION OUTPUT ;
    USE SIGNAL ;
    PORT
      LAYER M4 ;
        RECT  104.004 75.312 104.088 75.336 ;
    END
  END b[369]
  PIN b[36]
    DIRECTION OUTPUT ;
    USE SIGNAL ;
    PORT
      LAYER M4 ;
        RECT  104.004 42.576 104.088 42.6 ;
    END
  END b[36]
  PIN b[370]
    DIRECTION OUTPUT ;
    USE SIGNAL ;
    PORT
      LAYER M4 ;
        RECT  104.004 75.408 104.088 75.432 ;
    END
  END b[370]
  PIN b[371]
    DIRECTION OUTPUT ;
    USE SIGNAL ;
    PORT
      LAYER M4 ;
        RECT  104.004 75.504 104.088 75.528 ;
    END
  END b[371]
  PIN b[372]
    DIRECTION OUTPUT ;
    USE SIGNAL ;
    PORT
      LAYER M4 ;
        RECT  104.004 75.6 104.088 75.624 ;
    END
  END b[372]
  PIN b[373]
    DIRECTION OUTPUT ;
    USE SIGNAL ;
    PORT
      LAYER M4 ;
        RECT  104.004 75.696 104.088 75.72 ;
    END
  END b[373]
  PIN b[374]
    DIRECTION OUTPUT ;
    USE SIGNAL ;
    PORT
      LAYER M4 ;
        RECT  104.004 75.792 104.088 75.816 ;
    END
  END b[374]
  PIN b[375]
    DIRECTION OUTPUT ;
    USE SIGNAL ;
    PORT
      LAYER M4 ;
        RECT  104.004 75.888 104.088 75.912 ;
    END
  END b[375]
  PIN b[376]
    DIRECTION OUTPUT ;
    USE SIGNAL ;
    PORT
      LAYER M4 ;
        RECT  104.004 75.984 104.088 76.008 ;
    END
  END b[376]
  PIN b[377]
    DIRECTION OUTPUT ;
    USE SIGNAL ;
    PORT
      LAYER M4 ;
        RECT  104.004 76.08 104.088 76.104 ;
    END
  END b[377]
  PIN b[378]
    DIRECTION OUTPUT ;
    USE SIGNAL ;
    PORT
      LAYER M4 ;
        RECT  104.004 76.176 104.088 76.2 ;
    END
  END b[378]
  PIN b[379]
    DIRECTION OUTPUT ;
    USE SIGNAL ;
    PORT
      LAYER M4 ;
        RECT  104.004 76.272 104.088 76.296 ;
    END
  END b[379]
  PIN b[37]
    DIRECTION OUTPUT ;
    USE SIGNAL ;
    PORT
      LAYER M4 ;
        RECT  104.004 42.672 104.088 42.696 ;
    END
  END b[37]
  PIN b[380]
    DIRECTION OUTPUT ;
    USE SIGNAL ;
    PORT
      LAYER M4 ;
        RECT  104.004 76.368 104.088 76.392 ;
    END
  END b[380]
  PIN b[381]
    DIRECTION OUTPUT ;
    USE SIGNAL ;
    PORT
      LAYER M4 ;
        RECT  104.004 76.464 104.088 76.488 ;
    END
  END b[381]
  PIN b[382]
    DIRECTION OUTPUT ;
    USE SIGNAL ;
    PORT
      LAYER M4 ;
        RECT  104.004 76.56 104.088 76.584 ;
    END
  END b[382]
  PIN b[383]
    DIRECTION OUTPUT ;
    USE SIGNAL ;
    PORT
      LAYER M4 ;
        RECT  104.004 76.656 104.088 76.68 ;
    END
  END b[383]
  PIN b[384]
    DIRECTION OUTPUT ;
    USE SIGNAL ;
    PORT
      LAYER M4 ;
        RECT  104.004 48.336 104.088 48.36 ;
    END
  END b[384]
  PIN b[385]
    DIRECTION OUTPUT ;
    USE SIGNAL ;
    PORT
      LAYER M4 ;
        RECT  104.004 48.432 104.088 48.456 ;
    END
  END b[385]
  PIN b[386]
    DIRECTION OUTPUT ;
    USE SIGNAL ;
    PORT
      LAYER M4 ;
        RECT  104.004 48.528 104.088 48.552 ;
    END
  END b[386]
  PIN b[387]
    DIRECTION OUTPUT ;
    USE SIGNAL ;
    PORT
      LAYER M4 ;
        RECT  104.004 48.624 104.088 48.648 ;
    END
  END b[387]
  PIN b[388]
    DIRECTION OUTPUT ;
    USE SIGNAL ;
    PORT
      LAYER M4 ;
        RECT  104.004 48.72 104.088 48.744 ;
    END
  END b[388]
  PIN b[389]
    DIRECTION OUTPUT ;
    USE SIGNAL ;
    PORT
      LAYER M4 ;
        RECT  104.004 48.816 104.088 48.84 ;
    END
  END b[389]
  PIN b[38]
    DIRECTION OUTPUT ;
    USE SIGNAL ;
    PORT
      LAYER M4 ;
        RECT  104.004 42.768 104.088 42.792 ;
    END
  END b[38]
  PIN b[390]
    DIRECTION OUTPUT ;
    USE SIGNAL ;
    PORT
      LAYER M4 ;
        RECT  104.004 48.912 104.088 48.936 ;
    END
  END b[390]
  PIN b[391]
    DIRECTION OUTPUT ;
    USE SIGNAL ;
    PORT
      LAYER M4 ;
        RECT  104.004 49.008 104.088 49.032 ;
    END
  END b[391]
  PIN b[392]
    DIRECTION OUTPUT ;
    USE SIGNAL ;
    PORT
      LAYER M4 ;
        RECT  104.004 49.104 104.088 49.128 ;
    END
  END b[392]
  PIN b[393]
    DIRECTION OUTPUT ;
    USE SIGNAL ;
    PORT
      LAYER M4 ;
        RECT  104.004 49.2 104.088 49.224 ;
    END
  END b[393]
  PIN b[394]
    DIRECTION OUTPUT ;
    USE SIGNAL ;
    PORT
      LAYER M4 ;
        RECT  104.004 49.296 104.088 49.32 ;
    END
  END b[394]
  PIN b[395]
    DIRECTION OUTPUT ;
    USE SIGNAL ;
    PORT
      LAYER M4 ;
        RECT  104.004 49.392 104.088 49.416 ;
    END
  END b[395]
  PIN b[396]
    DIRECTION OUTPUT ;
    USE SIGNAL ;
    PORT
      LAYER M4 ;
        RECT  104.004 49.488 104.088 49.512 ;
    END
  END b[396]
  PIN b[397]
    DIRECTION OUTPUT ;
    USE SIGNAL ;
    PORT
      LAYER M4 ;
        RECT  104.004 49.584 104.088 49.608 ;
    END
  END b[397]
  PIN b[398]
    DIRECTION OUTPUT ;
    USE SIGNAL ;
    PORT
      LAYER M4 ;
        RECT  104.004 49.68 104.088 49.704 ;
    END
  END b[398]
  PIN b[399]
    DIRECTION OUTPUT ;
    USE SIGNAL ;
    PORT
      LAYER M4 ;
        RECT  104.004 49.776 104.088 49.8 ;
    END
  END b[399]
  PIN b[39]
    DIRECTION OUTPUT ;
    USE SIGNAL ;
    PORT
      LAYER M4 ;
        RECT  104.004 42.864 104.088 42.888 ;
    END
  END b[39]
  PIN b[3]
    DIRECTION OUTPUT ;
    USE SIGNAL ;
    PORT
      LAYER M4 ;
        RECT  104.004 64.752 104.088 64.776 ;
    END
  END b[3]
  PIN b[400]
    DIRECTION OUTPUT ;
    USE SIGNAL ;
    PORT
      LAYER M4 ;
        RECT  104.004 49.872 104.088 49.896 ;
    END
  END b[400]
  PIN b[401]
    DIRECTION OUTPUT ;
    USE SIGNAL ;
    PORT
      LAYER M4 ;
        RECT  104.004 49.968 104.088 49.992 ;
    END
  END b[401]
  PIN b[402]
    DIRECTION OUTPUT ;
    USE SIGNAL ;
    PORT
      LAYER M4 ;
        RECT  104.004 50.064 104.088 50.088 ;
    END
  END b[402]
  PIN b[403]
    DIRECTION OUTPUT ;
    USE SIGNAL ;
    PORT
      LAYER M4 ;
        RECT  104.004 50.16 104.088 50.184 ;
    END
  END b[403]
  PIN b[404]
    DIRECTION OUTPUT ;
    USE SIGNAL ;
    PORT
      LAYER M4 ;
        RECT  104.004 50.256 104.088 50.28 ;
    END
  END b[404]
  PIN b[405]
    DIRECTION OUTPUT ;
    USE SIGNAL ;
    PORT
      LAYER M4 ;
        RECT  104.004 50.352 104.088 50.376 ;
    END
  END b[405]
  PIN b[406]
    DIRECTION OUTPUT ;
    USE SIGNAL ;
    PORT
      LAYER M4 ;
        RECT  104.004 50.448 104.088 50.472 ;
    END
  END b[406]
  PIN b[407]
    DIRECTION OUTPUT ;
    USE SIGNAL ;
    PORT
      LAYER M4 ;
        RECT  104.004 50.544 104.088 50.568 ;
    END
  END b[407]
  PIN b[408]
    DIRECTION OUTPUT ;
    USE SIGNAL ;
    PORT
      LAYER M4 ;
        RECT  104.004 50.64 104.088 50.664 ;
    END
  END b[408]
  PIN b[409]
    DIRECTION OUTPUT ;
    USE SIGNAL ;
    PORT
      LAYER M4 ;
        RECT  104.004 50.736 104.088 50.76 ;
    END
  END b[409]
  PIN b[40]
    DIRECTION OUTPUT ;
    USE SIGNAL ;
    PORT
      LAYER M4 ;
        RECT  104.004 42.96 104.088 42.984 ;
    END
  END b[40]
  PIN b[410]
    DIRECTION OUTPUT ;
    USE SIGNAL ;
    PORT
      LAYER M4 ;
        RECT  104.004 50.832 104.088 50.856 ;
    END
  END b[410]
  PIN b[411]
    DIRECTION OUTPUT ;
    USE SIGNAL ;
    PORT
      LAYER M4 ;
        RECT  104.004 50.928 104.088 50.952 ;
    END
  END b[411]
  PIN b[412]
    DIRECTION OUTPUT ;
    USE SIGNAL ;
    PORT
      LAYER M4 ;
        RECT  104.004 51.024 104.088 51.048 ;
    END
  END b[412]
  PIN b[413]
    DIRECTION OUTPUT ;
    USE SIGNAL ;
    PORT
      LAYER M4 ;
        RECT  104.004 51.12 104.088 51.144 ;
    END
  END b[413]
  PIN b[414]
    DIRECTION OUTPUT ;
    USE SIGNAL ;
    PORT
      LAYER M4 ;
        RECT  104.004 51.216 104.088 51.24 ;
    END
  END b[414]
  PIN b[415]
    DIRECTION OUTPUT ;
    USE SIGNAL ;
    PORT
      LAYER M4 ;
        RECT  104.004 51.312 104.088 51.336 ;
    END
  END b[415]
  PIN b[416]
    DIRECTION OUTPUT ;
    USE SIGNAL ;
    PORT
      LAYER M4 ;
        RECT  104.004 26.064 104.088 26.088 ;
    END
  END b[416]
  PIN b[417]
    DIRECTION OUTPUT ;
    USE SIGNAL ;
    PORT
      LAYER M4 ;
        RECT  104.004 26.16 104.088 26.184 ;
    END
  END b[417]
  PIN b[418]
    DIRECTION OUTPUT ;
    USE SIGNAL ;
    PORT
      LAYER M4 ;
        RECT  104.004 26.256 104.088 26.28 ;
    END
  END b[418]
  PIN b[419]
    DIRECTION OUTPUT ;
    USE SIGNAL ;
    PORT
      LAYER M4 ;
        RECT  104.004 26.352 104.088 26.376 ;
    END
  END b[419]
  PIN b[41]
    DIRECTION OUTPUT ;
    USE SIGNAL ;
    PORT
      LAYER M4 ;
        RECT  104.004 43.056 104.088 43.08 ;
    END
  END b[41]
  PIN b[420]
    DIRECTION OUTPUT ;
    USE SIGNAL ;
    PORT
      LAYER M4 ;
        RECT  104.004 26.448 104.088 26.472 ;
    END
  END b[420]
  PIN b[421]
    DIRECTION OUTPUT ;
    USE SIGNAL ;
    PORT
      LAYER M4 ;
        RECT  104.004 26.544 104.088 26.568 ;
    END
  END b[421]
  PIN b[422]
    DIRECTION OUTPUT ;
    USE SIGNAL ;
    PORT
      LAYER M4 ;
        RECT  104.004 26.64 104.088 26.664 ;
    END
  END b[422]
  PIN b[423]
    DIRECTION OUTPUT ;
    USE SIGNAL ;
    PORT
      LAYER M4 ;
        RECT  104.004 26.736 104.088 26.76 ;
    END
  END b[423]
  PIN b[424]
    DIRECTION OUTPUT ;
    USE SIGNAL ;
    PORT
      LAYER M4 ;
        RECT  104.004 26.832 104.088 26.856 ;
    END
  END b[424]
  PIN b[425]
    DIRECTION OUTPUT ;
    USE SIGNAL ;
    PORT
      LAYER M4 ;
        RECT  104.004 26.928 104.088 26.952 ;
    END
  END b[425]
  PIN b[426]
    DIRECTION OUTPUT ;
    USE SIGNAL ;
    PORT
      LAYER M4 ;
        RECT  104.004 27.024 104.088 27.048 ;
    END
  END b[426]
  PIN b[427]
    DIRECTION OUTPUT ;
    USE SIGNAL ;
    PORT
      LAYER M4 ;
        RECT  104.004 27.12 104.088 27.144 ;
    END
  END b[427]
  PIN b[428]
    DIRECTION OUTPUT ;
    USE SIGNAL ;
    PORT
      LAYER M4 ;
        RECT  104.004 27.216 104.088 27.24 ;
    END
  END b[428]
  PIN b[429]
    DIRECTION OUTPUT ;
    USE SIGNAL ;
    PORT
      LAYER M4 ;
        RECT  104.004 27.312 104.088 27.336 ;
    END
  END b[429]
  PIN b[42]
    DIRECTION OUTPUT ;
    USE SIGNAL ;
    PORT
      LAYER M4 ;
        RECT  104.004 43.152 104.088 43.176 ;
    END
  END b[42]
  PIN b[430]
    DIRECTION OUTPUT ;
    USE SIGNAL ;
    PORT
      LAYER M4 ;
        RECT  104.004 27.408 104.088 27.432 ;
    END
  END b[430]
  PIN b[431]
    DIRECTION OUTPUT ;
    USE SIGNAL ;
    PORT
      LAYER M4 ;
        RECT  104.004 27.504 104.088 27.528 ;
    END
  END b[431]
  PIN b[432]
    DIRECTION OUTPUT ;
    USE SIGNAL ;
    PORT
      LAYER M4 ;
        RECT  104.004 27.6 104.088 27.624 ;
    END
  END b[432]
  PIN b[433]
    DIRECTION OUTPUT ;
    USE SIGNAL ;
    PORT
      LAYER M4 ;
        RECT  104.004 27.696 104.088 27.72 ;
    END
  END b[433]
  PIN b[434]
    DIRECTION OUTPUT ;
    USE SIGNAL ;
    PORT
      LAYER M4 ;
        RECT  104.004 27.792 104.088 27.816 ;
    END
  END b[434]
  PIN b[435]
    DIRECTION OUTPUT ;
    USE SIGNAL ;
    PORT
      LAYER M4 ;
        RECT  104.004 27.888 104.088 27.912 ;
    END
  END b[435]
  PIN b[436]
    DIRECTION OUTPUT ;
    USE SIGNAL ;
    PORT
      LAYER M4 ;
        RECT  104.004 27.984 104.088 28.008 ;
    END
  END b[436]
  PIN b[437]
    DIRECTION OUTPUT ;
    USE SIGNAL ;
    PORT
      LAYER M4 ;
        RECT  104.004 28.08 104.088 28.104 ;
    END
  END b[437]
  PIN b[438]
    DIRECTION OUTPUT ;
    USE SIGNAL ;
    PORT
      LAYER M4 ;
        RECT  104.004 28.176 104.088 28.2 ;
    END
  END b[438]
  PIN b[439]
    DIRECTION OUTPUT ;
    USE SIGNAL ;
    PORT
      LAYER M4 ;
        RECT  104.004 28.272 104.088 28.296 ;
    END
  END b[439]
  PIN b[43]
    DIRECTION OUTPUT ;
    USE SIGNAL ;
    PORT
      LAYER M4 ;
        RECT  104.004 43.248 104.088 43.272 ;
    END
  END b[43]
  PIN b[440]
    DIRECTION OUTPUT ;
    USE SIGNAL ;
    PORT
      LAYER M4 ;
        RECT  104.004 28.368 104.088 28.392 ;
    END
  END b[440]
  PIN b[441]
    DIRECTION OUTPUT ;
    USE SIGNAL ;
    PORT
      LAYER M4 ;
        RECT  104.004 28.464 104.088 28.488 ;
    END
  END b[441]
  PIN b[442]
    DIRECTION OUTPUT ;
    USE SIGNAL ;
    PORT
      LAYER M4 ;
        RECT  104.004 28.56 104.088 28.584 ;
    END
  END b[442]
  PIN b[443]
    DIRECTION OUTPUT ;
    USE SIGNAL ;
    PORT
      LAYER M4 ;
        RECT  104.004 28.656 104.088 28.68 ;
    END
  END b[443]
  PIN b[444]
    DIRECTION OUTPUT ;
    USE SIGNAL ;
    PORT
      LAYER M4 ;
        RECT  104.004 28.752 104.088 28.776 ;
    END
  END b[444]
  PIN b[445]
    DIRECTION OUTPUT ;
    USE SIGNAL ;
    PORT
      LAYER M4 ;
        RECT  104.004 28.848 104.088 28.872 ;
    END
  END b[445]
  PIN b[446]
    DIRECTION OUTPUT ;
    USE SIGNAL ;
    PORT
      LAYER M4 ;
        RECT  104.004 28.944 104.088 28.968 ;
    END
  END b[446]
  PIN b[447]
    DIRECTION OUTPUT ;
    USE SIGNAL ;
    PORT
      LAYER M4 ;
        RECT  104.004 29.04 104.088 29.064 ;
    END
  END b[447]
  PIN b[448]
    DIRECTION OUTPUT ;
    USE SIGNAL ;
    PORT
      LAYER M4 ;
        RECT  104.004 22.992 104.088 23.016 ;
    END
  END b[448]
  PIN b[449]
    DIRECTION OUTPUT ;
    USE SIGNAL ;
    PORT
      LAYER M4 ;
        RECT  104.004 23.088 104.088 23.112 ;
    END
  END b[449]
  PIN b[44]
    DIRECTION OUTPUT ;
    USE SIGNAL ;
    PORT
      LAYER M4 ;
        RECT  104.004 43.344 104.088 43.368 ;
    END
  END b[44]
  PIN b[450]
    DIRECTION OUTPUT ;
    USE SIGNAL ;
    PORT
      LAYER M4 ;
        RECT  104.004 23.184 104.088 23.208 ;
    END
  END b[450]
  PIN b[451]
    DIRECTION OUTPUT ;
    USE SIGNAL ;
    PORT
      LAYER M4 ;
        RECT  104.004 23.28 104.088 23.304 ;
    END
  END b[451]
  PIN b[452]
    DIRECTION OUTPUT ;
    USE SIGNAL ;
    PORT
      LAYER M4 ;
        RECT  104.004 23.376 104.088 23.4 ;
    END
  END b[452]
  PIN b[453]
    DIRECTION OUTPUT ;
    USE SIGNAL ;
    PORT
      LAYER M4 ;
        RECT  104.004 23.472 104.088 23.496 ;
    END
  END b[453]
  PIN b[454]
    DIRECTION OUTPUT ;
    USE SIGNAL ;
    PORT
      LAYER M4 ;
        RECT  104.004 23.568 104.088 23.592 ;
    END
  END b[454]
  PIN b[455]
    DIRECTION OUTPUT ;
    USE SIGNAL ;
    PORT
      LAYER M4 ;
        RECT  104.004 23.664 104.088 23.688 ;
    END
  END b[455]
  PIN b[456]
    DIRECTION OUTPUT ;
    USE SIGNAL ;
    PORT
      LAYER M4 ;
        RECT  104.004 23.76 104.088 23.784 ;
    END
  END b[456]
  PIN b[457]
    DIRECTION OUTPUT ;
    USE SIGNAL ;
    PORT
      LAYER M4 ;
        RECT  104.004 23.856 104.088 23.88 ;
    END
  END b[457]
  PIN b[458]
    DIRECTION OUTPUT ;
    USE SIGNAL ;
    PORT
      LAYER M4 ;
        RECT  104.004 23.952 104.088 23.976 ;
    END
  END b[458]
  PIN b[459]
    DIRECTION OUTPUT ;
    USE SIGNAL ;
    PORT
      LAYER M4 ;
        RECT  104.004 24.048 104.088 24.072 ;
    END
  END b[459]
  PIN b[45]
    DIRECTION OUTPUT ;
    USE SIGNAL ;
    PORT
      LAYER M4 ;
        RECT  104.004 43.44 104.088 43.464 ;
    END
  END b[45]
  PIN b[460]
    DIRECTION OUTPUT ;
    USE SIGNAL ;
    PORT
      LAYER M4 ;
        RECT  104.004 24.144 104.088 24.168 ;
    END
  END b[460]
  PIN b[461]
    DIRECTION OUTPUT ;
    USE SIGNAL ;
    PORT
      LAYER M4 ;
        RECT  104.004 24.24 104.088 24.264 ;
    END
  END b[461]
  PIN b[462]
    DIRECTION OUTPUT ;
    USE SIGNAL ;
    PORT
      LAYER M4 ;
        RECT  104.004 24.336 104.088 24.36 ;
    END
  END b[462]
  PIN b[463]
    DIRECTION OUTPUT ;
    USE SIGNAL ;
    PORT
      LAYER M4 ;
        RECT  104.004 24.432 104.088 24.456 ;
    END
  END b[463]
  PIN b[464]
    DIRECTION OUTPUT ;
    USE SIGNAL ;
    PORT
      LAYER M4 ;
        RECT  104.004 24.528 104.088 24.552 ;
    END
  END b[464]
  PIN b[465]
    DIRECTION OUTPUT ;
    USE SIGNAL ;
    PORT
      LAYER M4 ;
        RECT  104.004 24.624 104.088 24.648 ;
    END
  END b[465]
  PIN b[466]
    DIRECTION OUTPUT ;
    USE SIGNAL ;
    PORT
      LAYER M4 ;
        RECT  104.004 24.72 104.088 24.744 ;
    END
  END b[466]
  PIN b[467]
    DIRECTION OUTPUT ;
    USE SIGNAL ;
    PORT
      LAYER M4 ;
        RECT  104.004 24.816 104.088 24.84 ;
    END
  END b[467]
  PIN b[468]
    DIRECTION OUTPUT ;
    USE SIGNAL ;
    PORT
      LAYER M4 ;
        RECT  104.004 24.912 104.088 24.936 ;
    END
  END b[468]
  PIN b[469]
    DIRECTION OUTPUT ;
    USE SIGNAL ;
    PORT
      LAYER M4 ;
        RECT  104.004 25.008 104.088 25.032 ;
    END
  END b[469]
  PIN b[46]
    DIRECTION OUTPUT ;
    USE SIGNAL ;
    PORT
      LAYER M4 ;
        RECT  104.004 43.536 104.088 43.56 ;
    END
  END b[46]
  PIN b[470]
    DIRECTION OUTPUT ;
    USE SIGNAL ;
    PORT
      LAYER M4 ;
        RECT  104.004 25.104 104.088 25.128 ;
    END
  END b[470]
  PIN b[471]
    DIRECTION OUTPUT ;
    USE SIGNAL ;
    PORT
      LAYER M4 ;
        RECT  104.004 25.2 104.088 25.224 ;
    END
  END b[471]
  PIN b[472]
    DIRECTION OUTPUT ;
    USE SIGNAL ;
    PORT
      LAYER M4 ;
        RECT  104.004 25.296 104.088 25.32 ;
    END
  END b[472]
  PIN b[473]
    DIRECTION OUTPUT ;
    USE SIGNAL ;
    PORT
      LAYER M4 ;
        RECT  104.004 25.392 104.088 25.416 ;
    END
  END b[473]
  PIN b[474]
    DIRECTION OUTPUT ;
    USE SIGNAL ;
    PORT
      LAYER M4 ;
        RECT  104.004 25.488 104.088 25.512 ;
    END
  END b[474]
  PIN b[475]
    DIRECTION OUTPUT ;
    USE SIGNAL ;
    PORT
      LAYER M4 ;
        RECT  104.004 25.584 104.088 25.608 ;
    END
  END b[475]
  PIN b[476]
    DIRECTION OUTPUT ;
    USE SIGNAL ;
    PORT
      LAYER M4 ;
        RECT  104.004 25.68 104.088 25.704 ;
    END
  END b[476]
  PIN b[477]
    DIRECTION OUTPUT ;
    USE SIGNAL ;
    PORT
      LAYER M4 ;
        RECT  104.004 25.776 104.088 25.8 ;
    END
  END b[477]
  PIN b[478]
    DIRECTION OUTPUT ;
    USE SIGNAL ;
    PORT
      LAYER M4 ;
        RECT  104.004 25.872 104.088 25.896 ;
    END
  END b[478]
  PIN b[479]
    DIRECTION OUTPUT ;
    USE SIGNAL ;
    PORT
      LAYER M4 ;
        RECT  104.004 25.968 104.088 25.992 ;
    END
  END b[479]
  PIN b[47]
    DIRECTION OUTPUT ;
    USE SIGNAL ;
    PORT
      LAYER M4 ;
        RECT  104.004 43.632 104.088 43.656 ;
    END
  END b[47]
  PIN b[480]
    DIRECTION OUTPUT ;
    USE SIGNAL ;
    PORT
      LAYER M4 ;
        RECT  104.004 32.208 104.088 32.232 ;
    END
  END b[480]
  PIN b[481]
    DIRECTION OUTPUT ;
    USE SIGNAL ;
    PORT
      LAYER M4 ;
        RECT  104.004 32.304 104.088 32.328 ;
    END
  END b[481]
  PIN b[482]
    DIRECTION OUTPUT ;
    USE SIGNAL ;
    PORT
      LAYER M4 ;
        RECT  104.004 32.4 104.088 32.424 ;
    END
  END b[482]
  PIN b[483]
    DIRECTION OUTPUT ;
    USE SIGNAL ;
    PORT
      LAYER M4 ;
        RECT  104.004 32.496 104.088 32.52 ;
    END
  END b[483]
  PIN b[484]
    DIRECTION OUTPUT ;
    USE SIGNAL ;
    PORT
      LAYER M4 ;
        RECT  104.004 32.592 104.088 32.616 ;
    END
  END b[484]
  PIN b[485]
    DIRECTION OUTPUT ;
    USE SIGNAL ;
    PORT
      LAYER M4 ;
        RECT  104.004 32.688 104.088 32.712 ;
    END
  END b[485]
  PIN b[486]
    DIRECTION OUTPUT ;
    USE SIGNAL ;
    PORT
      LAYER M4 ;
        RECT  104.004 32.784 104.088 32.808 ;
    END
  END b[486]
  PIN b[487]
    DIRECTION OUTPUT ;
    USE SIGNAL ;
    PORT
      LAYER M4 ;
        RECT  104.004 32.88 104.088 32.904 ;
    END
  END b[487]
  PIN b[488]
    DIRECTION OUTPUT ;
    USE SIGNAL ;
    PORT
      LAYER M4 ;
        RECT  104.004 32.976 104.088 33 ;
    END
  END b[488]
  PIN b[489]
    DIRECTION OUTPUT ;
    USE SIGNAL ;
    PORT
      LAYER M4 ;
        RECT  104.004 33.072 104.088 33.096 ;
    END
  END b[489]
  PIN b[48]
    DIRECTION OUTPUT ;
    USE SIGNAL ;
    PORT
      LAYER M4 ;
        RECT  104.004 43.728 104.088 43.752 ;
    END
  END b[48]
  PIN b[490]
    DIRECTION OUTPUT ;
    USE SIGNAL ;
    PORT
      LAYER M4 ;
        RECT  104.004 33.168 104.088 33.192 ;
    END
  END b[490]
  PIN b[491]
    DIRECTION OUTPUT ;
    USE SIGNAL ;
    PORT
      LAYER M4 ;
        RECT  104.004 33.264 104.088 33.288 ;
    END
  END b[491]
  PIN b[492]
    DIRECTION OUTPUT ;
    USE SIGNAL ;
    PORT
      LAYER M4 ;
        RECT  104.004 33.36 104.088 33.384 ;
    END
  END b[492]
  PIN b[493]
    DIRECTION OUTPUT ;
    USE SIGNAL ;
    PORT
      LAYER M4 ;
        RECT  104.004 33.456 104.088 33.48 ;
    END
  END b[493]
  PIN b[494]
    DIRECTION OUTPUT ;
    USE SIGNAL ;
    PORT
      LAYER M4 ;
        RECT  104.004 33.552 104.088 33.576 ;
    END
  END b[494]
  PIN b[495]
    DIRECTION OUTPUT ;
    USE SIGNAL ;
    PORT
      LAYER M4 ;
        RECT  104.004 33.648 104.088 33.672 ;
    END
  END b[495]
  PIN b[496]
    DIRECTION OUTPUT ;
    USE SIGNAL ;
    PORT
      LAYER M4 ;
        RECT  104.004 33.744 104.088 33.768 ;
    END
  END b[496]
  PIN b[497]
    DIRECTION OUTPUT ;
    USE SIGNAL ;
    PORT
      LAYER M4 ;
        RECT  104.004 33.84 104.088 33.864 ;
    END
  END b[497]
  PIN b[498]
    DIRECTION OUTPUT ;
    USE SIGNAL ;
    PORT
      LAYER M4 ;
        RECT  104.004 33.936 104.088 33.96 ;
    END
  END b[498]
  PIN b[499]
    DIRECTION OUTPUT ;
    USE SIGNAL ;
    PORT
      LAYER M4 ;
        RECT  104.004 34.032 104.088 34.056 ;
    END
  END b[499]
  PIN b[49]
    DIRECTION OUTPUT ;
    USE SIGNAL ;
    PORT
      LAYER M4 ;
        RECT  104.004 43.824 104.088 43.848 ;
    END
  END b[49]
  PIN b[4]
    DIRECTION OUTPUT ;
    USE SIGNAL ;
    PORT
      LAYER M4 ;
        RECT  104.004 64.848 104.088 64.872 ;
    END
  END b[4]
  PIN b[500]
    DIRECTION OUTPUT ;
    USE SIGNAL ;
    PORT
      LAYER M4 ;
        RECT  104.004 34.128 104.088 34.152 ;
    END
  END b[500]
  PIN b[501]
    DIRECTION OUTPUT ;
    USE SIGNAL ;
    PORT
      LAYER M4 ;
        RECT  104.004 34.224 104.088 34.248 ;
    END
  END b[501]
  PIN b[502]
    DIRECTION OUTPUT ;
    USE SIGNAL ;
    PORT
      LAYER M4 ;
        RECT  104.004 34.32 104.088 34.344 ;
    END
  END b[502]
  PIN b[503]
    DIRECTION OUTPUT ;
    USE SIGNAL ;
    PORT
      LAYER M4 ;
        RECT  104.004 34.416 104.088 34.44 ;
    END
  END b[503]
  PIN b[504]
    DIRECTION OUTPUT ;
    USE SIGNAL ;
    PORT
      LAYER M4 ;
        RECT  104.004 34.512 104.088 34.536 ;
    END
  END b[504]
  PIN b[505]
    DIRECTION OUTPUT ;
    USE SIGNAL ;
    PORT
      LAYER M4 ;
        RECT  104.004 34.608 104.088 34.632 ;
    END
  END b[505]
  PIN b[506]
    DIRECTION OUTPUT ;
    USE SIGNAL ;
    PORT
      LAYER M4 ;
        RECT  104.004 34.704 104.088 34.728 ;
    END
  END b[506]
  PIN b[507]
    DIRECTION OUTPUT ;
    USE SIGNAL ;
    PORT
      LAYER M4 ;
        RECT  104.004 34.8 104.088 34.824 ;
    END
  END b[507]
  PIN b[508]
    DIRECTION OUTPUT ;
    USE SIGNAL ;
    PORT
      LAYER M4 ;
        RECT  104.004 34.896 104.088 34.92 ;
    END
  END b[508]
  PIN b[509]
    DIRECTION OUTPUT ;
    USE SIGNAL ;
    PORT
      LAYER M4 ;
        RECT  104.004 34.992 104.088 35.016 ;
    END
  END b[509]
  PIN b[50]
    DIRECTION OUTPUT ;
    USE SIGNAL ;
    PORT
      LAYER M4 ;
        RECT  104.004 43.92 104.088 43.944 ;
    END
  END b[50]
  PIN b[510]
    DIRECTION OUTPUT ;
    USE SIGNAL ;
    PORT
      LAYER M4 ;
        RECT  104.004 35.088 104.088 35.112 ;
    END
  END b[510]
  PIN b[511]
    DIRECTION OUTPUT ;
    USE SIGNAL ;
    PORT
      LAYER M4 ;
        RECT  104.004 35.184 104.088 35.208 ;
    END
  END b[511]
  PIN b[512]
    DIRECTION OUTPUT ;
    USE SIGNAL ;
    PORT
      LAYER M4 ;
        RECT  104.004 51.408 104.088 51.432 ;
    END
  END b[512]
  PIN b[513]
    DIRECTION OUTPUT ;
    USE SIGNAL ;
    PORT
      LAYER M4 ;
        RECT  104.004 51.504 104.088 51.528 ;
    END
  END b[513]
  PIN b[514]
    DIRECTION OUTPUT ;
    USE SIGNAL ;
    PORT
      LAYER M4 ;
        RECT  104.004 51.6 104.088 51.624 ;
    END
  END b[514]
  PIN b[515]
    DIRECTION OUTPUT ;
    USE SIGNAL ;
    PORT
      LAYER M4 ;
        RECT  104.004 51.696 104.088 51.72 ;
    END
  END b[515]
  PIN b[516]
    DIRECTION OUTPUT ;
    USE SIGNAL ;
    PORT
      LAYER M4 ;
        RECT  104.004 51.792 104.088 51.816 ;
    END
  END b[516]
  PIN b[517]
    DIRECTION OUTPUT ;
    USE SIGNAL ;
    PORT
      LAYER M4 ;
        RECT  104.004 51.888 104.088 51.912 ;
    END
  END b[517]
  PIN b[518]
    DIRECTION OUTPUT ;
    USE SIGNAL ;
    PORT
      LAYER M4 ;
        RECT  104.004 51.984 104.088 52.008 ;
    END
  END b[518]
  PIN b[519]
    DIRECTION OUTPUT ;
    USE SIGNAL ;
    PORT
      LAYER M4 ;
        RECT  104.004 52.08 104.088 52.104 ;
    END
  END b[519]
  PIN b[51]
    DIRECTION OUTPUT ;
    USE SIGNAL ;
    PORT
      LAYER M4 ;
        RECT  104.004 44.016 104.088 44.04 ;
    END
  END b[51]
  PIN b[520]
    DIRECTION OUTPUT ;
    USE SIGNAL ;
    PORT
      LAYER M4 ;
        RECT  104.004 52.176 104.088 52.2 ;
    END
  END b[520]
  PIN b[521]
    DIRECTION OUTPUT ;
    USE SIGNAL ;
    PORT
      LAYER M4 ;
        RECT  104.004 52.272 104.088 52.296 ;
    END
  END b[521]
  PIN b[522]
    DIRECTION OUTPUT ;
    USE SIGNAL ;
    PORT
      LAYER M4 ;
        RECT  104.004 52.368 104.088 52.392 ;
    END
  END b[522]
  PIN b[523]
    DIRECTION OUTPUT ;
    USE SIGNAL ;
    PORT
      LAYER M4 ;
        RECT  104.004 52.464 104.088 52.488 ;
    END
  END b[523]
  PIN b[524]
    DIRECTION OUTPUT ;
    USE SIGNAL ;
    PORT
      LAYER M4 ;
        RECT  104.004 52.56 104.088 52.584 ;
    END
  END b[524]
  PIN b[525]
    DIRECTION OUTPUT ;
    USE SIGNAL ;
    PORT
      LAYER M4 ;
        RECT  104.004 52.656 104.088 52.68 ;
    END
  END b[525]
  PIN b[526]
    DIRECTION OUTPUT ;
    USE SIGNAL ;
    PORT
      LAYER M4 ;
        RECT  104.004 52.752 104.088 52.776 ;
    END
  END b[526]
  PIN b[527]
    DIRECTION OUTPUT ;
    USE SIGNAL ;
    PORT
      LAYER M4 ;
        RECT  104.004 52.848 104.088 52.872 ;
    END
  END b[527]
  PIN b[528]
    DIRECTION OUTPUT ;
    USE SIGNAL ;
    PORT
      LAYER M4 ;
        RECT  104.004 52.944 104.088 52.968 ;
    END
  END b[528]
  PIN b[529]
    DIRECTION OUTPUT ;
    USE SIGNAL ;
    PORT
      LAYER M4 ;
        RECT  104.004 53.04 104.088 53.064 ;
    END
  END b[529]
  PIN b[52]
    DIRECTION OUTPUT ;
    USE SIGNAL ;
    PORT
      LAYER M4 ;
        RECT  104.004 44.112 104.088 44.136 ;
    END
  END b[52]
  PIN b[530]
    DIRECTION OUTPUT ;
    USE SIGNAL ;
    PORT
      LAYER M4 ;
        RECT  104.004 53.136 104.088 53.16 ;
    END
  END b[530]
  PIN b[531]
    DIRECTION OUTPUT ;
    USE SIGNAL ;
    PORT
      LAYER M4 ;
        RECT  104.004 53.232 104.088 53.256 ;
    END
  END b[531]
  PIN b[532]
    DIRECTION OUTPUT ;
    USE SIGNAL ;
    PORT
      LAYER M4 ;
        RECT  104.004 53.328 104.088 53.352 ;
    END
  END b[532]
  PIN b[533]
    DIRECTION OUTPUT ;
    USE SIGNAL ;
    PORT
      LAYER M4 ;
        RECT  104.004 53.424 104.088 53.448 ;
    END
  END b[533]
  PIN b[534]
    DIRECTION OUTPUT ;
    USE SIGNAL ;
    PORT
      LAYER M4 ;
        RECT  104.004 53.52 104.088 53.544 ;
    END
  END b[534]
  PIN b[535]
    DIRECTION OUTPUT ;
    USE SIGNAL ;
    PORT
      LAYER M4 ;
        RECT  104.004 53.616 104.088 53.64 ;
    END
  END b[535]
  PIN b[536]
    DIRECTION OUTPUT ;
    USE SIGNAL ;
    PORT
      LAYER M4 ;
        RECT  104.004 53.712 104.088 53.736 ;
    END
  END b[536]
  PIN b[537]
    DIRECTION OUTPUT ;
    USE SIGNAL ;
    PORT
      LAYER M4 ;
        RECT  104.004 53.808 104.088 53.832 ;
    END
  END b[537]
  PIN b[538]
    DIRECTION OUTPUT ;
    USE SIGNAL ;
    PORT
      LAYER M4 ;
        RECT  104.004 53.904 104.088 53.928 ;
    END
  END b[538]
  PIN b[539]
    DIRECTION OUTPUT ;
    USE SIGNAL ;
    PORT
      LAYER M4 ;
        RECT  104.004 54 104.088 54.024 ;
    END
  END b[539]
  PIN b[53]
    DIRECTION OUTPUT ;
    USE SIGNAL ;
    PORT
      LAYER M4 ;
        RECT  104.004 44.208 104.088 44.232 ;
    END
  END b[53]
  PIN b[540]
    DIRECTION OUTPUT ;
    USE SIGNAL ;
    PORT
      LAYER M4 ;
        RECT  104.004 54.096 104.088 54.12 ;
    END
  END b[540]
  PIN b[541]
    DIRECTION OUTPUT ;
    USE SIGNAL ;
    PORT
      LAYER M4 ;
        RECT  104.004 54.192 104.088 54.216 ;
    END
  END b[541]
  PIN b[542]
    DIRECTION OUTPUT ;
    USE SIGNAL ;
    PORT
      LAYER M4 ;
        RECT  104.004 54.288 104.088 54.312 ;
    END
  END b[542]
  PIN b[543]
    DIRECTION OUTPUT ;
    USE SIGNAL ;
    PORT
      LAYER M4 ;
        RECT  104.004 54.384 104.088 54.408 ;
    END
  END b[543]
  PIN b[544]
    DIRECTION OUTPUT ;
    USE SIGNAL ;
    PORT
      LAYER M4 ;
        RECT  104.004 58.32 104.088 58.344 ;
    END
  END b[544]
  PIN b[545]
    DIRECTION OUTPUT ;
    USE SIGNAL ;
    PORT
      LAYER M4 ;
        RECT  104.004 58.416 104.088 58.44 ;
    END
  END b[545]
  PIN b[546]
    DIRECTION OUTPUT ;
    USE SIGNAL ;
    PORT
      LAYER M4 ;
        RECT  104.004 58.512 104.088 58.536 ;
    END
  END b[546]
  PIN b[547]
    DIRECTION OUTPUT ;
    USE SIGNAL ;
    PORT
      LAYER M4 ;
        RECT  104.004 58.608 104.088 58.632 ;
    END
  END b[547]
  PIN b[548]
    DIRECTION OUTPUT ;
    USE SIGNAL ;
    PORT
      LAYER M4 ;
        RECT  104.004 58.704 104.088 58.728 ;
    END
  END b[548]
  PIN b[549]
    DIRECTION OUTPUT ;
    USE SIGNAL ;
    PORT
      LAYER M4 ;
        RECT  104.004 58.8 104.088 58.824 ;
    END
  END b[549]
  PIN b[54]
    DIRECTION OUTPUT ;
    USE SIGNAL ;
    PORT
      LAYER M4 ;
        RECT  104.004 44.304 104.088 44.328 ;
    END
  END b[54]
  PIN b[550]
    DIRECTION OUTPUT ;
    USE SIGNAL ;
    PORT
      LAYER M4 ;
        RECT  104.004 58.896 104.088 58.92 ;
    END
  END b[550]
  PIN b[551]
    DIRECTION OUTPUT ;
    USE SIGNAL ;
    PORT
      LAYER M4 ;
        RECT  104.004 58.992 104.088 59.016 ;
    END
  END b[551]
  PIN b[552]
    DIRECTION OUTPUT ;
    USE SIGNAL ;
    PORT
      LAYER M4 ;
        RECT  104.004 59.088 104.088 59.112 ;
    END
  END b[552]
  PIN b[553]
    DIRECTION OUTPUT ;
    USE SIGNAL ;
    PORT
      LAYER M4 ;
        RECT  104.004 59.184 104.088 59.208 ;
    END
  END b[553]
  PIN b[554]
    DIRECTION OUTPUT ;
    USE SIGNAL ;
    PORT
      LAYER M4 ;
        RECT  104.004 59.28 104.088 59.304 ;
    END
  END b[554]
  PIN b[555]
    DIRECTION OUTPUT ;
    USE SIGNAL ;
    PORT
      LAYER M4 ;
        RECT  104.004 59.376 104.088 59.4 ;
    END
  END b[555]
  PIN b[556]
    DIRECTION OUTPUT ;
    USE SIGNAL ;
    PORT
      LAYER M4 ;
        RECT  104.004 59.472 104.088 59.496 ;
    END
  END b[556]
  PIN b[557]
    DIRECTION OUTPUT ;
    USE SIGNAL ;
    PORT
      LAYER M4 ;
        RECT  104.004 59.568 104.088 59.592 ;
    END
  END b[557]
  PIN b[558]
    DIRECTION OUTPUT ;
    USE SIGNAL ;
    PORT
      LAYER M4 ;
        RECT  104.004 59.664 104.088 59.688 ;
    END
  END b[558]
  PIN b[559]
    DIRECTION OUTPUT ;
    USE SIGNAL ;
    PORT
      LAYER M4 ;
        RECT  104.004 59.76 104.088 59.784 ;
    END
  END b[559]
  PIN b[55]
    DIRECTION OUTPUT ;
    USE SIGNAL ;
    PORT
      LAYER M4 ;
        RECT  104.004 44.4 104.088 44.424 ;
    END
  END b[55]
  PIN b[560]
    DIRECTION OUTPUT ;
    USE SIGNAL ;
    PORT
      LAYER M4 ;
        RECT  104.004 59.856 104.088 59.88 ;
    END
  END b[560]
  PIN b[561]
    DIRECTION OUTPUT ;
    USE SIGNAL ;
    PORT
      LAYER M4 ;
        RECT  104.004 59.952 104.088 59.976 ;
    END
  END b[561]
  PIN b[562]
    DIRECTION OUTPUT ;
    USE SIGNAL ;
    PORT
      LAYER M4 ;
        RECT  104.004 60.048 104.088 60.072 ;
    END
  END b[562]
  PIN b[563]
    DIRECTION OUTPUT ;
    USE SIGNAL ;
    PORT
      LAYER M4 ;
        RECT  104.004 60.144 104.088 60.168 ;
    END
  END b[563]
  PIN b[564]
    DIRECTION OUTPUT ;
    USE SIGNAL ;
    PORT
      LAYER M4 ;
        RECT  104.004 60.24 104.088 60.264 ;
    END
  END b[564]
  PIN b[565]
    DIRECTION OUTPUT ;
    USE SIGNAL ;
    PORT
      LAYER M4 ;
        RECT  104.004 60.336 104.088 60.36 ;
    END
  END b[565]
  PIN b[566]
    DIRECTION OUTPUT ;
    USE SIGNAL ;
    PORT
      LAYER M4 ;
        RECT  104.004 60.432 104.088 60.456 ;
    END
  END b[566]
  PIN b[567]
    DIRECTION OUTPUT ;
    USE SIGNAL ;
    PORT
      LAYER M4 ;
        RECT  104.004 60.528 104.088 60.552 ;
    END
  END b[567]
  PIN b[568]
    DIRECTION OUTPUT ;
    USE SIGNAL ;
    PORT
      LAYER M4 ;
        RECT  104.004 60.624 104.088 60.648 ;
    END
  END b[568]
  PIN b[569]
    DIRECTION OUTPUT ;
    USE SIGNAL ;
    PORT
      LAYER M4 ;
        RECT  104.004 60.72 104.088 60.744 ;
    END
  END b[569]
  PIN b[56]
    DIRECTION OUTPUT ;
    USE SIGNAL ;
    PORT
      LAYER M4 ;
        RECT  104.004 44.496 104.088 44.52 ;
    END
  END b[56]
  PIN b[570]
    DIRECTION OUTPUT ;
    USE SIGNAL ;
    PORT
      LAYER M4 ;
        RECT  104.004 60.816 104.088 60.84 ;
    END
  END b[570]
  PIN b[571]
    DIRECTION OUTPUT ;
    USE SIGNAL ;
    PORT
      LAYER M4 ;
        RECT  104.004 60.912 104.088 60.936 ;
    END
  END b[571]
  PIN b[572]
    DIRECTION OUTPUT ;
    USE SIGNAL ;
    PORT
      LAYER M4 ;
        RECT  104.004 61.008 104.088 61.032 ;
    END
  END b[572]
  PIN b[573]
    DIRECTION OUTPUT ;
    USE SIGNAL ;
    PORT
      LAYER M4 ;
        RECT  104.004 61.104 104.088 61.128 ;
    END
  END b[573]
  PIN b[574]
    DIRECTION OUTPUT ;
    USE SIGNAL ;
    PORT
      LAYER M4 ;
        RECT  104.004 61.2 104.088 61.224 ;
    END
  END b[574]
  PIN b[575]
    DIRECTION OUTPUT ;
    USE SIGNAL ;
    PORT
      LAYER M4 ;
        RECT  104.004 61.296 104.088 61.32 ;
    END
  END b[575]
  PIN b[576]
    DIRECTION OUTPUT ;
    USE SIGNAL ;
    PORT
      LAYER M4 ;
        RECT  104.004 35.28 104.088 35.304 ;
    END
  END b[576]
  PIN b[577]
    DIRECTION OUTPUT ;
    USE SIGNAL ;
    PORT
      LAYER M4 ;
        RECT  104.004 35.376 104.088 35.4 ;
    END
  END b[577]
  PIN b[578]
    DIRECTION OUTPUT ;
    USE SIGNAL ;
    PORT
      LAYER M4 ;
        RECT  104.004 35.472 104.088 35.496 ;
    END
  END b[578]
  PIN b[579]
    DIRECTION OUTPUT ;
    USE SIGNAL ;
    PORT
      LAYER M4 ;
        RECT  104.004 35.568 104.088 35.592 ;
    END
  END b[579]
  PIN b[57]
    DIRECTION OUTPUT ;
    USE SIGNAL ;
    PORT
      LAYER M4 ;
        RECT  104.004 44.592 104.088 44.616 ;
    END
  END b[57]
  PIN b[580]
    DIRECTION OUTPUT ;
    USE SIGNAL ;
    PORT
      LAYER M4 ;
        RECT  104.004 35.664 104.088 35.688 ;
    END
  END b[580]
  PIN b[581]
    DIRECTION OUTPUT ;
    USE SIGNAL ;
    PORT
      LAYER M4 ;
        RECT  104.004 35.76 104.088 35.784 ;
    END
  END b[581]
  PIN b[582]
    DIRECTION OUTPUT ;
    USE SIGNAL ;
    PORT
      LAYER M4 ;
        RECT  104.004 35.856 104.088 35.88 ;
    END
  END b[582]
  PIN b[583]
    DIRECTION OUTPUT ;
    USE SIGNAL ;
    PORT
      LAYER M4 ;
        RECT  104.004 35.952 104.088 35.976 ;
    END
  END b[583]
  PIN b[584]
    DIRECTION OUTPUT ;
    USE SIGNAL ;
    PORT
      LAYER M4 ;
        RECT  104.004 36.048 104.088 36.072 ;
    END
  END b[584]
  PIN b[585]
    DIRECTION OUTPUT ;
    USE SIGNAL ;
    PORT
      LAYER M4 ;
        RECT  104.004 36.144 104.088 36.168 ;
    END
  END b[585]
  PIN b[586]
    DIRECTION OUTPUT ;
    USE SIGNAL ;
    PORT
      LAYER M4 ;
        RECT  104.004 36.24 104.088 36.264 ;
    END
  END b[586]
  PIN b[587]
    DIRECTION OUTPUT ;
    USE SIGNAL ;
    PORT
      LAYER M4 ;
        RECT  104.004 36.336 104.088 36.36 ;
    END
  END b[587]
  PIN b[588]
    DIRECTION OUTPUT ;
    USE SIGNAL ;
    PORT
      LAYER M4 ;
        RECT  104.004 36.432 104.088 36.456 ;
    END
  END b[588]
  PIN b[589]
    DIRECTION OUTPUT ;
    USE SIGNAL ;
    PORT
      LAYER M4 ;
        RECT  104.004 36.528 104.088 36.552 ;
    END
  END b[589]
  PIN b[58]
    DIRECTION OUTPUT ;
    USE SIGNAL ;
    PORT
      LAYER M4 ;
        RECT  104.004 44.688 104.088 44.712 ;
    END
  END b[58]
  PIN b[590]
    DIRECTION OUTPUT ;
    USE SIGNAL ;
    PORT
      LAYER M4 ;
        RECT  104.004 36.624 104.088 36.648 ;
    END
  END b[590]
  PIN b[591]
    DIRECTION OUTPUT ;
    USE SIGNAL ;
    PORT
      LAYER M4 ;
        RECT  104.004 36.72 104.088 36.744 ;
    END
  END b[591]
  PIN b[592]
    DIRECTION OUTPUT ;
    USE SIGNAL ;
    PORT
      LAYER M4 ;
        RECT  104.004 36.816 104.088 36.84 ;
    END
  END b[592]
  PIN b[593]
    DIRECTION OUTPUT ;
    USE SIGNAL ;
    PORT
      LAYER M4 ;
        RECT  104.004 36.912 104.088 36.936 ;
    END
  END b[593]
  PIN b[594]
    DIRECTION OUTPUT ;
    USE SIGNAL ;
    PORT
      LAYER M4 ;
        RECT  104.004 37.008 104.088 37.032 ;
    END
  END b[594]
  PIN b[595]
    DIRECTION OUTPUT ;
    USE SIGNAL ;
    PORT
      LAYER M4 ;
        RECT  104.004 37.104 104.088 37.128 ;
    END
  END b[595]
  PIN b[596]
    DIRECTION OUTPUT ;
    USE SIGNAL ;
    PORT
      LAYER M4 ;
        RECT  104.004 37.2 104.088 37.224 ;
    END
  END b[596]
  PIN b[597]
    DIRECTION OUTPUT ;
    USE SIGNAL ;
    PORT
      LAYER M4 ;
        RECT  104.004 37.296 104.088 37.32 ;
    END
  END b[597]
  PIN b[598]
    DIRECTION OUTPUT ;
    USE SIGNAL ;
    PORT
      LAYER M4 ;
        RECT  104.004 37.392 104.088 37.416 ;
    END
  END b[598]
  PIN b[599]
    DIRECTION OUTPUT ;
    USE SIGNAL ;
    PORT
      LAYER M4 ;
        RECT  104.004 37.488 104.088 37.512 ;
    END
  END b[599]
  PIN b[59]
    DIRECTION OUTPUT ;
    USE SIGNAL ;
    PORT
      LAYER M4 ;
        RECT  104.004 44.784 104.088 44.808 ;
    END
  END b[59]
  PIN b[5]
    DIRECTION OUTPUT ;
    USE SIGNAL ;
    PORT
      LAYER M4 ;
        RECT  104.004 64.944 104.088 64.968 ;
    END
  END b[5]
  PIN b[60]
    DIRECTION OUTPUT ;
    USE SIGNAL ;
    PORT
      LAYER M4 ;
        RECT  104.004 44.88 104.088 44.904 ;
    END
  END b[60]
  PIN b[61]
    DIRECTION OUTPUT ;
    USE SIGNAL ;
    PORT
      LAYER M4 ;
        RECT  104.004 44.976 104.088 45 ;
    END
  END b[61]
  PIN b[62]
    DIRECTION OUTPUT ;
    USE SIGNAL ;
    PORT
      LAYER M4 ;
        RECT  104.004 45.072 104.088 45.096 ;
    END
  END b[62]
  PIN b[63]
    DIRECTION OUTPUT ;
    USE SIGNAL ;
    PORT
      LAYER M4 ;
        RECT  104.004 45.168 104.088 45.192 ;
    END
  END b[63]
  PIN b[64]
    DIRECTION OUTPUT ;
    USE SIGNAL ;
    PORT
      LAYER M4 ;
        RECT  104.004 61.392 104.088 61.416 ;
    END
  END b[64]
  PIN b[65]
    DIRECTION OUTPUT ;
    USE SIGNAL ;
    PORT
      LAYER M4 ;
        RECT  104.004 61.488 104.088 61.512 ;
    END
  END b[65]
  PIN b[66]
    DIRECTION OUTPUT ;
    USE SIGNAL ;
    PORT
      LAYER M4 ;
        RECT  104.004 61.584 104.088 61.608 ;
    END
  END b[66]
  PIN b[67]
    DIRECTION OUTPUT ;
    USE SIGNAL ;
    PORT
      LAYER M4 ;
        RECT  104.004 61.68 104.088 61.704 ;
    END
  END b[67]
  PIN b[68]
    DIRECTION OUTPUT ;
    USE SIGNAL ;
    PORT
      LAYER M4 ;
        RECT  104.004 61.776 104.088 61.8 ;
    END
  END b[68]
  PIN b[69]
    DIRECTION OUTPUT ;
    USE SIGNAL ;
    PORT
      LAYER M4 ;
        RECT  104.004 61.872 104.088 61.896 ;
    END
  END b[69]
  PIN b[6]
    DIRECTION OUTPUT ;
    USE SIGNAL ;
    PORT
      LAYER M4 ;
        RECT  104.004 65.04 104.088 65.064 ;
    END
  END b[6]
  PIN b[70]
    DIRECTION OUTPUT ;
    USE SIGNAL ;
    PORT
      LAYER M4 ;
        RECT  104.004 61.968 104.088 61.992 ;
    END
  END b[70]
  PIN b[71]
    DIRECTION OUTPUT ;
    USE SIGNAL ;
    PORT
      LAYER M4 ;
        RECT  104.004 62.064 104.088 62.088 ;
    END
  END b[71]
  PIN b[72]
    DIRECTION OUTPUT ;
    USE SIGNAL ;
    PORT
      LAYER M4 ;
        RECT  104.004 62.16 104.088 62.184 ;
    END
  END b[72]
  PIN b[73]
    DIRECTION OUTPUT ;
    USE SIGNAL ;
    PORT
      LAYER M4 ;
        RECT  104.004 62.256 104.088 62.28 ;
    END
  END b[73]
  PIN b[74]
    DIRECTION OUTPUT ;
    USE SIGNAL ;
    PORT
      LAYER M4 ;
        RECT  104.004 62.352 104.088 62.376 ;
    END
  END b[74]
  PIN b[75]
    DIRECTION OUTPUT ;
    USE SIGNAL ;
    PORT
      LAYER M4 ;
        RECT  104.004 62.448 104.088 62.472 ;
    END
  END b[75]
  PIN b[76]
    DIRECTION OUTPUT ;
    USE SIGNAL ;
    PORT
      LAYER M4 ;
        RECT  104.004 62.544 104.088 62.568 ;
    END
  END b[76]
  PIN b[77]
    DIRECTION OUTPUT ;
    USE SIGNAL ;
    PORT
      LAYER M4 ;
        RECT  104.004 62.64 104.088 62.664 ;
    END
  END b[77]
  PIN b[78]
    DIRECTION OUTPUT ;
    USE SIGNAL ;
    PORT
      LAYER M4 ;
        RECT  104.004 62.736 104.088 62.76 ;
    END
  END b[78]
  PIN b[79]
    DIRECTION OUTPUT ;
    USE SIGNAL ;
    PORT
      LAYER M4 ;
        RECT  104.004 62.832 104.088 62.856 ;
    END
  END b[79]
  PIN b[7]
    DIRECTION OUTPUT ;
    USE SIGNAL ;
    PORT
      LAYER M4 ;
        RECT  104.004 65.136 104.088 65.16 ;
    END
  END b[7]
  PIN b[80]
    DIRECTION OUTPUT ;
    USE SIGNAL ;
    PORT
      LAYER M4 ;
        RECT  104.004 62.928 104.088 62.952 ;
    END
  END b[80]
  PIN b[81]
    DIRECTION OUTPUT ;
    USE SIGNAL ;
    PORT
      LAYER M4 ;
        RECT  104.004 63.024 104.088 63.048 ;
    END
  END b[81]
  PIN b[82]
    DIRECTION OUTPUT ;
    USE SIGNAL ;
    PORT
      LAYER M4 ;
        RECT  104.004 63.12 104.088 63.144 ;
    END
  END b[82]
  PIN b[83]
    DIRECTION OUTPUT ;
    USE SIGNAL ;
    PORT
      LAYER M4 ;
        RECT  104.004 63.216 104.088 63.24 ;
    END
  END b[83]
  PIN b[84]
    DIRECTION OUTPUT ;
    USE SIGNAL ;
    PORT
      LAYER M4 ;
        RECT  104.004 63.312 104.088 63.336 ;
    END
  END b[84]
  PIN b[85]
    DIRECTION OUTPUT ;
    USE SIGNAL ;
    PORT
      LAYER M4 ;
        RECT  104.004 63.408 104.088 63.432 ;
    END
  END b[85]
  PIN b[86]
    DIRECTION OUTPUT ;
    USE SIGNAL ;
    PORT
      LAYER M4 ;
        RECT  104.004 63.504 104.088 63.528 ;
    END
  END b[86]
  PIN b[87]
    DIRECTION OUTPUT ;
    USE SIGNAL ;
    PORT
      LAYER M4 ;
        RECT  104.004 63.6 104.088 63.624 ;
    END
  END b[87]
  PIN b[88]
    DIRECTION OUTPUT ;
    USE SIGNAL ;
    PORT
      LAYER M4 ;
        RECT  104.004 63.696 104.088 63.72 ;
    END
  END b[88]
  PIN b[89]
    DIRECTION OUTPUT ;
    USE SIGNAL ;
    PORT
      LAYER M4 ;
        RECT  104.004 63.792 104.088 63.816 ;
    END
  END b[89]
  PIN b[8]
    DIRECTION OUTPUT ;
    USE SIGNAL ;
    PORT
      LAYER M4 ;
        RECT  104.004 65.232 104.088 65.256 ;
    END
  END b[8]
  PIN b[90]
    DIRECTION OUTPUT ;
    USE SIGNAL ;
    PORT
      LAYER M4 ;
        RECT  104.004 63.888 104.088 63.912 ;
    END
  END b[90]
  PIN b[91]
    DIRECTION OUTPUT ;
    USE SIGNAL ;
    PORT
      LAYER M4 ;
        RECT  104.004 63.984 104.088 64.008 ;
    END
  END b[91]
  PIN b[92]
    DIRECTION OUTPUT ;
    USE SIGNAL ;
    PORT
      LAYER M4 ;
        RECT  104.004 64.08 104.088 64.104 ;
    END
  END b[92]
  PIN b[93]
    DIRECTION OUTPUT ;
    USE SIGNAL ;
    PORT
      LAYER M4 ;
        RECT  104.004 64.176 104.088 64.2 ;
    END
  END b[93]
  PIN b[94]
    DIRECTION OUTPUT ;
    USE SIGNAL ;
    PORT
      LAYER M4 ;
        RECT  104.004 64.272 104.088 64.296 ;
    END
  END b[94]
  PIN b[95]
    DIRECTION OUTPUT ;
    USE SIGNAL ;
    PORT
      LAYER M4 ;
        RECT  104.004 64.368 104.088 64.392 ;
    END
  END b[95]
  PIN b[96]
    DIRECTION OUTPUT ;
    USE SIGNAL ;
    PORT
      LAYER M4 ;
        RECT  104.004 39.12 104.088 39.144 ;
    END
  END b[96]
  PIN b[97]
    DIRECTION OUTPUT ;
    USE SIGNAL ;
    PORT
      LAYER M4 ;
        RECT  104.004 39.216 104.088 39.24 ;
    END
  END b[97]
  PIN b[98]
    DIRECTION OUTPUT ;
    USE SIGNAL ;
    PORT
      LAYER M4 ;
        RECT  104.004 39.312 104.088 39.336 ;
    END
  END b[98]
  PIN b[99]
    DIRECTION OUTPUT ;
    USE SIGNAL ;
    PORT
      LAYER M4 ;
        RECT  104.004 39.408 104.088 39.432 ;
    END
  END b[99]
  PIN b[9]
    DIRECTION OUTPUT ;
    USE SIGNAL ;
    PORT
      LAYER M4 ;
        RECT  104.004 65.328 104.088 65.352 ;
    END
  END b[9]
  PIN ck
    DIRECTION INPUT ;
    USE SIGNAL ;
    PORT
      LAYER M4 ;
        RECT  0 60.048 0.084 60.072 ;
    END
  END ck
  PIN ck_s
    DIRECTION INPUT ;
    USE SIGNAL ;
    PORT
      LAYER M4 ;
        RECT  0 60.144 0.084 60.168 ;
    END
  END ck_s
  PIN en
    DIRECTION INPUT ;
    USE SIGNAL ;
    PORT
      LAYER M4 ;
        RECT  0 60.24 0.084 60.264 ;
    END
  END en
  PIN fault
    DIRECTION OUTPUT ;
    USE SIGNAL ;
    PORT
      LAYER M4 ;
        RECT  0 60.336 0.084 60.36 ;
    END
  END fault
  PIN k0
    DIRECTION INPUT ;
    USE SIGNAL ;
    PORT
      LAYER M4 ;
        RECT  0 60.432 0.084 60.456 ;
    END
  END k0
  PIN k1
    DIRECTION INPUT ;
    USE SIGNAL ;
    PORT
      LAYER M4 ;
        RECT  0 60.528 0.084 60.552 ;
    END
  END k1
  PIN k2
    DIRECTION INPUT ;
    USE SIGNAL ;
    PORT
      LAYER M4 ;
        RECT  0 60.624 0.084 60.648 ;
    END
  END k2
  PIN rs
    DIRECTION INPUT ;
    USE SIGNAL ;
    PORT
      LAYER M4 ;
        RECT  0 60.72 0.084 60.744 ;
    END
  END rs
  PIN tie_hi
    DIRECTION OUTPUT ;
    USE SIGNAL ;
    PORT
      LAYER M4 ;
        RECT  0 60.816 0.084 60.84 ;
    END
  END tie_hi
  PIN tie_lo
    DIRECTION OUTPUT ;
    USE SIGNAL ;
    PORT
      LAYER M4 ;
        RECT  0 60.912 0.084 60.936 ;
    END
  END tie_lo
  PIN VDD
    DIRECTION INOUT ;
    USE POWER ;
    PORT
      LAYER M5 ;
        RECT  99.792 2.151 99.912 103.433 ;
        RECT  97.092 2.151 97.212 103.433 ;
        RECT  94.392 2.151 94.512 103.433 ;
        RECT  91.692 2.151 91.812 103.433 ;
        RECT  88.992 2.151 89.112 103.433 ;
        RECT  86.292 2.151 86.412 103.433 ;
        RECT  83.592 2.151 83.712 103.433 ;
        RECT  80.892 2.151 81.012 103.433 ;
        RECT  78.192 2.151 78.312 103.433 ;
        RECT  75.492 2.151 75.612 103.433 ;
        RECT  72.792 2.151 72.912 103.433 ;
        RECT  70.092 2.151 70.212 103.433 ;
        RECT  67.392 2.151 67.512 103.433 ;
        RECT  64.692 2.151 64.812 103.433 ;
        RECT  61.992 2.151 62.112 103.433 ;
        RECT  59.292 2.151 59.412 103.433 ;
        RECT  56.592 2.151 56.712 103.433 ;
        RECT  53.892 2.151 54.012 103.433 ;
        RECT  51.192 2.151 51.312 103.433 ;
        RECT  48.492 2.151 48.612 103.433 ;
        RECT  45.792 2.151 45.912 103.433 ;
        RECT  43.092 2.151 43.212 103.433 ;
        RECT  40.392 2.151 40.512 103.433 ;
        RECT  37.692 2.151 37.812 103.433 ;
        RECT  34.992 2.151 35.112 103.433 ;
        RECT  32.292 2.151 32.412 103.433 ;
        RECT  29.592 2.151 29.712 103.433 ;
        RECT  26.892 2.151 27.012 103.433 ;
        RECT  24.192 2.151 24.312 103.433 ;
        RECT  21.492 2.151 21.612 103.433 ;
        RECT  18.792 2.151 18.912 103.433 ;
        RECT  16.092 2.151 16.212 103.433 ;
        RECT  13.392 2.151 13.512 103.433 ;
        RECT  10.692 2.151 10.812 103.433 ;
        RECT  7.992 2.151 8.112 103.433 ;
        RECT  5.292 2.151 5.412 103.433 ;
        RECT  2.592 2.151 2.712 103.433 ;
    END
  END VDD
  PIN VSS
    DIRECTION INOUT ;
    USE GROUND ;
    PORT
      LAYER M5 ;
        RECT  99.6 2.137 99.72 103.419 ;
        RECT  96.9 2.137 97.02 103.419 ;
        RECT  94.2 2.137 94.32 103.419 ;
        RECT  91.5 2.137 91.62 103.419 ;
        RECT  88.8 2.137 88.92 103.419 ;
        RECT  86.1 2.137 86.22 103.419 ;
        RECT  83.4 2.137 83.52 103.419 ;
        RECT  80.7 2.137 80.82 103.419 ;
        RECT  78 2.137 78.12 103.419 ;
        RECT  75.3 2.137 75.42 103.419 ;
        RECT  72.6 2.137 72.72 103.419 ;
        RECT  69.9 2.137 70.02 103.419 ;
        RECT  67.2 2.137 67.32 103.419 ;
        RECT  64.5 2.137 64.62 103.419 ;
        RECT  61.8 2.137 61.92 103.419 ;
        RECT  59.1 2.137 59.22 103.419 ;
        RECT  56.4 2.137 56.52 103.419 ;
        RECT  53.7 2.137 53.82 103.419 ;
        RECT  51 2.137 51.12 103.419 ;
        RECT  48.3 2.137 48.42 103.419 ;
        RECT  45.6 2.137 45.72 103.419 ;
        RECT  42.9 2.137 43.02 103.419 ;
        RECT  40.2 2.137 40.32 103.419 ;
        RECT  37.5 2.137 37.62 103.419 ;
        RECT  34.8 2.137 34.92 103.419 ;
        RECT  32.1 2.137 32.22 103.419 ;
        RECT  29.4 2.137 29.52 103.419 ;
        RECT  26.7 2.137 26.82 103.419 ;
        RECT  24 2.137 24.12 103.419 ;
        RECT  21.3 2.137 21.42 103.419 ;
        RECT  18.6 2.137 18.72 103.419 ;
        RECT  15.9 2.137 16.02 103.419 ;
        RECT  13.2 2.137 13.32 103.419 ;
        RECT  10.5 2.137 10.62 103.419 ;
        RECT  7.8 2.137 7.92 103.419 ;
        RECT  5.1 2.137 5.22 103.419 ;
        RECT  2.4 2.137 2.52 103.419 ;
    END
  END VSS
  OBS
    LAYER RVTN ;
     RECT  2.16 2.16 101.898 2.295 ;
     RECT  2.16 2.565 101.898 2.835 ;
     RECT  2.16 3.105 101.898 3.375 ;
     RECT  2.16 3.645 101.898 3.915 ;
     RECT  2.16 4.185 101.898 4.455 ;
     RECT  2.16 4.725 101.898 4.995 ;
     RECT  2.16 5.265 101.898 5.535 ;
     RECT  2.16 5.805 101.898 6.075 ;
     RECT  2.16 6.345 101.898 6.615 ;
     RECT  2.16 6.885 101.898 7.155 ;
     RECT  2.16 7.425 101.898 7.695 ;
     RECT  2.16 7.965 101.898 8.235 ;
     RECT  2.16 8.505 101.898 8.775 ;
     RECT  2.16 9.045 101.898 9.315 ;
     RECT  2.16 9.585 101.898 9.855 ;
     RECT  2.16 10.125 101.898 10.395 ;
     RECT  2.16 10.665 101.898 10.935 ;
     RECT  2.16 11.205 101.898 11.475 ;
     RECT  2.16 11.745 101.898 12.015 ;
     RECT  2.16 12.285 101.898 12.555 ;
     RECT  2.16 12.825 101.898 13.095 ;
     RECT  2.16 13.365 101.898 13.635 ;
     RECT  2.16 13.905 101.898 14.175 ;
     RECT  2.16 14.445 101.898 14.715 ;
     RECT  2.16 14.985 101.898 15.255 ;
     RECT  2.16 15.525 101.898 15.795 ;
     RECT  2.16 16.065 101.898 16.335 ;
     RECT  2.16 16.605 101.898 16.875 ;
     RECT  2.16 17.145 101.898 17.415 ;
     RECT  2.16 17.685 101.898 17.955 ;
     RECT  2.16 18.225 101.898 18.495 ;
     RECT  2.16 18.765 101.898 19.035 ;
     RECT  2.16 19.305 101.898 19.575 ;
     RECT  2.16 19.845 101.898 20.115 ;
     RECT  2.16 20.385 101.898 20.655 ;
     RECT  2.16 20.925 101.898 21.195 ;
     RECT  2.16 21.465 101.898 21.735 ;
     RECT  2.16 22.005 101.898 22.275 ;
     RECT  2.16 22.545 101.898 22.815 ;
     RECT  2.16 23.085 101.898 23.355 ;
     RECT  2.16 23.625 101.898 23.895 ;
     RECT  2.16 24.165 101.898 24.435 ;
     RECT  2.16 24.705 101.898 24.975 ;
     RECT  2.16 25.245 101.898 25.515 ;
     RECT  2.16 25.785 101.898 26.055 ;
     RECT  2.16 26.325 101.898 26.595 ;
     RECT  2.16 26.865 101.898 27.135 ;
     RECT  2.16 27.405 101.898 27.675 ;
     RECT  2.16 27.945 101.898 28.215 ;
     RECT  2.16 28.485 101.898 28.755 ;
     RECT  2.16 29.025 101.898 29.295 ;
     RECT  2.16 29.565 101.898 29.835 ;
     RECT  2.16 30.105 101.898 30.375 ;
     RECT  2.16 30.645 101.898 30.915 ;
     RECT  2.16 31.185 101.898 31.455 ;
     RECT  2.16 31.725 101.898 31.995 ;
     RECT  2.16 32.265 101.898 32.535 ;
     RECT  2.16 32.805 101.898 33.075 ;
     RECT  2.16 33.345 101.898 33.615 ;
     RECT  2.16 33.885 101.898 34.155 ;
     RECT  2.16 34.425 101.898 34.695 ;
     RECT  2.16 34.965 101.898 35.235 ;
     RECT  2.16 35.505 101.898 35.775 ;
     RECT  2.16 36.045 101.898 36.315 ;
     RECT  2.16 36.585 101.898 36.855 ;
     RECT  2.16 37.125 101.898 37.395 ;
     RECT  2.16 37.665 101.898 37.935 ;
     RECT  2.16 38.205 101.898 38.475 ;
     RECT  2.16 38.745 101.898 39.015 ;
     RECT  2.16 39.285 101.898 39.555 ;
     RECT  2.16 39.825 101.898 40.095 ;
     RECT  2.16 40.365 101.898 40.635 ;
     RECT  2.16 40.905 101.898 41.175 ;
     RECT  2.16 41.445 101.898 41.715 ;
     RECT  2.16 41.985 101.898 42.255 ;
     RECT  2.16 42.525 101.898 42.795 ;
     RECT  2.16 43.065 101.898 43.335 ;
     RECT  2.16 43.605 101.898 43.875 ;
     RECT  2.16 44.145 101.898 44.415 ;
     RECT  2.16 44.685 101.898 44.955 ;
     RECT  2.16 45.225 101.898 45.495 ;
     RECT  2.16 45.765 101.898 46.035 ;
     RECT  2.16 46.305 101.898 46.575 ;
     RECT  2.16 46.845 101.898 47.115 ;
     RECT  2.16 47.385 101.898 47.655 ;
     RECT  2.16 47.925 101.898 48.195 ;
     RECT  2.16 48.465 101.898 48.735 ;
     RECT  2.16 49.005 101.898 49.275 ;
     RECT  2.16 49.545 101.898 49.815 ;
     RECT  2.16 50.085 101.898 50.355 ;
     RECT  2.16 50.625 101.898 50.895 ;
     RECT  2.16 51.165 101.898 51.435 ;
     RECT  2.16 51.705 101.898 51.975 ;
     RECT  2.16 52.245 101.898 52.515 ;
     RECT  2.16 52.785 101.898 53.055 ;
     RECT  2.16 53.325 101.898 53.595 ;
     RECT  2.16 53.865 101.898 54.135 ;
     RECT  2.16 54.405 101.898 54.675 ;
     RECT  2.16 54.945 101.898 55.215 ;
     RECT  2.16 55.485 101.898 55.755 ;
     RECT  2.16 56.025 101.898 56.295 ;
     RECT  2.16 56.565 101.898 56.835 ;
     RECT  2.16 57.105 101.898 57.375 ;
     RECT  2.16 57.645 101.898 57.915 ;
     RECT  2.16 58.185 101.898 58.455 ;
     RECT  2.16 58.725 101.898 58.995 ;
     RECT  2.16 59.265 101.898 59.535 ;
     RECT  2.16 59.805 101.898 60.075 ;
     RECT  2.16 60.345 101.898 60.615 ;
     RECT  2.16 60.885 101.898 61.155 ;
     RECT  2.16 61.425 101.898 61.695 ;
     RECT  2.16 61.965 101.898 62.235 ;
     RECT  2.16 62.505 101.898 62.775 ;
     RECT  2.16 63.045 101.898 63.315 ;
     RECT  2.16 63.585 101.898 63.855 ;
     RECT  2.16 64.125 101.898 64.395 ;
     RECT  2.16 64.665 101.898 64.935 ;
     RECT  2.16 65.205 101.898 65.475 ;
     RECT  2.16 65.745 101.898 66.015 ;
     RECT  2.16 66.285 101.898 66.555 ;
     RECT  2.16 66.825 101.898 67.095 ;
     RECT  2.16 67.365 101.898 67.635 ;
     RECT  2.16 67.905 101.898 68.175 ;
     RECT  2.16 68.445 101.898 68.715 ;
     RECT  2.16 68.985 101.898 69.255 ;
     RECT  2.16 69.525 101.898 69.795 ;
     RECT  2.16 70.065 101.898 70.335 ;
     RECT  2.16 70.605 101.898 70.875 ;
     RECT  2.16 71.145 101.898 71.415 ;
     RECT  2.16 71.685 101.898 71.955 ;
     RECT  2.16 72.225 101.898 72.495 ;
     RECT  2.16 72.765 101.898 73.035 ;
     RECT  2.16 73.305 101.898 73.575 ;
     RECT  2.16 73.845 101.898 74.115 ;
     RECT  2.16 74.385 101.898 74.655 ;
     RECT  2.16 74.925 101.898 75.195 ;
     RECT  2.16 75.465 101.898 75.735 ;
     RECT  2.16 76.005 101.898 76.275 ;
     RECT  2.16 76.545 101.898 76.815 ;
     RECT  2.16 77.085 101.898 77.355 ;
     RECT  2.16 77.625 101.898 77.895 ;
     RECT  2.16 78.165 101.898 78.435 ;
     RECT  2.16 78.705 101.898 78.975 ;
     RECT  2.16 79.245 101.898 79.515 ;
     RECT  2.16 79.785 101.898 80.055 ;
     RECT  2.16 80.325 101.898 80.595 ;
     RECT  2.16 80.865 101.898 81.135 ;
     RECT  2.16 81.405 101.898 81.675 ;
     RECT  2.16 81.945 101.898 82.215 ;
     RECT  2.16 82.485 101.898 82.755 ;
     RECT  2.16 83.025 101.898 83.295 ;
     RECT  2.16 83.565 101.898 83.835 ;
     RECT  2.16 84.105 101.898 84.375 ;
     RECT  2.16 84.645 101.898 84.915 ;
     RECT  2.16 85.185 101.898 85.455 ;
     RECT  2.16 85.725 101.898 85.995 ;
     RECT  2.16 86.265 101.898 86.535 ;
     RECT  2.16 86.805 101.898 87.075 ;
     RECT  2.16 87.345 101.898 87.615 ;
     RECT  2.16 87.885 101.898 88.155 ;
     RECT  2.16 88.425 101.898 88.695 ;
     RECT  2.16 88.965 101.898 89.235 ;
     RECT  2.16 89.505 101.898 89.775 ;
     RECT  2.16 90.045 101.898 90.315 ;
     RECT  2.16 90.585 101.898 90.855 ;
     RECT  2.16 91.125 101.898 91.395 ;
     RECT  2.16 91.665 101.898 91.935 ;
     RECT  2.16 92.205 101.898 92.475 ;
     RECT  2.16 92.745 101.898 93.015 ;
     RECT  2.16 93.285 101.898 93.555 ;
     RECT  2.16 93.825 101.898 94.095 ;
     RECT  2.16 94.365 101.898 94.635 ;
     RECT  2.16 94.905 101.898 95.175 ;
     RECT  2.16 95.445 101.898 95.715 ;
     RECT  2.16 95.985 101.898 96.255 ;
     RECT  2.16 96.525 101.898 96.795 ;
     RECT  2.16 97.065 101.898 97.335 ;
     RECT  2.16 97.605 101.898 97.875 ;
     RECT  2.16 98.145 101.898 98.415 ;
     RECT  2.16 98.685 101.898 98.955 ;
     RECT  2.16 99.225 101.898 99.495 ;
     RECT  2.16 99.765 101.898 100.035 ;
     RECT  2.16 100.305 101.898 100.575 ;
     RECT  2.16 100.845 101.898 101.115 ;
     RECT  2.16 101.385 101.898 101.655 ;
     RECT  2.16 101.925 101.898 102.195 ;
     RECT  2.16 102.465 101.898 102.735 ;
     RECT  2.16 103.005 101.898 103.275 ;
    LAYER RVTP ;
     RECT  2.16 2.295 101.898 2.565 ;
     RECT  2.16 2.835 101.898 3.105 ;
     RECT  2.16 3.375 101.898 3.645 ;
     RECT  2.16 3.915 101.898 4.185 ;
     RECT  2.16 4.455 101.898 4.725 ;
     RECT  2.16 4.995 101.898 5.265 ;
     RECT  2.16 5.535 101.898 5.805 ;
     RECT  2.16 6.075 101.898 6.345 ;
     RECT  2.16 6.615 101.898 6.885 ;
     RECT  2.16 7.155 101.898 7.425 ;
     RECT  2.16 7.695 101.898 7.965 ;
     RECT  2.16 8.235 101.898 8.505 ;
     RECT  2.16 8.775 101.898 9.045 ;
     RECT  2.16 9.315 101.898 9.585 ;
     RECT  2.16 9.855 101.898 10.125 ;
     RECT  2.16 10.395 101.898 10.665 ;
     RECT  2.16 10.935 101.898 11.205 ;
     RECT  2.16 11.475 101.898 11.745 ;
     RECT  2.16 12.015 101.898 12.285 ;
     RECT  2.16 12.555 101.898 12.825 ;
     RECT  2.16 13.095 101.898 13.365 ;
     RECT  2.16 13.635 101.898 13.905 ;
     RECT  2.16 14.175 101.898 14.445 ;
     RECT  2.16 14.715 101.898 14.985 ;
     RECT  2.16 15.255 101.898 15.525 ;
     RECT  2.16 15.795 101.898 16.065 ;
     RECT  2.16 16.335 101.898 16.605 ;
     RECT  2.16 16.875 101.898 17.145 ;
     RECT  2.16 17.415 101.898 17.685 ;
     RECT  2.16 17.955 101.898 18.225 ;
     RECT  2.16 18.495 101.898 18.765 ;
     RECT  2.16 19.035 101.898 19.305 ;
     RECT  2.16 19.575 101.898 19.845 ;
     RECT  2.16 20.115 101.898 20.385 ;
     RECT  2.16 20.655 101.898 20.925 ;
     RECT  2.16 21.195 101.898 21.465 ;
     RECT  2.16 21.735 101.898 22.005 ;
     RECT  2.16 22.275 101.898 22.545 ;
     RECT  2.16 22.815 101.898 23.085 ;
     RECT  2.16 23.355 101.898 23.625 ;
     RECT  2.16 23.895 101.898 24.165 ;
     RECT  2.16 24.435 101.898 24.705 ;
     RECT  2.16 24.975 101.898 25.245 ;
     RECT  2.16 25.515 101.898 25.785 ;
     RECT  2.16 26.055 101.898 26.325 ;
     RECT  2.16 26.595 101.898 26.865 ;
     RECT  2.16 27.135 101.898 27.405 ;
     RECT  2.16 27.675 101.898 27.945 ;
     RECT  2.16 28.215 101.898 28.485 ;
     RECT  2.16 28.755 101.898 29.025 ;
     RECT  2.16 29.295 101.898 29.565 ;
     RECT  2.16 29.835 101.898 30.105 ;
     RECT  2.16 30.375 101.898 30.645 ;
     RECT  2.16 30.915 101.898 31.185 ;
     RECT  2.16 31.455 101.898 31.725 ;
     RECT  2.16 31.995 101.898 32.265 ;
     RECT  2.16 32.535 101.898 32.805 ;
     RECT  2.16 33.075 101.898 33.345 ;
     RECT  2.16 33.615 101.898 33.885 ;
     RECT  2.16 34.155 101.898 34.425 ;
     RECT  2.16 34.695 101.898 34.965 ;
     RECT  2.16 35.235 101.898 35.505 ;
     RECT  2.16 35.775 101.898 36.045 ;
     RECT  2.16 36.315 101.898 36.585 ;
     RECT  2.16 36.855 101.898 37.125 ;
     RECT  2.16 37.395 101.898 37.665 ;
     RECT  2.16 37.935 101.898 38.205 ;
     RECT  2.16 38.475 101.898 38.745 ;
     RECT  2.16 39.015 101.898 39.285 ;
     RECT  2.16 39.555 101.898 39.825 ;
     RECT  2.16 40.095 101.898 40.365 ;
     RECT  2.16 40.635 101.898 40.905 ;
     RECT  2.16 41.175 101.898 41.445 ;
     RECT  2.16 41.715 101.898 41.985 ;
     RECT  2.16 42.255 101.898 42.525 ;
     RECT  2.16 42.795 101.898 43.065 ;
     RECT  2.16 43.335 101.898 43.605 ;
     RECT  2.16 43.875 101.898 44.145 ;
     RECT  2.16 44.415 101.898 44.685 ;
     RECT  2.16 44.955 101.898 45.225 ;
     RECT  2.16 45.495 101.898 45.765 ;
     RECT  2.16 46.035 101.898 46.305 ;
     RECT  2.16 46.575 101.898 46.845 ;
     RECT  2.16 47.115 101.898 47.385 ;
     RECT  2.16 47.655 101.898 47.925 ;
     RECT  2.16 48.195 101.898 48.465 ;
     RECT  2.16 48.735 101.898 49.005 ;
     RECT  2.16 49.275 101.898 49.545 ;
     RECT  2.16 49.815 101.898 50.085 ;
     RECT  2.16 50.355 101.898 50.625 ;
     RECT  2.16 50.895 101.898 51.165 ;
     RECT  2.16 51.435 101.898 51.705 ;
     RECT  2.16 51.975 101.898 52.245 ;
     RECT  2.16 52.515 101.898 52.785 ;
     RECT  2.16 53.055 101.898 53.325 ;
     RECT  2.16 53.595 101.898 53.865 ;
     RECT  2.16 54.135 101.898 54.405 ;
     RECT  2.16 54.675 101.898 54.945 ;
     RECT  2.16 55.215 101.898 55.485 ;
     RECT  2.16 55.755 101.898 56.025 ;
     RECT  2.16 56.295 101.898 56.565 ;
     RECT  2.16 56.835 101.898 57.105 ;
     RECT  2.16 57.375 101.898 57.645 ;
     RECT  2.16 57.915 101.898 58.185 ;
     RECT  2.16 58.455 101.898 58.725 ;
     RECT  2.16 58.995 101.898 59.265 ;
     RECT  2.16 59.535 101.898 59.805 ;
     RECT  2.16 60.075 101.898 60.345 ;
     RECT  2.16 60.615 101.898 60.885 ;
     RECT  2.16 61.155 101.898 61.425 ;
     RECT  2.16 61.695 101.898 61.965 ;
     RECT  2.16 62.235 101.898 62.505 ;
     RECT  2.16 62.775 101.898 63.045 ;
     RECT  2.16 63.315 101.898 63.585 ;
     RECT  2.16 63.855 101.898 64.125 ;
     RECT  2.16 64.395 101.898 64.665 ;
     RECT  2.16 64.935 101.898 65.205 ;
     RECT  2.16 65.475 101.898 65.745 ;
     RECT  2.16 66.015 101.898 66.285 ;
     RECT  2.16 66.555 101.898 66.825 ;
     RECT  2.16 67.095 101.898 67.365 ;
     RECT  2.16 67.635 101.898 67.905 ;
     RECT  2.16 68.175 101.898 68.445 ;
     RECT  2.16 68.715 101.898 68.985 ;
     RECT  2.16 69.255 101.898 69.525 ;
     RECT  2.16 69.795 101.898 70.065 ;
     RECT  2.16 70.335 101.898 70.605 ;
     RECT  2.16 70.875 101.898 71.145 ;
     RECT  2.16 71.415 101.898 71.685 ;
     RECT  2.16 71.955 101.898 72.225 ;
     RECT  2.16 72.495 101.898 72.765 ;
     RECT  2.16 73.035 101.898 73.305 ;
     RECT  2.16 73.575 101.898 73.845 ;
     RECT  2.16 74.115 101.898 74.385 ;
     RECT  2.16 74.655 101.898 74.925 ;
     RECT  2.16 75.195 101.898 75.465 ;
     RECT  2.16 75.735 101.898 76.005 ;
     RECT  2.16 76.275 101.898 76.545 ;
     RECT  2.16 76.815 101.898 77.085 ;
     RECT  2.16 77.355 101.898 77.625 ;
     RECT  2.16 77.895 101.898 78.165 ;
     RECT  2.16 78.435 101.898 78.705 ;
     RECT  2.16 78.975 101.898 79.245 ;
     RECT  2.16 79.515 101.898 79.785 ;
     RECT  2.16 80.055 101.898 80.325 ;
     RECT  2.16 80.595 101.898 80.865 ;
     RECT  2.16 81.135 101.898 81.405 ;
     RECT  2.16 81.675 101.898 81.945 ;
     RECT  2.16 82.215 101.898 82.485 ;
     RECT  2.16 82.755 101.898 83.025 ;
     RECT  2.16 83.295 101.898 83.565 ;
     RECT  2.16 83.835 101.898 84.105 ;
     RECT  2.16 84.375 101.898 84.645 ;
     RECT  2.16 84.915 101.898 85.185 ;
     RECT  2.16 85.455 101.898 85.725 ;
     RECT  2.16 85.995 101.898 86.265 ;
     RECT  2.16 86.535 101.898 86.805 ;
     RECT  2.16 87.075 101.898 87.345 ;
     RECT  2.16 87.615 101.898 87.885 ;
     RECT  2.16 88.155 101.898 88.425 ;
     RECT  2.16 88.695 101.898 88.965 ;
     RECT  2.16 89.235 101.898 89.505 ;
     RECT  2.16 89.775 101.898 90.045 ;
     RECT  2.16 90.315 101.898 90.585 ;
     RECT  2.16 90.855 101.898 91.125 ;
     RECT  2.16 91.395 101.898 91.665 ;
     RECT  2.16 91.935 101.898 92.205 ;
     RECT  2.16 92.475 101.898 92.745 ;
     RECT  2.16 93.015 101.898 93.285 ;
     RECT  2.16 93.555 101.898 93.825 ;
     RECT  2.16 94.095 101.898 94.365 ;
     RECT  2.16 94.635 101.898 94.905 ;
     RECT  2.16 95.175 101.898 95.445 ;
     RECT  2.16 95.715 101.898 95.985 ;
     RECT  2.16 96.255 101.898 96.525 ;
     RECT  2.16 96.795 101.898 97.065 ;
     RECT  2.16 97.335 101.898 97.605 ;
     RECT  2.16 97.875 101.898 98.145 ;
     RECT  2.16 98.415 101.898 98.685 ;
     RECT  2.16 98.955 101.898 99.225 ;
     RECT  2.16 99.495 101.898 99.765 ;
     RECT  2.16 100.035 101.898 100.305 ;
     RECT  2.16 100.575 101.898 100.845 ;
     RECT  2.16 101.115 101.898 101.385 ;
     RECT  2.16 101.655 101.898 101.925 ;
     RECT  2.16 102.195 101.898 102.465 ;
     RECT  2.16 102.735 101.898 103.005 ;
     RECT  2.16 103.275 101.898 103.41 ;
    LAYER M1 ;
     RECT  2.16 2.151 101.898 103.419 ;
    LAYER M2 ;
     RECT  0.499 60.048 0.535 60.066 ;
     RECT  0.535 60.048 2.16 60.408 ;
     RECT  8.023 105.75 8.095 105.768 ;
     RECT  8.095 105.678 8.159 105.768 ;
     RECT  8.159 105.678 8.231 105.696 ;
     RECT  10.111 105.75 10.175 105.768 ;
     RECT  17.743 105.75 17.887 105.768 ;
     RECT  17.887 105.714 17.995 105.768 ;
     RECT  17.995 105.714 18.463 105.804 ;
     RECT  18.463 105.606 18.563 105.804 ;
     RECT  18.563 105.678 18.995 105.804 ;
     RECT  18.995 105.786 20.219 105.804 ;
     RECT  21.091 105.678 21.163 105.696 ;
     RECT  21.163 105.678 21.235 105.768 ;
     RECT  21.235 105.516 21.371 105.768 ;
     RECT  21.371 105.516 21.587 105.732 ;
     RECT  21.587 105.606 21.623 105.732 ;
     RECT  22.279 105.75 22.487 105.768 ;
     RECT  27.391 105.75 27.715 105.768 ;
     RECT  27.715 105.642 27.887 105.768 ;
     RECT  27.887 105.678 28.463 105.768 ;
     RECT  28.463 105.678 28.499 105.696 ;
     RECT  39.055 105.561 39.235 105.579 ;
     RECT  39.235 105.561 39.299 105.768 ;
     RECT  39.919 104.292 40.207 104.31 ;
     RECT  39.299 105.75 40.279 105.768 ;
     RECT  40.279 105.606 40.495 105.768 ;
     RECT  40.207 104.292 40.559 104.616 ;
     RECT  40.495 105.561 40.883 105.768 ;
     RECT  40.559 104.598 41.035 104.616 ;
     RECT  40.883 105.714 41.323 105.768 ;
     RECT  41.323 105.714 41.351 105.804 ;
     RECT  41.035 104.598 44.915 104.652 ;
     RECT  44.915 104.598 45.311 104.616 ;
     RECT  41.351 105.786 45.347 105.804 ;
     RECT  46.543 105.75 46.759 105.768 ;
     RECT  46.759 105.678 47.047 105.768 ;
     RECT  47.047 105.606 47.291 105.768 ;
     RECT  48.271 104.904 48.443 104.922 ;
     RECT  47.291 105.75 48.487 105.768 ;
     RECT  48.487 105.606 48.875 105.768 ;
     RECT  48.875 105.678 49.523 105.768 ;
     RECT  49.523 105.75 49.991 105.768 ;
     RECT  2.16 2.151 50.287 103.419 ;
     RECT  50.359 105.606 50.459 105.624 ;
     RECT  50.287 2.151 50.791 103.464 ;
     RECT  50.791 2.151 50.863 103.536 ;
     RECT  50.863 2.151 50.935 103.608 ;
     RECT  50.935 2.151 52.871 103.689 ;
     RECT  52.871 2.151 54.347 103.536 ;
     RECT  54.347 2.151 54.815 103.464 ;
     RECT  54.815 2.151 55.579 103.419 ;
     RECT  55.579 2.151 55.939 103.5 ;
     RECT  55.939 2.151 57.955 103.572 ;
     RECT  57.955 2.151 58.963 103.644 ;
     RECT  60.511 105.75 61.087 105.768 ;
     RECT  61.087 105.561 61.159 105.768 ;
     RECT  61.159 105.516 62.167 105.768 ;
     RECT  62.167 105.48 62.339 105.768 ;
     RECT  62.339 105.516 63.095 105.768 ;
     RECT  63.095 105.516 63.283 105.579 ;
     RECT  63.283 104.868 63.311 105.579 ;
     RECT  63.311 104.868 63.671 105.534 ;
     RECT  58.963 2.151 64.355 103.734 ;
     RECT  63.671 104.868 65.003 104.886 ;
     RECT  64.355 2.151 65.615 103.689 ;
     RECT  65.615 2.151 66.451 103.644 ;
     RECT  66.127 105.606 66.659 105.624 ;
     RECT  66.451 2.151 67.279 103.689 ;
     RECT  66.775 105.75 67.495 105.768 ;
     RECT  67.495 105.606 67.595 105.768 ;
     RECT  67.595 105.75 67.847 105.768 ;
     RECT  67.279 2.151 68.171 104.31 ;
     RECT  68.287 104.868 68.503 104.886 ;
     RECT  68.503 104.868 68.683 105.624 ;
     RECT  68.683 104.868 68.819 105.768 ;
     RECT  68.819 104.868 69.071 104.886 ;
     RECT  69.547 105.75 69.799 105.768 ;
     RECT  69.799 105.291 70.043 105.768 ;
     RECT  70.043 105.291 70.115 105.309 ;
     RECT  68.171 2.151 72.959 103.689 ;
     RECT  72.959 2.151 74.039 103.608 ;
     RECT  74.039 2.151 74.911 103.572 ;
     RECT  75.343 105.75 75.631 105.768 ;
     RECT  75.631 105.606 77.315 105.768 ;
     RECT  74.911 2.151 77.999 103.608 ;
     RECT  77.315 105.714 78.043 105.768 ;
     RECT  78.043 105.714 78.295 105.804 ;
     RECT  78.295 105.372 78.539 105.804 ;
     RECT  77.999 2.151 78.575 103.572 ;
     RECT  78.539 105.786 79.303 105.804 ;
     RECT  78.799 104.328 79.375 104.346 ;
     RECT  79.303 105.75 79.447 105.804 ;
     RECT  79.375 104.328 79.547 104.814 ;
     RECT  79.447 105.678 80.087 105.804 ;
     RECT  80.087 105.678 80.095 105.768 ;
     RECT  79.547 104.328 80.375 104.346 ;
     RECT  80.095 105.606 80.491 105.768 ;
     RECT  80.491 105.561 81.175 105.768 ;
     RECT  78.575 2.151 81.751 103.536 ;
     RECT  81.175 104.868 81.931 105.768 ;
     RECT  81.931 104.832 81.995 105.768 ;
     RECT  81.995 104.832 82.031 104.886 ;
     RECT  81.751 2.151 82.103 103.734 ;
     RECT  81.995 105.75 82.247 105.768 ;
     RECT  82.031 104.868 82.319 104.886 ;
     RECT  82.103 2.151 101.898 103.419 ;
     RECT  101.898 83.376 102.047 87.102 ;
     RECT  102.047 83.466 102.083 87.102 ;
     RECT  101.898 19.116 102.587 77.922 ;
     RECT  102.587 19.278 102.623 29.124 ;
     RECT  102.587 29.916 102.623 32.634 ;
     RECT  102.587 33.516 102.623 49.842 ;
     RECT  102.587 50.634 102.623 77.922 ;
     RECT  102.623 20.736 102.659 27.864 ;
     RECT  102.623 29.106 102.659 29.124 ;
     RECT  102.623 31.734 102.659 32.454 ;
     RECT  102.623 33.516 102.659 37.764 ;
     RECT  102.623 38.718 102.659 44.676 ;
     RECT  102.623 47.286 102.659 48.564 ;
     RECT  102.623 49.626 102.659 49.734 ;
     RECT  102.623 54.684 102.659 57.294 ;
     RECT  102.623 58.122 102.659 65.574 ;
     RECT  102.623 67.41 102.659 70.434 ;
     RECT  102.623 74.628 102.659 77.922 ;
     RECT  102.083 83.538 102.659 87.102 ;
     RECT  102.659 24.48 102.695 26.784 ;
     RECT  102.659 31.734 102.695 32.292 ;
     RECT  102.659 33.696 102.695 37.764 ;
     RECT  102.659 38.718 102.695 41.544 ;
     RECT  102.659 42.336 102.695 44.676 ;
     RECT  102.659 48.366 102.695 48.564 ;
     RECT  102.623 50.94 102.695 53.388 ;
     RECT  102.659 59.238 102.695 65.232 ;
     RECT  102.623 71.226 102.695 73.674 ;
     RECT  102.659 74.628 102.695 77.814 ;
     RECT  102.659 83.574 102.695 84.402 ;
     RECT  102.695 42.426 102.731 44.676 ;
     RECT  102.695 75.816 102.731 77.814 ;
     RECT  102.659 20.826 102.767 23.454 ;
     RECT  102.731 75.816 102.767 77.004 ;
     RECT  102.767 76.896 102.803 77.004 ;
     RECT  102.731 77.796 102.839 77.814 ;
     RECT  102.623 30.816 103.163 30.906 ;
     RECT  102.695 50.94 103.163 53.352 ;
     RECT  102.659 58.122 103.163 58.482 ;
     RECT  102.695 59.58 103.163 65.232 ;
     RECT  102.695 74.628 103.163 74.844 ;
     RECT  102.623 19.278 103.199 19.872 ;
     RECT  102.767 21.474 103.199 23.454 ;
     RECT  102.695 26.226 103.199 26.784 ;
     RECT  102.659 27.846 103.199 27.864 ;
     RECT  102.695 31.734 103.199 31.986 ;
     RECT  102.695 34.776 103.199 35.604 ;
     RECT  102.695 37.296 103.199 37.764 ;
     RECT  102.695 38.718 103.199 40.824 ;
     RECT  102.731 43.146 103.199 44.676 ;
     RECT  102.623 45.774 103.199 46.062 ;
     RECT  102.659 47.286 103.199 47.412 ;
     RECT  102.695 48.546 103.199 48.564 ;
     RECT  102.659 49.626 103.199 49.644 ;
     RECT  103.163 50.976 103.199 53.352 ;
     RECT  102.659 54.684 103.199 54.774 ;
     RECT  102.659 55.998 103.199 56.664 ;
     RECT  103.163 58.122 103.199 58.14 ;
     RECT  103.163 59.616 103.199 65.232 ;
     RECT  102.623 66.33 103.199 66.348 ;
     RECT  102.659 67.41 103.199 68.976 ;
     RECT  102.659 69.768 103.199 70.434 ;
     RECT  102.695 71.226 103.199 73.638 ;
     RECT  103.163 74.628 103.199 74.646 ;
     RECT  102.767 75.816 103.199 76.104 ;
     RECT  102.803 76.896 103.199 76.914 ;
     RECT  102.695 83.772 103.199 84.402 ;
     RECT  102.659 85.536 103.199 86.058 ;
     RECT  102.659 86.85 103.199 87.102 ;
     RECT  103.199 22.212 103.235 23.454 ;
     RECT  102.695 24.48 103.235 25.434 ;
     RECT  103.199 26.766 103.235 26.784 ;
     RECT  103.163 30.888 103.235 30.906 ;
     RECT  103.199 31.968 103.235 31.986 ;
     RECT  103.199 38.718 103.235 39.042 ;
     RECT  103.199 39.996 103.235 40.014 ;
     RECT  103.199 51.516 103.235 52.344 ;
     RECT  103.199 60.426 103.235 60.444 ;
     RECT  103.199 61.506 103.235 63.27 ;
     RECT  103.199 73.044 103.235 73.134 ;
     RECT  103.199 75.816 103.235 75.834 ;
     RECT  103.199 87.084 103.235 87.102 ;
     RECT  103.199 19.278 103.271 19.764 ;
     RECT  103.199 37.296 103.271 37.314 ;
     RECT  103.235 51.516 103.271 51.894 ;
     RECT  103.199 55.998 103.271 56.016 ;
     RECT  103.235 61.74 103.271 62.46 ;
     RECT  103.235 73.044 103.271 73.062 ;
     RECT  103.199 84.384 103.271 84.402 ;
     RECT  103.271 19.746 103.307 19.764 ;
     RECT  103.235 22.518 103.307 22.734 ;
     RECT  103.271 51.606 103.307 51.624 ;
     RECT  103.307 22.554 103.955 22.572 ;
     RECT  103.199 34.776 103.991 34.794 ;
     RECT  103.235 38.718 103.991 38.736 ;
     RECT  103.963 30.15 104.063 30.168 ;
    LAYER M3 ;
     RECT  2.415 2.143 2.505 2.413 ;
     RECT  5.115 2.143 5.205 2.413 ;
     RECT  7.815 2.143 7.905 2.413 ;
     RECT  10.515 2.143 10.605 2.413 ;
     RECT  13.215 2.143 13.305 2.413 ;
     RECT  15.915 2.143 16.005 2.413 ;
     RECT  18.615 2.143 18.705 2.413 ;
     RECT  21.315 2.143 21.405 2.413 ;
     RECT  24.015 2.143 24.105 2.413 ;
     RECT  26.715 2.143 26.805 2.413 ;
     RECT  29.415 2.143 29.505 2.413 ;
     RECT  32.115 2.143 32.205 2.413 ;
     RECT  34.815 2.143 34.905 2.413 ;
     RECT  37.515 2.143 37.605 2.413 ;
     RECT  40.215 2.143 40.305 2.413 ;
     RECT  42.915 2.143 43.005 2.413 ;
     RECT  45.615 2.143 45.705 2.413 ;
     RECT  48.315 2.143 48.405 2.413 ;
     RECT  51.015 2.143 51.105 2.413 ;
     RECT  53.715 2.143 53.805 2.413 ;
     RECT  56.415 2.143 56.505 2.413 ;
     RECT  59.115 2.143 59.205 2.413 ;
     RECT  61.815 2.143 61.905 2.413 ;
     RECT  64.515 2.143 64.605 2.413 ;
     RECT  67.215 2.143 67.305 2.413 ;
     RECT  69.915 2.143 70.005 2.413 ;
     RECT  72.615 2.143 72.705 2.413 ;
     RECT  75.315 2.143 75.405 2.413 ;
     RECT  78.015 2.143 78.105 2.413 ;
     RECT  80.715 2.143 80.805 2.413 ;
     RECT  83.415 2.143 83.505 2.413 ;
     RECT  86.115 2.143 86.205 2.413 ;
     RECT  88.815 2.143 88.905 2.413 ;
     RECT  91.515 2.143 91.605 2.413 ;
     RECT  94.215 2.143 94.305 2.413 ;
     RECT  96.915 2.143 97.005 2.413 ;
     RECT  99.615 2.143 99.705 2.413 ;
     RECT  90.072 13.531 90.09 13.567 ;
     RECT  88.815 2.413 89.097 13.603 ;
     RECT  90.072 13.567 90.378 13.603 ;
     RECT  91.515 2.413 91.797 13.711 ;
     RECT  88.815 13.603 90.378 13.801 ;
     RECT  91.224 13.711 91.797 13.801 ;
     RECT  94.215 2.413 94.497 13.837 ;
     RECT  88.815 13.801 91.797 13.873 ;
     RECT  87.696 13.711 87.714 13.945 ;
     RECT  87.696 13.945 87.75 13.981 ;
     RECT  88.776 13.873 91.797 13.981 ;
     RECT  87.696 13.981 91.854 14.107 ;
     RECT  87.3 14.107 91.854 14.215 ;
     RECT  92.88 14.143 92.898 14.215 ;
     RECT  93.708 13.837 94.497 14.215 ;
     RECT  87.3 14.215 94.497 14.251 ;
     RECT  86.115 2.413 86.397 14.485 ;
     RECT  87.3 14.251 94.626 14.485 ;
     RECT  87.3 14.485 94.95 14.521 ;
     RECT  95.76 14.251 95.778 14.521 ;
     RECT  86.115 14.485 86.454 14.647 ;
     RECT  87.3 14.521 95.778 14.647 ;
     RECT  87.3 14.647 96.03 14.719 ;
     RECT  84.852 14.251 84.87 14.755 ;
     RECT  86.004 14.647 86.454 14.755 ;
     RECT  86.004 14.755 86.49 14.791 ;
     RECT  87.3 14.719 96.138 14.791 ;
     RECT  84.42 14.755 84.87 15.019 ;
     RECT  83.415 2.413 83.697 15.025 ;
     RECT  84.42 15.019 85.158 15.025 ;
     RECT  86.004 14.791 96.138 15.025 ;
     RECT  96.915 2.413 97.197 15.025 ;
     RECT  83.376 15.025 83.697 15.061 ;
     RECT  84.42 15.025 97.197 15.061 ;
     RECT  83.376 15.061 97.197 15.323 ;
     RECT  83.376 15.323 83.697 15.691 ;
     RECT  82.656 15.691 83.697 15.835 ;
     RECT  84.564 15.323 97.197 15.871 ;
     RECT  82.08 15.835 83.697 16.141 ;
     RECT  84.564 15.871 97.326 16.141 ;
     RECT  78.015 2.413 78.297 16.303 ;
     RECT  80.715 2.413 80.997 16.375 ;
     RECT  82.08 16.141 97.326 16.375 ;
     RECT  78.015 16.303 78.678 16.529 ;
     RECT  80.715 16.375 97.326 16.609 ;
     RECT  78.015 16.529 78.297 16.645 ;
     RECT  99.615 2.413 99.897 16.681 ;
     RECT  80.715 16.609 97.614 16.685 ;
     RECT  87.84 16.685 97.614 16.709 ;
     RECT  87.84 16.709 97.542 16.979 ;
     RECT  87.84 16.979 97.47 17.069 ;
     RECT  77.544 16.645 78.297 17.339 ;
     RECT  77.904 17.339 78.297 17.383 ;
     RECT  72.615 2.413 72.897 17.455 ;
     RECT  87.84 17.069 97.326 17.467 ;
     RECT  80.715 16.685 86.958 17.581 ;
     RECT  87.804 17.467 97.326 17.581 ;
     RECT  80.715 17.581 97.326 17.609 ;
     RECT  80.715 17.609 97.29 17.689 ;
     RECT  98.892 16.681 99.897 17.761 ;
     RECT  72.615 17.455 72.99 17.879 ;
     RECT  80.64 17.689 97.29 17.923 ;
     RECT  80.208 17.923 97.29 18.139 ;
     RECT  76.932 17.455 76.95 18.149 ;
     RECT  80.172 18.139 97.29 18.229 ;
     RECT  77.904 17.383 78.75 18.535 ;
     RECT  80.136 18.229 97.29 18.535 ;
     RECT  76.86 18.661 76.878 18.761 ;
     RECT  72.615 17.879 72.897 18.805 ;
     RECT  73.62 18.157 73.638 18.805 ;
     RECT  77.904 18.535 97.29 18.805 ;
     RECT  72.615 18.805 73.638 18.959 ;
     RECT  68.724 17.995 68.742 19.075 ;
     RECT  77.904 18.805 97.362 19.201 ;
     RECT  98.496 17.761 99.897 19.201 ;
     RECT  100.728 19.111 100.746 19.201 ;
     RECT  102.564 19.111 102.582 19.273 ;
     RECT  77.904 19.201 99.897 19.345 ;
     RECT  77.688 19.345 99.897 19.381 ;
     RECT  102.492 19.273 103.266 19.382 ;
     RECT  77.688 19.381 99.918 19.543 ;
     RECT  100.728 19.201 100.998 19.543 ;
     RECT  77.688 19.543 101.502 19.615 ;
     RECT  102.528 19.382 103.266 19.741 ;
     RECT  75.315 2.413 75.597 19.777 ;
     RECT  77.688 19.615 101.718 20.011 ;
     RECT  74.664 19.777 75.597 20.039 ;
     RECT  73.62 18.959 73.638 20.155 ;
     RECT  77.616 20.011 101.718 20.155 ;
     RECT  77.472 20.155 101.718 20.203 ;
     RECT  102.528 19.741 103.302 20.203 ;
     RECT  73.62 20.155 74.07 20.309 ;
     RECT  68.724 19.075 69.066 20.317 ;
     RECT  67.215 2.413 67.497 20.425 ;
     RECT  68.256 20.317 69.066 20.425 ;
     RECT  76.392 19.885 76.41 20.695 ;
     RECT  77.472 20.203 103.302 20.695 ;
     RECT  75.315 20.039 75.597 20.731 ;
     RECT  76.392 20.695 103.302 20.731 ;
     RECT  73.62 20.309 73.638 21.091 ;
     RECT  64.515 2.413 64.797 21.271 ;
     RECT  75.315 20.731 103.302 21.293 ;
     RECT  72.615 18.959 72.897 21.361 ;
     RECT  75.315 21.293 103.194 21.361 ;
     RECT  75.06 21.361 103.194 21.389 ;
     RECT  64.332 21.271 64.797 21.397 ;
     RECT  63.936 21.397 64.797 21.433 ;
     RECT  65.736 21.271 65.754 21.433 ;
     RECT  75.06 21.389 95.166 21.461 ;
     RECT  67.215 20.425 69.066 21.496 ;
     RECT  63.936 21.433 65.754 21.499 ;
     RECT  63.936 21.499 66.222 21.505 ;
     RECT  73.62 21.091 73.746 21.505 ;
     RECT  63.504 21.505 66.222 21.541 ;
     RECT  67.104 21.496 69.066 21.541 ;
     RECT  72.396 21.361 72.897 21.541 ;
     RECT  73.62 21.505 74.286 21.541 ;
     RECT  75.06 21.461 95.13 21.659 ;
     RECT  63.468 21.541 69.066 21.703 ;
     RECT  69.915 2.413 70.197 21.703 ;
     RECT  72.396 21.541 74.286 21.739 ;
     RECT  63.468 21.703 70.197 21.775 ;
     RECT  63.108 21.775 70.197 21.811 ;
     RECT  63 21.811 70.197 21.937 ;
     RECT  61.815 2.413 62.097 21.973 ;
     RECT  61.632 21.973 62.097 22.045 ;
     RECT  62.856 21.937 70.197 22.045 ;
     RECT  96.012 21.389 103.194 22.199 ;
     RECT  98.496 22.199 103.194 22.207 ;
     RECT  71.892 21.739 74.286 22.235 ;
     RECT  96.012 22.199 97.686 22.351 ;
     RECT  95.94 22.351 97.686 22.469 ;
     RECT  61.632 22.045 70.197 22.513 ;
     RECT  98.496 22.207 103.23 22.513 ;
     RECT  98.496 22.513 103.302 22.549 ;
     RECT  59.115 2.413 59.397 22.585 ;
     RECT  61.596 22.513 70.197 22.585 ;
     RECT  58.104 22.585 59.397 22.621 ;
     RECT  61.164 22.585 70.197 22.621 ;
     RECT  75.096 21.659 95.13 22.621 ;
     RECT  61.128 22.621 70.197 22.711 ;
     RECT  98.496 22.549 103.95 22.733 ;
     RECT  75.096 22.621 95.202 22.739 ;
     RECT  57.564 22.621 59.454 22.747 ;
     RECT  98.496 22.733 101.682 22.781 ;
     RECT  102.6 22.733 103.95 22.829 ;
     RECT  57.564 22.747 59.778 22.891 ;
     RECT  61.128 22.711 70.29 22.891 ;
     RECT  71.82 22.585 71.838 22.891 ;
     RECT  61.128 22.891 71.838 23.017 ;
     RECT  72.615 22.235 74.286 23.017 ;
     RECT  96.408 22.469 97.686 23.125 ;
     RECT  98.496 22.781 100.35 23.125 ;
     RECT  61.128 23.017 74.286 23.131 ;
     RECT  75.096 22.739 95.094 23.131 ;
     RECT  56.415 2.413 56.697 23.251 ;
     RECT  96.408 23.125 100.35 23.279 ;
     RECT  51.015 2.413 51.297 23.287 ;
     RECT  53.715 2.413 53.997 23.287 ;
     RECT  56.088 23.251 56.697 23.287 ;
     RECT  57.564 22.891 60.174 23.287 ;
     RECT  101.088 22.781 101.682 23.351 ;
     RECT  53.28 23.287 53.997 23.371 ;
     RECT  50.976 23.287 51.297 23.395 ;
     RECT  52.668 23.371 53.997 23.395 ;
     RECT  54.756 23.287 54.774 23.395 ;
     RECT  55.584 23.287 60.174 23.395 ;
     RECT  50.976 23.395 51.858 23.431 ;
     RECT  52.668 23.395 60.174 23.431 ;
     RECT  96.012 23.431 96.03 23.549 ;
     RECT  61.128 23.131 95.094 23.563 ;
     RECT  98.352 23.279 100.35 23.656 ;
     RECT  101.088 23.351 101.106 23.656 ;
     RECT  98.352 23.656 101.106 23.657 ;
     RECT  61.092 23.563 95.094 23.659 ;
     RECT  50.256 23.431 60.174 23.665 ;
     RECT  60.984 23.659 95.094 23.665 ;
     RECT  102.6 22.829 103.23 23.693 ;
     RECT  50.256 23.665 95.094 23.791 ;
     RECT  95.832 23.557 95.85 23.791 ;
     RECT  102.6 23.693 103.194 23.851 ;
     RECT  102.564 23.851 103.194 23.947 ;
     RECT  50.256 23.791 95.85 24.205 ;
     RECT  102.024 23.947 103.194 24.232 ;
     RECT  98.352 23.657 100.134 24.241 ;
     RECT  101.988 24.232 103.194 24.269 ;
     RECT  96.915 23.279 97.578 24.331 ;
     RECT  98.316 24.241 100.134 24.359 ;
     RECT  100.944 23.657 101.106 24.403 ;
     RECT  102.492 24.269 103.194 24.427 ;
     RECT  49.644 24.205 95.85 24.439 ;
     RECT  48.315 2.413 48.597 24.475 ;
     RECT  49.644 24.439 95.922 24.475 ;
     RECT  96.876 24.331 97.578 24.475 ;
     RECT  98.568 24.359 100.134 24.511 ;
     RECT  100.872 24.403 101.106 24.511 ;
     RECT  45.615 2.413 45.897 24.637 ;
     RECT  98.568 24.511 101.106 24.637 ;
     RECT  48.315 24.475 97.578 25.141 ;
     RECT  98.568 24.637 101.502 25.141 ;
     RECT  48.24 25.141 101.502 25.213 ;
     RECT  102.492 24.427 103.23 25.213 ;
     RECT  48.24 25.213 103.23 25.241 ;
     RECT  48.315 25.241 103.23 25.277 ;
     RECT  48.315 25.277 79.902 25.475 ;
     RECT  80.715 25.277 103.23 25.805 ;
     RECT  44.316 25.285 44.334 25.987 ;
     RECT  45.288 24.637 45.897 25.987 ;
     RECT  48.315 25.475 79.83 26.203 ;
     RECT  80.715 25.805 103.194 26.203 ;
     RECT  48.315 26.203 103.194 26.429 ;
     RECT  48.315 26.429 101.178 26.635 ;
     RECT  102.024 26.429 103.194 26.761 ;
     RECT  48.06 26.635 101.178 26.789 ;
     RECT  50.796 26.789 51.297 26.825 ;
     RECT  44.316 25.987 45.897 26.941 ;
     RECT  102.024 26.761 103.23 27.053 ;
     RECT  48.06 26.789 50.058 27.059 ;
     RECT  44.316 26.941 46.134 27.067 ;
     RECT  42.915 2.413 43.197 27.175 ;
     RECT  44.316 27.067 46.206 27.175 ;
     RECT  52.308 26.789 101.178 27.211 ;
     RECT  102.024 27.053 102.654 27.211 ;
     RECT  42.915 27.175 46.206 27.329 ;
     RECT  52.308 27.211 102.654 27.329 ;
     RECT  52.524 27.329 55.638 27.341 ;
     RECT  56.376 27.329 102.654 27.599 ;
     RECT  52.56 27.341 55.638 27.671 ;
     RECT  51.015 26.825 51.297 27.841 ;
     RECT  56.415 27.599 102.654 27.841 ;
     RECT  48.06 27.059 49.518 27.913 ;
     RECT  56.415 27.841 103.194 27.917 ;
     RECT  51.015 27.841 51.39 27.941 ;
     RECT  52.92 27.671 55.638 27.941 ;
     RECT  57.564 27.917 103.194 28.109 ;
     RECT  51.015 27.941 51.318 28.175 ;
     RECT  57.564 28.109 102.618 28.493 ;
     RECT  57.564 28.493 101.61 28.541 ;
     RECT  42.915 27.329 45.897 28.759 ;
     RECT  47.16 27.607 47.178 28.759 ;
     RECT  48.06 27.913 49.878 28.787 ;
     RECT  55.476 27.941 55.638 28.795 ;
     RECT  56.415 27.917 56.697 28.795 ;
     RECT  55.476 28.795 56.697 28.957 ;
     RECT  57.564 28.541 97.65 28.957 ;
     RECT  55.476 28.957 97.65 29.057 ;
     RECT  52.92 27.941 53.997 29.065 ;
     RECT  102.564 28.493 102.618 29.101 ;
     RECT  52.92 29.065 54.126 29.219 ;
     RECT  98.424 28.541 101.61 29.227 ;
     RECT  102.564 29.101 102.654 29.227 ;
     RECT  96.876 29.057 97.65 29.299 ;
     RECT  98.424 29.227 102.654 29.299 ;
     RECT  96.876 29.299 102.654 29.357 ;
     RECT  96.876 29.357 102.618 29.525 ;
     RECT  51.015 28.175 51.297 29.605 ;
     RECT  100.872 29.525 102.618 29.741 ;
     RECT  100.872 29.741 101.286 29.759 ;
     RECT  55.476 29.057 96.138 29.839 ;
     RECT  96.876 29.525 100.026 29.839 ;
     RECT  42.915 28.759 47.178 29.875 ;
     RECT  48.06 28.787 49.518 29.875 ;
     RECT  52.92 29.219 53.997 30.139 ;
     RECT  104.04 30.136 104.058 30.145 ;
     RECT  103.968 30.145 104.058 30.173 ;
     RECT  103.968 30.173 103.986 30.221 ;
     RECT  42.915 29.875 49.518 30.307 ;
     RECT  55.476 29.839 100.026 30.413 ;
     RECT  102.024 29.741 102.618 30.479 ;
     RECT  52.92 30.139 54.234 30.541 ;
     RECT  101.124 29.759 101.286 30.571 ;
     RECT  96.84 30.413 100.026 30.701 ;
     RECT  52.632 30.541 54.234 30.721 ;
     RECT  102.492 30.479 102.618 30.811 ;
     RECT  102.492 30.811 103.158 30.883 ;
     RECT  52.632 30.721 54.558 30.955 ;
     RECT  55.476 30.413 95.994 30.955 ;
     RECT  101.124 30.571 101.502 30.955 ;
     RECT  102.492 30.883 103.23 30.989 ;
     RECT  96.915 30.701 100.026 30.991 ;
     RECT  100.944 30.955 101.502 30.991 ;
     RECT  96.915 30.991 101.502 31.243 ;
     RECT  102.492 30.989 102.618 31.243 ;
     RECT  42.48 30.307 49.518 31.289 ;
     RECT  52.452 30.955 95.994 31.459 ;
     RECT  96.915 31.243 102.618 31.459 ;
     RECT  52.452 31.459 102.618 31.685 ;
     RECT  58.644 31.685 102.618 31.729 ;
     RECT  58.644 31.729 103.194 31.829 ;
     RECT  102.528 31.829 103.194 31.963 ;
     RECT  52.452 31.685 57.834 32.063 ;
     RECT  102.528 31.963 103.23 32.429 ;
     RECT  58.644 31.829 101.502 32.459 ;
     RECT  101.484 32.459 101.502 32.587 ;
     RECT  102.528 32.429 102.69 32.587 ;
     RECT  101.484 32.587 102.69 32.717 ;
     RECT  51.015 29.605 51.642 32.809 ;
     RECT  52.452 32.063 57.51 32.809 ;
     RECT  51.015 32.809 57.51 32.845 ;
     RECT  58.644 32.459 100.746 32.845 ;
     RECT  51.015 32.845 100.746 33.385 ;
     RECT  101.484 32.717 102.654 33.385 ;
     RECT  51.015 33.385 102.654 33.538 ;
     RECT  40.215 2.413 40.497 33.655 ;
     RECT  51.015 33.538 102.69 33.683 ;
     RECT  51.015 33.683 101.358 33.719 ;
     RECT  42.48 31.289 49.338 33.931 ;
     RECT  41.868 33.931 49.338 33.961 ;
     RECT  50.22 33.151 50.238 33.961 ;
     RECT  102.564 33.683 102.69 33.965 ;
     RECT  39.708 33.655 40.497 34.051 ;
     RECT  39.708 34.051 40.842 34.079 ;
     RECT  102.6 33.965 102.69 34.123 ;
     RECT  41.868 33.961 50.238 34.223 ;
     RECT  58.644 33.719 101.358 34.259 ;
     RECT  58.788 34.259 101.358 34.411 ;
     RECT  58.788 34.411 101.502 34.465 ;
     RECT  51.015 33.719 57.51 34.591 ;
     RECT  50.976 34.591 57.51 34.627 ;
     RECT  102.6 34.123 103.158 34.699 ;
     RECT  58.788 34.465 101.574 34.795 ;
     RECT  102.6 34.699 103.194 34.795 ;
     RECT  103.968 34.507 103.986 34.799 ;
     RECT  58.788 34.795 103.194 34.961 ;
     RECT  42.915 34.223 50.238 35.131 ;
     RECT  39.852 34.079 40.842 35.203 ;
     RECT  41.868 34.223 41.886 35.203 ;
     RECT  42.768 35.131 50.238 35.213 ;
     RECT  39.852 35.203 41.886 35.275 ;
     RECT  50.976 34.627 57.726 35.401 ;
     RECT  58.788 34.961 97.47 35.401 ;
     RECT  98.316 34.961 103.194 35.609 ;
     RECT  98.316 35.609 102.69 35.735 ;
     RECT  50.976 35.401 97.47 35.771 ;
     RECT  96.915 35.771 97.47 35.815 ;
     RECT  98.316 35.735 100.71 35.815 ;
     RECT  42.915 35.213 50.238 35.851 ;
     RECT  50.976 35.771 96.174 35.851 ;
     RECT  101.448 35.735 102.69 35.969 ;
     RECT  96.915 35.815 100.71 36.239 ;
     RECT  42.915 35.851 96.174 36.347 ;
     RECT  98.424 36.239 100.71 36.419 ;
     RECT  101.556 35.969 102.69 36.619 ;
     RECT  61.815 36.347 96.174 36.625 ;
     RECT  96.915 36.239 97.398 36.625 ;
     RECT  61.815 36.625 97.398 36.689 ;
     RECT  39.852 35.275 42.102 36.907 ;
     RECT  42.915 36.347 60.93 36.907 ;
     RECT  101.556 36.619 103.194 36.907 ;
     RECT  37.515 2.413 37.797 36.931 ;
     RECT  98.568 36.419 100.71 36.931 ;
     RECT  101.556 36.907 103.266 36.931 ;
     RECT  37.515 36.931 37.854 37.021 ;
     RECT  38.844 34.087 38.862 37.021 ;
     RECT  37.515 37.021 38.862 37.165 ;
     RECT  39.852 36.907 60.93 37.165 ;
     RECT  93.96 36.689 97.398 37.201 ;
     RECT  98.568 36.931 103.266 37.201 ;
     RECT  93.96 37.201 103.266 37.319 ;
     RECT  61.815 36.689 93.15 37.435 ;
     RECT  93.96 37.319 103.194 37.435 ;
     RECT  61.815 37.435 103.194 37.463 ;
     RECT  37.044 37.165 60.93 37.471 ;
     RECT  61.815 37.463 101.25 37.697 ;
     RECT  101.988 37.463 103.194 37.769 ;
     RECT  101.988 37.769 102.618 37.859 ;
     RECT  101.232 37.697 101.25 37.895 ;
     RECT  61.815 37.697 100.314 38.039 ;
     RECT  61.815 38.039 99.954 38.129 ;
     RECT  36.72 37.471 60.93 38.203 ;
     RECT  61.815 38.129 96.174 38.203 ;
     RECT  35.964 34.465 35.982 38.515 ;
     RECT  36.72 38.203 96.174 38.515 ;
     RECT  102.024 37.859 102.618 38.785 ;
     RECT  96.915 38.129 99.954 38.821 ;
     RECT  35.964 38.515 96.174 38.911 ;
     RECT  96.915 38.821 100.206 38.911 ;
     RECT  35.964 38.911 100.206 39.019 ;
     RECT  102.024 38.785 102.762 39.019 ;
     RECT  35.964 39.019 100.242 39.091 ;
     RECT  101.088 39.055 101.106 39.091 ;
     RECT  102.024 39.019 103.23 39.149 ;
     RECT  35.964 39.091 101.106 39.209 ;
     RECT  103.968 38.713 103.986 39.245 ;
     RECT  35.964 39.209 95.958 39.317 ;
     RECT  96.696 39.209 101.106 39.515 ;
     RECT  98.064 39.515 101.106 39.559 ;
     RECT  34.815 2.413 35.097 39.595 ;
     RECT  35.964 39.317 95.85 39.595 ;
     RECT  98.064 39.559 101.25 40.019 ;
     RECT  96.696 39.515 97.29 40.027 ;
     RECT  101.052 40.019 101.25 40.027 ;
     RECT  101.052 40.027 101.358 40.099 ;
     RECT  102.6 39.149 103.23 40.099 ;
     RECT  34.815 39.595 95.85 40.135 ;
     RECT  101.052 40.099 103.23 40.205 ;
     RECT  34.815 40.135 95.886 40.369 ;
     RECT  96.624 40.027 97.29 40.369 ;
     RECT  34.815 40.369 97.29 40.405 ;
     RECT  98.064 40.019 100.314 40.405 ;
     RECT  102.528 40.205 103.23 40.433 ;
     RECT  32.115 2.413 32.397 40.675 ;
     RECT  33.156 40.135 33.174 40.675 ;
     RECT  102.6 40.433 103.23 40.781 ;
     RECT  32.115 40.675 33.174 40.829 ;
     RECT  34.815 40.405 100.314 40.873 ;
     RECT  101.052 40.205 101.502 40.873 ;
     RECT  29.415 2.413 29.697 40.945 ;
     RECT  34.815 40.873 101.502 40.973 ;
     RECT  33.156 40.829 33.174 41.071 ;
     RECT  33.156 41.071 33.246 41.099 ;
     RECT  102.6 40.781 103.194 41.165 ;
     RECT  102.6 41.165 102.69 41.215 ;
     RECT  102.024 41.215 102.69 41.555 ;
     RECT  34.815 40.973 100.89 41.639 ;
     RECT  34.815 41.639 100.062 41.747 ;
     RECT  102.024 41.555 102.654 42.025 ;
     RECT  101.124 42.025 102.654 42.029 ;
     RECT  101.124 42.029 101.502 42.125 ;
     RECT  29.415 40.945 30.006 42.151 ;
     RECT  32.115 40.829 32.397 42.151 ;
     RECT  33.228 41.099 33.246 42.151 ;
     RECT  29.415 42.151 30.186 42.251 ;
     RECT  29.415 42.251 30.006 42.295 ;
     RECT  102.528 42.029 102.654 42.316 ;
     RECT  31.896 42.151 32.397 42.323 ;
     RECT  102.528 42.316 102.69 42.421 ;
     RECT  34.815 41.747 99.99 42.461 ;
     RECT  34.815 42.461 97.326 42.485 ;
     RECT  33.228 42.151 33.642 42.565 ;
     RECT  33.228 42.565 33.966 42.601 ;
     RECT  34.815 42.485 92.97 42.601 ;
     RECT  98.064 42.461 99.99 42.601 ;
     RECT  101.124 42.125 101.43 42.629 ;
     RECT  101.124 42.629 101.178 42.727 ;
     RECT  98.064 42.601 100.242 42.835 ;
     RECT  32.115 42.323 32.397 42.961 ;
     RECT  33.228 42.601 92.97 42.961 ;
     RECT  93.78 42.485 97.326 42.989 ;
     RECT  98.064 42.835 100.35 43.141 ;
     RECT  101.088 42.727 101.178 43.141 ;
     RECT  102.528 42.421 102.726 43.141 ;
     RECT  93.78 42.989 97.29 43.259 ;
     RECT  98.064 43.141 101.178 43.259 ;
     RECT  32.115 42.961 92.97 43.375 ;
     RECT  93.78 43.259 97.254 43.375 ;
     RECT  102.528 43.141 103.194 43.375 ;
     RECT  98.424 43.259 101.178 43.565 ;
     RECT  98.424 43.565 100.026 43.571 ;
     RECT  100.872 43.565 101.178 43.771 ;
     RECT  102.024 43.375 103.194 43.771 ;
     RECT  100.872 43.771 103.194 43.835 ;
     RECT  98.46 43.571 100.026 43.853 ;
     RECT  98.532 43.853 100.026 43.871 ;
     RECT  32.115 43.375 97.254 44.149 ;
     RECT  98.568 43.871 100.026 44.455 ;
     RECT  100.872 43.835 101.142 44.455 ;
     RECT  98.568 44.455 101.142 44.483 ;
     RECT  102.024 43.835 103.194 44.725 ;
     RECT  32.115 44.149 97.362 44.761 ;
     RECT  32.115 44.761 97.506 44.851 ;
     RECT  98.568 44.483 100.638 44.851 ;
     RECT  101.988 44.725 103.194 44.909 ;
     RECT  32.115 44.851 100.638 44.951 ;
     RECT  32.115 44.951 97.197 44.959 ;
     RECT  29.052 42.295 30.006 44.995 ;
     RECT  32.04 44.959 97.197 45.121 ;
     RECT  98.1 44.951 100.638 45.197 ;
     RECT  102.024 44.909 103.194 45.389 ;
     RECT  100.692 45.301 100.962 45.535 ;
     RECT  32.004 45.121 97.197 45.595 ;
     RECT  31.86 45.595 97.197 45.689 ;
     RECT  32.115 45.689 97.197 45.805 ;
     RECT  98.1 45.197 99.954 45.931 ;
     RECT  100.692 45.535 101.214 45.931 ;
     RECT  98.1 45.931 101.214 45.959 ;
     RECT  98.1 45.959 101.106 46.031 ;
     RECT  102.564 45.389 103.194 46.067 ;
     RECT  102.564 46.067 102.618 46.219 ;
     RECT  98.856 46.031 101.106 46.337 ;
     RECT  32.115 45.805 97.326 46.381 ;
     RECT  98.1 46.031 98.118 46.381 ;
     RECT  28.548 44.995 30.006 46.651 ;
     RECT  28.548 46.651 30.114 46.805 ;
     RECT  101.988 46.219 102.618 46.913 ;
     RECT  30.852 45.535 30.87 46.921 ;
     RECT  32.115 46.381 98.118 46.921 ;
     RECT  98.856 46.337 101.034 46.921 ;
     RECT  30.852 46.921 31.014 47.075 ;
     RECT  32.115 46.921 101.034 47.083 ;
     RECT  102.564 46.913 102.618 47.147 ;
     RECT  102.6 47.147 102.618 47.275 ;
     RECT  32.115 47.083 101.574 47.353 ;
     RECT  31.968 47.353 101.574 47.389 ;
     RECT  102.6 47.275 103.194 47.417 ;
     RECT  31.932 47.389 101.574 47.659 ;
     RECT  28.548 46.805 30.006 47.857 ;
     RECT  30.852 47.075 30.87 47.857 ;
     RECT  31.932 47.659 101.718 47.885 ;
     RECT  102.6 47.417 102.654 47.929 ;
     RECT  28.548 47.857 30.87 48.119 ;
     RECT  31.932 47.885 100.962 48.119 ;
     RECT  30.852 48.119 30.87 48.235 ;
     RECT  101.736 47.929 102.654 48.299 ;
     RECT  102.564 48.299 102.654 48.361 ;
     RECT  30.852 48.235 30.978 48.389 ;
     RECT  32.115 48.119 100.962 48.425 ;
     RECT  101.736 48.299 101.754 48.425 ;
     RECT  102.564 48.361 102.69 48.541 ;
     RECT  101.484 48.973 101.502 49.037 ;
     RECT  102.564 48.541 103.194 49.195 ;
     RECT  101.988 49.195 103.194 49.235 ;
     RECT  32.115 48.425 100.494 49.441 ;
     RECT  32.115 49.441 100.962 49.577 ;
     RECT  100.692 49.577 100.962 49.855 ;
     RECT  100.692 49.855 101.574 49.963 ;
     RECT  102.528 49.235 103.194 49.963 ;
     RECT  100.692 49.963 103.194 50.009 ;
     RECT  32.115 49.577 99.897 50.279 ;
     RECT  100.692 50.009 101.574 50.279 ;
     RECT  33.12 50.279 99.897 50.315 ;
     RECT  30.852 48.389 30.87 50.395 ;
     RECT  32.115 50.279 32.397 50.395 ;
     RECT  33.156 50.315 99.897 50.693 ;
     RECT  33.912 50.693 99.897 51.089 ;
     RECT  101.232 50.279 101.502 51.197 ;
     RECT  102.492 50.009 103.194 51.331 ;
     RECT  33.156 50.693 33.174 51.475 ;
     RECT  33.912 51.089 97.65 51.475 ;
     RECT  101.988 51.331 103.194 51.499 ;
     RECT  101.988 51.499 103.23 51.511 ;
     RECT  101.988 51.511 103.266 51.601 ;
     RECT  98.604 51.089 99.897 51.673 ;
     RECT  100.98 51.241 100.998 51.673 ;
     RECT  101.988 51.601 103.302 51.725 ;
     RECT  98.604 51.673 100.998 51.871 ;
     RECT  101.988 51.725 103.266 51.899 ;
     RECT  33.156 51.475 97.65 51.907 ;
     RECT  98.532 51.871 100.998 51.907 ;
     RECT  33.156 51.907 100.998 51.965 ;
     RECT  98.424 51.965 100.998 51.979 ;
     RECT  101.988 51.899 103.23 51.979 ;
     RECT  98.424 51.979 103.23 52.349 ;
     RECT  98.424 52.349 103.194 52.439 ;
     RECT  98.424 52.439 101.466 52.511 ;
     RECT  33.156 51.965 97.326 52.717 ;
     RECT  98.424 52.511 101.142 52.817 ;
     RECT  98.424 52.817 99.897 52.825 ;
     RECT  33.156 52.717 97.362 52.861 ;
     RECT  33.156 52.861 97.434 52.951 ;
     RECT  33.156 52.951 97.506 53.221 ;
     RECT  98.28 52.825 99.897 53.221 ;
     RECT  102.564 52.439 103.194 53.227 ;
     RECT  102.456 53.227 103.194 53.401 ;
     RECT  101.988 53.401 103.194 53.549 ;
     RECT  100.62 52.817 101.142 53.995 ;
     RECT  101.988 53.549 102.618 53.995 ;
     RECT  100.62 53.995 102.618 54.283 ;
     RECT  26.715 2.413 26.997 54.571 ;
     RECT  30.852 50.395 32.397 54.571 ;
     RECT  33.156 53.221 99.897 54.571 ;
     RECT  100.62 54.283 103.194 54.571 ;
     RECT  18.615 2.413 18.897 54.607 ;
     RECT  19.764 54.571 19.782 54.607 ;
     RECT  18.615 54.607 19.782 54.701 ;
     RECT  26.676 54.571 26.997 54.701 ;
     RECT  30.78 54.571 32.397 54.701 ;
     RECT  33.156 54.571 103.194 55.139 ;
     RECT  101.304 55.139 103.194 55.679 ;
     RECT  33.156 55.139 100.386 55.921 ;
     RECT  33.156 55.921 100.422 55.985 ;
     RECT  101.376 55.679 103.194 55.993 ;
     RECT  101.376 55.993 103.266 56.237 ;
     RECT  101.376 56.237 103.194 56.669 ;
     RECT  33.156 55.985 97.506 56.759 ;
     RECT  33.228 56.759 97.506 56.767 ;
     RECT  98.28 55.985 100.422 56.767 ;
     RECT  33.228 56.767 100.422 56.867 ;
     RECT  101.376 56.669 102.654 57.181 ;
     RECT  28.548 48.119 30.006 57.299 ;
     RECT  100.872 57.181 102.654 57.299 ;
     RECT  100.872 57.299 102.618 57.407 ;
     RECT  33.228 56.867 100.134 57.479 ;
     RECT  30.852 54.701 32.397 57.685 ;
     RECT  33.228 57.479 97.197 57.685 ;
     RECT  98.136 57.479 100.134 57.991 ;
     RECT  100.872 57.407 101.178 57.991 ;
     RECT  98.136 57.991 101.178 58.109 ;
     RECT  102.024 57.407 102.618 58.117 ;
     RECT  30.852 57.685 97.197 58.225 ;
     RECT  102.024 58.117 103.194 58.225 ;
     RECT  101.484 58.225 103.194 58.349 ;
     RECT  98.136 58.109 100.566 58.531 ;
     RECT  101.484 58.349 103.158 58.637 ;
     RECT  98.028 58.531 100.566 58.649 ;
     RECT  30.852 58.225 97.254 58.729 ;
     RECT  26.715 54.701 26.997 58.891 ;
     RECT  30.852 58.729 97.398 58.891 ;
     RECT  102.06 58.637 103.158 58.925 ;
     RECT  98.136 58.649 100.566 58.999 ;
     RECT  26.676 58.891 26.997 59.021 ;
     RECT  30.78 58.891 97.398 59.021 ;
     RECT  102.564 58.925 103.158 59.371 ;
     RECT  98.136 58.999 101.07 59.501 ;
     RECT  30.852 59.021 97.398 59.611 ;
     RECT  98.316 59.501 101.07 59.701 ;
     RECT  2.415 2.413 2.697 59.971 ;
     RECT  2.415 59.971 2.934 60.029 ;
     RECT  102.564 59.371 103.194 60.139 ;
     RECT  2.415 60.029 2.754 60.235 ;
     RECT  2.304 60.235 2.754 60.269 ;
     RECT  28.548 57.299 29.754 60.277 ;
     RECT  3.78 60.043 3.798 60.313 ;
     RECT  30.852 59.611 97.578 60.313 ;
     RECT  98.316 59.701 101.106 60.313 ;
     RECT  30.852 60.313 101.106 60.349 ;
     RECT  102.024 60.139 103.194 60.349 ;
     RECT  3.744 60.313 3.798 60.377 ;
     RECT  0.504 60.043 0.522 60.385 ;
     RECT  30.852 60.349 103.194 60.421 ;
     RECT  0.504 60.385 0.558 60.461 ;
     RECT  5.115 2.413 5.397 60.511 ;
     RECT  0.504 60.461 0.522 60.523 ;
     RECT  10.515 2.413 10.797 60.523 ;
     RECT  3.744 60.377 3.762 60.539 ;
     RECT  5.004 60.511 5.397 60.557 ;
     RECT  0.324 60.523 0.522 60.619 ;
     RECT  6.84 60.523 6.858 60.653 ;
     RECT  10.515 60.523 10.854 60.653 ;
     RECT  14.256 60.619 14.274 60.656 ;
     RECT  15.915 2.413 16.197 60.691 ;
     RECT  30.852 60.421 103.23 60.701 ;
     RECT  0.18 60.619 0.522 60.749 ;
     RECT  99.504 60.701 103.23 60.749 ;
     RECT  0.18 60.749 0.198 60.797 ;
     RECT  2.304 60.269 2.697 60.797 ;
     RECT  15.624 60.691 16.197 60.881 ;
     RECT  30.852 60.701 98.586 60.925 ;
     RECT  99.504 60.749 101.502 60.941 ;
     RECT  99.504 60.941 101.25 60.989 ;
     RECT  99.504 60.989 99.99 61.115 ;
     RECT  99.54 61.115 99.99 61.349 ;
     RECT  30.636 60.925 98.586 61.429 ;
     RECT  102.564 60.749 103.23 61.483 ;
     RECT  30.636 61.429 98.658 61.531 ;
     RECT  102.024 61.483 103.23 61.579 ;
     RECT  100.944 60.989 101.25 61.771 ;
     RECT  30.636 61.531 98.766 61.949 ;
     RECT  99.615 61.349 99.99 62.059 ;
     RECT  100.944 61.771 101.286 62.059 ;
     RECT  99.615 62.059 101.286 62.131 ;
     RECT  102.024 61.579 103.266 62.131 ;
     RECT  99.615 62.131 103.266 62.231 ;
     RECT  99.615 62.231 100.386 62.239 ;
     RECT  99.504 62.239 100.386 62.311 ;
     RECT  101.16 62.231 103.266 62.339 ;
     RECT  102.024 62.339 103.266 62.573 ;
     RECT  30.636 61.949 98.694 62.671 ;
     RECT  99.432 62.311 100.386 62.671 ;
     RECT  28.476 60.277 29.754 63.085 ;
     RECT  30.636 62.671 100.386 63.121 ;
     RECT  101.16 62.339 101.286 63.121 ;
     RECT  102.024 62.573 103.23 63.121 ;
     RECT  30.636 63.121 103.23 63.341 ;
     RECT  30.636 63.341 103.194 63.437 ;
     RECT  102.024 63.437 103.194 63.533 ;
     RECT  102.528 63.533 103.194 64.229 ;
     RECT  30.636 63.437 101.214 64.267 ;
     RECT  30.636 64.267 101.43 64.319 ;
     RECT  28.44 63.085 29.754 64.363 ;
     RECT  30.636 64.319 31.266 64.363 ;
     RECT  32.115 64.319 101.43 64.397 ;
     RECT  101.088 64.397 101.43 64.399 ;
     RECT  101.088 64.399 101.502 64.471 ;
     RECT  101.088 64.471 101.538 64.967 ;
     RECT  102.564 64.229 103.194 65.011 ;
     RECT  101.988 65.011 103.194 65.237 ;
     RECT  32.115 64.397 100.242 65.515 ;
     RECT  32.115 65.515 100.314 65.641 ;
     RECT  32.115 65.641 100.35 65.677 ;
     RECT  101.088 64.967 101.25 65.677 ;
     RECT  28.44 64.363 31.266 65.785 ;
     RECT  32.115 65.677 101.25 65.785 ;
     RECT  101.988 65.237 102.654 66.029 ;
     RECT  28.44 65.785 101.25 66.28 ;
     RECT  101.988 66.029 102.042 66.28 ;
     RECT  103.176 66.187 103.194 66.353 ;
     RECT  28.44 66.28 102.042 66.856 ;
     RECT  28.44 66.856 102.618 67.339 ;
     RECT  28.44 67.339 103.194 67.559 ;
     RECT  101.988 67.559 103.194 67.667 ;
     RECT  28.44 67.559 101.142 68.207 ;
     RECT  101.124 68.207 101.142 68.243 ;
     RECT  28.44 68.207 100.278 68.513 ;
     RECT  10.515 60.653 10.797 68.917 ;
     RECT  102.564 67.667 103.194 68.981 ;
     RECT  102.564 68.981 102.654 69.061 ;
     RECT  102.06 69.061 102.654 69.067 ;
     RECT  10.515 68.917 11.394 69.179 ;
     RECT  101.16 68.719 101.178 69.187 ;
     RECT  98.28 68.513 100.278 69.223 ;
     RECT  101.088 69.187 101.178 69.223 ;
     RECT  28.44 68.513 97.506 69.307 ;
     RECT  98.28 69.223 101.178 69.307 ;
     RECT  28.44 69.307 101.178 69.331 ;
     RECT  102.024 69.067 102.654 69.331 ;
     RECT  28.44 69.331 102.654 69.719 ;
     RECT  102.024 69.719 102.654 69.763 ;
     RECT  28.44 69.719 101.25 70.681 ;
     RECT  102.024 69.763 103.194 70.681 ;
     RECT  28.44 70.681 103.194 71.645 ;
     RECT  28.44 71.645 101.142 71.789 ;
     RECT  28.44 71.789 101.07 72.619 ;
     RECT  101.988 71.645 103.194 72.619 ;
     RECT  28.44 72.619 103.194 73.039 ;
     RECT  26.715 59.021 26.997 73.237 ;
     RECT  28.44 73.039 103.266 73.517 ;
     RECT  28.44 73.517 103.194 73.877 ;
     RECT  102.528 73.877 103.194 73.901 ;
     RECT  102.528 73.901 103.158 74.623 ;
     RECT  26.676 73.237 26.997 74.849 ;
     RECT  10.515 69.179 11.286 74.857 ;
     RECT  28.44 73.877 101.502 75.127 ;
     RECT  102.528 74.623 103.194 75.211 ;
     RECT  102.492 75.211 103.194 75.403 ;
     RECT  28.44 75.127 101.574 75.461 ;
     RECT  28.44 75.461 100.818 75.505 ;
     RECT  101.556 75.461 101.574 75.569 ;
     RECT  102.492 75.403 103.23 75.839 ;
     RECT  10.515 74.857 11.682 75.929 ;
     RECT  102.492 75.839 103.194 75.929 ;
     RECT  28.224 75.505 100.818 76.199 ;
     RECT  102.528 75.929 103.194 76.651 ;
     RECT  102.024 76.651 103.194 76.919 ;
     RECT  28.224 76.199 100.386 76.981 ;
     RECT  101.124 76.351 101.142 76.981 ;
     RECT  28.224 76.981 101.142 77.359 ;
     RECT  102.024 76.919 102.834 77.359 ;
     RECT  28.116 77.359 102.834 77.395 ;
     RECT  28.044 77.395 102.834 77.459 ;
     RECT  102.6 77.459 102.834 77.549 ;
     RECT  28.044 77.459 101.502 77.585 ;
     RECT  102.636 77.549 102.834 77.819 ;
     RECT  28.044 77.585 100.962 77.855 ;
     RECT  102.636 77.819 102.654 77.927 ;
     RECT  26.715 74.849 26.997 78.511 ;
     RECT  28.044 77.855 100.386 78.511 ;
     RECT  26.715 78.511 100.386 78.907 ;
     RECT  26.1 78.907 100.386 78.943 ;
     RECT  25.776 78.943 100.386 79.411 ;
     RECT  24.015 2.413 24.297 79.483 ;
     RECT  25.776 79.411 100.818 80.095 ;
     RECT  25.776 80.095 101.106 80.249 ;
     RECT  25.776 80.249 100.458 80.519 ;
     RECT  25.776 80.519 100.386 83.371 ;
     RECT  101.556 83.299 101.574 83.371 ;
     RECT  101.556 83.371 102.042 83.461 ;
     RECT  10.515 75.929 11.502 83.489 ;
     RECT  25.776 83.371 100.458 83.497 ;
     RECT  101.484 83.461 102.078 83.497 ;
     RECT  25.776 83.497 102.078 83.533 ;
     RECT  25.776 83.533 102.654 83.569 ;
     RECT  23.256 83.605 23.274 83.641 ;
     RECT  24.015 79.483 24.894 83.641 ;
     RECT  25.776 83.569 102.69 83.767 ;
     RECT  25.776 83.767 103.194 83.795 ;
     RECT  21.315 2.413 21.597 84.181 ;
     RECT  25.776 83.795 101.07 84.371 ;
     RECT  101.916 83.795 103.194 84.379 ;
     RECT  101.916 84.379 103.266 84.653 ;
     RECT  101.916 84.653 102.654 84.685 ;
     RECT  25.776 84.371 100.422 85.189 ;
     RECT  101.484 84.685 102.654 85.189 ;
     RECT  25.776 85.189 102.654 85.387 ;
     RECT  25.776 85.387 103.194 85.487 ;
     RECT  23.256 83.641 24.894 85.801 ;
     RECT  25.776 85.487 100.782 85.801 ;
     RECT  23.256 85.801 100.782 86.305 ;
     RECT  101.664 85.487 103.194 86.305 ;
     RECT  23.256 86.305 103.194 86.381 ;
     RECT  102.492 86.381 103.194 86.477 ;
     RECT  102.528 86.477 103.194 86.539 ;
     RECT  23.256 86.381 101.682 86.567 ;
     RECT  23.256 86.567 100.962 86.729 ;
     RECT  100.8 86.729 100.962 86.999 ;
     RECT  102.528 86.539 103.23 86.999 ;
     RECT  20.988 84.181 21.597 87.007 ;
     RECT  103.212 86.999 103.23 87.107 ;
     RECT  23.256 86.729 99.897 87.277 ;
     RECT  20.988 87.007 21.978 87.313 ;
     RECT  100.8 86.999 100.818 87.539 ;
     RECT  20.988 87.313 22.05 87.853 ;
     RECT  22.932 87.277 99.897 87.853 ;
     RECT  20.988 87.853 99.897 88.079 ;
     RECT  34.632 88.079 99.897 89.429 ;
     RECT  58.14 89.429 99.897 89.465 ;
     RECT  20.988 88.079 33.858 89.815 ;
     RECT  34.632 89.429 57.186 89.815 ;
     RECT  20.988 89.815 57.186 89.879 ;
     RECT  52.704 89.879 57.186 90.355 ;
     RECT  58.176 89.465 99.897 90.355 ;
     RECT  10.515 83.489 11.286 91.049 ;
     RECT  20.988 89.879 51.966 91.319 ;
     RECT  52.704 90.355 57.294 92.137 ;
     RECT  33.516 91.319 51.966 92.399 ;
     RECT  52.704 92.137 57.402 92.515 ;
     RECT  58.14 90.355 99.897 92.515 ;
     RECT  36.18 92.399 51.966 92.785 ;
     RECT  52.704 92.515 99.897 92.785 ;
     RECT  20.988 91.319 32.778 93.209 ;
     RECT  18.615 54.701 18.897 93.793 ;
     RECT  18.324 93.793 18.897 93.829 ;
     RECT  36.18 92.785 99.897 94.019 ;
     RECT  36.18 94.019 98.766 94.091 ;
     RECT  36.18 94.091 98.658 94.829 ;
     RECT  17.964 93.829 18.897 94.981 ;
     RECT  36.18 94.829 98.586 95.099 ;
     RECT  20.988 93.209 32.454 95.107 ;
     RECT  20.88 95.107 32.454 95.165 ;
     RECT  33.516 92.399 35.097 95.179 ;
     RECT  17.964 94.981 19.566 95.521 ;
     RECT  33.516 95.179 35.298 95.755 ;
     RECT  36.18 95.099 98.046 95.755 ;
     RECT  33.516 95.755 98.046 95.981 ;
     RECT  21.24 95.165 32.454 96.259 ;
     RECT  20.808 96.259 32.454 96.331 ;
     RECT  33.516 95.981 97.866 96.449 ;
     RECT  33.516 96.449 97.362 96.593 ;
     RECT  20.808 96.331 32.706 96.719 ;
     RECT  33.516 96.593 97.197 96.791 ;
     RECT  10.515 91.049 10.854 96.835 ;
     RECT  10.296 96.835 10.854 96.893 ;
     RECT  33.516 96.791 94.59 97.061 ;
     RECT  95.4 96.791 97.197 97.637 ;
     RECT  17.964 95.521 19.998 97.915 ;
     RECT  20.808 96.719 32.454 97.915 ;
     RECT  33.516 97.061 52.326 97.915 ;
     RECT  53.316 97.061 94.497 97.915 ;
     RECT  33.516 97.915 94.497 98.041 ;
     RECT  95.256 97.645 95.274 98.041 ;
     RECT  33.516 98.041 95.274 98.069 ;
     RECT  7.815 2.413 8.097 98.077 ;
     RECT  33.516 98.069 95.13 98.141 ;
     RECT  17.964 97.915 32.454 98.213 ;
     RECT  7.815 98.077 8.766 98.383 ;
     RECT  96.012 97.637 97.197 98.411 ;
     RECT  17.964 98.213 31.194 98.519 ;
     RECT  10.515 96.893 10.854 98.609 ;
     RECT  32.004 98.213 32.454 98.609 ;
     RECT  33.516 98.141 94.554 98.681 ;
     RECT  10.515 98.609 10.797 98.725 ;
     RECT  96.192 98.411 97.197 98.879 ;
     RECT  44.46 98.681 94.554 98.915 ;
     RECT  44.46 98.915 93.438 99.059 ;
     RECT  44.748 99.059 93.438 99.149 ;
     RECT  32.04 98.609 32.454 99.157 ;
     RECT  33.516 98.681 43.398 99.185 ;
     RECT  46.62 99.149 93.438 99.197 ;
     RECT  42.915 99.185 43.398 99.419 ;
     RECT  44.748 99.149 45.897 99.419 ;
     RECT  33.516 99.185 41.958 99.491 ;
     RECT  46.62 99.197 93.042 99.599 ;
     RECT  32.04 99.157 32.49 99.883 ;
     RECT  94.215 98.915 94.554 99.959 ;
     RECT  33.624 99.491 41.958 100.109 ;
     RECT  17.964 98.519 31.086 100.229 ;
     RECT  33.732 100.109 41.958 100.253 ;
     RECT  46.62 99.599 92.898 100.265 ;
     RECT  31.968 99.883 32.49 100.301 ;
     RECT  88.056 100.265 92.898 100.301 ;
     RECT  15.915 60.881 16.197 100.315 ;
     RECT  17.964 100.229 30.474 100.499 ;
     RECT  17.964 100.499 29.862 100.507 ;
     RECT  15.516 100.315 16.722 100.543 ;
     RECT  88.056 100.301 92.538 100.607 ;
     RECT  88.056 100.607 92.358 100.679 ;
     RECT  88.056 100.679 92.178 100.769 ;
     RECT  10.08 98.725 10.797 100.777 ;
     RECT  46.62 100.265 87.246 100.805 ;
     RECT  88.056 100.769 92.106 100.841 ;
     RECT  17.82 100.507 29.862 100.849 ;
     RECT  15.3 100.543 16.722 100.891 ;
     RECT  17.784 100.849 29.862 100.891 ;
     RECT  10.044 100.777 10.797 100.921 ;
     RECT  86.076 100.805 87.246 101.075 ;
     RECT  10.044 100.921 10.89 101.083 ;
     RECT  7.815 98.383 9.054 101.155 ;
     RECT  88.056 100.841 91.962 101.155 ;
     RECT  10.044 101.083 10.962 101.219 ;
     RECT  15.084 100.891 29.862 101.219 ;
     RECT  87.804 101.155 91.962 101.219 ;
     RECT  7.815 101.155 9.27 101.281 ;
     RECT  10.044 101.219 10.926 101.281 ;
     RECT  24.015 101.219 29.697 101.309 ;
     RECT  46.62 100.805 85.338 101.309 ;
     RECT  86.076 101.075 87.066 101.309 ;
     RECT  87.804 101.219 91.854 101.309 ;
     RECT  15.084 101.219 23.274 101.317 ;
     RECT  24.015 101.309 25.542 101.357 ;
     RECT  7.815 101.281 10.926 101.381 ;
     RECT  14.94 101.317 23.274 101.405 ;
     RECT  33.732 100.253 33.75 101.425 ;
     RECT  34.815 100.253 41.958 101.425 ;
     RECT  14.94 101.405 14.958 101.587 ;
     RECT  25.164 101.357 25.542 101.687 ;
     RECT  25.524 101.687 25.542 101.723 ;
     RECT  33.732 101.425 41.958 101.759 ;
     RECT  34.164 101.759 41.958 101.849 ;
     RECT  14.832 101.587 14.958 101.993 ;
     RECT  86.076 101.309 86.994 102.091 ;
     RECT  87.804 101.309 91.797 102.091 ;
     RECT  34.164 101.849 41.31 102.125 ;
     RECT  64.515 101.309 85.338 102.127 ;
     RECT  86.076 102.091 91.797 102.127 ;
     RECT  34.164 102.125 38.214 102.128 ;
     RECT  46.62 101.309 63.666 102.199 ;
     RECT  64.404 102.127 91.797 102.199 ;
     RECT  46.62 102.199 91.797 102.221 ;
     RECT  15.915 101.405 23.274 102.227 ;
     RECT  87.624 102.221 91.797 102.227 ;
     RECT  14.832 101.993 14.85 102.263 ;
     RECT  15.915 102.227 22.842 102.269 ;
     RECT  24.015 101.357 24.297 102.271 ;
     RECT  24.015 102.271 24.642 102.389 ;
     RECT  34.164 102.128 38.178 102.389 ;
     RECT  87.624 102.227 89.097 102.389 ;
     RECT  24.015 102.389 24.297 102.424 ;
     RECT  87.624 102.389 88.074 102.425 ;
     RECT  17.1 102.269 22.842 102.461 ;
     RECT  46.62 102.221 86.562 102.461 ;
     RECT  87.876 102.425 87.894 102.497 ;
     RECT  17.784 102.461 22.842 102.533 ;
     RECT  31.968 100.301 32.454 102.541 ;
     RECT  31.932 102.541 32.454 102.569 ;
     RECT  85.284 102.461 86.562 102.659 ;
     RECT  90.108 102.227 91.797 102.659 ;
     RECT  46.62 102.461 84.546 102.704 ;
     RECT  38.952 102.125 41.31 102.731 ;
     RECT  38.988 102.731 41.31 102.929 ;
     RECT  46.62 102.704 84.006 102.929 ;
     RECT  85.392 102.659 86.562 102.929 ;
     RECT  90.432 102.659 91.797 102.929 ;
     RECT  46.62 102.929 83.697 103.037 ;
     RECT  23.832 102.424 24.297 103.045 ;
     RECT  85.392 102.929 86.397 103.073 ;
     RECT  83.268 103.037 83.697 103.109 ;
     RECT  2.415 60.797 2.697 103.157 ;
     RECT  5.115 60.557 5.397 103.157 ;
     RECT  7.815 101.381 10.797 103.157 ;
     RECT  13.215 2.413 13.497 103.157 ;
     RECT  15.915 102.269 16.197 103.157 ;
     RECT  26.715 101.309 29.697 103.157 ;
     RECT  34.164 102.389 38.07 103.157 ;
     RECT  42.915 99.419 43.197 103.157 ;
     RECT  83.415 103.109 83.697 103.157 ;
     RECT  86.115 103.073 86.397 103.157 ;
     RECT  88.815 102.389 89.097 103.157 ;
     RECT  91.515 102.929 91.797 103.157 ;
     RECT  94.215 99.959 94.497 103.157 ;
     RECT  96.915 98.879 97.197 103.157 ;
     RECT  99.615 94.019 99.897 103.157 ;
     RECT  46.62 103.037 82.314 103.229 ;
     RECT  90.432 102.929 90.45 103.307 ;
     RECT  23.724 103.045 24.297 103.315 ;
     RECT  34.956 103.157 38.07 103.325 ;
     RECT  46.62 103.229 51.462 103.343 ;
     RECT  23.58 103.315 24.297 103.373 ;
     RECT  46.62 103.343 51.39 103.379 ;
     RECT  2.607 103.157 2.697 103.427 ;
     RECT  5.307 103.157 5.397 103.427 ;
     RECT  8.007 103.157 10.797 103.427 ;
     RECT  13.407 103.157 13.497 103.427 ;
     RECT  16.107 103.157 16.197 103.427 ;
     RECT  24.207 103.373 24.297 103.427 ;
     RECT  26.907 103.157 29.697 103.427 ;
     RECT  31.932 102.569 32.397 103.427 ;
     RECT  43.107 103.157 43.197 103.427 ;
     RECT  44.892 99.419 45.897 103.427 ;
     RECT  46.62 103.379 51.297 103.427 ;
     RECT  83.607 103.157 83.697 103.427 ;
     RECT  86.307 103.157 86.397 103.427 ;
     RECT  89.007 103.157 89.097 103.427 ;
     RECT  91.707 103.157 91.797 103.427 ;
     RECT  94.407 103.157 94.497 103.427 ;
     RECT  97.107 103.157 97.197 103.427 ;
     RECT  99.807 103.157 99.897 103.427 ;
     RECT  52.308 103.229 82.314 103.469 ;
     RECT  34.956 103.325 37.962 103.517 ;
     RECT  52.488 103.469 70.722 103.517 ;
     RECT  71.64 103.469 82.314 103.517 ;
     RECT  52.488 103.517 70.47 103.541 ;
     RECT  71.64 103.517 71.658 103.541 ;
     RECT  35.532 103.517 37.962 103.565 ;
     RECT  73.98 103.517 82.314 103.577 ;
     RECT  31.932 103.427 32.058 103.613 ;
     RECT  59.76 103.541 70.47 103.613 ;
     RECT  74.016 103.577 74.034 103.613 ;
     RECT  74.916 103.577 82.314 103.613 ;
     RECT  31.932 103.613 31.95 103.661 ;
     RECT  35.568 103.565 37.674 103.661 ;
     RECT  52.848 103.541 58.986 103.661 ;
     RECT  52.848 103.661 57.042 103.694 ;
     RECT  59.76 103.613 70.074 103.694 ;
     RECT  72.936 103.517 72.954 103.694 ;
     RECT  36.972 103.661 37.674 103.709 ;
     RECT  53.532 103.694 57.042 103.709 ;
     RECT  58.14 103.661 58.986 103.709 ;
     RECT  58.968 103.709 58.986 103.739 ;
     RECT  60.516 103.694 70.074 103.739 ;
     RECT  34.164 103.157 34.182 103.757 ;
     RECT  35.568 103.661 36.234 103.757 ;
     RECT  37.656 103.709 37.674 103.757 ;
     RECT  54.108 103.709 57.042 103.757 ;
     RECT  58.14 103.709 58.158 103.757 ;
     RECT  59.76 103.694 59.778 103.757 ;
     RECT  64.98 103.739 70.074 103.757 ;
     RECT  36.144 103.757 36.234 104.573 ;
     RECT  54.108 103.757 56.79 104.573 ;
     RECT  36.144 104.573 36.162 104.621 ;
     RECT  54.108 104.573 55.386 104.621 ;
     RECT  60.516 103.739 63.666 104.621 ;
     RECT  44.892 103.427 45.342 104.657 ;
     RECT  56.304 104.573 56.79 104.669 ;
     RECT  54.108 104.621 54.162 104.717 ;
     RECT  55.08 104.621 55.386 104.765 ;
     RECT  55.08 104.765 55.098 104.813 ;
     RECT  54.144 104.717 54.162 104.861 ;
     RECT  8.136 103.427 10.206 104.875 ;
     RECT  27.108 103.427 29.142 104.875 ;
     RECT  75.456 103.613 77.598 104.875 ;
     RECT  64.98 103.757 69.894 104.891 ;
     RECT  78.516 103.613 82.314 104.891 ;
     RECT  75.42 104.875 77.742 104.923 ;
     RECT  78.516 104.891 82.242 104.923 ;
     RECT  65.556 104.891 69.894 105.286 ;
     RECT  46.62 103.427 51.102 105.403 ;
     RECT  57.276 105.403 57.294 105.499 ;
     RECT  60.516 104.621 60.534 105.511 ;
     RECT  61.344 104.621 63.666 105.511 ;
     RECT  60.516 105.511 63.666 105.539 ;
     RECT  39.132 102.929 41.31 105.556 ;
     RECT  60.516 105.539 63.306 105.584 ;
     RECT  56.304 104.669 56.394 105.595 ;
     RECT  57.204 105.499 57.546 105.595 ;
     RECT  58.536 105.451 58.554 105.595 ;
     RECT  46.62 105.403 51.714 105.629 ;
     RECT  56.304 105.595 58.554 105.677 ;
     RECT  39.06 105.556 41.31 105.709 ;
     RECT  35.28 105.499 35.298 105.725 ;
     RECT  56.304 105.677 57.438 105.725 ;
     RECT  58.248 105.677 58.554 105.725 ;
     RECT  26.964 104.875 29.142 105.739 ;
     RECT  17.784 102.533 22.482 105.745 ;
     RECT  46.62 105.629 51.174 105.745 ;
     RECT  75.42 104.923 82.242 105.745 ;
     RECT  17.748 105.745 22.482 105.773 ;
     RECT  46.548 105.745 51.174 105.773 ;
     RECT  56.376 105.725 56.394 105.773 ;
     RECT  60.516 105.584 63.198 105.773 ;
     RECT  75.348 105.745 82.242 105.773 ;
     RECT  7.956 104.875 10.206 105.804 ;
     RECT  17.748 105.773 22.302 105.804 ;
     RECT  26.964 105.739 29.214 105.804 ;
     RECT  39.06 105.709 41.346 105.804 ;
     RECT  46.548 105.773 51.102 105.804 ;
     RECT  60.948 105.773 63.198 105.804 ;
     RECT  65.556 105.286 70.11 105.804 ;
     RECT  75.348 105.773 82.206 105.804 ;
     RECT  18 105.804 18.018 105.809 ;
     RECT  20.196 105.804 20.214 105.809 ;
     RECT  41.328 105.804 41.346 105.809 ;
     RECT  45.324 104.657 45.342 105.809 ;
     RECT  78.048 105.804 78.066 105.809 ;
     RECT  80.064 105.804 80.082 105.809 ;
    LAYER M4 ;
     RECT  0.06 60.048 0.227 60.936 ;
     RECT  0.227 60.144 0.371 60.936 ;
     RECT  0.181 53.328 2.408 53.352 ;
     RECT  0.325 56.784 2.408 56.808 ;
     RECT  0.371 60.24 2.408 60.936 ;
     RECT  2.408 2.148 2.512 103.152 ;
     RECT  2.512 2.418 2.6 103.152 ;
     RECT  2.6 2.418 2.704 103.422 ;
     RECT  2.704 53.328 5.108 53.352 ;
     RECT  2.704 56.784 5.108 56.808 ;
     RECT  2.704 60 5.108 60.552 ;
     RECT  5.108 2.148 5.212 103.152 ;
     RECT  5.212 2.418 5.3 103.152 ;
     RECT  5.3 2.418 5.404 103.422 ;
     RECT  5.404 60 6.829 60.552 ;
     RECT  5.404 53.328 7.808 53.352 ;
     RECT  5.404 56.784 7.808 56.808 ;
     RECT  6.829 60 7.808 60.648 ;
     RECT  7.669 101.328 7.808 101.352 ;
     RECT  7.808 2.148 7.912 103.152 ;
     RECT  7.669 104.88 7.985 104.904 ;
     RECT  7.912 2.418 8 103.152 ;
     RECT  8 2.418 8.104 103.422 ;
     RECT  8.444 105.744 9.356 105.768 ;
     RECT  8.104 101.328 9.397 101.4 ;
     RECT  9.356 105.696 9.442 105.768 ;
     RECT  9.397 101.088 9.493 101.4 ;
     RECT  9.493 101.088 9.637 102.264 ;
     RECT  9.637 101.088 9.685 102.456 ;
     RECT  9.442 105.648 9.757 105.768 ;
     RECT  9.685 100.56 9.781 102.456 ;
     RECT  9.757 105.696 9.923 105.768 ;
     RECT  9.923 105.744 10.163 105.768 ;
     RECT  8.104 53.328 10.508 53.352 ;
     RECT  8.104 56.784 10.508 56.808 ;
     RECT  8.104 60 10.508 60.648 ;
     RECT  10.285 96.864 10.508 96.888 ;
     RECT  9.781 100.512 10.508 102.456 ;
     RECT  10.508 2.148 10.612 103.152 ;
     RECT  10.612 2.418 10.7 103.152 ;
     RECT  10.7 2.418 10.804 103.422 ;
     RECT  10.804 53.328 13.208 53.352 ;
     RECT  10.804 56.784 13.208 56.808 ;
     RECT  10.804 60 13.208 60.648 ;
     RECT  10.804 100.512 13.208 102.456 ;
     RECT  13.208 2.148 13.312 103.152 ;
     RECT  13.312 2.418 13.4 103.152 ;
     RECT  13.4 2.418 13.504 103.422 ;
     RECT  13.504 60 14.285 60.648 ;
     RECT  15.061 96.768 15.397 96.792 ;
     RECT  13.504 100.512 15.505 102.456 ;
     RECT  13.504 53.328 15.908 53.352 ;
     RECT  13.504 56.784 15.908 56.808 ;
     RECT  14.285 60 15.908 60.36 ;
     RECT  15.541 95.136 15.908 95.16 ;
     RECT  15.397 96.48 15.908 96.792 ;
     RECT  15.505 100.32 15.908 102.456 ;
     RECT  15.908 2.148 16.012 103.152 ;
     RECT  16.012 2.418 16.1 103.152 ;
     RECT  16.1 2.418 16.204 103.422 ;
     RECT  16.204 100.32 16.777 102.456 ;
     RECT  16.777 100.896 17.129 102.456 ;
     RECT  16.204 94.848 17.413 95.16 ;
     RECT  16.204 96.48 17.413 96.792 ;
     RECT  17.129 100.896 17.497 102.216 ;
     RECT  16.204 98.4 17.557 98.424 ;
     RECT  17.557 98.112 17.605 98.424 ;
     RECT  17.497 101.328 18.421 102.216 ;
     RECT  18.421 104.976 18.469 105.768 ;
     RECT  16.204 53.328 18.608 53.352 ;
     RECT  16.204 56.784 18.608 56.808 ;
     RECT  16.204 60 18.608 60.36 ;
     RECT  17.413 94.848 18.608 96.792 ;
     RECT  17.605 98.112 18.608 98.664 ;
     RECT  18.469 100.08 18.608 100.104 ;
     RECT  18.421 101.328 18.608 102.456 ;
     RECT  18.469 104.88 18.641 105.768 ;
     RECT  18.608 2.148 18.712 103.152 ;
     RECT  18.641 104.976 18.713 105.768 ;
     RECT  18.712 2.418 18.8 103.152 ;
     RECT  18.8 2.418 18.904 103.422 ;
     RECT  18.713 105.696 19.139 105.768 ;
     RECT  19.139 105.744 19.523 105.768 ;
     RECT  18.904 60 19.619 60.36 ;
     RECT  18.904 99.984 20.917 100.296 ;
     RECT  18.904 101.328 20.917 101.352 ;
     RECT  18.904 53.328 21.308 53.352 ;
     RECT  18.904 54.672 21.308 54.696 ;
     RECT  18.904 56.784 21.308 56.808 ;
     RECT  18.904 58.752 21.308 58.776 ;
     RECT  19.619 60.336 21.308 60.36 ;
     RECT  18.904 94.848 21.308 96.792 ;
     RECT  18.904 98.112 21.308 98.664 ;
     RECT  20.917 99.984 21.308 101.352 ;
     RECT  18.904 102.432 21.308 102.456 ;
     RECT  21.308 2.148 21.412 103.152 ;
     RECT  21.412 2.418 21.5 103.152 ;
     RECT  21.5 2.418 21.604 103.422 ;
     RECT  21.604 95.952 21.881 96.792 ;
     RECT  20.876 105.744 22.067 105.768 ;
     RECT  21.604 99.984 23.713 101.352 ;
     RECT  23.701 93.744 23.797 93.768 ;
     RECT  21.604 94.848 23.797 94.872 ;
     RECT  21.604 54.576 23.893 54.6 ;
     RECT  21.604 58.896 23.893 58.92 ;
     RECT  21.604 53.328 24.008 53.352 ;
     RECT  23.893 54.576 24.008 54.696 ;
     RECT  21.604 56.784 24.008 56.808 ;
     RECT  23.893 58.896 24.008 59.016 ;
     RECT  21.604 60.336 24.008 60.36 ;
     RECT  23.797 93.744 24.008 94.872 ;
     RECT  21.881 95.952 24.008 96.024 ;
     RECT  21.604 98.112 24.008 98.664 ;
     RECT  23.713 99.744 24.008 101.352 ;
     RECT  21.604 102.432 24.008 103.368 ;
     RECT  24.008 2.148 24.112 103.368 ;
     RECT  24.112 2.418 24.2 103.368 ;
     RECT  24.2 2.418 24.304 103.422 ;
     RECT  24.304 99.744 24.515 102.696 ;
     RECT  24.304 95.952 25.121 96.792 ;
     RECT  24.304 98.112 25.157 98.76 ;
     RECT  24.515 99.744 25.229 101.448 ;
     RECT  25.229 101.136 25.265 101.448 ;
     RECT  24.304 93.744 25.333 94.056 ;
     RECT  25.265 101.424 25.373 101.448 ;
     RECT  25.229 99.744 25.417 99.768 ;
     RECT  25.157 98.352 25.445 98.76 ;
     RECT  24.304 53.328 26.708 53.352 ;
     RECT  24.304 54.672 26.708 54.696 ;
     RECT  24.304 56.784 26.708 56.808 ;
     RECT  24.304 58.992 26.708 59.016 ;
     RECT  24.304 60.336 26.708 60.36 ;
     RECT  26.413 85.68 26.708 85.704 ;
     RECT  25.333 93.744 26.708 94.584 ;
     RECT  25.121 95.952 26.708 96.6 ;
     RECT  25.445 98.736 26.708 98.76 ;
     RECT  26.708 2.148 26.812 103.152 ;
     RECT  26.812 2.418 26.9 103.152 ;
     RECT  26.9 2.418 27.004 103.422 ;
     RECT  26.953 104.88 27.025 104.904 ;
     RECT  27.025 104.88 27.197 105 ;
     RECT  27.197 104.88 27.347 105.096 ;
     RECT  27.004 102.048 27.821 103.08 ;
     RECT  27.601 105.648 27.929 105.768 ;
     RECT  27.821 102.048 28.037 102.888 ;
     RECT  28.037 102.048 28.189 102.648 ;
     RECT  27.004 93.792 28.429 94.584 ;
     RECT  27.004 98.4 28.609 99.72 ;
     RECT  27.004 95.952 28.753 96.6 ;
     RECT  28.453 81.408 28.789 81.432 ;
     RECT  27.929 105.744 29.267 105.768 ;
     RECT  27.004 53.328 29.408 53.352 ;
     RECT  27.004 54.672 29.408 54.696 ;
     RECT  27.004 56.784 29.408 56.808 ;
     RECT  27.004 58.992 29.408 59.016 ;
     RECT  27.004 60.336 29.408 60.36 ;
     RECT  28.789 81.36 29.408 81.432 ;
     RECT  27.004 85.68 29.408 85.704 ;
     RECT  28.429 93.504 29.408 94.584 ;
     RECT  28.753 95.952 29.408 96.888 ;
     RECT  28.609 98.112 29.408 99.72 ;
     RECT  28.189 102.048 29.408 102.552 ;
     RECT  29.408 2.148 29.512 103.152 ;
     RECT  29.512 2.418 29.6 103.152 ;
     RECT  29.6 2.418 29.704 103.422 ;
     RECT  29.704 93.792 29.909 94.584 ;
     RECT  29.704 98.352 30.757 98.376 ;
     RECT  29.704 54.576 30.769 54.6 ;
     RECT  29.704 58.896 30.769 58.92 ;
     RECT  30.769 54.576 30.809 54.696 ;
     RECT  30.769 58.896 30.809 59.016 ;
     RECT  29.909 94.56 30.845 94.584 ;
     RECT  30.757 105.504 30.853 105.528 ;
     RECT  30.757 102.528 30.899 102.744 ;
     RECT  30.853 105.504 30.899 105.672 ;
     RECT  30.899 102.528 30.947 102.648 ;
     RECT  30.757 98.352 30.949 98.664 ;
     RECT  30.947 102.624 31.043 102.648 ;
     RECT  30.899 105.648 31.043 105.672 ;
     RECT  29.704 100.272 31.045 100.296 ;
     RECT  31.045 100.224 31.237 100.296 ;
     RECT  29.704 95.952 31.333 97.08 ;
     RECT  31.333 95.952 31.429 97.32 ;
     RECT  30.853 91.104 31.621 91.128 ;
     RECT  31.237 100.08 31.717 100.296 ;
     RECT  31.717 100.032 31.916 100.296 ;
     RECT  31.849 45.6 31.957 45.624 ;
     RECT  31.909 88.128 31.957 88.152 ;
     RECT  31.921 103.632 31.957 103.656 ;
     RECT  31.957 105.552 32.005 105.576 ;
     RECT  31.957 44.352 32.108 45.624 ;
     RECT  29.704 53.328 32.108 53.352 ;
     RECT  30.809 54.672 32.108 54.696 ;
     RECT  29.704 56.784 32.108 56.808 ;
     RECT  30.809 58.992 32.108 59.016 ;
     RECT  29.704 60.336 32.108 60.36 ;
     RECT  29.704 81.36 32.108 81.432 ;
     RECT  29.704 85.68 32.108 85.704 ;
     RECT  31.957 88.128 32.108 88.68 ;
     RECT  31.621 90.528 32.108 91.128 ;
     RECT  31.429 95.952 32.108 97.368 ;
     RECT  30.949 98.352 32.108 98.76 ;
     RECT  31.916 99.888 32.108 100.296 ;
     RECT  31.957 103.536 32.108 103.656 ;
     RECT  32.005 105.552 32.147 105.672 ;
     RECT  32.108 2.148 32.212 103.656 ;
     RECT  32.212 2.418 32.339 103.656 ;
     RECT  32.339 2.418 32.404 103.608 ;
     RECT  32.404 103.584 32.435 103.608 ;
     RECT  32.147 105.648 32.771 105.672 ;
     RECT  32.404 87.648 32.933 88.92 ;
     RECT  32.404 49.872 33.577 49.896 ;
     RECT  32.404 46.272 33.613 46.68 ;
     RECT  33.577 49.872 33.617 50.136 ;
     RECT  33.541 102.96 33.637 102.984 ;
     RECT  33.637 102.96 33.733 103.08 ;
     RECT  32.404 95.712 33.797 98.76 ;
     RECT  33.829 101.952 33.925 101.976 ;
     RECT  33.733 102.96 33.925 103.752 ;
     RECT  32.404 90.528 33.973 91.128 ;
     RECT  33.925 101.952 34.021 103.752 ;
     RECT  33.613 46.272 34.153 46.872 ;
     RECT  32.404 85.68 34.213 85.704 ;
     RECT  32.933 87.648 34.357 87.672 ;
     RECT  32.933 88.656 34.357 88.92 ;
     RECT  32.404 44.88 34.441 44.904 ;
     RECT  34.021 101.712 34.501 103.752 ;
     RECT  33.617 50.112 34.621 50.136 ;
     RECT  33.829 48.48 34.652 48.504 ;
     RECT  34.652 47.856 34.693 48.504 ;
     RECT  34.621 49.584 34.693 50.136 ;
     RECT  34.501 101.712 34.789 104.616 ;
     RECT  32.404 43.104 34.808 43.128 ;
     RECT  34.441 44.448 34.808 44.904 ;
     RECT  34.153 46.08 34.808 46.872 ;
     RECT  34.693 47.856 34.808 50.136 ;
     RECT  32.404 53.328 34.808 53.352 ;
     RECT  32.404 54.672 34.808 54.696 ;
     RECT  32.404 56.784 34.808 56.808 ;
     RECT  32.404 58.992 34.808 59.016 ;
     RECT  32.404 60.336 34.808 60.36 ;
     RECT  32.404 81.36 34.808 81.432 ;
     RECT  34.213 85.68 34.808 86.52 ;
     RECT  34.357 87.648 34.808 88.92 ;
     RECT  33.973 90.528 34.808 91.368 ;
     RECT  34.021 94.656 34.808 94.68 ;
     RECT  33.797 95.712 34.808 98.376 ;
     RECT  32.404 99.984 34.808 100.296 ;
     RECT  34.789 101.712 34.808 105.432 ;
     RECT  34.808 2.148 34.912 105.432 ;
     RECT  34.912 2.418 35.104 105.432 ;
     RECT  35.104 100.272 35.125 105.432 ;
     RECT  35.125 100.272 35.173 105.528 ;
     RECT  35.173 100.272 35.237 105.624 ;
     RECT  35.237 101.184 35.269 105.624 ;
     RECT  35.269 101.184 35.309 105.72 ;
     RECT  35.309 105.6 35.315 105.72 ;
     RECT  35.315 105.648 35.353 105.72 ;
     RECT  35.104 95.184 35.389 97.512 ;
     RECT  35.389 95.184 35.603 96.792 ;
     RECT  35.603 95.76 35.843 96.792 ;
     RECT  35.353 105.648 35.843 105.672 ;
     RECT  35.104 51.456 35.849 51.48 ;
     RECT  35.104 43.104 36.086 45.624 ;
     RECT  35.104 48.384 36.092 48.696 ;
     RECT  36.086 43.152 36.131 45.624 ;
     RECT  35.104 60.336 36.133 60.36 ;
     RECT  36.131 43.152 36.173 45 ;
     RECT  35.309 101.184 36.173 104.616 ;
     RECT  35.104 54.672 36.179 54.696 ;
     RECT  35.104 90.528 36.245 91.368 ;
     RECT  36.173 101.184 36.245 104.568 ;
     RECT  35.104 46.848 36.461 46.872 ;
     RECT  36.245 90.816 36.497 91.368 ;
     RECT  35.104 38.592 36.524 38.616 ;
     RECT  35.104 40.368 36.524 40.392 ;
     RECT  36.092 48.384 36.817 48.84 ;
     RECT  36.572 50.112 36.817 50.136 ;
     RECT  35.104 41.616 36.889 41.64 ;
     RECT  36.817 48.384 37.148 50.136 ;
     RECT  36.524 38.592 37.508 40.392 ;
     RECT  36.889 41.616 37.508 42.024 ;
     RECT  36.173 43.296 37.508 45 ;
     RECT  37.189 46.128 37.508 46.152 ;
     RECT  37.148 47.568 37.508 50.136 ;
     RECT  36.421 51.216 37.508 51.336 ;
     RECT  35.104 53.328 37.508 53.352 ;
     RECT  35.104 56.784 37.508 56.808 ;
     RECT  35.104 58.992 37.508 59.016 ;
     RECT  36.133 60 37.508 60.36 ;
     RECT  35.104 81.36 37.508 81.432 ;
     RECT  35.104 85.68 37.508 89.304 ;
     RECT  36.497 90.816 37.508 90.84 ;
     RECT  35.843 96.336 37.508 96.792 ;
     RECT  36.245 101.184 37.508 103.752 ;
     RECT  37.508 2.148 37.612 103.752 ;
     RECT  37.612 2.418 37.685 103.752 ;
     RECT  37.685 2.418 37.804 103.56 ;
     RECT  37.804 85.68 37.865 87.576 ;
     RECT  37.804 41.904 37.955 44.376 ;
     RECT  37.804 101.856 37.973 103.56 ;
     RECT  37.804 47.76 37.996 50.28 ;
     RECT  37.955 42 38.081 44.376 ;
     RECT  37.973 101.856 38.081 103.32 ;
     RECT  38.081 101.856 38.195 103.224 ;
     RECT  38.195 101.856 38.225 102.696 ;
     RECT  37.804 81.36 38.297 81.432 ;
     RECT  37.804 88.704 38.549 88.728 ;
     RECT  38.081 42 38.765 43.56 ;
     RECT  38.297 81.36 38.765 81.384 ;
     RECT  37.804 38.016 38.771 38.904 ;
     RECT  37.804 51.6 38.771 51.912 ;
     RECT  37.804 58.896 38.801 59.016 ;
     RECT  37.865 85.68 38.833 85.704 ;
     RECT  37.865 87.024 38.833 87.576 ;
     RECT  38.833 85.68 38.837 87.576 ;
     RECT  38.771 38.448 38.905 38.904 ;
     RECT  37.804 40.32 38.905 40.392 ;
     RECT  38.797 46.752 38.905 46.776 ;
     RECT  37.996 47.76 38.905 49.032 ;
     RECT  37.804 45.408 38.941 45.432 ;
     RECT  38.905 38.448 39.017 40.392 ;
     RECT  38.837 85.68 39.017 87.336 ;
     RECT  38.225 102 39.053 102.696 ;
     RECT  39.013 41.568 39.161 41.592 ;
     RECT  38.905 46.752 39.161 49.032 ;
     RECT  39.053 102.672 39.301 102.696 ;
     RECT  39.193 104.88 39.337 104.904 ;
     RECT  39.337 104.88 39.625 105.72 ;
     RECT  37.996 50.16 39.661 50.28 ;
     RECT  39.445 90.624 39.661 90.648 ;
     RECT  39.553 98.592 39.661 98.616 ;
     RECT  39.661 50.16 39.797 50.328 ;
     RECT  38.771 51.6 39.797 51.624 ;
     RECT  39.797 50.16 39.829 51.624 ;
     RECT  39.661 90.048 39.884 90.648 ;
     RECT  39.661 98.064 40.021 98.616 ;
     RECT  40.021 98.064 40.069 98.76 ;
     RECT  40.129 34.464 40.208 34.488 ;
     RECT  39.017 38.592 40.208 40.392 ;
     RECT  39.985 41.376 40.208 41.4 ;
     RECT  38.765 42.72 40.208 43.56 ;
     RECT  38.941 44.64 40.208 45.432 ;
     RECT  39.161 47.136 40.208 49.032 ;
     RECT  39.829 50.16 40.208 51.672 ;
     RECT  37.804 53.328 40.208 53.352 ;
     RECT  37.804 56.784 40.208 56.808 ;
     RECT  38.801 58.992 40.208 59.016 ;
     RECT  37.804 60 40.208 60.36 ;
     RECT  39.445 83.52 40.208 83.544 ;
     RECT  39.017 85.68 40.208 85.704 ;
     RECT  39.017 87.312 40.208 87.336 ;
     RECT  39.884 90 40.208 90.648 ;
     RECT  40.069 98.064 40.208 99.72 ;
     RECT  39.301 102.672 40.208 103.08 ;
     RECT  40.208 2.148 40.312 103.152 ;
     RECT  39.625 104.88 40.385 105.768 ;
     RECT  40.312 2.418 40.4 103.152 ;
     RECT  40.385 104.88 40.457 104.904 ;
     RECT  40.4 2.418 40.504 103.422 ;
     RECT  40.504 45.456 40.673 45.528 ;
     RECT  40.504 43.056 40.709 44.472 ;
     RECT  40.504 46.896 40.709 49.176 ;
     RECT  40.709 43.296 40.739 44.472 ;
     RECT  40.504 50.304 40.739 50.328 ;
     RECT  40.504 98.736 40.925 99.72 ;
     RECT  40.709 48.72 40.997 49.176 ;
     RECT  40.997 48.72 41.075 48.984 ;
     RECT  40.504 39.024 41.177 41.4 ;
     RECT  41.177 39.024 41.321 40.44 ;
     RECT  40.504 51.312 41.533 53.832 ;
     RECT  41.321 39.024 41.645 40.392 ;
     RECT  41.533 50.64 41.713 53.832 ;
     RECT  40.673 45.456 41.717 45.48 ;
     RECT  41.645 39.024 41.821 39.624 ;
     RECT  40.504 34.08 41.857 34.488 ;
     RECT  40.709 46.896 41.857 47.64 ;
     RECT  41.857 46.752 41.893 47.64 ;
     RECT  41.713 50.544 42.109 53.832 ;
     RECT  40.504 56.784 42.14 56.808 ;
     RECT  42.109 50.544 42.181 54.696 ;
     RECT  42.14 56.112 42.181 56.808 ;
     RECT  40.739 43.344 42.22 44.472 ;
     RECT  41.075 48.72 42.289 48.744 ;
     RECT  42.085 42.096 42.361 42.12 ;
     RECT  42.361 41.424 42.397 42.12 ;
     RECT  40.925 98.736 42.397 98.76 ;
     RECT  42.397 41.424 42.505 42.312 ;
     RECT  42.22 43.296 42.505 44.472 ;
     RECT  42.397 98.64 42.505 98.76 ;
     RECT  42.421 91.344 42.517 91.368 ;
     RECT  41.821 38.448 42.685 39.624 ;
     RECT  42.505 41.424 42.685 44.472 ;
     RECT  41.857 33.936 42.757 34.488 ;
     RECT  41.893 46.08 42.757 47.64 ;
     RECT  42.289 48.72 42.757 49.032 ;
     RECT  42.181 50.544 42.757 54.888 ;
     RECT  42.421 30.384 42.908 30.408 ;
     RECT  42.757 33.936 42.908 35.208 ;
     RECT  42.649 36.912 42.908 36.936 ;
     RECT  42.685 38.448 42.908 44.472 ;
     RECT  42.757 46.08 42.908 54.888 ;
     RECT  42.181 56.112 42.908 57.048 ;
     RECT  40.504 58.992 42.908 59.016 ;
     RECT  40.504 60 42.908 60.36 ;
     RECT  42.757 79.248 42.908 79.704 ;
     RECT  40.504 83.52 42.908 83.544 ;
     RECT  40.504 85.68 42.908 85.704 ;
     RECT  42.517 91.104 42.908 91.368 ;
     RECT  42.505 98.064 42.908 98.76 ;
     RECT  42.908 2.148 43.012 103.152 ;
     RECT  43.012 2.418 43.1 103.152 ;
     RECT  43.1 2.418 43.204 103.422 ;
     RECT  43.204 51.456 43.301 57.576 ;
     RECT  43.301 51.648 43.331 57.576 ;
     RECT  43.331 51.696 43.955 57.576 ;
     RECT  43.204 36.912 44.003 44.472 ;
     RECT  44.003 38.976 44.021 44.472 ;
     RECT  44.021 39.024 44.093 44.472 ;
     RECT  43.204 91.104 44.165 91.368 ;
     RECT  44.093 39.6 44.201 44.472 ;
     RECT  44.201 41.616 44.273 44.472 ;
     RECT  44.273 43.296 44.291 44.472 ;
     RECT  44.165 91.344 44.453 91.368 ;
     RECT  44.449 68.208 44.521 68.232 ;
     RECT  44.377 76.32 44.521 76.344 ;
     RECT  44.521 68.16 44.593 68.232 ;
     RECT  44.341 74.592 44.593 74.616 ;
     RECT  43.955 51.696 44.597 55.032 ;
     RECT  44.588 71.664 44.629 72.6 ;
     RECT  44.593 74.112 44.629 74.616 ;
     RECT  43.204 46.752 44.665 49.368 ;
     RECT  44.593 68.112 44.665 68.232 ;
     RECT  44.629 71.664 44.917 74.616 ;
     RECT  44.629 77.664 44.917 77.688 ;
     RECT  44.665 46.56 44.953 49.368 ;
     RECT  44.917 77.664 44.989 77.88 ;
     RECT  44.665 68.112 45.061 68.76 ;
     RECT  44.917 71.664 45.061 74.712 ;
     RECT  44.269 70.272 45.133 70.296 ;
     RECT  44.521 75.936 45.133 76.344 ;
     RECT  44.989 77.328 45.133 77.88 ;
     RECT  44.953 46.224 45.308 49.368 ;
     RECT  45.061 71.424 45.308 74.712 ;
     RECT  45.133 75.936 45.308 77.88 ;
     RECT  45.308 71.424 45.349 77.88 ;
     RECT  45.308 46.224 45.385 49.992 ;
     RECT  44.597 51.696 45.385 54.936 ;
     RECT  45.061 67.824 45.385 68.76 ;
     RECT  44.273 41.616 45.493 41.928 ;
     RECT  44.291 43.392 45.493 44.472 ;
     RECT  43.204 30.384 45.608 30.408 ;
     RECT  43.204 33.936 45.608 35.256 ;
     RECT  44.003 36.912 45.608 37.608 ;
     RECT  44.201 39.6 45.608 40.632 ;
     RECT  45.493 41.616 45.608 44.472 ;
     RECT  45.385 46.224 45.608 54.936 ;
     RECT  43.955 56.016 45.608 57.576 ;
     RECT  43.204 58.992 45.608 59.016 ;
     RECT  43.204 60 45.608 60.36 ;
     RECT  45.385 66.864 45.608 68.76 ;
     RECT  45.133 70.272 45.608 70.392 ;
     RECT  45.349 71.424 45.608 77.976 ;
     RECT  43.204 83.52 45.608 83.544 ;
     RECT  45.608 2.148 45.712 103.152 ;
     RECT  45.712 2.418 45.8 103.152 ;
     RECT  45.8 2.418 45.904 103.422 ;
     RECT  45.904 46.224 45.965 47.88 ;
     RECT  45.965 46.224 46.001 47.736 ;
     RECT  45.904 58.992 46.019 60.792 ;
     RECT  46.001 46.512 46.037 47.736 ;
     RECT  46.037 46.56 46.073 47.736 ;
     RECT  45.904 70.272 46.073 78.072 ;
     RECT  46.073 46.56 46.109 47.64 ;
     RECT  45.904 48.96 46.145 51.96 ;
     RECT  45.904 44.352 46.181 44.424 ;
     RECT  46.109 47.376 46.217 47.64 ;
     RECT  45.904 55.824 46.289 57.912 ;
     RECT  46.217 47.376 46.325 47.4 ;
     RECT  45.904 39.504 46.793 39.624 ;
     RECT  46.073 70.368 46.793 78.072 ;
     RECT  46.793 70.368 46.829 77.88 ;
     RECT  46.796 105.744 46.882 105.768 ;
     RECT  45.904 97.92 46.933 97.944 ;
     RECT  46.019 60 47.041 60.792 ;
     RECT  45.904 53.04 47.113 54.552 ;
     RECT  46.145 48.96 47.117 50.568 ;
     RECT  46.933 97.92 47.125 98.472 ;
     RECT  46.145 51.6 47.18 51.96 ;
     RECT  47.113 53.04 47.18 54.696 ;
     RECT  46.181 44.352 47.185 44.376 ;
     RECT  46.289 57.888 47.185 57.912 ;
     RECT  46.019 58.992 47.185 59.016 ;
     RECT  45.904 41.52 47.221 42.744 ;
     RECT  47.185 44.352 47.225 45 ;
     RECT  46.829 70.368 47.228 77.304 ;
     RECT  45.904 36.912 47.257 37.608 ;
     RECT  46.289 55.824 47.257 56.808 ;
     RECT  47.185 57.888 47.257 59.016 ;
     RECT  47.221 40.944 47.293 42.744 ;
     RECT  47.228 70.272 47.315 77.304 ;
     RECT  47.315 70.608 47.341 77.304 ;
     RECT  47.293 40.944 47.401 42.84 ;
     RECT  46.882 105.696 47.458 105.768 ;
     RECT  47.413 96.816 47.509 96.84 ;
     RECT  47.125 97.872 47.509 98.472 ;
     RECT  47.18 51.6 47.581 54.696 ;
     RECT  47.257 55.824 47.581 59.016 ;
     RECT  47.041 60 47.617 60.84 ;
     RECT  47.458 105.648 47.651 105.768 ;
     RECT  47.581 45.984 47.689 46.008 ;
     RECT  45.904 66.24 47.689 68.76 ;
     RECT  47.509 96.816 47.797 98.472 ;
     RECT  47.401 40.944 47.833 43.32 ;
     RECT  47.651 105.648 47.891 105.72 ;
     RECT  46.793 39.504 47.941 39.528 ;
     RECT  47.761 63.072 47.941 63.096 ;
     RECT  47.225 44.88 48.049 45 ;
     RECT  47.689 45.984 48.049 46.776 ;
     RECT  48.085 105.072 48.133 105.096 ;
     RECT  48.133 104.976 48.149 105.096 ;
     RECT  47.581 51.6 48.181 59.016 ;
     RECT  47.617 60 48.181 61.608 ;
     RECT  47.941 38.784 48.193 39.528 ;
     RECT  47.941 63.072 48.301 63.624 ;
     RECT  45.904 30.384 48.308 30.408 ;
     RECT  45.904 33.936 48.308 35.256 ;
     RECT  47.257 36.864 48.308 37.608 ;
     RECT  48.193 38.784 48.308 39.624 ;
     RECT  47.833 40.848 48.308 43.32 ;
     RECT  48.049 44.88 48.308 46.776 ;
     RECT  47.833 47.856 48.308 47.88 ;
     RECT  47.117 48.96 48.308 50.136 ;
     RECT  48.181 51.6 48.308 61.608 ;
     RECT  48.301 62.976 48.308 63.624 ;
     RECT  47.689 66.24 48.308 69.048 ;
     RECT  47.341 70.992 48.308 77.304 ;
     RECT  45.904 83.52 48.308 83.544 ;
     RECT  47.756 87.696 48.308 87.72 ;
     RECT  47.797 96.336 48.308 98.472 ;
     RECT  48.308 2.148 48.412 103.152 ;
     RECT  48.412 2.418 48.5 103.152 ;
     RECT  48.5 2.418 48.604 103.422 ;
     RECT  48.604 58.128 48.701 60.84 ;
     RECT  48.604 43.728 48.755 43.752 ;
     RECT  48.604 38.688 48.773 40.968 ;
     RECT  48.604 36.816 48.995 37.608 ;
     RECT  48.604 61.824 49.025 77.544 ;
     RECT  48.604 25.056 49.033 25.08 ;
     RECT  48.604 96.336 49.033 98.472 ;
     RECT  48.149 104.88 49.057 105.096 ;
     RECT  48.995 36.816 49.061 36.936 ;
     RECT  48.604 44.88 49.061 57.048 ;
     RECT  49.025 62.448 49.097 77.544 ;
     RECT  49.061 46.368 49.241 57.048 ;
     RECT  49.241 55.2 49.277 57.048 ;
     RECT  48.604 87.12 49.313 87.144 ;
     RECT  49.241 46.368 49.421 53.928 ;
     RECT  49.421 46.368 49.529 46.68 ;
     RECT  49.061 44.88 49.601 44.952 ;
     RECT  49.277 55.44 49.705 57.048 ;
     RECT  48.701 58.656 49.705 60.84 ;
     RECT  49.529 46.368 49.709 46.392 ;
     RECT  49.097 67.056 49.741 77.544 ;
     RECT  49.741 67.056 49.745 77.688 ;
     RECT  48.604 102 49.765 103.368 ;
     RECT  49.745 71.376 49.813 77.688 ;
     RECT  49.705 78.72 49.813 78.744 ;
     RECT  48.604 88.752 49.813 88.776 ;
     RECT  48.773 40.848 49.853 40.968 ;
     RECT  49.033 96.816 49.853 98.472 ;
     RECT  49.813 88.752 49.861 88.92 ;
     RECT  48.773 38.688 49.885 39.624 ;
     RECT  49.861 88.704 49.909 88.92 ;
     RECT  49.885 38.16 49.921 39.624 ;
     RECT  49.601 44.928 49.925 44.952 ;
     RECT  49.705 55.44 49.955 60.84 ;
     RECT  49.909 88.368 49.957 88.92 ;
     RECT  49.853 96.816 50.041 98.088 ;
     RECT  49.057 104.88 50.053 105.768 ;
     RECT  49.955 56.4 50.101 60.84 ;
     RECT  49.097 62.448 50.101 65.784 ;
     RECT  49.745 67.056 50.101 70.248 ;
     RECT  49.813 71.376 50.197 78.744 ;
     RECT  49.765 102 50.245 103.464 ;
     RECT  50.041 96.816 50.281 97.512 ;
     RECT  50.281 42 50.389 42.024 ;
     RECT  50.425 43.392 50.605 43.416 ;
     RECT  50.197 80.544 50.629 80.568 ;
     RECT  50.197 71.376 50.641 79.128 ;
     RECT  50.629 80.544 50.641 80.952 ;
     RECT  50.605 43.392 50.677 43.656 ;
     RECT  50.677 43.392 50.713 43.944 ;
     RECT  50.053 104.688 50.725 105.768 ;
     RECT  50.101 25.824 50.749 25.848 ;
     RECT  50.749 24.912 50.785 25.848 ;
     RECT  50.725 104.544 50.821 105.768 ;
     RECT  50.245 101.712 50.924 103.464 ;
     RECT  50.821 104.496 50.924 105.768 ;
     RECT  50.785 24.912 51.008 26.808 ;
     RECT  48.604 30.384 51.008 30.408 ;
     RECT  48.604 33.936 51.008 35.256 ;
     RECT  49.061 36.816 51.008 36.888 ;
     RECT  49.921 38.16 51.008 40.296 ;
     RECT  50.389 41.664 51.008 42.024 ;
     RECT  50.713 43.392 51.008 44.184 ;
     RECT  50.605 46.224 51.008 46.248 ;
     RECT  49.421 47.664 51.008 53.928 ;
     RECT  50.101 56.4 51.008 70.248 ;
     RECT  50.641 71.376 51.008 80.952 ;
     RECT  48.604 83.52 51.008 83.544 ;
     RECT  49.957 88.368 51.008 89.208 ;
     RECT  50.281 96.336 51.008 97.512 ;
     RECT  50.677 100.656 51.008 100.68 ;
     RECT  50.924 101.712 51.008 105.768 ;
     RECT  51.008 2.148 51.112 105.768 ;
     RECT  51.112 2.418 51.304 105.768 ;
     RECT  51.304 66.048 51.329 79.512 ;
     RECT  51.304 80.544 51.365 81.096 ;
     RECT  51.304 41.04 51.437 44.472 ;
     RECT  51.329 66.144 51.545 79.512 ;
     RECT  51.304 47.664 51.581 51.384 ;
     RECT  51.304 52.944 51.581 55.32 ;
     RECT  51.304 33.936 51.805 39.624 ;
     RECT  51.304 56.352 51.869 59.064 ;
     RECT  51.545 66.144 51.923 73.08 ;
     RECT  51.869 56.352 51.941 56.904 ;
     RECT  51.437 41.04 52.013 44.184 ;
     RECT  51.805 33.936 52.085 37.416 ;
     RECT  52.013 41.472 52.121 44.184 ;
     RECT  51.923 68.112 52.3 73.08 ;
     RECT  51.581 52.944 52.325 55.224 ;
     RECT  51.304 82.272 52.333 83.544 ;
     RECT  51.581 47.664 52.348 50.664 ;
     RECT  52.405 85.776 52.453 86.616 ;
     RECT  51.304 25.68 52.513 26.808 ;
     RECT  51.365 80.784 52.513 81.096 ;
     RECT  52.333 82.272 52.513 83.784 ;
     RECT  52.121 43.776 52.517 44.184 ;
     RECT  51.923 66.144 52.604 67.08 ;
     RECT  52.3 71.424 52.621 73.08 ;
     RECT  51.545 74.112 52.621 79.512 ;
     RECT  52.621 71.424 52.645 79.512 ;
     RECT  52.513 80.784 52.645 83.784 ;
     RECT  51.304 60.816 52.657 64.344 ;
     RECT  52.645 71.424 52.661 83.784 ;
     RECT  52.604 65.52 52.691 67.08 ;
     RECT  51.304 88.368 52.697 89.208 ;
     RECT  52.513 25.68 52.729 27.336 ;
     RECT  51.869 57.936 52.729 59.064 ;
     RECT  52.453 85.488 52.865 86.616 ;
     RECT  52.657 23.376 52.909 23.4 ;
     RECT  52.909 23.376 52.945 23.64 ;
     RECT  52.121 41.472 53.017 42.792 ;
     RECT  51.805 38.784 53.125 39.624 ;
     RECT  52.517 44.16 53.233 44.184 ;
     RECT  51.304 30.384 53.305 30.408 ;
     RECT  52.085 33.936 53.305 36.936 ;
     RECT  53.125 38.256 53.305 39.624 ;
     RECT  52.691 65.664 53.305 67.08 ;
     RECT  52.325 52.464 53.341 55.224 ;
     RECT  52.945 23.376 53.377 23.88 ;
     RECT  52.661 71.424 53.449 80.952 ;
     RECT  52.729 57.936 53.461 59.112 ;
     RECT  52.348 50.64 53.485 50.664 ;
     RECT  52.657 60.816 53.519 64.392 ;
     RECT  53.305 30.144 53.557 30.408 ;
     RECT  53.017 40.992 53.557 42.792 ;
     RECT  52.348 47.664 53.557 49.608 ;
     RECT  53.485 50.64 53.557 50.904 ;
     RECT  52.3 68.112 53.557 70.296 ;
     RECT  53.449 71.376 53.557 80.952 ;
     RECT  53.557 47.664 53.593 50.904 ;
     RECT  53.233 44.16 53.665 45 ;
     RECT  53.377 23.376 53.708 23.928 ;
     RECT  52.729 25.296 53.708 27.336 ;
     RECT  53.557 30 53.708 30.984 ;
     RECT  53.557 32.832 53.708 32.856 ;
     RECT  53.305 33.936 53.708 39.624 ;
     RECT  53.557 40.896 53.708 42.792 ;
     RECT  53.665 43.92 53.708 45 ;
     RECT  53.053 46.608 53.708 46.632 ;
     RECT  53.593 47.664 53.708 50.952 ;
     RECT  53.341 52.224 53.708 55.224 ;
     RECT  51.941 56.352 53.708 56.808 ;
     RECT  53.461 57.936 53.708 59.304 ;
     RECT  53.519 60.336 53.708 64.392 ;
     RECT  53.305 65.664 53.708 67.128 ;
     RECT  53.557 68.112 53.708 80.952 ;
     RECT  52.661 82.032 53.708 83.784 ;
     RECT  52.865 85.488 53.708 87.24 ;
     RECT  52.697 88.368 53.708 88.392 ;
     RECT  51.304 100.512 53.708 105.768 ;
     RECT  53.708 2.148 53.812 105.768 ;
     RECT  53.812 2.418 54.004 105.768 ;
     RECT  54.004 23.616 54.029 26.856 ;
     RECT  54.004 40.56 54.131 51.672 ;
     RECT  54.004 98.496 54.145 98.616 ;
     RECT  54.131 41.712 54.172 44.808 ;
     RECT  54.145 98.592 54.172 98.616 ;
     RECT  54.172 41.712 54.173 42.744 ;
     RECT  54.004 30.144 54.245 30.984 ;
     RECT  54.004 52.8 54.317 55.416 ;
     RECT  54.004 32.976 54.371 35.832 ;
     RECT  54.172 44.352 54.497 44.808 ;
     RECT  54.371 33.936 54.605 35.832 ;
     RECT  54.131 46.128 54.605 51.672 ;
     RECT  54.004 68.16 54.707 87.288 ;
     RECT  54.605 46.128 54.746 50.664 ;
     RECT  54.707 78.672 54.755 87.288 ;
     RECT  54.605 33.936 54.785 35.592 ;
     RECT  54.605 51.648 54.785 51.672 ;
     RECT  54.245 30.384 54.821 30.984 ;
     RECT  54.755 78.672 54.899 84.888 ;
     RECT  54.899 84.864 54.929 84.888 ;
     RECT  54.131 40.56 54.94 40.584 ;
     RECT  54.899 78.672 54.965 83.832 ;
     RECT  54.707 68.16 55.037 77.688 ;
     RECT  54.029 26.832 55.069 26.856 ;
     RECT  55.045 88.56 55.132 88.584 ;
     RECT  55.037 68.16 55.145 77.304 ;
     RECT  54.965 78.672 55.145 79.512 ;
     RECT  54.965 80.784 55.289 83.832 ;
     RECT  54.746 46.128 55.331 50.616 ;
     RECT  54.004 57.936 55.357 57.96 ;
     RECT  54.004 58.944 55.357 67.128 ;
     RECT  54.173 41.712 55.381 42.216 ;
     RECT  54.755 86.304 55.393 87.288 ;
     RECT  54.004 100.512 55.397 105.768 ;
     RECT  54.029 23.616 55.429 25.752 ;
     RECT  55.069 26.832 55.429 27.048 ;
     RECT  55.331 46.128 55.429 47.208 ;
     RECT  54.004 56.496 55.465 56.808 ;
     RECT  55.357 57.936 55.465 67.128 ;
     RECT  55.465 56.496 55.645 67.128 ;
     RECT  55.145 68.16 55.645 77.16 ;
     RECT  55.381 41.712 55.669 42.84 ;
     RECT  55.429 23.616 55.681 27.048 ;
     RECT  55.397 100.512 55.765 104.664 ;
     RECT  55.765 100.272 55.813 104.664 ;
     RECT  55.669 41.232 55.861 42.84 ;
     RECT  55.813 99.744 56.005 104.664 ;
     RECT  54.497 44.352 56.077 44.376 ;
     RECT  55.331 48.384 56.101 50.616 ;
     RECT  55.861 85.248 56.113 85.272 ;
     RECT  56.113 84.912 56.245 85.272 ;
     RECT  55.393 86.304 56.245 87.432 ;
     RECT  56.005 99.168 56.245 104.664 ;
     RECT  54.004 36.864 56.329 39.528 ;
     RECT  55.861 41.232 56.329 43.128 ;
     RECT  56.077 44.112 56.329 44.376 ;
     RECT  56.329 36.864 56.365 39.624 ;
     RECT  56.329 41.232 56.365 44.376 ;
     RECT  55.429 45.552 56.365 47.208 ;
     RECT  56.101 48.384 56.365 51.336 ;
     RECT  55.397 105.696 56.405 105.768 ;
     RECT  55.681 23.616 56.408 27.192 ;
     RECT  54.821 30.384 56.408 30.408 ;
     RECT  55.213 31.92 56.408 31.944 ;
     RECT  54.785 33.936 56.408 35.496 ;
     RECT  56.365 36.864 56.408 51.336 ;
     RECT  54.317 53.04 56.408 55.416 ;
     RECT  55.645 56.496 56.408 77.16 ;
     RECT  55.145 78.72 56.408 79.512 ;
     RECT  55.289 80.784 56.408 81.192 ;
     RECT  55.289 82.224 56.408 83.832 ;
     RECT  56.245 84.912 56.408 87.432 ;
     RECT  56.197 88.992 56.408 89.016 ;
     RECT  56.293 92.976 56.408 93 ;
     RECT  56.245 98.976 56.408 104.664 ;
     RECT  56.408 2.148 56.485 104.664 ;
     RECT  56.405 105.696 56.485 105.72 ;
     RECT  56.485 2.148 56.512 105.72 ;
     RECT  56.512 2.418 56.704 105.72 ;
     RECT  56.704 80.016 56.801 83.832 ;
     RECT  56.704 23.568 56.867 27.912 ;
     RECT  56.704 29.424 56.867 31.752 ;
     RECT  56.867 29.424 56.881 30.408 ;
     RECT  56.867 31.488 56.981 31.752 ;
     RECT  56.704 46.512 57.125 55.272 ;
     RECT  56.881 29.808 57.161 30.408 ;
     RECT  56.704 56.544 57.347 78.936 ;
     RECT  57.347 56.544 57.377 76.872 ;
     RECT  56.704 45.12 57.805 45.192 ;
     RECT  57.125 46.512 57.805 50.664 ;
     RECT  56.801 80.016 57.805 83.592 ;
     RECT  56.981 31.488 57.809 31.512 ;
     RECT  56.704 86.016 57.817 89.016 ;
     RECT  57.817 86.016 57.845 86.04 ;
     RECT  57.817 87.312 57.845 89.016 ;
     RECT  56.704 98.976 57.949 105.72 ;
     RECT  56.704 92.976 57.973 93 ;
     RECT  56.704 37.968 57.985 38.52 ;
     RECT  56.704 39.504 57.985 44.136 ;
     RECT  57.125 51.84 58.021 55.272 ;
     RECT  57.949 98.64 58.033 105.72 ;
     RECT  58.021 51.84 58.129 55.56 ;
     RECT  57.805 45.12 58.165 50.664 ;
     RECT  58.129 51.744 58.165 55.56 ;
     RECT  57.161 30.144 58.345 30.408 ;
     RECT  56.704 33.936 58.381 35.496 ;
     RECT  57.347 78.096 58.405 78.936 ;
     RECT  57.377 56.784 58.489 76.872 ;
     RECT  56.867 23.568 58.633 26.232 ;
     RECT  58.033 98.976 58.643 105.72 ;
     RECT  58.643 98.976 58.691 105.48 ;
     RECT  58.381 33.936 58.705 35.544 ;
     RECT  58.405 77.904 58.705 78.936 ;
     RECT  57.805 80.016 58.705 83.784 ;
     RECT  58.633 22.752 58.777 26.232 ;
     RECT  56.867 27.216 58.777 27.912 ;
     RECT  58.165 45.12 58.777 55.56 ;
     RECT  58.489 56.592 58.777 76.872 ;
     RECT  57.845 87.552 58.813 89.016 ;
     RECT  58.705 33.84 58.844 35.544 ;
     RECT  58.345 30.144 58.885 31.128 ;
     RECT  58.844 32.976 58.885 35.544 ;
     RECT  58.705 77.904 58.949 83.784 ;
     RECT  58.813 87.36 58.957 89.016 ;
     RECT  58.777 45.12 58.981 76.872 ;
     RECT  58.949 77.904 58.981 84.408 ;
     RECT  58.777 22.752 59.108 27.912 ;
     RECT  58.885 30.144 59.108 35.544 ;
     RECT  56.704 36.864 59.108 36.936 ;
     RECT  57.985 37.968 59.108 44.136 ;
     RECT  58.981 45.12 59.108 84.408 ;
     RECT  58.993 85.392 59.108 85.416 ;
     RECT  58.957 87.024 59.108 89.016 ;
     RECT  58.597 91.2 59.108 91.224 ;
     RECT  57.973 92.256 59.108 93 ;
     RECT  58.691 98.976 59.108 104.616 ;
     RECT  59.108 2.148 59.212 104.616 ;
     RECT  59.212 2.418 59.404 104.616 ;
     RECT  59.404 92.256 59.465 93.288 ;
     RECT  59.404 22.752 59.537 28.2 ;
     RECT  59.404 45.168 59.681 49.08 ;
     RECT  59.404 101.424 59.747 104.616 ;
     RECT  59.404 99.168 59.761 100.296 ;
     RECT  59.747 101.712 59.789 104.616 ;
     RECT  59.404 60.816 59.825 71.208 ;
     RECT  59.681 45.168 59.861 48.792 ;
     RECT  59.761 100.08 59.861 100.296 ;
     RECT  59.537 22.752 59.891 26.76 ;
     RECT  59.404 79.104 59.897 80.136 ;
     RECT  59.404 37.968 59.969 42.024 ;
     RECT  59.404 72.192 60.035 77.976 ;
     RECT  59.861 45.168 60.221 48.744 ;
     RECT  59.861 100.08 60.257 100.104 ;
     RECT  59.537 27.792 60.373 28.2 ;
     RECT  59.404 32.496 60.373 32.52 ;
     RECT  59.404 33.84 60.373 35.544 ;
     RECT  59.404 57.888 60.397 59.784 ;
     RECT  59.825 60.816 60.397 66.6 ;
     RECT  59.404 81.168 60.397 84.072 ;
     RECT  59.404 85.392 60.397 87.048 ;
     RECT  60.373 27.792 60.46 28.968 ;
     RECT  60.373 32.496 60.46 35.544 ;
     RECT  60.397 81.168 60.469 87.048 ;
     RECT  59.404 88.176 60.469 89.016 ;
     RECT  60.469 81.168 60.515 89.016 ;
     RECT  60.46 32.496 60.577 32.712 ;
     RECT  59.404 30.384 60.611 30.936 ;
     RECT  60.46 33.84 60.649 35.544 ;
     RECT  59.404 36.864 60.649 36.936 ;
     RECT  59.404 50.352 60.757 56.904 ;
     RECT  60.469 90.624 60.761 90.648 ;
     RECT  59.404 43.056 60.793 44.136 ;
     RECT  60.035 77.952 60.829 77.976 ;
     RECT  59.897 79.104 60.829 80.04 ;
     RECT  59.789 104.592 60.833 104.616 ;
     RECT  59.825 67.776 60.901 71.208 ;
     RECT  60.829 77.952 60.901 80.04 ;
     RECT  60.515 81.168 60.901 88.92 ;
     RECT  60.793 42.912 61.045 44.136 ;
     RECT  60.221 45.168 61.045 48.696 ;
     RECT  60.397 57.888 61.045 66.6 ;
     RECT  60.901 67.68 61.045 71.208 ;
     RECT  61.045 42.912 61.081 48.696 ;
     RECT  60.757 50.016 61.117 56.904 ;
     RECT  61.045 57.888 61.117 71.208 ;
     RECT  61.052 98.208 61.181 98.232 ;
     RECT  60.035 72.192 61.189 76.968 ;
     RECT  60.901 77.952 61.189 88.92 ;
     RECT  59.891 23.04 61.237 26.76 ;
     RECT  60.46 27.792 61.237 28.824 ;
     RECT  61.181 98.064 61.292 98.232 ;
     RECT  59.789 101.712 61.292 103.56 ;
     RECT  61.292 101.424 61.333 103.56 ;
     RECT  61.081 42.864 61.405 48.696 ;
     RECT  61.189 72.192 61.525 88.92 ;
     RECT  61.153 90.048 61.525 90.072 ;
     RECT  61.333 100.896 61.525 103.56 ;
     RECT  61.237 23.04 61.549 28.824 ;
     RECT  60.577 31.968 61.573 32.712 ;
     RECT  60.649 33.84 61.573 36.936 ;
     RECT  61.009 105.744 61.573 105.768 ;
     RECT  61.292 98.064 61.621 99.048 ;
     RECT  59.969 37.968 61.657 41.688 ;
     RECT  61.405 42.816 61.657 48.696 ;
     RECT  60.611 30.912 61.669 30.936 ;
     RECT  61.573 31.968 61.669 36.936 ;
     RECT  61.549 23.04 61.808 29.256 ;
     RECT  61.669 30.864 61.808 30.936 ;
     RECT  61.669 31.92 61.808 36.936 ;
     RECT  61.657 37.968 61.808 48.696 ;
     RECT  61.117 50.016 61.808 71.208 ;
     RECT  61.525 72.192 61.808 90.072 ;
     RECT  61.397 91.776 61.808 91.8 ;
     RECT  59.465 92.976 61.808 93.288 ;
     RECT  61.621 97.584 61.808 99.048 ;
     RECT  61.525 100.896 61.808 103.752 ;
     RECT  61.808 2.148 61.841 103.752 ;
     RECT  61.841 2.148 61.912 103.56 ;
     RECT  61.912 2.418 62.104 103.56 ;
     RECT  62.104 39.6 62.129 71.208 ;
     RECT  61.573 104.88 62.147 105.768 ;
     RECT  62.104 80.016 62.165 85.416 ;
     RECT  62.104 101.472 62.188 103.56 ;
     RECT  62.165 80.064 62.309 85.416 ;
     RECT  62.104 90.384 62.309 93.288 ;
     RECT  62.188 101.472 62.489 103.272 ;
     RECT  62.104 28.464 62.525 36.936 ;
     RECT  62.104 86.544 62.525 89.256 ;
     RECT  62.129 39.6 62.597 62.52 ;
     RECT  62.597 50.016 62.666 62.52 ;
     RECT  62.309 80.112 62.675 85.416 ;
     RECT  62.104 72.24 62.705 78.696 ;
     RECT  62.666 50.064 62.713 62.52 ;
     RECT  62.309 90.624 62.813 93.288 ;
     RECT  62.713 50.064 62.819 55.608 ;
     RECT  62.819 50.064 62.849 50.76 ;
     RECT  62.129 63.744 62.885 71.208 ;
     RECT  62.525 31.248 62.957 36.936 ;
     RECT  62.104 98.208 62.963 99.192 ;
     RECT  62.147 105.648 62.963 105.768 ;
     RECT  62.705 72.24 63.029 78.264 ;
     RECT  62.525 86.64 63.101 89.256 ;
     RECT  62.104 22.176 63.137 26.376 ;
     RECT  62.957 31.296 63.164 36.936 ;
     RECT  62.104 37.92 63.164 38.52 ;
     RECT  62.675 80.112 63.203 84.84 ;
     RECT  62.597 39.6 63.251 48.84 ;
     RECT  63.169 104.88 63.253 104.904 ;
     RECT  62.713 56.784 63.349 62.52 ;
     RECT  63.203 80.112 63.385 80.136 ;
     RECT  63.101 86.64 63.461 89.16 ;
     RECT  63.461 86.64 63.497 88.824 ;
     RECT  63.497 86.64 63.533 88.776 ;
     RECT  62.489 102.048 63.569 103.272 ;
     RECT  63.533 86.64 63.673 86.664 ;
     RECT  63.137 23.136 63.692 26.376 ;
     RECT  63.692 23.136 63.745 27.288 ;
     RECT  62.525 28.464 63.745 30.168 ;
     RECT  62.813 90.624 63.781 92.712 ;
     RECT  63.745 23.136 63.925 30.168 ;
     RECT  63.164 31.296 63.925 38.52 ;
     RECT  62.819 51.888 63.925 55.608 ;
     RECT  63.349 56.784 63.925 62.568 ;
     RECT  63.925 51.888 63.961 62.568 ;
     RECT  62.885 63.888 63.961 71.208 ;
     RECT  63.781 90.624 63.961 93.528 ;
     RECT  63.673 86.304 63.997 86.664 ;
     RECT  63.961 51.888 64.069 71.208 ;
     RECT  63.029 72.24 64.069 78.216 ;
     RECT  63.961 90.576 64.069 93.528 ;
     RECT  64.069 51.888 64.141 78.216 ;
     RECT  63.385 79.488 64.141 80.136 ;
     RECT  64.141 51.888 64.177 80.136 ;
     RECT  63.203 81.168 64.177 84.84 ;
     RECT  64.069 90.576 64.285 94.056 ;
     RECT  63.925 23.136 64.357 38.52 ;
     RECT  63.251 39.6 64.501 48.696 ;
     RECT  64.357 22.848 64.508 38.52 ;
     RECT  64.501 39.552 64.508 48.696 ;
     RECT  62.849 50.112 64.508 50.76 ;
     RECT  64.177 51.888 64.508 84.84 ;
     RECT  63.997 86.016 64.508 86.664 ;
     RECT  63.533 88.08 64.508 88.776 ;
     RECT  64.285 90.048 64.508 94.056 ;
     RECT  62.963 98.928 64.508 99.192 ;
     RECT  63.569 102.048 64.508 103.224 ;
     RECT  64.508 2.148 64.612 103.224 ;
     RECT  64.612 2.418 64.7 103.224 ;
     RECT  64.7 2.418 64.804 103.422 ;
     RECT  64.804 84.912 64.972 94.056 ;
     RECT  64.804 51.072 65.009 83.688 ;
     RECT  64.972 84.912 65.009 88.776 ;
     RECT  65.009 51.072 65.171 83.64 ;
     RECT  65.171 51.36 65.225 83.64 ;
     RECT  65.009 84.912 65.261 88.68 ;
     RECT  64.804 27.36 65.333 49.992 ;
     RECT  65.261 88.656 65.369 88.68 ;
     RECT  65.261 84.912 65.797 87.576 ;
     RECT  65.66 105.744 65.89 105.768 ;
     RECT  65.89 105.696 65.948 105.768 ;
     RECT  65.333 27.408 65.981 49.992 ;
     RECT  65.941 95.136 65.989 95.16 ;
     RECT  64.972 89.952 66.049 94.056 ;
     RECT  64.804 102.432 66.083 103.224 ;
     RECT  66.049 89.088 66.085 94.056 ;
     RECT  65.989 95.136 66.085 95.688 ;
     RECT  65.797 84.864 66.157 87.576 ;
     RECT  64.804 21.648 66.193 21.672 ;
     RECT  65.981 31.2 66.197 49.992 ;
     RECT  65.225 51.36 66.197 83.592 ;
     RECT  66.193 21.504 66.233 21.672 ;
     RECT  66.197 32.256 66.265 49.992 ;
     RECT  66.197 51.36 66.373 78.168 ;
     RECT  66.037 101.088 66.481 101.112 ;
     RECT  66.083 102.432 66.481 103.08 ;
     RECT  66.085 89.088 66.553 95.688 ;
     RECT  64.804 22.8 66.625 26.376 ;
     RECT  65.981 27.408 66.625 30.168 ;
     RECT  66.265 32.256 66.661 50.136 ;
     RECT  66.373 51.216 66.661 78.168 ;
     RECT  66.157 84.576 66.661 87.576 ;
     RECT  66.553 88.896 66.661 95.688 ;
     RECT  66.661 84.576 66.853 95.688 ;
     RECT  64.804 96.768 66.853 96.792 ;
     RECT  66.197 79.728 66.949 83.592 ;
     RECT  66.853 84.576 66.949 96.792 ;
     RECT  66.625 22.8 66.985 30.168 ;
     RECT  66.197 31.2 66.985 31.224 ;
     RECT  66.233 21.504 67.208 21.528 ;
     RECT  66.985 22.8 67.208 31.224 ;
     RECT  66.661 32.256 67.208 78.168 ;
     RECT  66.949 79.728 67.208 96.792 ;
     RECT  66.481 101.088 67.208 103.08 ;
     RECT  67.208 2.148 67.312 103.152 ;
     RECT  67.312 2.418 67.4 103.152 ;
     RECT  67.4 2.418 67.504 103.422 ;
     RECT  67.504 32.256 67.619 78.168 ;
     RECT  67.619 36.864 67.637 78.168 ;
     RECT  67.637 56.88 67.709 78.168 ;
     RECT  67.504 79.152 67.853 89.496 ;
     RECT  67.504 90.528 67.853 96.792 ;
     RECT  67.853 92.208 67.889 96.792 ;
     RECT  67.853 79.152 67.907 88.728 ;
     RECT  65.948 105.6 67.921 105.768 ;
     RECT  67.504 22.128 67.925 29.88 ;
     RECT  67.637 36.864 68.069 55.896 ;
     RECT  67.907 79.152 68.069 81.192 ;
     RECT  67.925 22.128 68.285 29.784 ;
     RECT  67.709 73.824 68.393 78.168 ;
     RECT  67.709 56.88 68.429 72.792 ;
     RECT  67.853 90.528 68.537 91.08 ;
     RECT  67.504 31.2 68.677 31.224 ;
     RECT  67.619 32.256 68.677 35.544 ;
     RECT  67.504 101.088 68.677 103.368 ;
     RECT  68.677 31.2 68.749 35.544 ;
     RECT  68.537 90.816 68.771 91.08 ;
     RECT  67.921 104.88 68.771 105.768 ;
     RECT  68.869 99.744 68.917 99.768 ;
     RECT  68.069 79.296 68.929 81.192 ;
     RECT  67.907 82.272 68.929 88.728 ;
     RECT  68.069 36.864 68.933 55.56 ;
     RECT  68.677 100.8 68.965 103.368 ;
     RECT  68.429 63.552 69.001 72.792 ;
     RECT  68.393 73.824 69.001 74.664 ;
     RECT  67.889 92.208 69.073 96.504 ;
     RECT  69.073 92.208 69.109 96.84 ;
     RECT  68.917 99.456 69.157 99.768 ;
     RECT  68.965 100.8 69.157 103.464 ;
     RECT  69.157 99.456 69.184 103.464 ;
     RECT  69.184 99.456 69.253 103.512 ;
     RECT  68.393 75.84 69.389 78.168 ;
     RECT  68.929 79.296 69.389 88.728 ;
     RECT  68.771 104.88 69.395 105.672 ;
     RECT  69.001 63.552 69.397 74.664 ;
     RECT  69.389 75.84 69.397 88.728 ;
     RECT  68.285 22.752 69.433 29.784 ;
     RECT  68.749 31.2 69.433 35.784 ;
     RECT  69.397 63.552 69.469 88.728 ;
     RECT  69.395 105.024 69.473 105.672 ;
     RECT  68.429 56.88 69.721 62.568 ;
     RECT  69.469 63.552 69.721 88.92 ;
     RECT  69.253 99.168 69.829 103.512 ;
     RECT  69.473 105.312 69.829 105.672 ;
     RECT  69.433 22.752 69.908 35.784 ;
     RECT  68.933 36.864 69.908 48.792 ;
     RECT  68.933 49.776 69.908 55.56 ;
     RECT  69.721 56.88 69.908 88.92 ;
     RECT  69.865 90.048 69.908 90.072 ;
     RECT  69.109 91.392 69.908 96.84 ;
     RECT  69.461 98.064 69.908 98.088 ;
     RECT  69.829 99.168 69.908 103.56 ;
     RECT  69.829 105.312 69.913 105.72 ;
     RECT  69.908 2.148 70.001 103.56 ;
     RECT  70.001 2.148 70.012 103.752 ;
     RECT  70.012 2.418 70.085 103.752 ;
     RECT  70.085 2.418 70.204 103.608 ;
     RECT  70.204 22.992 70.481 77.592 ;
     RECT  70.204 99.696 70.481 103.608 ;
     RECT  70.204 81.168 70.553 97.032 ;
     RECT  69.913 105.312 70.979 105.672 ;
     RECT  70.481 22.992 71.021 38.52 ;
     RECT  70.553 81.168 71.201 91.752 ;
     RECT  70.204 80.112 71.233 80.136 ;
     RECT  71.201 81.168 71.233 90.36 ;
     RECT  71.021 23.04 71.273 38.52 ;
     RECT  70.481 39.6 71.453 77.592 ;
     RECT  71.273 23.136 71.485 38.52 ;
     RECT  71.453 39.6 71.485 77.544 ;
     RECT  71.201 91.728 71.605 91.752 ;
     RECT  70.553 93.216 71.605 97.032 ;
     RECT  70.979 105.552 71.747 105.672 ;
     RECT  71.747 105.552 71.795 105.576 ;
     RECT  70.204 78.672 71.845 79.128 ;
     RECT  71.845 78.624 71.917 79.128 ;
     RECT  71.233 80.112 71.917 90.36 ;
     RECT  71.917 78.624 72.205 90.36 ;
     RECT  71.485 23.136 72.608 77.544 ;
     RECT  72.205 78.624 72.608 90.696 ;
     RECT  71.605 91.728 72.608 97.032 ;
     RECT  70.481 99.696 72.608 103.512 ;
     RECT  72.608 2.148 72.712 103.512 ;
     RECT  72.712 2.418 72.904 103.512 ;
     RECT  72.904 93.072 73.037 96.504 ;
     RECT  72.904 75.936 73.043 77.592 ;
     RECT  72.904 23.136 73.081 74.616 ;
     RECT  72.904 78.624 73.109 78.648 ;
     RECT  72.904 100.608 73.109 100.824 ;
     RECT  73.081 60.096 73.217 74.616 ;
     RECT  73.081 23.136 73.245 59.112 ;
     RECT  73.037 95.904 73.397 96.504 ;
     RECT  73.109 100.8 73.397 100.824 ;
     RECT  72.904 102.672 73.397 103.512 ;
     RECT  73.397 102.768 73.433 103.512 ;
     RECT  72.904 79.824 73.475 85.704 ;
     RECT  73.217 60.576 73.505 74.616 ;
     RECT  72.904 87.36 73.577 90.072 ;
     RECT  73.037 93.072 73.613 94.872 ;
     RECT  73.397 95.904 73.613 96.312 ;
     RECT  73.475 84.816 73.793 85.704 ;
     RECT  73.793 84.912 74.005 85.704 ;
     RECT  73.245 23.136 74.153 48.696 ;
     RECT  73.613 96.288 74.153 96.312 ;
     RECT  74.153 30.048 74.189 48.696 ;
     RECT  73.613 93.072 74.189 93.096 ;
     RECT  74.189 30.336 74.225 48.696 ;
     RECT  72.904 91.44 74.261 91.464 ;
     RECT  73.245 49.776 74.293 59.112 ;
     RECT  73.505 60.576 74.293 74.088 ;
     RECT  73.577 88.56 74.293 90.072 ;
     RECT  73.577 87.36 74.329 87.528 ;
     RECT  73.043 75.936 74.473 77.496 ;
     RECT  74.329 87.312 74.473 87.528 ;
     RECT  74.473 75.936 74.509 77.544 ;
     RECT  74.225 36.816 74.545 48.696 ;
     RECT  74.473 87.264 74.545 87.528 ;
     RECT  74.293 88.56 74.545 90.6 ;
     RECT  74.293 49.776 74.581 74.088 ;
     RECT  74.689 91.68 74.761 91.704 ;
     RECT  73.613 94.128 74.761 94.872 ;
     RECT  74.581 95.952 74.761 95.976 ;
     RECT  73.433 102.768 74.797 103.272 ;
     RECT  74.293 78.624 74.905 78.648 ;
     RECT  73.475 79.824 74.905 83.352 ;
     RECT  74.761 94.128 75.02 95.976 ;
     RECT  74.005 84.912 75.049 85.752 ;
     RECT  74.905 78.624 75.121 83.352 ;
     RECT  75.049 84.432 75.121 85.752 ;
     RECT  74.153 23.136 75.149 29.064 ;
     RECT  75.149 22.224 75.157 29.064 ;
     RECT  74.225 30.336 75.157 35.736 ;
     RECT  74.581 49.776 75.193 74.712 ;
     RECT  74.509 75.696 75.193 77.544 ;
     RECT  75.157 20.88 75.308 20.904 ;
     RECT  75.157 22.224 75.308 35.736 ;
     RECT  74.545 36.816 75.308 48.792 ;
     RECT  75.193 49.776 75.308 77.544 ;
     RECT  75.121 78.624 75.308 85.752 ;
     RECT  74.545 87.264 75.308 90.6 ;
     RECT  74.761 91.68 75.308 92.568 ;
     RECT  75.02 93.552 75.308 95.976 ;
     RECT  74.629 100.8 75.308 100.824 ;
     RECT  74.797 102.768 75.308 103.32 ;
     RECT  75.308 2.148 75.412 103.32 ;
     RECT  75.412 2.418 75.5 103.32 ;
     RECT  75.409 104.88 75.553 104.904 ;
     RECT  75.5 2.418 75.604 103.422 ;
     RECT  75.604 100.656 75.637 103.422 ;
     RECT  75.553 104.88 75.685 105 ;
     RECT  75.604 30.336 75.731 87.384 ;
     RECT  75.731 30.336 75.773 81.672 ;
     RECT  75.773 30.576 75.809 81.672 ;
     RECT  75.809 75.696 75.845 81.672 ;
     RECT  75.809 30.576 75.917 74.712 ;
     RECT  75.637 100.656 75.917 103.56 ;
     RECT  75.731 82.656 75.923 87.384 ;
     RECT  75.604 88.608 75.923 91.704 ;
     RECT  75.923 87.216 75.964 87.384 ;
     RECT  75.917 30.576 75.989 74.616 ;
     RECT  75.845 75.936 76.061 81.672 ;
     RECT  75.989 36.864 76.097 74.616 ;
     RECT  75.917 100.656 76.205 103.368 ;
     RECT  75.989 30.576 76.277 35.88 ;
     RECT  75.923 88.752 76.457 91.704 ;
     RECT  76.061 76.56 76.493 81.672 ;
     RECT  76.277 30.672 76.529 35.88 ;
     RECT  76.205 100.8 76.595 103.368 ;
     RECT  76.493 76.56 76.673 77.64 ;
     RECT  75.604 92.928 76.817 96.888 ;
     RECT  76.529 30.672 76.853 35.832 ;
     RECT  76.457 91.44 76.885 91.704 ;
     RECT  76.493 78.672 76.889 81.672 ;
     RECT  76.817 92.928 76.924 96.36 ;
     RECT  76.889 81.168 76.94 81.672 ;
     RECT  75.923 82.656 76.94 85.704 ;
     RECT  75.604 23.28 76.957 29.352 ;
     RECT  76.097 36.864 76.957 69.336 ;
     RECT  76.853 30.672 76.961 31.224 ;
     RECT  76.924 92.928 76.993 94.392 ;
     RECT  76.885 91.44 76.997 91.8 ;
     RECT  76.853 32.256 77.033 35.832 ;
     RECT  76.957 23.088 77.101 29.352 ;
     RECT  75.964 87.264 77.137 87.384 ;
     RECT  77.137 87.264 77.173 87.48 ;
     RECT  76.457 88.752 77.173 90.264 ;
     RECT  76.94 81.168 77.209 85.704 ;
     RECT  77.173 87.264 77.209 90.264 ;
     RECT  76.595 102.528 77.413 103.368 ;
     RECT  76.957 36.816 77.497 69.336 ;
     RECT  76.097 70.608 77.497 74.616 ;
     RECT  77.497 36.816 77.569 74.616 ;
     RECT  77.413 102.528 77.653 103.416 ;
     RECT  76.595 100.8 77.701 101.112 ;
     RECT  77.653 102.48 77.701 103.416 ;
     RECT  76.993 92.88 77.713 94.392 ;
     RECT  76.997 91.44 77.821 91.464 ;
     RECT  75.604 20.88 77.857 22.056 ;
     RECT  77.101 23.04 77.893 29.352 ;
     RECT  77.713 92.496 77.893 94.392 ;
     RECT  76.924 95.664 77.893 96.36 ;
     RECT  77.701 100.8 77.893 103.416 ;
     RECT  77.893 97.536 77.929 97.56 ;
     RECT  76.673 76.56 78.001 77.592 ;
     RECT  77.173 19.344 78.008 19.368 ;
     RECT  77.857 20.352 78.008 22.056 ;
     RECT  77.893 23.04 78.008 29.64 ;
     RECT  76.961 30.96 78.008 31.224 ;
     RECT  77.033 32.256 78.008 35.448 ;
     RECT  77.569 36.816 78.008 75.144 ;
     RECT  78.001 76.464 78.008 77.592 ;
     RECT  76.889 78.672 78.008 80.136 ;
     RECT  77.209 81.168 78.008 90.264 ;
     RECT  77.821 91.392 78.008 91.464 ;
     RECT  77.893 92.496 78.008 96.36 ;
     RECT  77.929 97.536 78.008 97.848 ;
     RECT  77.893 100.8 78.008 103.512 ;
     RECT  78.008 2.148 78.112 103.512 ;
     RECT  78.112 2.418 78.304 103.512 ;
     RECT  78.304 100.8 78.509 103.512 ;
     RECT  78.304 18.96 78.833 78.12 ;
     RECT  78.833 21.408 78.905 78.12 ;
     RECT  78.509 100.848 79.139 103.512 ;
     RECT  79.139 101.424 79.141 103.512 ;
     RECT  75.685 104.88 79.141 105.768 ;
     RECT  78.905 21.408 79.229 30.168 ;
     RECT  78.304 79.248 79.297 98.136 ;
     RECT  78.304 99.552 79.297 99.576 ;
     RECT  79.229 29.04 79.409 30.168 ;
     RECT  79.297 79.248 79.477 99.576 ;
     RECT  78.905 31.2 79.625 78.12 ;
     RECT  79.625 77.568 79.657 78.12 ;
     RECT  79.477 79.2 79.657 99.576 ;
     RECT  79.141 101.424 79.811 105.768 ;
     RECT  79.409 29.616 79.981 30.168 ;
     RECT  79.625 31.2 79.981 76.584 ;
     RECT  79.811 101.424 79.985 104.328 ;
     RECT  79.229 21.408 80.017 28.008 ;
     RECT  79.657 77.568 80.125 99.576 ;
     RECT  78.833 18.96 80.161 20.088 ;
     RECT  79.811 105.744 80.291 105.768 ;
     RECT  80.161 18.144 80.305 20.088 ;
     RECT  80.017 21.168 80.305 28.008 ;
     RECT  80.125 77.568 80.449 100.056 ;
     RECT  79.981 29.616 80.533 76.584 ;
     RECT  80.449 77.568 80.629 100.344 ;
     RECT  79.985 101.424 80.629 103.464 ;
     RECT  80.305 18.144 80.708 28.008 ;
     RECT  80.533 29.088 80.708 76.584 ;
     RECT  80.629 77.568 80.708 103.464 ;
     RECT  80.708 2.148 80.812 103.464 ;
     RECT  80.812 2.418 80.953 103.464 ;
     RECT  80.953 2.418 81.004 104.28 ;
     RECT  81.004 76.224 81.101 81.768 ;
     RECT  81.004 21.408 81.137 28.008 ;
     RECT  81.004 96.336 81.155 104.28 ;
     RECT  81.004 29.04 81.181 29.064 ;
     RECT  81.308 105.744 81.413 105.768 ;
     RECT  81.004 30.672 81.497 74.664 ;
     RECT  81.413 104.88 81.497 105.768 ;
     RECT  81.004 17.088 81.532 20.088 ;
     RECT  81.004 86.592 81.635 95.208 ;
     RECT  81.497 104.928 81.635 105.768 ;
     RECT  81.532 18.144 81.713 20.088 ;
     RECT  81.155 96.336 81.821 103.32 ;
     RECT  81.497 30.672 81.857 74.376 ;
     RECT  81.821 96.336 81.929 103.08 ;
     RECT  81.635 105.744 81.971 105.768 ;
     RECT  81.713 18.192 81.997 20.088 ;
     RECT  81.004 82.752 81.997 85.224 ;
     RECT  81.635 86.592 81.997 91.8 ;
     RECT  81.101 76.224 82.213 81.672 ;
     RECT  81.137 21.744 82.249 28.008 ;
     RECT  81.635 92.928 82.429 95.208 ;
     RECT  81.929 96.336 82.429 102.792 ;
     RECT  82.249 21.744 82.661 28.2 ;
     RECT  82.213 75.936 82.717 81.672 ;
     RECT  82.717 75.84 82.825 81.672 ;
     RECT  82.661 21.696 82.885 28.2 ;
     RECT  82.825 75.744 82.933 81.672 ;
     RECT  82.429 92.928 82.969 102.792 ;
     RECT  82.969 92.832 82.981 102.792 ;
     RECT  82.933 75.456 83.036 81.672 ;
     RECT  81.997 18.192 83.041 20.328 ;
     RECT  82.885 21.696 83.041 29.064 ;
     RECT  81.997 82.752 83.077 91.8 ;
     RECT  82.981 92.832 83.077 102.936 ;
     RECT  83.036 75.408 83.113 81.672 ;
     RECT  83.077 82.752 83.113 102.936 ;
     RECT  81.532 17.088 83.365 17.112 ;
     RECT  83.365 16.56 83.408 17.112 ;
     RECT  83.041 18.192 83.408 29.064 ;
     RECT  81.997 30.192 83.408 30.216 ;
     RECT  81.857 31.2 83.408 74.376 ;
     RECT  83.113 75.408 83.408 102.936 ;
     RECT  83.408 2.148 83.512 103.152 ;
     RECT  83.512 2.418 83.6 103.152 ;
     RECT  83.6 2.418 83.704 103.422 ;
     RECT  83.704 18.24 83.765 19.32 ;
     RECT  83.704 15.936 83.981 17.112 ;
     RECT  83.704 21.696 84.197 100.872 ;
     RECT  84.197 21.744 84.233 100.872 ;
     RECT  84.233 21.744 84.371 100.344 ;
     RECT  84.371 21.744 84.449 100.104 ;
     RECT  83.981 15.936 84.769 16.872 ;
     RECT  83.765 18.816 84.805 19.32 ;
     RECT  84.449 21.744 84.947 98.712 ;
     RECT  84.947 21.744 85.025 29.16 ;
     RECT  84.947 30.336 85.061 98.712 ;
     RECT  84.769 15.84 85.065 16.872 ;
     RECT  85.065 15.024 85.453 16.872 ;
     RECT  84.805 18.816 85.772 19.368 ;
     RECT  85.025 21.744 85.813 28.008 ;
     RECT  85.453 15.024 85.849 17.208 ;
     RECT  85.772 18.816 85.849 19.656 ;
     RECT  85.061 75.84 86.101 87.96 ;
     RECT  85.061 88.992 86.101 98.712 ;
     RECT  85.849 15.024 86.108 19.656 ;
     RECT  85.813 20.832 86.108 28.008 ;
     RECT  85.025 29.04 86.108 29.16 ;
     RECT  85.061 30.336 86.108 74.232 ;
     RECT  86.101 75.84 86.108 98.712 ;
     RECT  84.449 100.08 86.108 100.104 ;
     RECT  83.704 102.192 86.108 102.792 ;
     RECT  86.108 2.148 86.212 103.152 ;
     RECT  86.212 2.418 86.3 103.152 ;
     RECT  86.3 2.418 86.404 103.422 ;
     RECT  86.404 15.024 86.465 15.864 ;
     RECT  86.465 15.504 86.573 15.864 ;
     RECT  86.404 80.064 86.861 96.504 ;
     RECT  86.404 101.328 87.113 102.216 ;
     RECT  86.404 16.848 87.257 19.368 ;
     RECT  86.861 89.52 87.293 96.504 ;
     RECT  86.404 78.384 87.433 78.792 ;
     RECT  86.861 80.064 87.433 88.392 ;
     RECT  86.573 15.552 87.469 15.864 ;
     RECT  87.257 16.848 87.469 17.496 ;
     RECT  86.404 97.488 87.617 100.248 ;
     RECT  87.293 92.352 87.653 96.504 ;
     RECT  87.469 15.552 87.685 17.496 ;
     RECT  86.404 20.832 87.797 77.208 ;
     RECT  87.257 18.72 88.045 19.368 ;
     RECT  87.797 20.832 88.045 29.496 ;
     RECT  87.685 15.504 88.189 17.496 ;
     RECT  87.797 31.152 88.189 77.208 ;
     RECT  87.433 78.384 88.189 88.392 ;
     RECT  87.293 89.52 88.297 91.176 ;
     RECT  88.297 89.472 88.333 91.176 ;
     RECT  87.653 92.352 88.333 95.208 ;
     RECT  88.045 18.72 88.357 29.496 ;
     RECT  88.189 31.152 88.405 88.392 ;
     RECT  88.405 31.152 88.765 88.488 ;
     RECT  87.397 14.4 88.808 14.424 ;
     RECT  88.189 15.456 88.808 17.496 ;
     RECT  88.357 18.624 88.808 29.496 ;
     RECT  88.765 30.672 88.808 88.488 ;
     RECT  88.333 89.472 88.808 95.208 ;
     RECT  87.653 96.48 88.808 96.504 ;
     RECT  87.617 97.68 88.808 99.768 ;
     RECT  87.113 101.328 88.808 101.352 ;
     RECT  88.808 2.148 88.912 103.152 ;
     RECT  88.912 2.418 89 103.152 ;
     RECT  89 2.418 89.104 103.422 ;
     RECT  89.104 13.632 89.219 16.008 ;
     RECT  89.104 77.952 89.309 80.664 ;
     RECT  89.219 13.632 89.507 14.424 ;
     RECT  89.219 15.456 89.705 16.008 ;
     RECT  89.104 17.472 89.705 19.368 ;
     RECT  89.507 13.632 89.741 13.656 ;
     RECT  89.705 18.24 89.813 19.368 ;
     RECT  89.104 89.808 89.813 90.648 ;
     RECT  89.104 21.168 89.849 76.2 ;
     RECT  89.104 91.728 89.957 101.064 ;
     RECT  89.957 91.728 90.124 98.904 ;
     RECT  89.104 84.816 90.133 84.84 ;
     RECT  89.104 86.016 90.133 88.776 ;
     RECT  89.813 89.808 90.133 90.072 ;
     RECT  89.813 18.72 90.137 19.368 ;
     RECT  89.957 100.272 90.209 101.064 ;
     RECT  89.309 78.528 90.325 80.664 ;
     RECT  89.104 81.744 90.325 83.736 ;
     RECT  90.325 78.048 90.332 83.736 ;
     RECT  90.133 84.816 90.332 88.776 ;
     RECT  90.137 18.72 90.389 19.08 ;
     RECT  89.849 21.792 90.425 76.2 ;
     RECT  90.332 78.048 90.493 88.776 ;
     RECT  90.124 91.728 90.493 96.552 ;
     RECT  90.493 91.056 90.533 96.552 ;
     RECT  90.493 77.568 90.613 88.776 ;
     RECT  90.133 89.76 90.613 90.072 ;
     RECT  90.425 30.72 90.673 76.2 ;
     RECT  89.705 15.456 90.925 15.816 ;
     RECT  90.673 30.72 90.997 76.248 ;
     RECT  90.613 77.568 90.997 90.072 ;
     RECT  90.425 21.792 91.213 29.688 ;
     RECT  90.313 20.16 91.285 20.184 ;
     RECT  91.213 21.36 91.285 29.688 ;
     RECT  90.124 97.872 91.393 98.904 ;
     RECT  90.997 30.72 91.465 90.072 ;
     RECT  90.925 14.736 91.508 15.816 ;
     RECT  90.817 16.896 91.508 16.92 ;
     RECT  90.389 18.768 91.508 19.08 ;
     RECT  91.285 20.16 91.508 29.688 ;
     RECT  91.465 30.672 91.508 90.072 ;
     RECT  90.533 91.056 91.508 96.504 ;
     RECT  91.393 97.584 91.508 98.904 ;
     RECT  90.209 100.848 91.508 101.064 ;
     RECT  91.508 2.148 91.612 103.152 ;
     RECT  91.612 2.418 91.7 103.152 ;
     RECT  91.7 2.418 91.804 103.422 ;
     RECT  91.804 29.04 91.865 29.352 ;
     RECT  91.804 30.336 91.865 43.128 ;
     RECT  91.804 88.224 91.955 91.08 ;
     RECT  91.804 44.16 91.973 62.568 ;
     RECT  91.804 92.064 91.973 96.216 ;
     RECT  91.973 44.64 92.189 62.568 ;
     RECT  91.804 63.552 92.189 84.36 ;
     RECT  91.804 18.24 92.225 20.616 ;
     RECT  91.973 94.032 92.261 96.216 ;
     RECT  91.865 29.28 92.333 29.352 ;
     RECT  92.189 77.28 92.333 83.064 ;
     RECT  91.865 30.336 92.339 39.864 ;
     RECT  91.804 14.352 92.369 16.92 ;
     RECT  92.225 18.24 92.369 20.568 ;
     RECT  92.369 15.552 92.441 16.92 ;
     RECT  92.333 77.52 92.441 83.064 ;
     RECT  92.441 15.552 92.513 16.536 ;
     RECT  91.973 92.064 92.621 93.048 ;
     RECT  92.261 94.032 92.701 95.832 ;
     RECT  92.621 92.064 92.716 92.952 ;
     RECT  92.701 94.032 92.716 95.784 ;
     RECT  92.189 45.456 92.729 62.568 ;
     RECT  92.189 84.144 92.797 84.36 ;
     RECT  91.804 85.92 92.797 87.144 ;
     RECT  92.729 45.696 92.801 62.568 ;
     RECT  92.441 77.568 92.801 83.064 ;
     RECT  92.333 29.28 92.873 29.304 ;
     RECT  92.801 45.696 92.906 49.56 ;
     RECT  92.797 84.144 92.941 87.144 ;
     RECT  91.955 88.32 92.941 91.08 ;
     RECT  92.941 84.144 93.053 91.08 ;
     RECT  93.053 84.144 93.059 90.6 ;
     RECT  92.513 16.416 93.089 16.536 ;
     RECT  92.801 50.592 93.089 62.568 ;
     RECT  93.059 85.968 93.089 88.392 ;
     RECT  93.059 89.76 93.089 90.6 ;
     RECT  93.089 51.312 93.125 59.592 ;
     RECT  91.865 40.896 93.197 43.128 ;
     RECT  93.125 51.312 93.197 59.016 ;
     RECT  93.059 84.144 93.197 84.936 ;
     RECT  92.369 18.24 93.301 19.08 ;
     RECT  93.301 17.616 93.373 19.08 ;
     RECT  93.373 17.616 93.409 19.176 ;
     RECT  92.189 63.552 93.481 76.248 ;
     RECT  92.801 77.664 93.517 83.064 ;
     RECT  93.197 84.144 93.517 84.168 ;
     RECT  92.369 20.544 93.553 20.568 ;
     RECT  91.804 21.696 93.553 28.008 ;
     RECT  91.804 97.584 93.553 99.192 ;
     RECT  92.716 95.76 93.788 95.784 ;
     RECT  92.716 92.928 93.829 92.952 ;
     RECT  92.716 94.032 93.829 94.68 ;
     RECT  93.481 63.552 93.841 76.488 ;
     RECT  92.339 30.432 93.985 39.864 ;
     RECT  93.089 16.512 94.021 16.536 ;
     RECT  93.409 17.616 94.021 19.368 ;
     RECT  93.517 77.664 94.021 84.168 ;
     RECT  93.089 85.968 94.028 87.96 ;
     RECT  93.829 92.928 94.093 94.68 ;
     RECT  93.788 95.712 94.093 95.784 ;
     RECT  94.093 92.928 94.129 95.784 ;
     RECT  93.553 97.008 94.129 99.192 ;
     RECT  92.369 14.352 94.208 14.376 ;
     RECT  94.021 16.512 94.208 19.368 ;
     RECT  93.553 20.544 94.208 28.008 ;
     RECT  93.661 29.04 94.208 29.064 ;
     RECT  93.985 30.432 94.208 40.056 ;
     RECT  93.197 41.136 94.208 43.128 ;
     RECT  92.906 45.696 94.208 49.512 ;
     RECT  93.197 51.36 94.208 59.016 ;
     RECT  93.089 60.672 94.208 62.568 ;
     RECT  93.841 63.552 94.208 76.584 ;
     RECT  94.021 77.616 94.208 84.168 ;
     RECT  94.028 85.824 94.208 87.96 ;
     RECT  93.089 89.76 94.208 89.784 ;
     RECT  94.129 92.928 94.208 99.192 ;
     RECT  94.208 2.148 94.312 103.152 ;
     RECT  94.312 2.418 94.4 103.152 ;
     RECT  94.4 2.418 94.504 103.422 ;
     RECT  94.504 17.04 94.565 17.64 ;
     RECT  94.504 18.768 94.601 40.056 ;
     RECT  94.504 77.616 94.637 84.36 ;
     RECT  94.504 93.12 94.643 94.056 ;
     RECT  94.601 18.768 94.673 19.368 ;
     RECT  94.637 77.856 94.673 84.36 ;
     RECT  94.601 20.544 94.745 40.056 ;
     RECT  94.504 72.912 94.745 74.376 ;
     RECT  94.504 45.744 94.781 71.736 ;
     RECT  94.745 20.544 94.817 39.912 ;
     RECT  94.673 82.992 94.883 84.36 ;
     RECT  94.504 15.84 94.889 15.864 ;
     RECT  94.504 85.488 95.075 87.96 ;
     RECT  94.504 95.04 95.075 97.032 ;
     RECT  94.817 20.544 95.141 32.904 ;
     RECT  94.883 82.992 95.171 83.832 ;
     RECT  94.504 41.136 95.213 44.76 ;
     RECT  95.075 95.376 95.213 97.032 ;
     RECT  94.504 75.648 95.277 76.248 ;
     RECT  94.673 18.768 95.285 18.84 ;
     RECT  95.075 87.84 95.285 87.96 ;
     RECT  95.141 20.544 95.321 21 ;
     RECT  95.213 96.672 95.357 97.032 ;
     RECT  95.141 21.984 95.393 32.904 ;
     RECT  94.781 45.744 95.459 63.624 ;
     RECT  94.781 64.944 95.465 71.736 ;
     RECT  94.504 88.944 95.497 91.464 ;
     RECT  95.171 82.992 95.501 83.688 ;
     RECT  95.075 85.488 95.533 86.856 ;
     RECT  95.459 45.744 95.557 60.696 ;
     RECT  94.643 93.12 95.641 93.768 ;
     RECT  95.285 18.768 95.645 18.792 ;
     RECT  94.817 33.888 95.645 39.912 ;
     RECT  94.673 77.856 95.681 81.912 ;
     RECT  95.285 87.936 95.701 87.96 ;
     RECT  95.497 88.944 95.701 92.136 ;
     RECT  95.681 78.624 95.713 81.912 ;
     RECT  95.557 45.168 95.717 60.696 ;
     RECT  95.701 87.936 95.747 92.136 ;
     RECT  95.747 90 95.749 92.136 ;
     RECT  95.641 93.12 95.749 93.912 ;
     RECT  95.747 88.752 95.753 88.968 ;
     RECT  95.465 64.944 95.785 70.68 ;
     RECT  95.708 77.472 95.795 77.496 ;
     RECT  95.277 75.648 95.825 75.768 ;
     RECT  95.533 85.44 95.825 86.856 ;
     RECT  95.749 90 95.825 93.912 ;
     RECT  95.393 21.984 95.861 31.224 ;
     RECT  95.645 33.888 95.933 39.864 ;
     RECT  95.213 41.136 95.933 44.184 ;
     RECT  95.717 45.552 95.933 60.696 ;
     RECT  95.465 71.712 95.933 71.736 ;
     RECT  95.357 97.008 95.933 97.032 ;
     RECT  94.745 73.344 96.037 74.376 ;
     RECT  95.459 61.68 96.073 63.624 ;
     RECT  95.861 21.984 96.253 28.728 ;
     RECT  95.501 83.04 96.277 83.688 ;
     RECT  95.321 20.544 96.361 20.568 ;
     RECT  96.253 21.648 96.361 28.728 ;
     RECT  95.933 36.864 96.613 39.864 ;
     RECT  95.393 32.256 96.649 32.904 ;
     RECT  95.933 33.888 96.649 35.544 ;
     RECT  95.861 29.76 96.685 31.224 ;
     RECT  96.649 32.256 96.685 35.544 ;
     RECT  96.613 36.864 96.685 40.056 ;
     RECT  95.825 92.688 96.685 93.912 ;
     RECT  95.753 88.752 96.793 88.92 ;
     RECT  95.825 90 96.793 91.704 ;
     RECT  95.213 95.376 96.793 95.4 ;
     RECT  95.933 50.784 96.829 60.696 ;
     RECT  96.073 61.68 96.829 63.864 ;
     RECT  95.933 45.552 96.901 49.512 ;
     RECT  96.829 50.784 96.901 63.864 ;
     RECT  95.825 85.44 96.901 85.512 ;
     RECT  94.565 17.04 96.908 17.064 ;
     RECT  96.361 20.544 96.908 28.728 ;
     RECT  96.685 29.76 96.908 35.544 ;
     RECT  96.685 36.864 96.908 40.104 ;
     RECT  95.933 41.136 96.908 43.656 ;
     RECT  96.901 45.552 96.908 63.864 ;
     RECT  95.785 64.896 96.908 70.68 ;
     RECT  96.037 72.96 96.908 74.376 ;
     RECT  95.825 75.648 96.908 75.672 ;
     RECT  95.857 76.752 96.908 76.968 ;
     RECT  95.713 78.624 96.908 82.008 ;
     RECT  96.277 83.04 96.908 84.264 ;
     RECT  96.901 85.44 96.908 85.704 ;
     RECT  95.825 86.832 96.908 86.856 ;
     RECT  96.793 88.752 96.908 91.704 ;
     RECT  96.685 92.688 96.908 94.056 ;
     RECT  96.793 95.136 96.908 95.4 ;
     RECT  96.908 2.148 97.012 103.152 ;
     RECT  97.012 2.418 97.1 103.152 ;
     RECT  97.1 2.418 97.204 103.422 ;
     RECT  97.204 20.592 97.301 20.712 ;
     RECT  97.204 21.696 97.301 40.056 ;
     RECT  97.204 91.056 97.301 93.384 ;
     RECT  97.204 69.264 97.337 70.008 ;
     RECT  97.204 45.552 97.373 57.432 ;
     RECT  97.337 69.264 97.373 69.576 ;
     RECT  97.204 87.888 97.373 90.024 ;
     RECT  97.204 94.464 97.373 95.4 ;
     RECT  97.204 72.288 97.481 74.184 ;
     RECT  97.373 53.808 97.517 57.432 ;
     RECT  97.373 89.472 97.517 90.024 ;
     RECT  97.517 89.52 97.589 90.024 ;
     RECT  97.373 45.552 97.661 52.824 ;
     RECT  97.589 89.52 97.697 89.688 ;
     RECT  97.661 45.552 97.913 50.664 ;
     RECT  97.517 53.808 97.949 57.048 ;
     RECT  97.301 21.696 98.051 38.712 ;
     RECT  97.913 49.584 98.057 50.664 ;
     RECT  97.373 87.888 98.165 87.912 ;
     RECT  97.481 72.288 98.201 73.896 ;
     RECT  97.301 20.592 98.237 20.616 ;
     RECT  98.051 21.696 98.237 37.464 ;
     RECT  97.204 58.512 98.269 59.304 ;
     RECT  97.204 60.384 98.269 63.624 ;
     RECT  97.301 91.056 98.291 92.328 ;
     RECT  98.291 92.304 98.332 92.328 ;
     RECT  98.201 72.288 98.341 72.408 ;
     RECT  97.204 80.88 98.377 80.904 ;
     RECT  97.204 81.984 98.377 84.264 ;
     RECT  98.237 21.696 98.381 22.248 ;
     RECT  97.301 93.36 98.381 93.384 ;
     RECT  97.373 94.464 98.381 94.488 ;
     RECT  98.269 58.512 98.389 63.624 ;
     RECT  97.204 64.896 98.389 67.896 ;
     RECT  97.204 78.624 98.405 79.8 ;
     RECT  97.913 45.552 98.413 48.504 ;
     RECT  98.389 58.512 98.413 67.896 ;
     RECT  97.373 69.264 98.413 69.384 ;
     RECT  97.204 85.68 98.413 86.856 ;
     RECT  98.237 23.472 98.417 37.464 ;
     RECT  98.413 45.168 98.417 48.504 ;
     RECT  97.204 41.136 98.449 43.56 ;
     RECT  98.381 22.032 98.453 22.248 ;
     RECT  98.413 58.512 98.453 69.384 ;
     RECT  97.697 89.568 98.453 89.688 ;
     RECT  98.341 70.8 98.483 72.408 ;
     RECT  98.377 80.88 98.485 84.264 ;
     RECT  98.405 78.096 98.489 79.8 ;
     RECT  98.485 80.832 98.489 84.264 ;
     RECT  97.661 51.744 98.521 52.824 ;
     RECT  98.449 41.136 98.557 43.848 ;
     RECT  98.417 45.168 98.557 48.264 ;
     RECT  97.949 54.624 98.593 57.048 ;
     RECT  98.201 73.536 98.629 73.896 ;
     RECT  98.489 78.912 98.629 79.8 ;
     RECT  98.489 80.832 98.629 83.064 ;
     RECT  98.417 23.472 98.633 30.168 ;
     RECT  98.413 85.488 98.633 86.856 ;
     RECT  98.593 54.624 98.665 57.528 ;
     RECT  98.453 58.512 98.665 69.288 ;
     RECT  98.633 86.832 99.02 86.856 ;
     RECT  98.629 73.536 99.097 74.376 ;
     RECT  98.521 51.744 99.133 53.016 ;
     RECT  98.483 70.8 99.205 71.736 ;
     RECT  98.489 84.24 99.277 84.264 ;
     RECT  98.633 85.488 99.277 85.656 ;
     RECT  97.301 39.792 99.313 40.056 ;
     RECT  99.097 73.536 99.313 74.664 ;
     RECT  97.204 75.84 99.313 76.824 ;
     RECT  98.449 20.064 99.608 20.088 ;
     RECT  98.453 22.224 99.608 22.248 ;
     RECT  98.633 23.472 99.608 28.44 ;
     RECT  98.633 29.568 99.608 30.168 ;
     RECT  98.417 31.2 99.608 37.464 ;
     RECT  99.313 39.504 99.608 40.056 ;
     RECT  98.557 41.136 99.608 48.264 ;
     RECT  98.057 50.256 99.608 50.664 ;
     RECT  99.133 51.744 99.608 53.352 ;
     RECT  98.665 54.624 99.608 69.288 ;
     RECT  99.205 70.272 99.608 71.736 ;
     RECT  99.313 73.536 99.608 76.824 ;
     RECT  98.629 78.912 99.608 83.064 ;
     RECT  99.277 84.24 99.608 85.656 ;
     RECT  99.02 86.832 99.608 87.528 ;
     RECT  98.453 89.664 99.608 89.688 ;
     RECT  98.291 91.056 99.608 91.08 ;
     RECT  99.608 2.148 99.712 103.152 ;
     RECT  99.712 2.418 99.8 103.152 ;
     RECT  99.8 2.418 99.904 103.422 ;
     RECT  99.904 56.064 99.929 56.088 ;
     RECT  99.904 35.52 99.965 36.936 ;
     RECT  99.904 21.456 100.001 24.072 ;
     RECT  99.904 33.936 100.001 34.488 ;
     RECT  99.904 31.2 100.037 32.52 ;
     RECT  99.904 43.536 100.037 46.728 ;
     RECT  100.001 33.936 100.217 34.104 ;
     RECT  99.904 75.888 100.253 75.96 ;
     RECT  99.965 35.568 100.289 36.936 ;
     RECT  99.904 73.584 100.361 74.664 ;
     RECT  100.001 21.456 100.397 22.776 ;
     RECT  99.904 61.92 100.397 63.912 ;
     RECT  99.904 83.04 100.397 83.064 ;
     RECT  99.904 79.776 100.433 79.8 ;
     RECT  99.904 47.904 100.505 48.216 ;
     RECT  100.505 47.952 100.685 48.216 ;
     RECT  99.904 67.44 100.685 70.152 ;
     RECT  100.685 47.952 100.793 47.976 ;
     RECT  100.397 21.456 100.897 22.152 ;
     RECT  99.904 26.592 100.897 27.144 ;
     RECT  99.904 28.224 100.897 30.168 ;
     RECT  100.397 63.12 100.897 63.912 ;
     RECT  100.685 67.44 100.897 67.464 ;
     RECT  100.685 68.496 100.897 70.152 ;
     RECT  100.397 61.92 100.933 62.088 ;
     RECT  100.037 43.536 101.005 43.56 ;
     RECT  100.361 73.968 101.009 74.664 ;
     RECT  99.904 25.536 101.437 25.56 ;
     RECT  100.897 26.592 101.437 30.168 ;
     RECT  99.904 51.984 101.437 53.352 ;
     RECT  100.969 54.576 101.437 54.6 ;
     RECT  99.904 65.424 101.437 65.448 ;
     RECT  100.897 66.672 101.437 67.464 ;
     RECT  100.897 20.592 101.473 22.152 ;
     RECT  100.001 24.048 101.473 24.072 ;
     RECT  101.437 25.536 101.473 30.168 ;
     RECT  100.037 31.728 101.473 32.52 ;
     RECT  100.217 34.032 101.473 34.104 ;
     RECT  99.904 41.376 101.473 42.504 ;
     RECT  100.037 44.784 101.473 46.728 ;
     RECT  99.904 49.392 101.473 49.416 ;
     RECT  101.437 51.984 101.473 54.6 ;
     RECT  99.904 58.992 101.473 59.016 ;
     RECT  100.933 61.68 101.473 62.088 ;
     RECT  100.897 63.12 101.473 64.392 ;
     RECT  101.437 65.424 101.473 67.464 ;
     RECT  100.897 68.496 101.473 70.536 ;
     RECT  99.904 71.664 101.473 71.688 ;
     RECT  101.473 51.984 101.509 56.904 ;
     RECT  101.473 68.496 101.509 71.688 ;
     RECT  101.473 20.4 101.545 22.152 ;
     RECT  101.509 51.984 101.545 57.096 ;
     RECT  101.473 24.048 101.689 34.44 ;
     RECT  100.289 35.568 101.689 36.744 ;
     RECT  101.509 68.496 101.689 72.648 ;
     RECT  101.009 73.968 101.689 74.376 ;
     RECT  101.689 24.048 101.941 36.744 ;
     RECT  101.473 49.008 101.977 50.568 ;
     RECT  101.545 51.984 101.977 57.288 ;
     RECT  101.473 63.12 101.977 67.464 ;
     RECT  101.689 68.496 101.977 74.376 ;
     RECT  101.905 84.144 101.977 84.168 ;
     RECT  101.545 20.4 102.013 22.44 ;
     RECT  101.941 24.048 102.013 37.32 ;
     RECT  101.473 40.944 102.013 42.504 ;
     RECT  101.005 43.536 102.013 43.8 ;
     RECT  101.473 44.784 102.013 47.88 ;
     RECT  101.977 49.008 102.013 57.288 ;
     RECT  101.473 58.608 102.013 59.016 ;
     RECT  101.473 60.432 102.013 62.088 ;
     RECT  101.977 63.12 102.013 74.376 ;
     RECT  100.253 75.888 102.013 75.912 ;
     RECT  101.977 83.664 102.013 84.168 ;
     RECT  101.653 86.064 102.013 86.088 ;
     RECT  102.013 43.536 102.049 57.288 ;
     RECT  102.013 58.416 102.049 59.016 ;
     RECT  102.013 83.664 102.337 86.088 ;
     RECT  102.013 60.144 102.481 74.376 ;
     RECT  102.013 75.888 102.481 76.68 ;
     RECT  102.337 83.664 102.481 86.376 ;
     RECT  102.013 40.176 102.517 42.504 ;
     RECT  102.049 43.536 102.517 59.016 ;
     RECT  102.481 83.664 102.517 86.472 ;
     RECT  102.013 23.952 102.553 37.32 ;
     RECT  102.517 40.176 102.553 59.016 ;
     RECT  102.481 60.144 102.553 76.68 ;
     RECT  102.013 20.208 102.589 22.728 ;
     RECT  102.553 23.856 102.589 37.32 ;
     RECT  102.013 39.12 102.589 39.144 ;
     RECT  102.553 40.176 102.589 76.68 ;
     RECT  102.589 19.92 103.165 37.416 ;
     RECT  103.165 19.92 104.028 37.512 ;
     RECT  102.589 39.12 104.028 76.68 ;
     RECT  102.517 83.664 104.028 86.664 ;
     RECT  104.028 30.144 104.069 30.168 ;
    LAYER M5 ;
     RECT  2.4 2.137 2.52 2.151 ;
     RECT  5.1 2.137 5.22 2.151 ;
     RECT  7.8 2.137 7.92 2.151 ;
     RECT  10.5 2.137 10.62 2.151 ;
     RECT  13.2 2.137 13.32 2.151 ;
     RECT  15.9 2.137 16.02 2.151 ;
     RECT  18.6 2.137 18.72 2.151 ;
     RECT  21.3 2.137 21.42 2.151 ;
     RECT  24 2.137 24.12 2.151 ;
     RECT  26.7 2.137 26.82 2.151 ;
     RECT  29.4 2.137 29.52 2.151 ;
     RECT  32.1 2.137 32.22 2.151 ;
     RECT  34.8 2.137 34.92 2.151 ;
     RECT  37.5 2.137 37.62 2.151 ;
     RECT  40.2 2.137 40.32 2.151 ;
     RECT  42.9 2.137 43.02 2.151 ;
     RECT  45.6 2.137 45.72 2.151 ;
     RECT  48.3 2.137 48.42 2.151 ;
     RECT  51 2.137 51.12 2.151 ;
     RECT  53.7 2.137 53.82 2.151 ;
     RECT  56.4 2.137 56.52 2.151 ;
     RECT  59.1 2.137 59.22 2.151 ;
     RECT  61.8 2.137 61.92 2.151 ;
     RECT  64.5 2.137 64.62 2.151 ;
     RECT  67.2 2.137 67.32 2.151 ;
     RECT  69.9 2.137 70.02 2.151 ;
     RECT  72.6 2.137 72.72 2.151 ;
     RECT  75.3 2.137 75.42 2.151 ;
     RECT  78 2.137 78.12 2.151 ;
     RECT  80.7 2.137 80.82 2.151 ;
     RECT  83.4 2.137 83.52 2.151 ;
     RECT  86.1 2.137 86.22 2.151 ;
     RECT  88.8 2.137 88.92 2.151 ;
     RECT  91.5 2.137 91.62 2.151 ;
     RECT  94.2 2.137 94.32 2.151 ;
     RECT  96.9 2.137 97.02 2.151 ;
     RECT  99.6 2.137 99.72 2.151 ;
     RECT  88.8 2.151 89.112 13.621 ;
     RECT  88.8 13.621 89.496 14.435 ;
     RECT  91.5 2.151 91.812 14.725 ;
     RECT  87.408 14.389 87.432 15.683 ;
     RECT  88.8 14.435 89.208 16.019 ;
     RECT  85.104 15.013 85.128 16.259 ;
     RECT  88.8 16.019 89.112 16.501 ;
     RECT  94.2 2.151 94.512 16.501 ;
     RECT  91.5 14.725 92.136 16.931 ;
     RECT  80.7 2.151 81.012 17.461 ;
     RECT  80.7 17.461 81.48 18.133 ;
     RECT  88.368 16.501 89.112 18.757 ;
     RECT  86.1 2.151 86.412 18.853 ;
     RECT  80.7 18.133 81.672 18.899 ;
     RECT  78 2.151 78.312 18.949 ;
     RECT  86.1 18.853 86.616 19.235 ;
     RECT  93.744 16.501 94.512 19.237 ;
     RECT  78 18.949 78.6 19.333 ;
     RECT  88.224 18.757 89.112 19.427 ;
     RECT  86.1 19.235 86.412 19.621 ;
     RECT  83.4 2.151 83.712 20.341 ;
     RECT  85.824 19.621 86.412 20.867 ;
     RECT  75.3 2.151 75.612 20.869 ;
     RECT  88.272 19.427 89.112 21.541 ;
     RECT  87.744 21.541 89.112 21.587 ;
     RECT  77.184 19.333 78.6 21.683 ;
     RECT  93.696 19.237 94.512 21.683 ;
     RECT  91.5 16.931 91.812 21.685 ;
     RECT  83.232 20.341 83.712 21.731 ;
     RECT  91.5 21.685 91.944 21.781 ;
     RECT  86.1 20.867 86.412 22.021 ;
     RECT  67.2 2.151 67.512 22.117 ;
     RECT  61.8 2.151 62.112 22.165 ;
     RECT  75.168 20.869 75.612 22.259 ;
     RECT  87.744 21.587 87.768 22.259 ;
     RECT  94.08 21.683 94.512 22.259 ;
     RECT  59.1 2.151 59.412 22.741 ;
     RECT  96.9 2.151 97.212 22.741 ;
     RECT  90.576 21.781 91.944 22.787 ;
     RECT  67.2 22.117 68.232 23.123 ;
     RECT  80.7 18.899 81.144 23.125 ;
     RECT  61.8 22.165 62.232 23.171 ;
     RECT  80.7 23.125 81.48 23.315 ;
     RECT  61.8 23.171 62.112 23.317 ;
     RECT  85.728 22.021 86.412 23.363 ;
     RECT  90.576 22.787 91.812 23.411 ;
     RECT  72.6 2.151 72.912 23.509 ;
     RECT  96.9 22.741 97.752 23.557 ;
     RECT  56.4 2.151 56.712 23.797 ;
     RECT  94.2 22.259 94.512 23.797 ;
     RECT  67.2 23.123 67.512 23.893 ;
     RECT  80.7 23.315 81.144 23.941 ;
     RECT  72.6 23.509 73.368 24.035 ;
     RECT  59.1 22.741 59.88 24.083 ;
     RECT  93.216 23.797 94.512 24.277 ;
     RECT  61.392 23.317 62.112 24.373 ;
     RECT  88.8 21.587 89.112 24.373 ;
     RECT  96.9 23.557 97.848 24.469 ;
     RECT  66.672 23.893 67.512 24.563 ;
     RECT  61.344 24.373 62.664 24.899 ;
     RECT  93.216 24.277 95.16 25.043 ;
     RECT  48.3 2.151 48.612 25.045 ;
     RECT  67.2 24.563 67.512 25.045 ;
     RECT  69.9 2.151 70.212 25.045 ;
     RECT  86.1 23.363 86.412 25.045 ;
     RECT  56.4 23.797 57.048 25.139 ;
     RECT  75.3 22.259 75.612 25.189 ;
     RECT  61.344 24.899 62.112 25.237 ;
     RECT  93.216 25.043 94.512 25.331 ;
     RECT  75.3 25.189 75.816 25.523 ;
     RECT  86.1 25.045 86.712 25.573 ;
     RECT  86.1 25.573 86.952 25.621 ;
     RECT  51 2.151 51.312 25.669 ;
     RECT  69.9 25.045 71.16 25.715 ;
     RECT  75.3 25.523 75.72 25.765 ;
     RECT  53.7 2.151 54.012 25.813 ;
     RECT  88.8 24.373 89.208 26.149 ;
     RECT  64.5 2.151 64.812 26.197 ;
     RECT  80.352 23.941 81.144 26.243 ;
     RECT  86.1 25.621 87.192 26.291 ;
     RECT  88.704 26.149 89.208 26.387 ;
     RECT  77.184 21.683 78.312 26.435 ;
     RECT  53.424 25.813 54.012 26.627 ;
     RECT  86.1 26.291 86.952 26.771 ;
     RECT  51 25.669 51.912 26.819 ;
     RECT  72.6 24.035 72.912 26.821 ;
     RECT  96.9 24.469 98.184 27.061 ;
     RECT  74.496 25.765 75.72 27.107 ;
     RECT  80.592 26.243 81.144 27.107 ;
     RECT  56.4 25.139 56.712 27.157 ;
     RECT  56.4 27.157 56.856 27.205 ;
     RECT  63.744 26.197 64.812 27.299 ;
     RECT  75.3 27.107 75.72 27.395 ;
     RECT  90.432 25.957 90.456 27.395 ;
     RECT  64.5 27.299 64.812 27.637 ;
     RECT  67.2 25.045 68.328 27.637 ;
     RECT  60.576 25.237 62.112 27.781 ;
     RECT  91.5 23.411 91.812 27.877 ;
     RECT  56.4 27.205 57.768 27.923 ;
     RECT  96.192 27.061 98.184 28.163 ;
     RECT  88.704 26.387 89.112 28.213 ;
     RECT  86.1 26.771 86.412 28.405 ;
     RECT  88.608 28.213 89.112 28.453 ;
     RECT  64.5 27.637 65.592 28.499 ;
     RECT  67.2 27.637 68.616 28.499 ;
     RECT  72.48 26.821 72.912 28.739 ;
     RECT  60.384 27.781 62.112 28.933 ;
     RECT  75.3 27.395 75.612 28.933 ;
     RECT  60.384 28.933 62.76 28.979 ;
     RECT  83.4 21.731 83.712 29.029 ;
     RECT  73.92 28.885 73.944 29.075 ;
     RECT  80.7 27.107 81.144 29.077 ;
     RECT  60.576 28.979 62.76 29.267 ;
     RECT  91.392 27.877 91.812 29.315 ;
     RECT  72.6 28.739 72.912 29.461 ;
     RECT  86.1 28.405 87.144 29.507 ;
     RECT  78 26.435 78.312 29.605 ;
     RECT  84.912 27.589 84.936 29.699 ;
     RECT  67.2 28.499 68.52 29.795 ;
     RECT  75.168 28.933 75.612 29.795 ;
     RECT  72.6 29.461 73.896 30.035 ;
     RECT  69.9 25.715 70.212 30.085 ;
     RECT  72.6 30.035 73.752 30.227 ;
     RECT  82.896 29.029 83.712 30.227 ;
     RECT  91.5 29.315 91.812 30.325 ;
     RECT  42.9 2.151 43.212 30.373 ;
     RECT  60.576 29.267 62.112 30.419 ;
     RECT  64.5 28.499 64.812 30.421 ;
     RECT  80.544 29.077 81.144 30.661 ;
     RECT  53.568 26.627 54.012 30.757 ;
     RECT  59.1 24.083 59.412 30.757 ;
     RECT  103.92 30.757 103.944 30.947 ;
     RECT  58.704 30.757 59.412 31.139 ;
     RECT  56.4 27.923 56.856 31.187 ;
     RECT  86.1 29.507 86.52 31.331 ;
     RECT  91.5 30.325 92.328 31.331 ;
     RECT  69.9 30.085 70.728 31.333 ;
     RECT  72.6 30.227 72.912 31.381 ;
     RECT  88.608 28.453 89.592 31.525 ;
     RECT  83.4 30.227 83.712 31.669 ;
     RECT  72.6 31.381 73.368 31.859 ;
     RECT  88.608 31.525 90.072 31.861 ;
     RECT  69.216 31.333 70.728 31.955 ;
     RECT  94.2 25.331 94.512 32.341 ;
     RECT  80.544 30.661 81.48 32.437 ;
     RECT  82.608 31.669 83.712 32.437 ;
     RECT  77.904 29.605 78.312 32.483 ;
     RECT  61.104 30.419 62.112 32.485 ;
     RECT  75.3 29.795 75.612 32.821 ;
     RECT  99.6 2.151 99.912 32.821 ;
     RECT  53.568 30.757 54.12 32.867 ;
     RECT  53.7 32.867 54.12 32.965 ;
     RECT  58.896 31.139 59.412 33.011 ;
     RECT  78 32.483 78.312 33.013 ;
     RECT  74.448 32.821 75.612 33.061 ;
     RECT  60.384 32.485 62.112 33.251 ;
     RECT  69.216 31.955 70.212 33.299 ;
     RECT  87.744 31.861 90.072 33.299 ;
     RECT  84.912 33.109 84.936 33.347 ;
     RECT  72.6 31.859 72.912 33.349 ;
     RECT  80.544 32.437 83.712 33.349 ;
     RECT  74.448 33.061 76.392 33.395 ;
     RECT  88.8 33.299 90.072 33.541 ;
     RECT  61.104 33.251 62.112 33.589 ;
     RECT  69.9 33.299 70.212 33.589 ;
     RECT  96.9 28.163 98.184 33.635 ;
     RECT  87.744 33.299 87.768 33.683 ;
     RECT  86.1 31.331 86.412 33.829 ;
     RECT  94.2 32.341 95.16 33.829 ;
     RECT  99.312 32.821 99.912 33.923 ;
     RECT  74.64 33.395 76.392 33.971 ;
     RECT  40.2 2.151 40.512 34.069 ;
     RECT  42.432 30.373 43.212 34.115 ;
     RECT  51 26.819 51.312 34.117 ;
     RECT  79.872 33.349 83.712 34.163 ;
     RECT  42.9 34.115 43.212 34.165 ;
     RECT  61.104 33.589 62.712 34.213 ;
     RECT  72.6 33.349 73.224 34.213 ;
     RECT  88.8 33.541 90.408 34.259 ;
     RECT  64.5 30.421 65.208 34.403 ;
     RECT  51 34.117 52.296 34.405 ;
     RECT  85.344 33.829 86.412 34.405 ;
     RECT  84.96 34.405 86.412 34.549 ;
     RECT  69.9 33.589 70.872 34.597 ;
     RECT  72.6 34.213 73.56 34.597 ;
     RECT  74.64 33.971 75.612 34.597 ;
     RECT  69.648 34.597 70.872 34.739 ;
     RECT  88.8 34.259 90.024 34.741 ;
     RECT  67.2 29.795 68.04 34.835 ;
     RECT  72.6 34.597 75.612 34.835 ;
     RECT  88.656 34.741 90.024 34.835 ;
     RECT  60.384 34.213 62.712 34.931 ;
     RECT  72.6 34.835 73.56 35.027 ;
     RECT  84.912 34.549 86.412 35.315 ;
     RECT  53.7 32.965 54.36 35.363 ;
     RECT  60.384 34.931 62.112 35.363 ;
     RECT  88.656 34.835 89.112 35.363 ;
     RECT  78 33.013 78.408 35.555 ;
     RECT  51 34.405 52.392 35.701 ;
     RECT  53.7 35.363 54.12 35.701 ;
     RECT  69.9 34.739 70.872 35.939 ;
     RECT  80.544 34.163 82.152 36.085 ;
     RECT  93.264 33.829 95.16 36.227 ;
     RECT  61.104 35.363 62.112 36.275 ;
     RECT  88.8 35.363 89.112 36.421 ;
     RECT  85.248 35.315 86.412 36.515 ;
     RECT  80.544 36.085 82.2 36.805 ;
     RECT  83.232 34.163 83.712 36.805 ;
     RECT  80.544 36.805 83.712 36.947 ;
     RECT  94.2 36.227 95.16 37.091 ;
     RECT  67.2 34.835 67.8 37.333 ;
     RECT  51 35.701 54.12 37.429 ;
     RECT  69.9 35.939 70.212 37.573 ;
     RECT  72.6 35.027 73.224 37.573 ;
     RECT  94.2 37.091 94.512 37.573 ;
     RECT  84.96 37.141 84.984 37.667 ;
     RECT  87.888 36.421 89.112 37.859 ;
     RECT  96.9 33.635 97.512 37.861 ;
     RECT  37.5 2.151 37.812 38.005 ;
     RECT  51 37.429 54.312 38.149 ;
     RECT  93.984 37.573 94.512 38.149 ;
     RECT  63.216 37.429 63.24 38.195 ;
     RECT  50.112 38.149 54.312 38.243 ;
     RECT  66.816 37.333 67.8 38.243 ;
     RECT  78 35.555 78.312 38.245 ;
     RECT  42.9 34.165 43.944 38.437 ;
     RECT  83.4 36.947 83.712 38.533 ;
     RECT  37.5 38.005 38.76 38.581 ;
     RECT  40.2 34.069 40.68 38.581 ;
     RECT  72.24 37.573 73.224 38.771 ;
     RECT  80.544 36.947 82.2 38.773 ;
     RECT  36.576 38.581 38.76 38.915 ;
     RECT  40.08 38.581 40.68 39.107 ;
     RECT  86.1 36.515 86.412 39.253 ;
     RECT  52.368 38.243 54.312 39.301 ;
     RECT  55.392 34.645 55.416 39.301 ;
     RECT  83.4 38.533 84.312 39.301 ;
     RECT  69.792 37.573 70.212 39.347 ;
     RECT  93.984 38.149 95.208 39.491 ;
     RECT  59.1 33.011 59.412 39.493 ;
     RECT  48.3 25.045 48.984 39.635 ;
     RECT  59.1 39.493 59.784 39.635 ;
     RECT  42.9 38.437 43.992 39.637 ;
     RECT  42.9 39.637 44.472 39.683 ;
     RECT  59.1 39.635 59.412 39.733 ;
     RECT  75.3 34.835 75.612 39.781 ;
     RECT  74.832 39.781 75.612 39.877 ;
     RECT  91.5 31.331 91.812 39.877 ;
     RECT  94.2 39.491 95.208 39.923 ;
     RECT  77.52 38.245 78.312 40.019 ;
     RECT  66.816 38.243 67.512 40.117 ;
     RECT  56.4 31.187 56.712 40.165 ;
     RECT  50.112 38.243 51.312 40.307 ;
     RECT  36.576 38.915 37.812 40.357 ;
     RECT  69.9 39.347 70.212 40.405 ;
     RECT  48.3 39.635 48.744 40.499 ;
     RECT  65.808 39.829 65.832 40.499 ;
     RECT  72.6 38.771 73.224 40.549 ;
     RECT  52.368 39.301 55.416 40.595 ;
     RECT  58.56 39.733 59.412 40.595 ;
     RECT  90.576 39.877 91.812 40.595 ;
     RECT  79.824 38.773 82.2 40.883 ;
     RECT  80.544 40.883 82.2 41.029 ;
     RECT  83.4 39.301 84.408 41.029 ;
     RECT  66.816 40.117 68.04 41.125 ;
     RECT  69.9 40.405 71.16 41.125 ;
     RECT  55.392 40.595 55.416 41.221 ;
     RECT  56.4 40.165 57.192 41.221 ;
     RECT  88.8 37.859 89.112 41.221 ;
     RECT  85.488 39.253 86.412 41.269 ;
     RECT  52.368 40.595 54.12 41.411 ;
     RECT  51 40.307 51.312 41.461 ;
     RECT  52.368 41.411 54.012 41.461 ;
     RECT  80.544 41.029 84.408 41.461 ;
     RECT  85.44 41.269 86.412 41.461 ;
     RECT  66.816 41.125 71.16 41.507 ;
     RECT  78 40.019 78.312 41.557 ;
     RECT  36.576 40.357 37.944 41.651 ;
     RECT  44.448 39.683 44.472 41.651 ;
     RECT  55.392 41.221 57.192 41.651 ;
     RECT  72.48 40.549 73.224 41.651 ;
     RECT  80.544 41.461 86.412 41.651 ;
     RECT  94.2 39.923 94.512 41.701 ;
     RECT  84.912 41.651 86.412 41.747 ;
     RECT  85.44 41.747 86.412 41.795 ;
     RECT  80.544 41.651 83.832 41.891 ;
     RECT  37.5 41.651 37.944 41.939 ;
     RECT  42.9 39.683 43.212 42.085 ;
     RECT  42.096 42.085 43.212 42.133 ;
     RECT  69.9 41.507 71.16 42.133 ;
     RECT  58.992 40.595 59.412 42.179 ;
     RECT  78 41.557 79.272 42.181 ;
     RECT  80.544 41.891 83.712 42.181 ;
     RECT  85.968 41.795 86.412 42.227 ;
     RECT  88.8 41.221 89.4 42.227 ;
     RECT  78 42.181 83.712 42.275 ;
     RECT  63.456 42.085 63.48 42.371 ;
     RECT  94.2 41.701 95.256 42.419 ;
     RECT  72.6 41.651 73.224 42.469 ;
     RECT  74.448 39.877 75.612 42.469 ;
     RECT  47.088 36.949 47.112 42.565 ;
     RECT  48.3 40.499 48.612 42.565 ;
     RECT  78 42.275 78.408 42.613 ;
     RECT  86.1 42.227 86.412 42.709 ;
     RECT  47.088 42.565 48.612 42.851 ;
     RECT  55.392 41.651 56.712 42.851 ;
     RECT  94.2 42.419 94.632 42.899 ;
     RECT  61.2 36.275 62.112 42.997 ;
     RECT  64.5 34.403 64.812 42.997 ;
     RECT  61.2 42.997 62.232 43.093 ;
     RECT  77.568 42.613 78.408 43.139 ;
     RECT  40.2 39.107 40.68 43.285 ;
     RECT  42.096 42.133 43.704 43.285 ;
     RECT  42.096 43.285 44.28 43.331 ;
     RECT  42.096 43.331 43.212 43.379 ;
     RECT  51 41.461 54.012 43.429 ;
     RECT  66.816 41.507 68.04 43.573 ;
     RECT  48.3 42.851 48.612 43.717 ;
     RECT  72.6 42.469 75.612 43.763 ;
     RECT  34.8 2.151 35.112 43.861 ;
     RECT  36.096 43.141 36.12 43.861 ;
     RECT  37.5 41.939 37.812 43.861 ;
     RECT  40.2 43.285 40.728 43.861 ;
     RECT  78 43.139 78.408 44.053 ;
     RECT  69.9 42.133 71.496 44.099 ;
     RECT  84.912 42.709 84.936 44.099 ;
     RECT  86.1 42.709 86.568 44.099 ;
     RECT  88.8 42.227 89.208 44.099 ;
     RECT  96.9 37.861 98.04 44.293 ;
     RECT  99.6 33.923 99.912 44.293 ;
     RECT  32.1 2.151 32.412 44.341 ;
     RECT  34.8 43.861 36.12 44.483 ;
     RECT  44.256 43.331 44.28 44.483 ;
     RECT  64.08 42.997 64.812 44.483 ;
     RECT  79.584 42.275 83.712 44.771 ;
     RECT  66.672 43.573 68.04 44.773 ;
     RECT  74.448 43.763 75.612 44.867 ;
     RECT  64.5 44.483 64.812 44.869 ;
     RECT  66.672 44.773 68.616 44.963 ;
     RECT  69.9 44.099 71.304 44.965 ;
     RECT  48.3 43.717 48.744 45.011 ;
     RECT  51 43.429 54.12 45.203 ;
     RECT  96.9 44.293 99.912 45.203 ;
     RECT  69.792 44.965 71.304 45.205 ;
     RECT  72.6 43.763 73.272 45.251 ;
     RECT  80.544 44.771 83.712 45.251 ;
     RECT  64.5 44.869 65.496 45.253 ;
     RECT  66.672 44.963 68.04 45.253 ;
     RECT  69.408 45.205 71.304 45.395 ;
     RECT  37.5 43.861 38.04 45.443 ;
     RECT  55.536 42.851 56.712 45.541 ;
     RECT  64.5 45.253 68.04 45.587 ;
     RECT  31.968 44.341 32.412 45.635 ;
     RECT  36.096 44.483 36.12 45.635 ;
     RECT  90.864 40.595 91.812 45.635 ;
     RECT  57.888 45.301 57.912 45.781 ;
     RECT  59.1 42.179 59.412 45.781 ;
     RECT  60.96 43.093 62.232 45.877 ;
     RECT  60.96 45.877 62.568 45.925 ;
     RECT  40.2 43.861 41.352 46.069 ;
     RECT  86.1 44.099 86.412 46.069 ;
     RECT  37.5 45.443 37.812 46.117 ;
     RECT  55.44 45.541 56.712 46.211 ;
     RECT  84.96 46.213 84.984 46.355 ;
     RECT  69.792 45.395 71.304 46.499 ;
     RECT  64.5 45.587 64.812 46.645 ;
     RECT  95.568 45.157 95.592 46.693 ;
     RECT  80.592 45.251 83.712 46.739 ;
     RECT  60.768 45.925 62.568 46.787 ;
     RECT  74.256 45.205 74.28 46.787 ;
     RECT  78 44.053 78.504 46.787 ;
     RECT  57.888 45.781 59.412 46.835 ;
     RECT  61.8 46.787 62.568 47.123 ;
     RECT  88.8 44.099 89.112 47.125 ;
     RECT  55.536 46.211 56.712 47.173 ;
     RECT  40.2 46.069 41.928 47.221 ;
     RECT  42.9 43.379 43.212 47.221 ;
     RECT  75.3 44.867 75.612 47.269 ;
     RECT  63.744 46.645 64.812 47.315 ;
     RECT  96.9 45.203 98.04 47.315 ;
     RECT  40.2 47.221 43.212 47.363 ;
     RECT  60.768 46.787 60.792 47.363 ;
     RECT  80.7 46.739 83.712 47.509 ;
     RECT  48.3 45.011 48.612 47.557 ;
     RECT  65.856 45.587 68.04 47.557 ;
     RECT  37.2 46.117 37.812 47.603 ;
     RECT  95.568 46.693 95.832 47.603 ;
     RECT  91.5 45.635 91.812 47.605 ;
     RECT  51 45.203 54.012 47.653 ;
     RECT  55.296 47.173 56.712 47.653 ;
     RECT  80.7 47.509 84.408 47.747 ;
     RECT  34.8 44.483 35.112 47.845 ;
     RECT  58.272 46.835 59.412 47.845 ;
     RECT  96.9 47.315 97.32 47.939 ;
     RECT  78 46.787 78.312 47.941 ;
     RECT  61.8 47.123 62.112 48.085 ;
     RECT  86.1 46.069 87.24 48.229 ;
     RECT  90.72 47.605 91.812 48.371 ;
     RECT  72.6 45.251 72.912 48.373 ;
     RECT  65.856 47.557 68.712 48.515 ;
     RECT  75.3 47.269 76.056 48.659 ;
     RECT  37.5 47.603 37.812 48.661 ;
     RECT  42.768 47.363 43.212 48.709 ;
     RECT  51 47.653 56.712 48.709 ;
     RECT  40.2 47.363 41.352 48.755 ;
     RECT  69.792 46.499 71.16 48.803 ;
     RECT  80.7 47.747 83.712 48.805 ;
     RECT  61.8 48.085 63.24 48.851 ;
     RECT  50.88 48.709 56.712 48.947 ;
     RECT  42.768 48.709 44.04 48.949 ;
     RECT  48.3 47.557 49.368 48.949 ;
     RECT  64.5 47.315 64.812 48.949 ;
     RECT  65.856 48.515 68.136 48.949 ;
     RECT  72.48 48.373 72.912 48.949 ;
     RECT  40.2 48.755 41.064 48.995 ;
     RECT  72.48 48.949 73.176 48.995 ;
     RECT  88.8 47.125 89.208 48.995 ;
     RECT  45.6 2.151 45.912 48.997 ;
     RECT  58.272 47.845 59.64 49.091 ;
     RECT  80.064 48.805 84.072 49.091 ;
     RECT  86.1 48.229 87.288 49.091 ;
     RECT  55.536 48.947 56.712 49.333 ;
     RECT  58.272 49.091 59.412 49.333 ;
     RECT  86.1 49.091 87.24 49.333 ;
     RECT  34.704 47.845 35.112 49.619 ;
     RECT  55.536 49.333 59.412 49.619 ;
     RECT  95.568 47.603 95.592 49.619 ;
     RECT  42.768 48.949 44.184 49.763 ;
     RECT  48.3 48.949 49.512 49.811 ;
     RECT  75.3 48.659 75.612 49.861 ;
     RECT  64.5 48.949 68.136 50.053 ;
     RECT  36.144 48.805 36.168 50.101 ;
     RECT  37.5 48.661 37.944 50.101 ;
     RECT  61.8 48.851 62.808 50.195 ;
     RECT  36.144 50.101 37.944 50.245 ;
     RECT  90.864 48.371 91.812 50.245 ;
     RECT  96.9 47.939 97.212 50.245 ;
     RECT  50.88 48.947 54.552 50.291 ;
     RECT  40.2 48.995 40.632 50.293 ;
     RECT  56.112 49.619 59.412 50.339 ;
     RECT  90.72 50.245 91.812 50.485 ;
     RECT  72.6 48.995 73.176 50.581 ;
     RECT  40.2 50.293 40.728 50.677 ;
     RECT  74.736 49.861 75.612 50.677 ;
     RECT  85.488 49.333 87.24 50.677 ;
     RECT  85.488 50.677 87.48 50.723 ;
     RECT  61.8 50.195 62.112 50.965 ;
     RECT  64.5 50.053 68.616 51.107 ;
     RECT  61.536 50.965 62.112 51.205 ;
     RECT  65.856 51.107 68.616 51.299 ;
     RECT  36.144 50.245 38.76 51.347 ;
     RECT  56.112 50.339 56.712 51.347 ;
     RECT  77.856 47.941 78.312 51.347 ;
     RECT  90.432 50.485 91.812 51.347 ;
     RECT  96.9 50.245 97.512 51.347 ;
     RECT  85.488 50.723 86.412 51.397 ;
     RECT  80.064 49.091 83.712 51.493 ;
     RECT  47.088 42.851 47.112 51.589 ;
     RECT  39.84 50.677 40.728 51.683 ;
     RECT  78 51.347 78.312 51.685 ;
     RECT  79.344 51.493 83.712 51.685 ;
     RECT  42.9 49.763 44.184 51.781 ;
     RECT  45.36 48.997 45.912 51.781 ;
     RECT  37.5 51.347 38.76 51.923 ;
     RECT  42.9 51.781 45.912 51.923 ;
     RECT  61.536 51.205 62.808 51.923 ;
     RECT  40.2 51.683 40.728 51.971 ;
     RECT  95.616 49.861 95.64 51.971 ;
     RECT  74.688 50.677 75.612 52.115 ;
     RECT  72.6 50.581 73.272 52.261 ;
     RECT  48.3 49.811 48.612 52.453 ;
     RECT  58.272 50.339 59.412 52.453 ;
     RECT  42.9 51.923 44.472 52.499 ;
     RECT  52.368 50.291 54.552 52.499 ;
     RECT  78 51.685 83.712 52.499 ;
     RECT  84.96 51.397 86.412 52.499 ;
     RECT  72.6 52.261 73.512 52.597 ;
     RECT  90.624 51.347 91.812 52.787 ;
     RECT  50.88 50.291 51.312 52.933 ;
     RECT  65.856 51.299 68.04 52.933 ;
     RECT  85.44 52.499 86.412 52.979 ;
     RECT  61.536 51.923 62.112 52.981 ;
     RECT  47.088 51.589 47.256 53.027 ;
     RECT  64.5 51.107 64.812 53.029 ;
     RECT  65.856 52.933 68.376 53.029 ;
     RECT  74.784 52.115 75.612 53.077 ;
     RECT  79.344 52.499 83.712 53.123 ;
     RECT  61.536 52.981 62.232 53.171 ;
     RECT  52.944 52.499 54.552 53.267 ;
     RECT  72.288 52.597 73.512 53.269 ;
     RECT  74.784 53.077 75.864 53.269 ;
     RECT  64.5 53.029 68.376 53.315 ;
     RECT  72.288 53.269 75.864 53.315 ;
     RECT  72.288 53.315 75.612 53.411 ;
     RECT  48.3 52.453 48.792 53.509 ;
     RECT  58.176 52.453 59.412 53.509 ;
     RECT  61.536 53.171 62.112 53.557 ;
     RECT  47.088 53.027 47.112 53.603 ;
     RECT  52.944 53.267 54.168 53.603 ;
     RECT  90.72 52.787 91.812 53.603 ;
     RECT  50.88 52.933 51.912 53.651 ;
     RECT  52.944 53.603 54.12 53.699 ;
     RECT  74.784 53.411 75.612 53.699 ;
     RECT  48.3 53.509 49.224 53.797 ;
     RECT  50.88 53.651 51.312 53.797 ;
     RECT  48.3 53.797 51.312 53.891 ;
     RECT  45.6 51.923 45.912 53.893 ;
     RECT  72.288 53.411 73.272 53.987 ;
     RECT  92.928 53.557 92.952 54.179 ;
     RECT  79.776 53.123 83.712 54.469 ;
     RECT  24 2.151 24.312 54.565 ;
     RECT  18.6 2.151 18.912 54.661 ;
     RECT  72.6 53.987 73.272 54.661 ;
     RECT  23.904 54.565 24.312 54.707 ;
     RECT  66.816 53.315 68.376 54.755 ;
     RECT  85.488 52.979 86.412 54.899 ;
     RECT  61.2 53.557 62.112 54.901 ;
     RECT  61.2 54.901 62.664 54.947 ;
     RECT  61.536 54.947 62.664 55.139 ;
     RECT  72.6 54.661 73.56 55.283 ;
     RECT  53.7 53.699 54.12 55.331 ;
     RECT  79.632 54.469 83.712 55.379 ;
     RECT  45.6 53.893 46.104 55.813 ;
     RECT  86.1 54.899 86.412 55.813 ;
     RECT  87.456 50.723 87.48 55.813 ;
     RECT  88.8 48.995 89.112 55.813 ;
     RECT  79.632 55.379 79.656 55.907 ;
     RECT  61.8 55.139 62.664 56.099 ;
     RECT  42.9 52.499 43.944 56.101 ;
     RECT  64.5 53.315 65.736 56.195 ;
     RECT  48.3 53.891 49.944 56.291 ;
     RECT  51 53.891 51.312 56.389 ;
     RECT  94.2 42.899 94.512 56.389 ;
     RECT  95.904 53.557 95.928 56.389 ;
     RECT  42.192 56.101 43.944 56.435 ;
     RECT  49.92 56.291 49.944 56.435 ;
     RECT  45.6 55.813 46.2 56.483 ;
     RECT  86.1 55.813 87.48 56.531 ;
     RECT  85.008 55.909 85.032 56.533 ;
     RECT  88.8 55.813 89.448 56.627 ;
     RECT  94.2 56.389 95.928 56.725 ;
     RECT  0.192 53.317 0.216 56.773 ;
     RECT  72.6 55.283 73.272 56.867 ;
     RECT  93.456 56.725 95.928 56.963 ;
     RECT  42.192 56.435 43.212 57.059 ;
     RECT  48.3 56.291 48.612 57.349 ;
     RECT  84.72 56.533 85.032 57.445 ;
     RECT  86.1 56.531 86.412 57.445 ;
     RECT  80.7 55.379 83.712 57.541 ;
     RECT  84.72 57.445 86.412 57.541 ;
     RECT  91.5 53.603 91.812 57.541 ;
     RECT  51 56.389 51.528 57.683 ;
     RECT  47.952 57.349 48.612 57.827 ;
     RECT  51 57.683 51.312 57.925 ;
     RECT  69.9 48.803 71.16 57.973 ;
     RECT  80.7 57.541 86.412 58.115 ;
     RECT  56.4 51.347 56.712 58.117 ;
     RECT  61.8 56.099 62.112 58.117 ;
     RECT  66.816 54.755 68.04 58.117 ;
     RECT  69.9 57.973 71.208 58.117 ;
     RECT  66.816 58.117 71.208 58.259 ;
     RECT  87.456 56.531 87.48 58.355 ;
     RECT  91.5 57.541 92.376 58.355 ;
     RECT  88.8 56.627 89.112 58.453 ;
     RECT  75.3 53.699 75.612 58.549 ;
     RECT  48.3 57.827 48.612 58.645 ;
     RECT  53.7 55.331 54.012 58.645 ;
     RECT  85.152 58.115 86.412 58.691 ;
     RECT  61.8 58.117 62.424 58.693 ;
     RECT  80.7 58.115 84.072 58.739 ;
     RECT  61.68 58.693 62.424 58.883 ;
     RECT  24 54.707 24.312 58.885 ;
     RECT  23.904 58.885 24.312 59.027 ;
     RECT  94.2 56.963 95.928 59.173 ;
     RECT  96.9 51.347 97.212 59.173 ;
     RECT  48.3 58.645 48.936 59.221 ;
     RECT  50.544 57.925 51.312 59.221 ;
     RECT  72.6 56.867 72.912 59.221 ;
     RECT  61.8 58.883 62.424 59.267 ;
     RECT  88.8 58.453 89.208 59.315 ;
     RECT  86.1 58.691 86.412 59.461 ;
     RECT  48.3 59.221 51.312 59.605 ;
     RECT  66.816 58.259 71.16 59.747 ;
     RECT  80.7 58.739 83.712 59.797 ;
     RECT  72.6 59.221 73.032 59.843 ;
     RECT  55.44 58.117 56.712 59.891 ;
     RECT  75.3 58.549 76.584 59.891 ;
     RECT  94.2 59.173 97.212 59.891 ;
     RECT  18.6 54.661 19.608 60.035 ;
     RECT  36.144 51.347 36.168 60.035 ;
     RECT  0.192 56.773 0.36 60.083 ;
     RECT  86.1 59.461 86.664 60.083 ;
     RECT  88.8 59.315 89.112 60.085 ;
     RECT  0.336 60.083 0.36 60.179 ;
     RECT  64.5 56.195 64.812 60.181 ;
     RECT  91.5 58.355 91.812 60.277 ;
     RECT  64.5 60.181 65.304 60.373 ;
     RECT  78 52.499 78.312 60.373 ;
     RECT  88.56 60.085 89.112 60.373 ;
     RECT  90.288 57.973 90.312 60.373 ;
     RECT  63.12 60.277 63.336 60.419 ;
     RECT  48.192 59.605 51.312 60.659 ;
     RECT  80.4 59.797 83.712 60.901 ;
     RECT  56.4 59.891 56.712 60.949 ;
     RECT  57.792 53.509 59.412 60.949 ;
     RECT  56.4 60.949 59.412 60.997 ;
     RECT  60.768 60.373 60.792 60.997 ;
     RECT  88.56 60.373 90.312 61.091 ;
     RECT  86.1 60.083 86.412 61.093 ;
     RECT  75.3 59.891 75.612 61.141 ;
     RECT  63.312 60.419 63.336 61.189 ;
     RECT  86.1 61.093 86.904 61.333 ;
     RECT  76.896 60.277 76.92 61.379 ;
     RECT  80.4 60.901 84.264 61.379 ;
     RECT  64.5 60.373 65.784 61.381 ;
     RECT  56.4 60.997 60.792 61.475 ;
     RECT  61.8 59.267 62.112 61.477 ;
     RECT  63.312 61.189 63.384 61.477 ;
     RECT  48.192 60.659 48.936 61.619 ;
     RECT  50.544 60.659 51.312 61.619 ;
     RECT  66.816 59.747 68.712 61.619 ;
     RECT  80.448 61.379 84.264 61.619 ;
     RECT  69.792 59.747 71.16 61.621 ;
     RECT  72.6 59.843 72.912 61.621 ;
     RECT  91.5 60.277 91.944 61.667 ;
     RECT  69.792 61.621 72.912 61.765 ;
     RECT  91.5 61.667 91.812 61.765 ;
     RECT  66.816 61.619 68.04 61.811 ;
     RECT  94.2 59.891 95.448 61.859 ;
     RECT  69.792 61.765 73.848 61.909 ;
     RECT  53.472 58.645 54.012 62.005 ;
     RECT  69.792 61.909 73.944 62.005 ;
     RECT  75.3 61.141 75.864 62.005 ;
     RECT  69.792 62.005 75.864 62.051 ;
     RECT  69.792 62.051 75.612 62.195 ;
     RECT  61.8 61.477 63.384 62.339 ;
     RECT  86.1 61.333 87.048 62.435 ;
     RECT  63.36 62.339 63.384 62.437 ;
     RECT  64.368 61.381 65.784 62.437 ;
     RECT  63.36 62.437 65.784 62.579 ;
     RECT  80.496 61.619 84.264 62.723 ;
     RECT  53.04 62.005 54.012 63.011 ;
     RECT  71.568 62.195 75.612 63.157 ;
     RECT  76.944 61.669 76.968 63.157 ;
     RECT  51 61.619 51.312 63.205 ;
     RECT  66.816 61.811 67.896 63.205 ;
     RECT  78 60.373 79.368 63.205 ;
     RECT  80.496 62.723 83.712 63.205 ;
     RECT  90.576 61.765 91.812 63.539 ;
     RECT  69.792 62.195 70.212 63.541 ;
     RECT  71.568 63.157 76.968 63.541 ;
     RECT  61.8 62.339 62.112 63.733 ;
     RECT  69.792 63.541 76.968 63.781 ;
     RECT  69.552 63.781 76.968 63.875 ;
     RECT  48.3 61.619 48.936 63.925 ;
     RECT  56.4 61.475 59.88 64.117 ;
     RECT  78 63.205 83.712 64.211 ;
     RECT  61.8 63.733 62.424 64.213 ;
     RECT  66.816 63.205 68.088 64.261 ;
     RECT  98.4 61.669 98.424 64.307 ;
     RECT  56.4 64.117 60.024 64.355 ;
     RECT  61.8 64.213 63.048 64.355 ;
     RECT  80.496 64.211 83.712 64.403 ;
     RECT  66.816 64.261 68.136 64.501 ;
     RECT  72.096 63.875 76.968 64.739 ;
     RECT  88.56 61.091 89.4 64.885 ;
     RECT  91.392 63.539 91.812 64.931 ;
     RECT  66.816 64.501 68.472 64.981 ;
     RECT  69.552 63.875 71.112 64.981 ;
     RECT  66.816 64.981 71.112 65.171 ;
     RECT  88.56 64.885 89.928 65.221 ;
     RECT  80.7 64.403 83.712 65.365 ;
     RECT  96.9 59.891 97.212 65.365 ;
     RECT  64.176 62.579 65.784 65.411 ;
     RECT  53.568 63.011 54.012 65.509 ;
     RECT  94.2 61.859 94.512 65.509 ;
     RECT  72.096 64.739 76.2 65.555 ;
     RECT  64.176 65.411 64.812 65.605 ;
     RECT  86.1 62.435 86.412 65.797 ;
     RECT  91.5 64.931 91.812 65.797 ;
     RECT  56.4 64.355 59.412 65.941 ;
     RECT  61.8 64.355 62.424 65.989 ;
     RECT  69.552 65.171 71.112 65.989 ;
     RECT  72.096 65.555 75.612 65.989 ;
     RECT  96.768 65.365 97.212 66.035 ;
     RECT  91.5 65.797 92.328 66.085 ;
     RECT  50.736 63.205 51.312 66.133 ;
     RECT  52.656 65.509 54.012 66.133 ;
     RECT  50.736 66.133 54.012 66.323 ;
     RECT  64.08 65.605 64.812 66.373 ;
     RECT  88.368 65.221 89.928 66.467 ;
     RECT  66.816 65.171 68.472 66.659 ;
     RECT  48.3 63.925 49.32 66.661 ;
     RECT  88.56 66.467 89.928 66.755 ;
     RECT  94.2 65.509 94.632 66.755 ;
     RECT  47.808 66.661 49.32 66.803 ;
     RECT  69.552 65.989 75.612 66.899 ;
     RECT  45.6 56.483 46.104 66.901 ;
     RECT  78 64.211 79.368 67.045 ;
     RECT  80.448 65.365 83.712 67.045 ;
     RECT  69.9 66.899 75.612 67.091 ;
     RECT  86.1 65.797 86.568 67.141 ;
     RECT  61.8 65.989 63.096 67.237 ;
     RECT  64.08 66.373 65.544 67.237 ;
     RECT  76.896 66.085 76.92 67.237 ;
     RECT  85.344 67.141 86.568 67.283 ;
     RECT  91.152 66.085 93.096 67.283 ;
     RECT  76.8 67.237 76.92 67.523 ;
     RECT  88.56 66.755 89.4 67.667 ;
     RECT  66.816 66.659 67.896 67.765 ;
     RECT  48.3 66.803 49.32 67.861 ;
     RECT  85.344 67.283 86.52 67.907 ;
     RECT  91.5 67.283 93.096 67.907 ;
     RECT  66.816 67.765 68.376 68.101 ;
     RECT  69.9 67.091 72.912 68.101 ;
     RECT  61.8 67.237 65.544 68.195 ;
     RECT  45.6 66.901 46.68 68.245 ;
     RECT  48.3 67.861 49.464 68.291 ;
     RECT  55.824 65.941 59.412 68.341 ;
     RECT  55.632 68.341 59.412 68.387 ;
     RECT  85.344 67.907 86.412 68.485 ;
     RECT  73.92 67.091 75.612 68.581 ;
     RECT  76.8 67.523 76.824 68.581 ;
     RECT  73.92 68.581 76.824 68.627 ;
     RECT  51 66.323 54.012 68.723 ;
     RECT  51 68.723 51.72 68.819 ;
     RECT  78 67.045 83.712 68.869 ;
     RECT  84.96 68.485 86.412 68.869 ;
     RECT  78 68.869 86.412 68.915 ;
     RECT  85.392 68.915 86.412 68.917 ;
     RECT  88.704 67.667 89.256 68.917 ;
     RECT  55.632 68.387 57.816 68.963 ;
     RECT  73.92 68.627 76.44 69.107 ;
     RECT  51 68.819 51.576 69.299 ;
     RECT  94.2 66.755 94.512 69.349 ;
     RECT  91.5 67.907 92.328 69.397 ;
     RECT  87.984 68.917 89.256 69.491 ;
     RECT  51 69.299 51.312 69.493 ;
     RECT  66.816 68.101 72.912 69.587 ;
     RECT  61.8 68.195 64.812 69.829 ;
     RECT  61.8 69.829 64.968 69.875 ;
     RECT  87.984 69.491 89.112 70.021 ;
     RECT  50.736 69.493 51.312 70.069 ;
     RECT  48.3 68.291 49.32 70.163 ;
     RECT  90.816 69.397 92.328 70.259 ;
     RECT  94.2 69.349 94.632 70.259 ;
     RECT  45.6 68.245 46.968 70.261 ;
     RECT  78 68.915 84.312 70.309 ;
     RECT  85.392 68.917 86.568 70.309 ;
     RECT  50.448 70.069 51.312 70.645 ;
     RECT  53.088 68.723 54.012 70.645 ;
     RECT  64.08 69.875 64.968 70.691 ;
     RECT  45.6 70.261 47.304 70.739 ;
     RECT  56.4 68.963 57.816 70.837 ;
     RECT  59.1 68.387 59.412 70.837 ;
     RECT  69.312 69.587 72.912 70.837 ;
     RECT  46.944 70.739 47.304 70.981 ;
     RECT  48.3 70.163 48.936 70.981 ;
     RECT  50.448 70.645 54.012 71.077 ;
     RECT  78 70.309 86.568 71.411 ;
     RECT  45.6 70.739 45.912 71.653 ;
     RECT  87.936 70.021 89.112 71.653 ;
     RECT  64.5 70.691 64.968 71.701 ;
     RECT  78 71.411 86.412 71.747 ;
     RECT  50.448 71.077 54.12 71.843 ;
     RECT  56.4 70.837 59.412 71.843 ;
     RECT  64.5 71.701 65.784 71.843 ;
     RECT  66.816 69.587 67.896 71.845 ;
     RECT  50.448 71.843 51.312 71.939 ;
     RECT  46.944 70.981 48.936 72.131 ;
     RECT  56.4 71.843 56.808 72.227 ;
     RECT  66.816 71.845 68.136 72.371 ;
     RECT  96.9 66.035 97.212 72.373 ;
     RECT  98.448 64.357 98.472 72.373 ;
     RECT  96.9 72.373 98.472 72.419 ;
     RECT  52.752 71.843 54.12 72.469 ;
     RECT  47.376 72.131 48.936 72.517 ;
     RECT  73.92 69.107 75.612 72.805 ;
     RECT  87.84 71.653 89.112 72.947 ;
     RECT  51 71.939 51.312 72.997 ;
     RECT  73.92 72.805 75.912 73.091 ;
     RECT  52.752 72.469 54.6 73.139 ;
     RECT  44.64 71.653 45.912 73.283 ;
     RECT  47.376 72.517 49.752 73.283 ;
     RECT  78 71.747 83.712 73.381 ;
     RECT  64.5 71.843 64.812 73.477 ;
     RECT  57.792 71.843 59.412 73.571 ;
     RECT  69.216 70.837 72.912 73.573 ;
     RECT  73.92 73.091 75.72 73.573 ;
     RECT  48.3 73.283 49.752 73.619 ;
     RECT  69.216 73.573 75.72 73.715 ;
     RECT  85.296 71.747 86.412 73.765 ;
     RECT  47.232 73.717 47.256 73.907 ;
     RECT  91.5 70.259 92.328 74.053 ;
     RECT  64.5 73.477 65.016 74.147 ;
     RECT  60.672 74.053 60.696 74.149 ;
     RECT  61.8 69.875 63.096 74.149 ;
     RECT  85.2 73.765 86.412 74.243 ;
     RECT  66.816 72.371 67.896 74.245 ;
     RECT  60.672 74.149 63.096 74.387 ;
     RECT  66.816 74.245 68.136 74.387 ;
     RECT  90.528 74.053 92.328 74.629 ;
     RECT  78 73.381 83.976 74.723 ;
     RECT  45.36 73.283 45.912 74.917 ;
     RECT  87.888 72.947 89.112 74.965 ;
     RECT  90.528 74.629 92.376 75.011 ;
     RECT  91.5 75.011 92.376 75.061 ;
     RECT  52.752 73.139 54.012 75.157 ;
     RECT  61.8 74.387 63.096 75.157 ;
     RECT  52.752 75.157 54.12 75.205 ;
     RECT  51 72.997 51.432 75.397 ;
     RECT  52.752 75.205 54.744 75.397 ;
     RECT  45.36 74.917 46.056 75.539 ;
     RECT  61.8 75.157 63.192 75.587 ;
     RECT  96.9 72.419 97.752 75.637 ;
     RECT  87.888 74.965 89.496 75.685 ;
     RECT  64.5 74.147 64.812 75.781 ;
     RECT  66.816 74.387 67.896 75.781 ;
     RECT  94.2 70.259 94.512 75.781 ;
     RECT  91.5 75.061 92.472 75.829 ;
     RECT  94.2 75.781 95.256 75.829 ;
     RECT  87.648 75.685 89.496 75.875 ;
     RECT  85.296 74.243 86.412 75.971 ;
     RECT  61.8 75.587 63.096 75.973 ;
     RECT  48.3 73.619 48.984 76.165 ;
     RECT  87.648 75.875 89.112 76.211 ;
     RECT  56.4 72.227 56.712 76.309 ;
     RECT  60.672 74.387 60.696 76.309 ;
     RECT  61.68 75.973 63.096 76.309 ;
     RECT  48.3 76.165 49.224 76.355 ;
     RECT  45.6 75.539 46.056 76.403 ;
     RECT  48.3 76.355 48.936 76.403 ;
     RECT  73.92 73.715 75.72 76.499 ;
     RECT  87.648 76.211 87.672 76.643 ;
     RECT  51 75.397 54.744 76.739 ;
     RECT  58.656 73.571 59.412 76.741 ;
     RECT  60.672 76.309 63.096 76.741 ;
     RECT  96.288 75.637 97.752 76.741 ;
     RECT  58.656 76.741 63.096 76.789 ;
     RECT  51 76.739 54.012 76.837 ;
     RECT  84.816 76.261 84.84 76.931 ;
     RECT  50.832 76.837 54.012 76.979 ;
     RECT  58.608 76.789 63.096 76.979 ;
     RECT  61.8 76.979 63.096 76.981 ;
     RECT  64.5 75.781 65.544 77.027 ;
     RECT  85.968 75.971 86.412 77.027 ;
     RECT  61.8 76.981 63.192 77.171 ;
     RECT  66.672 75.781 67.896 77.365 ;
     RECT  69.216 73.715 72.912 77.365 ;
     RECT  88.8 76.211 89.112 77.413 ;
     RECT  66.672 77.365 72.912 77.461 ;
     RECT  91.5 75.829 95.256 77.461 ;
     RECT  96.288 76.741 98.472 77.461 ;
     RECT  91.5 77.461 98.472 77.555 ;
     RECT  66.672 77.461 73.032 77.603 ;
     RECT  92.928 77.555 98.472 77.747 ;
     RECT  56.4 76.309 57.336 77.795 ;
     RECT  58.608 76.979 60.024 77.893 ;
     RECT  61.8 77.171 63.096 77.941 ;
     RECT  66.672 77.603 72.912 77.987 ;
     RECT  51 76.979 54.012 78.037 ;
     RECT  50.208 78.037 54.696 78.083 ;
     RECT  78 74.723 83.712 78.131 ;
     RECT  61.488 77.941 63.096 78.133 ;
     RECT  74.4 76.499 75.72 78.179 ;
     RECT  61.488 78.133 63.24 78.181 ;
     RECT  58.416 77.893 60.024 78.229 ;
     RECT  94.2 77.747 98.472 78.707 ;
     RECT  52.752 78.083 54.696 78.899 ;
     RECT  95.76 78.707 98.472 78.901 ;
     RECT  99.6 45.203 99.912 78.901 ;
     RECT  61.44 78.181 63.24 79.093 ;
     RECT  78 78.131 78.888 79.189 ;
     RECT  79.872 78.131 83.712 79.189 ;
     RECT  88.272 77.413 89.112 79.235 ;
     RECT  42.9 57.059 43.212 79.237 ;
     RECT  84.768 77.749 84.792 79.283 ;
     RECT  92.928 77.747 92.952 79.475 ;
     RECT  42.768 79.237 43.212 79.715 ;
     RECT  67.2 77.987 72.912 79.765 ;
     RECT  74.4 78.179 75.612 80.245 ;
     RECT  57.888 78.229 60.024 80.291 ;
     RECT  61.152 79.093 63.24 80.291 ;
     RECT  95.76 78.901 99.912 80.291 ;
     RECT  52.752 78.899 54.012 80.389 ;
     RECT  50.208 78.083 51.312 80.579 ;
     RECT  76.752 80.245 76.776 80.771 ;
     RECT  90.336 78.037 90.36 80.819 ;
     RECT  94.2 78.707 94.512 80.821 ;
     RECT  64.5 77.027 64.92 80.917 ;
     RECT  50.64 80.579 51.312 80.963 ;
     RECT  52.656 80.389 54.012 80.963 ;
     RECT  93.408 80.821 94.512 81.011 ;
     RECT  66.624 79.765 72.912 81.347 ;
     RECT  29.4 2.151 29.712 81.349 ;
     RECT  28.8 81.349 29.712 81.397 ;
     RECT  52.752 80.963 54.012 81.445 ;
     RECT  56.4 77.795 56.712 81.445 ;
     RECT  58.416 80.291 60.024 81.445 ;
     RECT  61.44 80.291 63.24 81.445 ;
     RECT  66.624 81.347 67.512 81.445 ;
     RECT  74.4 80.245 75.72 81.445 ;
     RECT  86.1 77.027 86.412 81.445 ;
     RECT  64.5 80.917 65.016 81.539 ;
     RECT  68.736 81.347 72.912 81.539 ;
     RECT  52.752 81.445 54.504 81.541 ;
     RECT  91.5 77.555 91.812 81.781 ;
     RECT  90.624 81.781 91.812 81.923 ;
     RECT  52.752 81.541 55.272 81.971 ;
     RECT  78 79.189 83.712 82.021 ;
     RECT  52.752 81.971 54.504 82.163 ;
     RECT  73.92 81.445 75.72 82.163 ;
     RECT  88.8 79.235 89.112 82.165 ;
     RECT  74.4 82.163 75.72 82.211 ;
     RECT  76.992 81.733 77.016 82.259 ;
     RECT  71.568 81.539 72.912 82.357 ;
     RECT  93.456 81.011 94.512 82.451 ;
     RECT  52.752 82.163 54.36 82.691 ;
     RECT  71.568 82.357 73.32 82.693 ;
     RECT  66.384 81.445 67.512 82.885 ;
     RECT  66.384 82.885 67.656 82.933 ;
     RECT  68.736 81.539 70.212 82.933 ;
     RECT  85.488 81.445 86.412 82.979 ;
     RECT  94.2 82.451 94.512 82.981 ;
     RECT  71.184 82.693 73.32 83.075 ;
     RECT  78 82.021 84.12 83.077 ;
     RECT  66.384 82.933 70.212 83.173 ;
     RECT  71.184 83.075 72.912 83.173 ;
     RECT  56.4 81.445 63.24 83.267 ;
     RECT  56.4 83.267 59.64 83.363 ;
     RECT  77.808 83.077 84.12 83.363 ;
     RECT  88.272 82.165 89.112 83.507 ;
     RECT  40.2 51.971 40.512 83.509 ;
     RECT  77.808 83.363 82.344 83.509 ;
     RECT  96.288 80.291 99.912 83.603 ;
     RECT  58.128 83.363 59.64 83.651 ;
     RECT  52.752 82.691 54.012 83.749 ;
     RECT  83.4 83.363 84.12 83.749 ;
     RECT  66.384 83.173 72.912 83.795 ;
     RECT  94.2 82.981 95.16 83.843 ;
     RECT  66.384 83.795 70.536 83.891 ;
     RECT  77.472 83.509 82.344 83.891 ;
     RECT  71.568 83.795 72.912 84.133 ;
     RECT  90.336 82.981 90.36 84.133 ;
     RECT  96.288 83.603 97.608 84.275 ;
     RECT  75.3 82.211 75.72 84.277 ;
     RECT  52.752 83.749 54.888 84.563 ;
     RECT  60.672 83.267 63.24 84.563 ;
     RECT  66.384 83.891 70.344 84.611 ;
     RECT  71.568 84.133 73.464 84.611 ;
     RECT  77.808 83.891 82.344 84.853 ;
     RECT  86.1 82.979 86.412 84.853 ;
     RECT  87.744 84.133 87.768 84.853 ;
     RECT  71.712 84.611 73.464 84.995 ;
     RECT  75.3 84.277 76.056 85.091 ;
     RECT  56.4 83.363 56.712 85.237 ;
     RECT  52.752 84.563 54.012 85.477 ;
     RECT  77.472 84.853 82.344 85.523 ;
     RECT  86.1 84.853 87.768 85.523 ;
     RECT  96.432 84.275 97.608 85.523 ;
     RECT  52.464 85.477 54.012 85.765 ;
     RECT  94.2 83.843 94.872 85.813 ;
     RECT  90.336 84.133 90.408 85.861 ;
     RECT  78 85.523 82.344 85.909 ;
     RECT  83.4 83.749 84.888 85.909 ;
     RECT  91.5 81.923 91.812 85.909 ;
     RECT  93.024 84.901 93.048 85.909 ;
     RECT  34.8 49.619 35.112 86.005 ;
     RECT  58.128 83.651 59.412 86.005 ;
     RECT  78 85.909 84.888 86.005 ;
     RECT  71.712 84.995 72.912 86.099 ;
     RECT  96.9 85.523 97.608 86.099 ;
     RECT  34.8 86.005 35.592 86.197 ;
     RECT  67.2 84.611 70.344 86.245 ;
     RECT  34.32 86.197 35.592 86.341 ;
     RECT  34.32 86.341 35.736 86.485 ;
     RECT  78 86.005 84.936 86.485 ;
     RECT  67.2 86.245 71.16 86.531 ;
     RECT  34.224 86.485 35.736 86.581 ;
     RECT  75.3 85.091 75.612 86.581 ;
     RECT  78 86.485 84.984 86.581 ;
     RECT  88.8 83.507 89.112 86.581 ;
     RECT  90.336 85.861 90.504 86.581 ;
     RECT  52.464 85.765 54.744 86.627 ;
     RECT  56.256 85.237 56.712 86.917 ;
     RECT  34.224 86.581 35.832 87.013 ;
     RECT  48.3 76.403 48.612 87.109 ;
     RECT  91.5 85.909 93.048 87.155 ;
     RECT  94.08 85.813 94.872 87.155 ;
     RECT  67.2 86.531 70.344 87.157 ;
     RECT  52.752 86.627 54.744 87.205 ;
     RECT  52.752 87.205 55.08 87.251 ;
     RECT  77.376 86.581 84.984 87.251 ;
     RECT  34.224 87.013 35.88 87.301 ;
     RECT  37.5 51.923 37.812 87.301 ;
     RECT  86.1 85.523 86.412 87.301 ;
     RECT  94.2 87.155 94.872 87.541 ;
     RECT  32.1 45.635 32.412 87.637 ;
     RECT  48.3 87.109 48.984 87.685 ;
     RECT  61.44 84.563 63.24 87.733 ;
     RECT  57.744 86.005 59.412 87.827 ;
     RECT  94.2 87.541 95.064 87.925 ;
     RECT  86.1 87.301 86.52 88.115 ;
     RECT  32.1 87.637 32.712 88.117 ;
     RECT  66.672 87.157 70.344 88.309 ;
     RECT  71.472 87.733 71.496 88.309 ;
     RECT  47.808 87.685 48.984 88.357 ;
     RECT  52.752 87.251 54.012 88.403 ;
     RECT  87.744 85.523 87.768 88.403 ;
     RECT  47.808 88.357 49.944 88.405 ;
     RECT  51 80.963 51.312 88.405 ;
     RECT  88.8 86.581 90.504 88.453 ;
     RECT  91.5 87.155 91.944 88.453 ;
     RECT  78 87.251 84.984 88.499 ;
     RECT  55.056 87.251 55.08 88.595 ;
     RECT  75.3 86.581 75.912 88.741 ;
     RECT  88.8 88.453 91.944 88.787 ;
     RECT  31.92 88.117 32.712 88.885 ;
     RECT  75.3 88.741 76.536 88.931 ;
     RECT  90.624 88.787 91.944 88.931 ;
     RECT  58.128 87.827 59.412 88.979 ;
     RECT  94.2 87.925 95.736 88.979 ;
     RECT  56.208 86.917 56.712 89.027 ;
     RECT  66.672 88.309 71.496 89.123 ;
     RECT  64.5 81.539 64.812 89.365 ;
     RECT  67.2 89.123 71.496 89.411 ;
     RECT  67.2 89.411 71.256 89.507 ;
     RECT  83.232 88.499 84.984 89.555 ;
     RECT  93.024 87.155 93.048 89.699 ;
     RECT  64.5 89.365 64.92 90.037 ;
     RECT  95.712 88.979 95.736 90.083 ;
     RECT  75.3 88.931 76.344 90.229 ;
     RECT  75.3 90.229 76.92 90.275 ;
     RECT  67.2 89.507 71.16 90.323 ;
     RECT  31.92 88.885 32.808 90.517 ;
     RECT  39.456 83.509 40.512 90.659 ;
     RECT  60.48 87.733 63.24 90.659 ;
     RECT  78 88.499 82.248 90.755 ;
     RECT  34.224 87.301 37.812 90.805 ;
     RECT  63.216 90.659 63.24 90.901 ;
     RECT  90.624 88.931 91.812 91.045 ;
     RECT  99.072 83.603 99.912 91.091 ;
     RECT  31.632 90.517 32.808 91.093 ;
     RECT  42.9 79.715 43.212 91.093 ;
     RECT  86.1 88.115 86.412 91.141 ;
     RECT  58.608 88.979 59.412 91.235 ;
     RECT  34.176 90.805 37.812 91.333 ;
     RECT  42.528 91.093 43.212 91.333 ;
     RECT  64.5 90.037 65.736 91.477 ;
     RECT  67.2 90.323 70.344 91.477 ;
     RECT  64.5 91.477 70.344 91.811 ;
     RECT  76.896 90.275 76.92 91.811 ;
     RECT  63.216 90.901 63.288 92.003 ;
     RECT  66.672 91.811 70.344 92.339 ;
     RECT  86.1 91.141 87.24 92.341 ;
     RECT  63.216 92.003 63.24 92.387 ;
     RECT  72.6 86.099 72.912 92.677 ;
     RECT  78 90.755 82.2 92.677 ;
     RECT  83.232 89.555 84.648 92.677 ;
     RECT  95.76 91.429 95.784 92.723 ;
     RECT  78 92.677 84.648 92.869 ;
     RECT  86.1 92.341 87.624 92.915 ;
     RECT  96.9 86.099 97.212 92.917 ;
     RECT  90.624 91.045 92.664 92.963 ;
     RECT  56.4 89.027 56.712 92.965 ;
     RECT  77.04 92.869 84.648 93.251 ;
     RECT  59.1 91.235 59.412 93.253 ;
     RECT  98.256 91.717 98.28 93.395 ;
     RECT  96.24 92.917 97.212 93.443 ;
     RECT  75.3 90.275 75.612 93.445 ;
     RECT  94.2 88.979 94.512 93.445 ;
     RECT  94.2 93.445 95.064 93.493 ;
     RECT  28.464 81.397 29.712 93.539 ;
     RECT  75.3 93.445 75.912 93.541 ;
     RECT  24 59.027 24.312 93.733 ;
     RECT  90.624 92.963 91.812 93.779 ;
     RECT  23.712 93.733 24.312 93.781 ;
     RECT  90.72 93.779 91.812 93.827 ;
     RECT  88.8 88.787 89.112 93.829 ;
     RECT  66.72 92.339 70.344 94.021 ;
     RECT  78 93.251 84.648 94.021 ;
     RECT  86.1 92.915 87.096 94.021 ;
     RECT  78 94.021 87.096 94.067 ;
     RECT  71.616 92.677 72.912 94.307 ;
     RECT  23.712 93.781 24.744 94.549 ;
     RECT  75.072 93.541 75.912 94.835 ;
     RECT  15.9 2.151 16.212 94.837 ;
     RECT  75.072 94.835 75.612 95.027 ;
     RECT  15.9 94.837 16.728 95.125 ;
     RECT  78 94.067 86.412 95.125 ;
     RECT  65.856 94.021 70.344 95.219 ;
     RECT  69.504 95.219 70.344 95.509 ;
     RECT  91.5 93.827 91.812 95.557 ;
     RECT  76.848 95.125 76.872 95.653 ;
     RECT  77.904 95.125 86.412 95.653 ;
     RECT  30.864 91.093 32.808 95.701 ;
     RECT  33.984 91.333 37.812 95.701 ;
     RECT  72.288 94.307 72.912 95.749 ;
     RECT  65.856 95.219 68.28 95.843 ;
     RECT  91.5 95.557 92.664 95.843 ;
     RECT  15.552 95.125 16.728 95.989 ;
     RECT  69.504 95.509 71.112 96.275 ;
     RECT  30.864 95.701 37.812 96.371 ;
     RECT  47.808 88.405 51.312 96.371 ;
     RECT  65.856 95.843 67.992 96.371 ;
     RECT  76.848 95.653 86.412 96.371 ;
     RECT  77.904 96.371 86.412 96.419 ;
     RECT  15.552 95.989 17.448 96.469 ;
     RECT  30.864 96.371 35.784 96.563 ;
     RECT  93.84 93.493 95.064 96.661 ;
     RECT  15.408 96.469 17.448 96.757 ;
     RECT  29.4 93.539 29.712 96.757 ;
     RECT  64.5 91.811 64.812 96.757 ;
     RECT  65.856 96.371 67.8 96.757 ;
     RECT  47.808 96.371 48.744 96.805 ;
     RECT  10.5 2.151 10.812 96.853 ;
     RECT  88.8 93.829 89.592 96.901 ;
     RECT  47.424 96.805 48.744 96.995 ;
     RECT  72.096 95.749 72.912 96.995 ;
     RECT  93.84 96.661 95.16 97.043 ;
     RECT  29.232 96.757 29.712 97.045 ;
     RECT  30.864 96.563 35.352 97.045 ;
     RECT  29.232 97.045 35.352 97.523 ;
     RECT  49.824 96.371 51.312 97.523 ;
     RECT  77.904 96.419 79.176 97.571 ;
     RECT  49.92 97.523 49.992 97.715 ;
     RECT  47.424 96.995 48.612 97.861 ;
     RECT  45.6 76.403 45.912 97.909 ;
     RECT  47.136 97.861 48.612 97.909 ;
     RECT  80.256 96.419 86.412 97.955 ;
     RECT  88.8 96.901 90.072 98.051 ;
     RECT  49.968 97.715 49.992 98.099 ;
     RECT  69.504 96.275 70.212 98.099 ;
     RECT  15.072 96.757 17.448 98.101 ;
     RECT  29.232 97.523 35.112 98.195 ;
     RECT  61.2 90.659 62.112 98.197 ;
     RECT  15.072 98.101 17.592 98.341 ;
     RECT  18.6 60.035 18.912 98.341 ;
     RECT  29.232 98.195 33.48 98.341 ;
     RECT  26.7 2.151 27.012 98.389 ;
     RECT  28.8 98.341 33.48 98.389 ;
     RECT  53.7 88.403 54.012 98.485 ;
     RECT  39.696 90.659 40.512 98.581 ;
     RECT  53.7 98.485 54.12 98.627 ;
     RECT  42.432 91.333 43.212 98.675 ;
     RECT  93.84 97.043 94.512 98.675 ;
     RECT  85.488 97.955 86.412 98.723 ;
     RECT  61.104 98.197 62.952 98.917 ;
     RECT  64.5 96.757 67.8 98.917 ;
     RECT  56.304 92.965 56.712 98.965 ;
     RECT  56.256 98.965 56.712 99.109 ;
     RECT  57.984 92.245 58.008 99.109 ;
     RECT  56.256 99.109 58.008 99.157 ;
     RECT  69.9 98.099 70.212 99.157 ;
     RECT  69.264 99.157 70.212 99.445 ;
     RECT  59.1 93.253 59.736 99.541 ;
     RECT  78 97.571 79.176 99.541 ;
     RECT  88.8 98.051 89.592 99.587 ;
     RECT  56.016 99.157 58.008 99.589 ;
     RECT  58.992 99.541 59.736 99.589 ;
     RECT  68.928 99.445 70.212 99.685 ;
     RECT  56.016 99.589 59.736 99.733 ;
     RECT  68.928 99.685 71.256 99.733 ;
     RECT  23.712 94.549 25.368 99.779 ;
     RECT  80.256 97.955 84.36 99.875 ;
     RECT  15.072 98.341 18.912 99.973 ;
     RECT  68.88 99.733 71.256 100.021 ;
     RECT  72.6 96.995 72.912 100.021 ;
     RECT  55.824 99.733 59.736 100.069 ;
     RECT  15.072 99.973 19.128 100.261 ;
     RECT  55.824 100.069 59.832 100.261 ;
     RECT  23.712 99.779 25.032 100.355 ;
     RECT  83.4 99.875 84.36 100.355 ;
     RECT  10.32 96.853 10.812 100.501 ;
     RECT  21.3 2.151 21.612 100.501 ;
     RECT  51 97.523 51.312 100.501 ;
     RECT  9.792 100.501 10.812 100.549 ;
     RECT  51 100.501 51.432 100.645 ;
     RECT  53.7 98.627 54.012 100.645 ;
     RECT  75.3 95.027 75.612 100.645 ;
     RECT  53.7 100.645 54.792 100.693 ;
     RECT  55.776 100.261 59.832 100.693 ;
     RECT  61.104 98.917 67.8 100.789 ;
     RECT  68.88 100.021 72.912 100.789 ;
     RECT  75.3 100.645 76.152 100.789 ;
     RECT  74.64 100.789 76.152 100.837 ;
     RECT  53.7 100.693 59.832 100.885 ;
     RECT  15.072 100.261 19.512 100.931 ;
     RECT  23.904 100.355 25.032 100.931 ;
     RECT  9.696 100.549 10.812 101.077 ;
     RECT  50.688 100.645 51.432 101.077 ;
     RECT  53.136 100.885 59.832 101.077 ;
     RECT  78 99.541 79.272 101.077 ;
     RECT  34.8 98.195 35.112 101.173 ;
     RECT  7.8 2.151 8.112 101.317 ;
     RECT  74.64 100.837 76.392 101.317 ;
     RECT  7.68 101.317 8.112 101.365 ;
     RECT  9.408 101.077 10.812 101.365 ;
     RECT  34.8 101.173 35.736 101.365 ;
     RECT  80.256 99.875 82.392 101.413 ;
     RECT  83.4 100.355 83.712 101.413 ;
     RECT  80.256 101.413 83.712 101.507 ;
     RECT  26.7 98.389 33.48 101.701 ;
     RECT  34.8 101.365 35.88 101.701 ;
     RECT  50.688 101.077 59.832 101.701 ;
     RECT  61.104 100.789 72.912 101.701 ;
     RECT  26.7 101.701 36.072 101.845 ;
     RECT  37.5 96.371 37.812 101.845 ;
     RECT  77.76 101.077 79.272 101.893 ;
     RECT  74.64 101.317 76.536 101.941 ;
     RECT  26.7 101.845 37.812 101.989 ;
     RECT  45.6 97.909 48.612 101.989 ;
     RECT  50.256 101.701 72.912 101.989 ;
     RECT  15.9 100.931 19.512 102.083 ;
     RECT  17.568 102.083 19.512 102.179 ;
     RECT  77.712 101.893 79.272 102.469 ;
     RECT  74.64 101.941 76.584 102.517 ;
     RECT  77.664 102.469 79.272 102.517 ;
     RECT  74.64 102.517 79.272 102.565 ;
     RECT  80.256 101.507 81.768 102.565 ;
     RECT  45.6 101.989 72.912 102.659 ;
     RECT  23.904 100.931 24.504 102.707 ;
     RECT  45.6 102.659 63.24 102.755 ;
     RECT  82.992 101.507 83.712 102.947 ;
     RECT  20.928 100.501 21.612 103.045 ;
     RECT  39.6 98.581 40.512 103.045 ;
     RECT  23.904 102.707 24.312 103.235 ;
     RECT  26.7 101.989 38.184 103.235 ;
     RECT  60.384 102.755 63.24 103.235 ;
     RECT  74.64 102.565 81.96 103.235 ;
     RECT  2.4 2.151 2.712 103.419 ;
     RECT  5.1 2.151 5.412 103.419 ;
     RECT  13.2 2.151 13.512 103.419 ;
     RECT  15.9 102.083 16.212 103.419 ;
     RECT  24 103.235 24.312 103.419 ;
     RECT  26.7 103.235 37.812 103.419 ;
     RECT  42.9 98.675 43.212 103.419 ;
     RECT  45.6 102.755 59.412 103.419 ;
     RECT  64.5 102.659 72.912 103.419 ;
     RECT  75.3 103.235 81.96 103.419 ;
     RECT  83.4 102.947 83.712 103.419 ;
     RECT  86.1 98.723 86.412 103.419 ;
     RECT  88.8 99.587 89.112 103.419 ;
     RECT  91.5 95.843 91.812 103.419 ;
     RECT  94.2 98.675 94.512 103.419 ;
     RECT  96.9 93.443 97.212 103.419 ;
     RECT  99.6 91.091 99.912 103.419 ;
     RECT  2.592 103.419 2.712 103.433 ;
     RECT  5.292 103.419 5.412 103.433 ;
     RECT  7.68 101.365 10.812 103.433 ;
     RECT  13.392 103.419 13.512 103.433 ;
     RECT  16.092 103.419 16.212 103.433 ;
     RECT  24.192 103.419 24.312 103.433 ;
     RECT  26.892 103.419 36.552 103.433 ;
     RECT  37.692 103.419 37.812 103.433 ;
     RECT  39.312 103.045 40.512 103.433 ;
     RECT  43.092 103.419 43.212 103.433 ;
     RECT  45.792 103.419 59.412 103.433 ;
     RECT  64.692 103.419 72.912 103.433 ;
     RECT  75.492 103.419 81.96 103.433 ;
     RECT  83.592 103.419 83.712 103.433 ;
     RECT  86.292 103.419 86.412 103.433 ;
     RECT  88.992 103.419 89.112 103.433 ;
     RECT  91.692 103.419 91.812 103.433 ;
     RECT  94.392 103.419 94.512 103.433 ;
     RECT  97.092 103.419 97.212 103.433 ;
     RECT  99.792 103.419 99.912 103.433 ;
     RECT  75.648 103.433 81.96 104.291 ;
     RECT  7.68 103.433 10.152 104.915 ;
     RECT  39.312 103.433 40.056 104.915 ;
     RECT  61.104 103.235 63.24 104.915 ;
     RECT  75.648 104.291 80.28 104.963 ;
     RECT  18.432 102.179 19.512 105.011 ;
     RECT  46.848 103.433 58.824 105.011 ;
     RECT  75.696 104.963 75.768 105.011 ;
     RECT  27.216 103.433 29.256 105.107 ;
     RECT  46.848 105.011 48.12 105.107 ;
     RECT  49.344 105.011 58.824 105.107 ;
     RECT  8.496 104.915 10.152 105.731 ;
     RECT  39.6 104.915 39.864 105.731 ;
     RECT  46.848 105.107 47.88 105.731 ;
     RECT  30.48 103.433 36.552 105.744 ;
     RECT  49.392 105.107 58.824 105.744 ;
     RECT  65.712 103.433 71.88 105.744 ;
     RECT  8.496 105.731 8.52 105.779 ;
     RECT  9.504 105.731 10.152 105.779 ;
     RECT  19.008 105.011 19.512 105.779 ;
     RECT  20.928 103.045 22.056 105.779 ;
     RECT  27.792 105.107 29.256 105.779 ;
     RECT  39.84 105.731 39.864 105.779 ;
     RECT  46.848 105.731 47.64 105.779 ;
     RECT  49.392 105.744 49.512 105.779 ;
     RECT  61.104 104.915 62.952 105.779 ;
     RECT  65.712 105.744 68.76 105.779 ;
     RECT  75.696 105.011 75.72 105.779 ;
     RECT  76.896 104.963 80.28 105.779 ;
     RECT  81.36 104.291 81.96 105.779 ;
  END
END qfd_landh0_600_NE_104x106
END LIBRARY
